VERSION 5.8 ;
BUSBITCHARS "[]" ;
DIVIDERCHAR "/" ;
UNITS
    DATABASE MICRONS 1000 ;
END UNITS

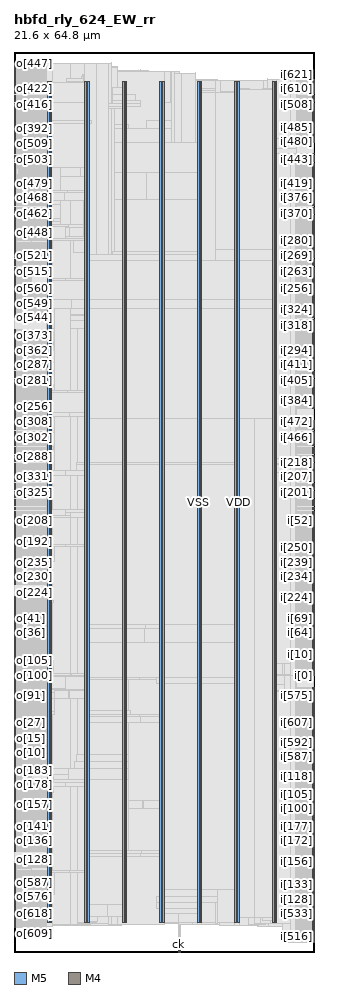
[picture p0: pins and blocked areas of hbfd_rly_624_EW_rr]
MACRO hbfd_rly_624_EW_rr
  FOREIGN hbfd_rly_624_EW_rr 0 0 ;
  CLASS BLOCK ;
  SIZE 21.6 BY 64.8 ;
  PIN ck
    DIRECTION INPUT ;
    USE SIGNAL ;
    PORT
      LAYER M5 ;
        RECT  11.856 0 11.88 0.084 ;
    END
  END ck
  PIN i[0]
    DIRECTION INPUT ;
    USE SIGNAL ;
    PORT
      LAYER M4 ;
        RECT  21.516 19.92 21.6 19.944 ;
    END
  END i[0]
  PIN i[100]
    DIRECTION INPUT ;
    USE SIGNAL ;
    PORT
      LAYER M4 ;
        RECT  21.516 10.32 21.6 10.344 ;
    END
  END i[100]
  PIN i[101]
    DIRECTION INPUT ;
    USE SIGNAL ;
    PORT
      LAYER M4 ;
        RECT  21.516 10.416 21.6 10.44 ;
    END
  END i[101]
  PIN i[102]
    DIRECTION INPUT ;
    USE SIGNAL ;
    PORT
      LAYER M4 ;
        RECT  21.516 10.512 21.6 10.536 ;
    END
  END i[102]
  PIN i[103]
    DIRECTION INPUT ;
    USE SIGNAL ;
    PORT
      LAYER M4 ;
        RECT  21.516 10.608 21.6 10.632 ;
    END
  END i[103]
  PIN i[104]
    DIRECTION INPUT ;
    USE SIGNAL ;
    PORT
      LAYER M4 ;
        RECT  21.516 10.704 21.6 10.728 ;
    END
  END i[104]
  PIN i[105]
    DIRECTION INPUT ;
    USE SIGNAL ;
    PORT
      LAYER M4 ;
        RECT  21.516 10.8 21.6 10.824 ;
    END
  END i[105]
  PIN i[106]
    DIRECTION INPUT ;
    USE SIGNAL ;
    PORT
      LAYER M4 ;
        RECT  21.516 10.896 21.6 10.92 ;
    END
  END i[106]
  PIN i[107]
    DIRECTION INPUT ;
    USE SIGNAL ;
    PORT
      LAYER M4 ;
        RECT  21.516 10.992 21.6 11.016 ;
    END
  END i[107]
  PIN i[108]
    DIRECTION INPUT ;
    USE SIGNAL ;
    PORT
      LAYER M4 ;
        RECT  21.516 11.088 21.6 11.112 ;
    END
  END i[108]
  PIN i[109]
    DIRECTION INPUT ;
    USE SIGNAL ;
    PORT
      LAYER M4 ;
        RECT  21.516 11.184 21.6 11.208 ;
    END
  END i[109]
  PIN i[10]
    DIRECTION INPUT ;
    USE SIGNAL ;
    PORT
      LAYER M4 ;
        RECT  21.516 20.88 21.6 20.904 ;
    END
  END i[10]
  PIN i[110]
    DIRECTION INPUT ;
    USE SIGNAL ;
    PORT
      LAYER M4 ;
        RECT  21.516 11.28 21.6 11.304 ;
    END
  END i[110]
  PIN i[111]
    DIRECTION INPUT ;
    USE SIGNAL ;
    PORT
      LAYER M4 ;
        RECT  21.516 11.376 21.6 11.4 ;
    END
  END i[111]
  PIN i[112]
    DIRECTION INPUT ;
    USE SIGNAL ;
    PORT
      LAYER M4 ;
        RECT  21.516 11.472 21.6 11.496 ;
    END
  END i[112]
  PIN i[113]
    DIRECTION INPUT ;
    USE SIGNAL ;
    PORT
      LAYER M4 ;
        RECT  21.516 11.568 21.6 11.592 ;
    END
  END i[113]
  PIN i[114]
    DIRECTION INPUT ;
    USE SIGNAL ;
    PORT
      LAYER M4 ;
        RECT  21.516 11.664 21.6 11.688 ;
    END
  END i[114]
  PIN i[115]
    DIRECTION INPUT ;
    USE SIGNAL ;
    PORT
      LAYER M4 ;
        RECT  21.516 11.76 21.6 11.784 ;
    END
  END i[115]
  PIN i[116]
    DIRECTION INPUT ;
    USE SIGNAL ;
    PORT
      LAYER M4 ;
        RECT  21.516 11.856 21.6 11.88 ;
    END
  END i[116]
  PIN i[117]
    DIRECTION INPUT ;
    USE SIGNAL ;
    PORT
      LAYER M4 ;
        RECT  21.516 11.952 21.6 11.976 ;
    END
  END i[117]
  PIN i[118]
    DIRECTION INPUT ;
    USE SIGNAL ;
    PORT
      LAYER M4 ;
        RECT  21.516 12.048 21.6 12.072 ;
    END
  END i[118]
  PIN i[119]
    DIRECTION INPUT ;
    USE SIGNAL ;
    PORT
      LAYER M4 ;
        RECT  21.516 12.144 21.6 12.168 ;
    END
  END i[119]
  PIN i[11]
    DIRECTION INPUT ;
    USE SIGNAL ;
    PORT
      LAYER M4 ;
        RECT  21.516 20.976 21.6 21 ;
    END
  END i[11]
  PIN i[120]
    DIRECTION INPUT ;
    USE SIGNAL ;
    PORT
      LAYER M4 ;
        RECT  21.516 12.24 21.6 12.264 ;
    END
  END i[120]
  PIN i[121]
    DIRECTION INPUT ;
    USE SIGNAL ;
    PORT
      LAYER M4 ;
        RECT  21.516 12.336 21.6 12.36 ;
    END
  END i[121]
  PIN i[122]
    DIRECTION INPUT ;
    USE SIGNAL ;
    PORT
      LAYER M4 ;
        RECT  21.516 12.432 21.6 12.456 ;
    END
  END i[122]
  PIN i[123]
    DIRECTION INPUT ;
    USE SIGNAL ;
    PORT
      LAYER M4 ;
        RECT  21.516 12.528 21.6 12.552 ;
    END
  END i[123]
  PIN i[124]
    DIRECTION INPUT ;
    USE SIGNAL ;
    PORT
      LAYER M4 ;
        RECT  21.516 12.624 21.6 12.648 ;
    END
  END i[124]
  PIN i[125]
    DIRECTION INPUT ;
    USE SIGNAL ;
    PORT
      LAYER M4 ;
        RECT  21.516 12.72 21.6 12.744 ;
    END
  END i[125]
  PIN i[126]
    DIRECTION INPUT ;
    USE SIGNAL ;
    PORT
      LAYER M4 ;
        RECT  21.516 12.816 21.6 12.84 ;
    END
  END i[126]
  PIN i[127]
    DIRECTION INPUT ;
    USE SIGNAL ;
    PORT
      LAYER M4 ;
        RECT  21.516 12.912 21.6 12.936 ;
    END
  END i[127]
  PIN i[128]
    DIRECTION INPUT ;
    USE SIGNAL ;
    PORT
      LAYER M4 ;
        RECT  21.516 3.792 21.6 3.816 ;
    END
  END i[128]
  PIN i[129]
    DIRECTION INPUT ;
    USE SIGNAL ;
    PORT
      LAYER M4 ;
        RECT  21.516 3.888 21.6 3.912 ;
    END
  END i[129]
  PIN i[12]
    DIRECTION INPUT ;
    USE SIGNAL ;
    PORT
      LAYER M4 ;
        RECT  21.516 21.072 21.6 21.096 ;
    END
  END i[12]
  PIN i[130]
    DIRECTION INPUT ;
    USE SIGNAL ;
    PORT
      LAYER M4 ;
        RECT  21.516 3.984 21.6 4.008 ;
    END
  END i[130]
  PIN i[131]
    DIRECTION INPUT ;
    USE SIGNAL ;
    PORT
      LAYER M4 ;
        RECT  21.516 4.08 21.6 4.104 ;
    END
  END i[131]
  PIN i[132]
    DIRECTION INPUT ;
    USE SIGNAL ;
    PORT
      LAYER M4 ;
        RECT  21.516 4.176 21.6 4.2 ;
    END
  END i[132]
  PIN i[133]
    DIRECTION INPUT ;
    USE SIGNAL ;
    PORT
      LAYER M4 ;
        RECT  21.516 4.272 21.6 4.296 ;
    END
  END i[133]
  PIN i[134]
    DIRECTION INPUT ;
    USE SIGNAL ;
    PORT
      LAYER M4 ;
        RECT  21.516 4.368 21.6 4.392 ;
    END
  END i[134]
  PIN i[135]
    DIRECTION INPUT ;
    USE SIGNAL ;
    PORT
      LAYER M4 ;
        RECT  21.516 4.464 21.6 4.488 ;
    END
  END i[135]
  PIN i[136]
    DIRECTION INPUT ;
    USE SIGNAL ;
    PORT
      LAYER M4 ;
        RECT  21.516 4.56 21.6 4.584 ;
    END
  END i[136]
  PIN i[137]
    DIRECTION INPUT ;
    USE SIGNAL ;
    PORT
      LAYER M4 ;
        RECT  21.516 4.656 21.6 4.68 ;
    END
  END i[137]
  PIN i[138]
    DIRECTION INPUT ;
    USE SIGNAL ;
    PORT
      LAYER M4 ;
        RECT  21.516 4.752 21.6 4.776 ;
    END
  END i[138]
  PIN i[139]
    DIRECTION INPUT ;
    USE SIGNAL ;
    PORT
      LAYER M4 ;
        RECT  21.516 4.848 21.6 4.872 ;
    END
  END i[139]
  PIN i[13]
    DIRECTION INPUT ;
    USE SIGNAL ;
    PORT
      LAYER M4 ;
        RECT  21.516 21.168 21.6 21.192 ;
    END
  END i[13]
  PIN i[140]
    DIRECTION INPUT ;
    USE SIGNAL ;
    PORT
      LAYER M4 ;
        RECT  21.516 4.944 21.6 4.968 ;
    END
  END i[140]
  PIN i[141]
    DIRECTION INPUT ;
    USE SIGNAL ;
    PORT
      LAYER M4 ;
        RECT  21.516 5.04 21.6 5.064 ;
    END
  END i[141]
  PIN i[142]
    DIRECTION INPUT ;
    USE SIGNAL ;
    PORT
      LAYER M4 ;
        RECT  21.516 5.136 21.6 5.16 ;
    END
  END i[142]
  PIN i[143]
    DIRECTION INPUT ;
    USE SIGNAL ;
    PORT
      LAYER M4 ;
        RECT  21.516 5.232 21.6 5.256 ;
    END
  END i[143]
  PIN i[144]
    DIRECTION INPUT ;
    USE SIGNAL ;
    PORT
      LAYER M4 ;
        RECT  21.516 5.328 21.6 5.352 ;
    END
  END i[144]
  PIN i[145]
    DIRECTION INPUT ;
    USE SIGNAL ;
    PORT
      LAYER M4 ;
        RECT  21.516 5.424 21.6 5.448 ;
    END
  END i[145]
  PIN i[146]
    DIRECTION INPUT ;
    USE SIGNAL ;
    PORT
      LAYER M4 ;
        RECT  21.516 5.52 21.6 5.544 ;
    END
  END i[146]
  PIN i[147]
    DIRECTION INPUT ;
    USE SIGNAL ;
    PORT
      LAYER M4 ;
        RECT  21.516 5.616 21.6 5.64 ;
    END
  END i[147]
  PIN i[148]
    DIRECTION INPUT ;
    USE SIGNAL ;
    PORT
      LAYER M4 ;
        RECT  21.516 5.712 21.6 5.736 ;
    END
  END i[148]
  PIN i[149]
    DIRECTION INPUT ;
    USE SIGNAL ;
    PORT
      LAYER M4 ;
        RECT  21.516 5.808 21.6 5.832 ;
    END
  END i[149]
  PIN i[14]
    DIRECTION INPUT ;
    USE SIGNAL ;
    PORT
      LAYER M4 ;
        RECT  21.516 21.264 21.6 21.288 ;
    END
  END i[14]
  PIN i[150]
    DIRECTION INPUT ;
    USE SIGNAL ;
    PORT
      LAYER M4 ;
        RECT  21.516 5.904 21.6 5.928 ;
    END
  END i[150]
  PIN i[151]
    DIRECTION INPUT ;
    USE SIGNAL ;
    PORT
      LAYER M4 ;
        RECT  21.516 6 21.6 6.024 ;
    END
  END i[151]
  PIN i[152]
    DIRECTION INPUT ;
    USE SIGNAL ;
    PORT
      LAYER M4 ;
        RECT  21.516 6.096 21.6 6.12 ;
    END
  END i[152]
  PIN i[153]
    DIRECTION INPUT ;
    USE SIGNAL ;
    PORT
      LAYER M4 ;
        RECT  21.516 6.192 21.6 6.216 ;
    END
  END i[153]
  PIN i[154]
    DIRECTION INPUT ;
    USE SIGNAL ;
    PORT
      LAYER M4 ;
        RECT  21.516 6.288 21.6 6.312 ;
    END
  END i[154]
  PIN i[155]
    DIRECTION INPUT ;
    USE SIGNAL ;
    PORT
      LAYER M4 ;
        RECT  21.516 6.384 21.6 6.408 ;
    END
  END i[155]
  PIN i[156]
    DIRECTION INPUT ;
    USE SIGNAL ;
    PORT
      LAYER M4 ;
        RECT  21.516 6.48 21.6 6.504 ;
    END
  END i[156]
  PIN i[157]
    DIRECTION INPUT ;
    USE SIGNAL ;
    PORT
      LAYER M4 ;
        RECT  21.516 6.576 21.6 6.6 ;
    END
  END i[157]
  PIN i[158]
    DIRECTION INPUT ;
    USE SIGNAL ;
    PORT
      LAYER M4 ;
        RECT  21.516 6.672 21.6 6.696 ;
    END
  END i[158]
  PIN i[159]
    DIRECTION INPUT ;
    USE SIGNAL ;
    PORT
      LAYER M4 ;
        RECT  21.516 6.768 21.6 6.792 ;
    END
  END i[159]
  PIN i[15]
    DIRECTION INPUT ;
    USE SIGNAL ;
    PORT
      LAYER M4 ;
        RECT  21.516 21.36 21.6 21.384 ;
    END
  END i[15]
  PIN i[160]
    DIRECTION INPUT ;
    USE SIGNAL ;
    PORT
      LAYER M4 ;
        RECT  21.516 6.864 21.6 6.888 ;
    END
  END i[160]
  PIN i[161]
    DIRECTION INPUT ;
    USE SIGNAL ;
    PORT
      LAYER M4 ;
        RECT  21.516 6.96 21.6 6.984 ;
    END
  END i[161]
  PIN i[162]
    DIRECTION INPUT ;
    USE SIGNAL ;
    PORT
      LAYER M4 ;
        RECT  21.516 7.056 21.6 7.08 ;
    END
  END i[162]
  PIN i[163]
    DIRECTION INPUT ;
    USE SIGNAL ;
    PORT
      LAYER M4 ;
        RECT  21.516 7.152 21.6 7.176 ;
    END
  END i[163]
  PIN i[164]
    DIRECTION INPUT ;
    USE SIGNAL ;
    PORT
      LAYER M4 ;
        RECT  21.516 7.248 21.6 7.272 ;
    END
  END i[164]
  PIN i[165]
    DIRECTION INPUT ;
    USE SIGNAL ;
    PORT
      LAYER M4 ;
        RECT  21.516 7.344 21.6 7.368 ;
    END
  END i[165]
  PIN i[166]
    DIRECTION INPUT ;
    USE SIGNAL ;
    PORT
      LAYER M4 ;
        RECT  21.516 7.44 21.6 7.464 ;
    END
  END i[166]
  PIN i[167]
    DIRECTION INPUT ;
    USE SIGNAL ;
    PORT
      LAYER M4 ;
        RECT  21.516 7.536 21.6 7.56 ;
    END
  END i[167]
  PIN i[168]
    DIRECTION INPUT ;
    USE SIGNAL ;
    PORT
      LAYER M4 ;
        RECT  21.516 7.632 21.6 7.656 ;
    END
  END i[168]
  PIN i[169]
    DIRECTION INPUT ;
    USE SIGNAL ;
    PORT
      LAYER M4 ;
        RECT  21.516 7.728 21.6 7.752 ;
    END
  END i[169]
  PIN i[16]
    DIRECTION INPUT ;
    USE SIGNAL ;
    PORT
      LAYER M4 ;
        RECT  21.516 21.456 21.6 21.48 ;
    END
  END i[16]
  PIN i[170]
    DIRECTION INPUT ;
    USE SIGNAL ;
    PORT
      LAYER M4 ;
        RECT  21.516 7.824 21.6 7.848 ;
    END
  END i[170]
  PIN i[171]
    DIRECTION INPUT ;
    USE SIGNAL ;
    PORT
      LAYER M4 ;
        RECT  21.516 7.92 21.6 7.944 ;
    END
  END i[171]
  PIN i[172]
    DIRECTION INPUT ;
    USE SIGNAL ;
    PORT
      LAYER M4 ;
        RECT  21.516 8.016 21.6 8.04 ;
    END
  END i[172]
  PIN i[173]
    DIRECTION INPUT ;
    USE SIGNAL ;
    PORT
      LAYER M4 ;
        RECT  21.516 8.112 21.6 8.136 ;
    END
  END i[173]
  PIN i[174]
    DIRECTION INPUT ;
    USE SIGNAL ;
    PORT
      LAYER M4 ;
        RECT  21.516 8.208 21.6 8.232 ;
    END
  END i[174]
  PIN i[175]
    DIRECTION INPUT ;
    USE SIGNAL ;
    PORT
      LAYER M4 ;
        RECT  21.516 8.304 21.6 8.328 ;
    END
  END i[175]
  PIN i[176]
    DIRECTION INPUT ;
    USE SIGNAL ;
    PORT
      LAYER M4 ;
        RECT  21.516 8.4 21.6 8.424 ;
    END
  END i[176]
  PIN i[177]
    DIRECTION INPUT ;
    USE SIGNAL ;
    PORT
      LAYER M4 ;
        RECT  21.516 8.496 21.6 8.52 ;
    END
  END i[177]
  PIN i[178]
    DIRECTION INPUT ;
    USE SIGNAL ;
    PORT
      LAYER M4 ;
        RECT  21.516 8.592 21.6 8.616 ;
    END
  END i[178]
  PIN i[179]
    DIRECTION INPUT ;
    USE SIGNAL ;
    PORT
      LAYER M4 ;
        RECT  21.516 8.688 21.6 8.712 ;
    END
  END i[179]
  PIN i[17]
    DIRECTION INPUT ;
    USE SIGNAL ;
    PORT
      LAYER M4 ;
        RECT  21.516 21.552 21.6 21.576 ;
    END
  END i[17]
  PIN i[180]
    DIRECTION INPUT ;
    USE SIGNAL ;
    PORT
      LAYER M4 ;
        RECT  21.516 8.784 21.6 8.808 ;
    END
  END i[180]
  PIN i[181]
    DIRECTION INPUT ;
    USE SIGNAL ;
    PORT
      LAYER M4 ;
        RECT  21.516 8.88 21.6 8.904 ;
    END
  END i[181]
  PIN i[182]
    DIRECTION INPUT ;
    USE SIGNAL ;
    PORT
      LAYER M4 ;
        RECT  21.516 8.976 21.6 9 ;
    END
  END i[182]
  PIN i[183]
    DIRECTION INPUT ;
    USE SIGNAL ;
    PORT
      LAYER M4 ;
        RECT  21.516 9.072 21.6 9.096 ;
    END
  END i[183]
  PIN i[184]
    DIRECTION INPUT ;
    USE SIGNAL ;
    PORT
      LAYER M4 ;
        RECT  21.516 9.168 21.6 9.192 ;
    END
  END i[184]
  PIN i[185]
    DIRECTION INPUT ;
    USE SIGNAL ;
    PORT
      LAYER M4 ;
        RECT  21.516 9.264 21.6 9.288 ;
    END
  END i[185]
  PIN i[186]
    DIRECTION INPUT ;
    USE SIGNAL ;
    PORT
      LAYER M4 ;
        RECT  21.516 9.36 21.6 9.384 ;
    END
  END i[186]
  PIN i[187]
    DIRECTION INPUT ;
    USE SIGNAL ;
    PORT
      LAYER M4 ;
        RECT  21.516 9.456 21.6 9.48 ;
    END
  END i[187]
  PIN i[188]
    DIRECTION INPUT ;
    USE SIGNAL ;
    PORT
      LAYER M4 ;
        RECT  21.516 9.552 21.6 9.576 ;
    END
  END i[188]
  PIN i[189]
    DIRECTION INPUT ;
    USE SIGNAL ;
    PORT
      LAYER M4 ;
        RECT  21.516 9.648 21.6 9.672 ;
    END
  END i[189]
  PIN i[18]
    DIRECTION INPUT ;
    USE SIGNAL ;
    PORT
      LAYER M4 ;
        RECT  21.516 21.648 21.6 21.672 ;
    END
  END i[18]
  PIN i[190]
    DIRECTION INPUT ;
    USE SIGNAL ;
    PORT
      LAYER M4 ;
        RECT  21.516 9.744 21.6 9.768 ;
    END
  END i[190]
  PIN i[191]
    DIRECTION INPUT ;
    USE SIGNAL ;
    PORT
      LAYER M4 ;
        RECT  21.516 9.84 21.6 9.864 ;
    END
  END i[191]
  PIN i[192]
    DIRECTION INPUT ;
    USE SIGNAL ;
    PORT
      LAYER M4 ;
        RECT  21.516 32.208 21.6 32.232 ;
    END
  END i[192]
  PIN i[193]
    DIRECTION INPUT ;
    USE SIGNAL ;
    PORT
      LAYER M4 ;
        RECT  21.516 32.304 21.6 32.328 ;
    END
  END i[193]
  PIN i[194]
    DIRECTION INPUT ;
    USE SIGNAL ;
    PORT
      LAYER M4 ;
        RECT  21.516 32.4 21.6 32.424 ;
    END
  END i[194]
  PIN i[195]
    DIRECTION INPUT ;
    USE SIGNAL ;
    PORT
      LAYER M4 ;
        RECT  21.516 32.496 21.6 32.52 ;
    END
  END i[195]
  PIN i[196]
    DIRECTION INPUT ;
    USE SIGNAL ;
    PORT
      LAYER M4 ;
        RECT  21.516 32.592 21.6 32.616 ;
    END
  END i[196]
  PIN i[197]
    DIRECTION INPUT ;
    USE SIGNAL ;
    PORT
      LAYER M4 ;
        RECT  21.516 32.688 21.6 32.712 ;
    END
  END i[197]
  PIN i[198]
    DIRECTION INPUT ;
    USE SIGNAL ;
    PORT
      LAYER M4 ;
        RECT  21.516 32.784 21.6 32.808 ;
    END
  END i[198]
  PIN i[199]
    DIRECTION INPUT ;
    USE SIGNAL ;
    PORT
      LAYER M4 ;
        RECT  21.516 32.88 21.6 32.904 ;
    END
  END i[199]
  PIN i[19]
    DIRECTION INPUT ;
    USE SIGNAL ;
    PORT
      LAYER M4 ;
        RECT  21.516 21.744 21.6 21.768 ;
    END
  END i[19]
  PIN i[1]
    DIRECTION INPUT ;
    USE SIGNAL ;
    PORT
      LAYER M4 ;
        RECT  21.516 20.016 21.6 20.04 ;
    END
  END i[1]
  PIN i[200]
    DIRECTION INPUT ;
    USE SIGNAL ;
    PORT
      LAYER M4 ;
        RECT  21.516 32.976 21.6 33 ;
    END
  END i[200]
  PIN i[201]
    DIRECTION INPUT ;
    USE SIGNAL ;
    PORT
      LAYER M4 ;
        RECT  21.516 33.072 21.6 33.096 ;
    END
  END i[201]
  PIN i[202]
    DIRECTION INPUT ;
    USE SIGNAL ;
    PORT
      LAYER M4 ;
        RECT  21.516 33.168 21.6 33.192 ;
    END
  END i[202]
  PIN i[203]
    DIRECTION INPUT ;
    USE SIGNAL ;
    PORT
      LAYER M4 ;
        RECT  21.516 33.264 21.6 33.288 ;
    END
  END i[203]
  PIN i[204]
    DIRECTION INPUT ;
    USE SIGNAL ;
    PORT
      LAYER M4 ;
        RECT  21.516 33.36 21.6 33.384 ;
    END
  END i[204]
  PIN i[205]
    DIRECTION INPUT ;
    USE SIGNAL ;
    PORT
      LAYER M4 ;
        RECT  21.516 33.456 21.6 33.48 ;
    END
  END i[205]
  PIN i[206]
    DIRECTION INPUT ;
    USE SIGNAL ;
    PORT
      LAYER M4 ;
        RECT  21.516 33.552 21.6 33.576 ;
    END
  END i[206]
  PIN i[207]
    DIRECTION INPUT ;
    USE SIGNAL ;
    PORT
      LAYER M4 ;
        RECT  21.516 33.648 21.6 33.672 ;
    END
  END i[207]
  PIN i[208]
    DIRECTION INPUT ;
    USE SIGNAL ;
    PORT
      LAYER M4 ;
        RECT  21.516 33.744 21.6 33.768 ;
    END
  END i[208]
  PIN i[209]
    DIRECTION INPUT ;
    USE SIGNAL ;
    PORT
      LAYER M4 ;
        RECT  21.516 33.84 21.6 33.864 ;
    END
  END i[209]
  PIN i[20]
    DIRECTION INPUT ;
    USE SIGNAL ;
    PORT
      LAYER M4 ;
        RECT  21.516 21.84 21.6 21.864 ;
    END
  END i[20]
  PIN i[210]
    DIRECTION INPUT ;
    USE SIGNAL ;
    PORT
      LAYER M4 ;
        RECT  21.516 33.936 21.6 33.96 ;
    END
  END i[210]
  PIN i[211]
    DIRECTION INPUT ;
    USE SIGNAL ;
    PORT
      LAYER M4 ;
        RECT  21.516 34.032 21.6 34.056 ;
    END
  END i[211]
  PIN i[212]
    DIRECTION INPUT ;
    USE SIGNAL ;
    PORT
      LAYER M4 ;
        RECT  21.516 34.128 21.6 34.152 ;
    END
  END i[212]
  PIN i[213]
    DIRECTION INPUT ;
    USE SIGNAL ;
    PORT
      LAYER M4 ;
        RECT  21.516 34.224 21.6 34.248 ;
    END
  END i[213]
  PIN i[214]
    DIRECTION INPUT ;
    USE SIGNAL ;
    PORT
      LAYER M4 ;
        RECT  21.516 34.32 21.6 34.344 ;
    END
  END i[214]
  PIN i[215]
    DIRECTION INPUT ;
    USE SIGNAL ;
    PORT
      LAYER M4 ;
        RECT  21.516 34.416 21.6 34.44 ;
    END
  END i[215]
  PIN i[216]
    DIRECTION INPUT ;
    USE SIGNAL ;
    PORT
      LAYER M4 ;
        RECT  21.516 34.512 21.6 34.536 ;
    END
  END i[216]
  PIN i[217]
    DIRECTION INPUT ;
    USE SIGNAL ;
    PORT
      LAYER M4 ;
        RECT  21.516 34.608 21.6 34.632 ;
    END
  END i[217]
  PIN i[218]
    DIRECTION INPUT ;
    USE SIGNAL ;
    PORT
      LAYER M4 ;
        RECT  21.516 34.704 21.6 34.728 ;
    END
  END i[218]
  PIN i[219]
    DIRECTION INPUT ;
    USE SIGNAL ;
    PORT
      LAYER M4 ;
        RECT  21.516 34.8 21.6 34.824 ;
    END
  END i[219]
  PIN i[21]
    DIRECTION INPUT ;
    USE SIGNAL ;
    PORT
      LAYER M4 ;
        RECT  21.516 21.936 21.6 21.96 ;
    END
  END i[21]
  PIN i[220]
    DIRECTION INPUT ;
    USE SIGNAL ;
    PORT
      LAYER M4 ;
        RECT  21.516 34.896 21.6 34.92 ;
    END
  END i[220]
  PIN i[221]
    DIRECTION INPUT ;
    USE SIGNAL ;
    PORT
      LAYER M4 ;
        RECT  21.516 34.992 21.6 35.016 ;
    END
  END i[221]
  PIN i[222]
    DIRECTION INPUT ;
    USE SIGNAL ;
    PORT
      LAYER M4 ;
        RECT  21.516 35.088 21.6 35.112 ;
    END
  END i[222]
  PIN i[223]
    DIRECTION INPUT ;
    USE SIGNAL ;
    PORT
      LAYER M4 ;
        RECT  21.516 35.184 21.6 35.208 ;
    END
  END i[223]
  PIN i[224]
    DIRECTION INPUT ;
    USE SIGNAL ;
    PORT
      LAYER M4 ;
        RECT  21.516 26.064 21.6 26.088 ;
    END
  END i[224]
  PIN i[225]
    DIRECTION INPUT ;
    USE SIGNAL ;
    PORT
      LAYER M4 ;
        RECT  21.516 26.16 21.6 26.184 ;
    END
  END i[225]
  PIN i[226]
    DIRECTION INPUT ;
    USE SIGNAL ;
    PORT
      LAYER M4 ;
        RECT  21.516 26.256 21.6 26.28 ;
    END
  END i[226]
  PIN i[227]
    DIRECTION INPUT ;
    USE SIGNAL ;
    PORT
      LAYER M4 ;
        RECT  21.516 26.352 21.6 26.376 ;
    END
  END i[227]
  PIN i[228]
    DIRECTION INPUT ;
    USE SIGNAL ;
    PORT
      LAYER M4 ;
        RECT  21.516 26.448 21.6 26.472 ;
    END
  END i[228]
  PIN i[229]
    DIRECTION INPUT ;
    USE SIGNAL ;
    PORT
      LAYER M4 ;
        RECT  21.516 26.544 21.6 26.568 ;
    END
  END i[229]
  PIN i[22]
    DIRECTION INPUT ;
    USE SIGNAL ;
    PORT
      LAYER M4 ;
        RECT  21.516 22.032 21.6 22.056 ;
    END
  END i[22]
  PIN i[230]
    DIRECTION INPUT ;
    USE SIGNAL ;
    PORT
      LAYER M4 ;
        RECT  21.516 26.64 21.6 26.664 ;
    END
  END i[230]
  PIN i[231]
    DIRECTION INPUT ;
    USE SIGNAL ;
    PORT
      LAYER M4 ;
        RECT  21.516 26.736 21.6 26.76 ;
    END
  END i[231]
  PIN i[232]
    DIRECTION INPUT ;
    USE SIGNAL ;
    PORT
      LAYER M4 ;
        RECT  21.516 26.832 21.6 26.856 ;
    END
  END i[232]
  PIN i[233]
    DIRECTION INPUT ;
    USE SIGNAL ;
    PORT
      LAYER M4 ;
        RECT  21.516 26.928 21.6 26.952 ;
    END
  END i[233]
  PIN i[234]
    DIRECTION INPUT ;
    USE SIGNAL ;
    PORT
      LAYER M4 ;
        RECT  21.516 27.024 21.6 27.048 ;
    END
  END i[234]
  PIN i[235]
    DIRECTION INPUT ;
    USE SIGNAL ;
    PORT
      LAYER M4 ;
        RECT  21.516 27.12 21.6 27.144 ;
    END
  END i[235]
  PIN i[236]
    DIRECTION INPUT ;
    USE SIGNAL ;
    PORT
      LAYER M4 ;
        RECT  21.516 27.216 21.6 27.24 ;
    END
  END i[236]
  PIN i[237]
    DIRECTION INPUT ;
    USE SIGNAL ;
    PORT
      LAYER M4 ;
        RECT  21.516 27.312 21.6 27.336 ;
    END
  END i[237]
  PIN i[238]
    DIRECTION INPUT ;
    USE SIGNAL ;
    PORT
      LAYER M4 ;
        RECT  21.516 27.408 21.6 27.432 ;
    END
  END i[238]
  PIN i[239]
    DIRECTION INPUT ;
    USE SIGNAL ;
    PORT
      LAYER M4 ;
        RECT  21.516 27.504 21.6 27.528 ;
    END
  END i[239]
  PIN i[23]
    DIRECTION INPUT ;
    USE SIGNAL ;
    PORT
      LAYER M4 ;
        RECT  21.516 22.128 21.6 22.152 ;
    END
  END i[23]
  PIN i[240]
    DIRECTION INPUT ;
    USE SIGNAL ;
    PORT
      LAYER M4 ;
        RECT  21.516 27.6 21.6 27.624 ;
    END
  END i[240]
  PIN i[241]
    DIRECTION INPUT ;
    USE SIGNAL ;
    PORT
      LAYER M4 ;
        RECT  21.516 27.696 21.6 27.72 ;
    END
  END i[241]
  PIN i[242]
    DIRECTION INPUT ;
    USE SIGNAL ;
    PORT
      LAYER M4 ;
        RECT  21.516 27.792 21.6 27.816 ;
    END
  END i[242]
  PIN i[243]
    DIRECTION INPUT ;
    USE SIGNAL ;
    PORT
      LAYER M4 ;
        RECT  21.516 27.888 21.6 27.912 ;
    END
  END i[243]
  PIN i[244]
    DIRECTION INPUT ;
    USE SIGNAL ;
    PORT
      LAYER M4 ;
        RECT  21.516 27.984 21.6 28.008 ;
    END
  END i[244]
  PIN i[245]
    DIRECTION INPUT ;
    USE SIGNAL ;
    PORT
      LAYER M4 ;
        RECT  21.516 28.08 21.6 28.104 ;
    END
  END i[245]
  PIN i[246]
    DIRECTION INPUT ;
    USE SIGNAL ;
    PORT
      LAYER M4 ;
        RECT  21.516 28.176 21.6 28.2 ;
    END
  END i[246]
  PIN i[247]
    DIRECTION INPUT ;
    USE SIGNAL ;
    PORT
      LAYER M4 ;
        RECT  21.516 28.272 21.6 28.296 ;
    END
  END i[247]
  PIN i[248]
    DIRECTION INPUT ;
    USE SIGNAL ;
    PORT
      LAYER M4 ;
        RECT  21.516 28.368 21.6 28.392 ;
    END
  END i[248]
  PIN i[249]
    DIRECTION INPUT ;
    USE SIGNAL ;
    PORT
      LAYER M4 ;
        RECT  21.516 28.464 21.6 28.488 ;
    END
  END i[249]
  PIN i[24]
    DIRECTION INPUT ;
    USE SIGNAL ;
    PORT
      LAYER M4 ;
        RECT  21.516 22.224 21.6 22.248 ;
    END
  END i[24]
  PIN i[250]
    DIRECTION INPUT ;
    USE SIGNAL ;
    PORT
      LAYER M4 ;
        RECT  21.516 28.56 21.6 28.584 ;
    END
  END i[250]
  PIN i[251]
    DIRECTION INPUT ;
    USE SIGNAL ;
    PORT
      LAYER M4 ;
        RECT  21.516 28.656 21.6 28.68 ;
    END
  END i[251]
  PIN i[252]
    DIRECTION INPUT ;
    USE SIGNAL ;
    PORT
      LAYER M4 ;
        RECT  21.516 28.752 21.6 28.776 ;
    END
  END i[252]
  PIN i[253]
    DIRECTION INPUT ;
    USE SIGNAL ;
    PORT
      LAYER M4 ;
        RECT  21.516 28.848 21.6 28.872 ;
    END
  END i[253]
  PIN i[254]
    DIRECTION INPUT ;
    USE SIGNAL ;
    PORT
      LAYER M4 ;
        RECT  21.516 28.944 21.6 28.968 ;
    END
  END i[254]
  PIN i[255]
    DIRECTION INPUT ;
    USE SIGNAL ;
    PORT
      LAYER M4 ;
        RECT  21.516 29.04 21.6 29.064 ;
    END
  END i[255]
  PIN i[256]
    DIRECTION INPUT ;
    USE SIGNAL ;
    PORT
      LAYER M4 ;
        RECT  21.516 48.336 21.6 48.36 ;
    END
  END i[256]
  PIN i[257]
    DIRECTION INPUT ;
    USE SIGNAL ;
    PORT
      LAYER M4 ;
        RECT  21.516 48.432 21.6 48.456 ;
    END
  END i[257]
  PIN i[258]
    DIRECTION INPUT ;
    USE SIGNAL ;
    PORT
      LAYER M4 ;
        RECT  21.516 48.528 21.6 48.552 ;
    END
  END i[258]
  PIN i[259]
    DIRECTION INPUT ;
    USE SIGNAL ;
    PORT
      LAYER M4 ;
        RECT  21.516 48.624 21.6 48.648 ;
    END
  END i[259]
  PIN i[25]
    DIRECTION INPUT ;
    USE SIGNAL ;
    PORT
      LAYER M4 ;
        RECT  21.516 22.32 21.6 22.344 ;
    END
  END i[25]
  PIN i[260]
    DIRECTION INPUT ;
    USE SIGNAL ;
    PORT
      LAYER M4 ;
        RECT  21.516 48.72 21.6 48.744 ;
    END
  END i[260]
  PIN i[261]
    DIRECTION INPUT ;
    USE SIGNAL ;
    PORT
      LAYER M4 ;
        RECT  21.516 48.816 21.6 48.84 ;
    END
  END i[261]
  PIN i[262]
    DIRECTION INPUT ;
    USE SIGNAL ;
    PORT
      LAYER M4 ;
        RECT  21.516 48.912 21.6 48.936 ;
    END
  END i[262]
  PIN i[263]
    DIRECTION INPUT ;
    USE SIGNAL ;
    PORT
      LAYER M4 ;
        RECT  21.516 49.008 21.6 49.032 ;
    END
  END i[263]
  PIN i[264]
    DIRECTION INPUT ;
    USE SIGNAL ;
    PORT
      LAYER M4 ;
        RECT  21.516 49.104 21.6 49.128 ;
    END
  END i[264]
  PIN i[265]
    DIRECTION INPUT ;
    USE SIGNAL ;
    PORT
      LAYER M4 ;
        RECT  21.516 49.2 21.6 49.224 ;
    END
  END i[265]
  PIN i[266]
    DIRECTION INPUT ;
    USE SIGNAL ;
    PORT
      LAYER M4 ;
        RECT  21.516 49.296 21.6 49.32 ;
    END
  END i[266]
  PIN i[267]
    DIRECTION INPUT ;
    USE SIGNAL ;
    PORT
      LAYER M4 ;
        RECT  21.516 49.392 21.6 49.416 ;
    END
  END i[267]
  PIN i[268]
    DIRECTION INPUT ;
    USE SIGNAL ;
    PORT
      LAYER M4 ;
        RECT  21.516 49.488 21.6 49.512 ;
    END
  END i[268]
  PIN i[269]
    DIRECTION INPUT ;
    USE SIGNAL ;
    PORT
      LAYER M4 ;
        RECT  21.516 49.584 21.6 49.608 ;
    END
  END i[269]
  PIN i[26]
    DIRECTION INPUT ;
    USE SIGNAL ;
    PORT
      LAYER M4 ;
        RECT  21.516 22.416 21.6 22.44 ;
    END
  END i[26]
  PIN i[270]
    DIRECTION INPUT ;
    USE SIGNAL ;
    PORT
      LAYER M4 ;
        RECT  21.516 49.68 21.6 49.704 ;
    END
  END i[270]
  PIN i[271]
    DIRECTION INPUT ;
    USE SIGNAL ;
    PORT
      LAYER M4 ;
        RECT  21.516 49.776 21.6 49.8 ;
    END
  END i[271]
  PIN i[272]
    DIRECTION INPUT ;
    USE SIGNAL ;
    PORT
      LAYER M4 ;
        RECT  21.516 49.872 21.6 49.896 ;
    END
  END i[272]
  PIN i[273]
    DIRECTION INPUT ;
    USE SIGNAL ;
    PORT
      LAYER M4 ;
        RECT  21.516 49.968 21.6 49.992 ;
    END
  END i[273]
  PIN i[274]
    DIRECTION INPUT ;
    USE SIGNAL ;
    PORT
      LAYER M4 ;
        RECT  21.516 50.064 21.6 50.088 ;
    END
  END i[274]
  PIN i[275]
    DIRECTION INPUT ;
    USE SIGNAL ;
    PORT
      LAYER M4 ;
        RECT  21.516 50.16 21.6 50.184 ;
    END
  END i[275]
  PIN i[276]
    DIRECTION INPUT ;
    USE SIGNAL ;
    PORT
      LAYER M4 ;
        RECT  21.516 50.256 21.6 50.28 ;
    END
  END i[276]
  PIN i[277]
    DIRECTION INPUT ;
    USE SIGNAL ;
    PORT
      LAYER M4 ;
        RECT  21.516 50.352 21.6 50.376 ;
    END
  END i[277]
  PIN i[278]
    DIRECTION INPUT ;
    USE SIGNAL ;
    PORT
      LAYER M4 ;
        RECT  21.516 50.448 21.6 50.472 ;
    END
  END i[278]
  PIN i[279]
    DIRECTION INPUT ;
    USE SIGNAL ;
    PORT
      LAYER M4 ;
        RECT  21.516 50.544 21.6 50.568 ;
    END
  END i[279]
  PIN i[27]
    DIRECTION INPUT ;
    USE SIGNAL ;
    PORT
      LAYER M4 ;
        RECT  21.516 22.512 21.6 22.536 ;
    END
  END i[27]
  PIN i[280]
    DIRECTION INPUT ;
    USE SIGNAL ;
    PORT
      LAYER M4 ;
        RECT  21.516 50.64 21.6 50.664 ;
    END
  END i[280]
  PIN i[281]
    DIRECTION INPUT ;
    USE SIGNAL ;
    PORT
      LAYER M4 ;
        RECT  21.516 50.736 21.6 50.76 ;
    END
  END i[281]
  PIN i[282]
    DIRECTION INPUT ;
    USE SIGNAL ;
    PORT
      LAYER M4 ;
        RECT  21.516 50.832 21.6 50.856 ;
    END
  END i[282]
  PIN i[283]
    DIRECTION INPUT ;
    USE SIGNAL ;
    PORT
      LAYER M4 ;
        RECT  21.516 50.928 21.6 50.952 ;
    END
  END i[283]
  PIN i[284]
    DIRECTION INPUT ;
    USE SIGNAL ;
    PORT
      LAYER M4 ;
        RECT  21.516 51.024 21.6 51.048 ;
    END
  END i[284]
  PIN i[285]
    DIRECTION INPUT ;
    USE SIGNAL ;
    PORT
      LAYER M4 ;
        RECT  21.516 51.12 21.6 51.144 ;
    END
  END i[285]
  PIN i[286]
    DIRECTION INPUT ;
    USE SIGNAL ;
    PORT
      LAYER M4 ;
        RECT  21.516 51.216 21.6 51.24 ;
    END
  END i[286]
  PIN i[287]
    DIRECTION INPUT ;
    USE SIGNAL ;
    PORT
      LAYER M4 ;
        RECT  21.516 51.312 21.6 51.336 ;
    END
  END i[287]
  PIN i[288]
    DIRECTION INPUT ;
    USE SIGNAL ;
    PORT
      LAYER M4 ;
        RECT  21.516 42.192 21.6 42.216 ;
    END
  END i[288]
  PIN i[289]
    DIRECTION INPUT ;
    USE SIGNAL ;
    PORT
      LAYER M4 ;
        RECT  21.516 42.288 21.6 42.312 ;
    END
  END i[289]
  PIN i[28]
    DIRECTION INPUT ;
    USE SIGNAL ;
    PORT
      LAYER M4 ;
        RECT  21.516 22.608 21.6 22.632 ;
    END
  END i[28]
  PIN i[290]
    DIRECTION INPUT ;
    USE SIGNAL ;
    PORT
      LAYER M4 ;
        RECT  21.516 42.384 21.6 42.408 ;
    END
  END i[290]
  PIN i[291]
    DIRECTION INPUT ;
    USE SIGNAL ;
    PORT
      LAYER M4 ;
        RECT  21.516 42.48 21.6 42.504 ;
    END
  END i[291]
  PIN i[292]
    DIRECTION INPUT ;
    USE SIGNAL ;
    PORT
      LAYER M4 ;
        RECT  21.516 42.576 21.6 42.6 ;
    END
  END i[292]
  PIN i[293]
    DIRECTION INPUT ;
    USE SIGNAL ;
    PORT
      LAYER M4 ;
        RECT  21.516 42.672 21.6 42.696 ;
    END
  END i[293]
  PIN i[294]
    DIRECTION INPUT ;
    USE SIGNAL ;
    PORT
      LAYER M4 ;
        RECT  21.516 42.768 21.6 42.792 ;
    END
  END i[294]
  PIN i[295]
    DIRECTION INPUT ;
    USE SIGNAL ;
    PORT
      LAYER M4 ;
        RECT  21.516 42.864 21.6 42.888 ;
    END
  END i[295]
  PIN i[296]
    DIRECTION INPUT ;
    USE SIGNAL ;
    PORT
      LAYER M4 ;
        RECT  21.516 42.96 21.6 42.984 ;
    END
  END i[296]
  PIN i[297]
    DIRECTION INPUT ;
    USE SIGNAL ;
    PORT
      LAYER M4 ;
        RECT  21.516 43.056 21.6 43.08 ;
    END
  END i[297]
  PIN i[298]
    DIRECTION INPUT ;
    USE SIGNAL ;
    PORT
      LAYER M4 ;
        RECT  21.516 43.152 21.6 43.176 ;
    END
  END i[298]
  PIN i[299]
    DIRECTION INPUT ;
    USE SIGNAL ;
    PORT
      LAYER M4 ;
        RECT  21.516 43.248 21.6 43.272 ;
    END
  END i[299]
  PIN i[29]
    DIRECTION INPUT ;
    USE SIGNAL ;
    PORT
      LAYER M4 ;
        RECT  21.516 22.704 21.6 22.728 ;
    END
  END i[29]
  PIN i[2]
    DIRECTION INPUT ;
    USE SIGNAL ;
    PORT
      LAYER M4 ;
        RECT  21.516 20.112 21.6 20.136 ;
    END
  END i[2]
  PIN i[300]
    DIRECTION INPUT ;
    USE SIGNAL ;
    PORT
      LAYER M4 ;
        RECT  21.516 43.344 21.6 43.368 ;
    END
  END i[300]
  PIN i[301]
    DIRECTION INPUT ;
    USE SIGNAL ;
    PORT
      LAYER M4 ;
        RECT  21.516 43.44 21.6 43.464 ;
    END
  END i[301]
  PIN i[302]
    DIRECTION INPUT ;
    USE SIGNAL ;
    PORT
      LAYER M4 ;
        RECT  21.516 43.536 21.6 43.56 ;
    END
  END i[302]
  PIN i[303]
    DIRECTION INPUT ;
    USE SIGNAL ;
    PORT
      LAYER M4 ;
        RECT  21.516 43.632 21.6 43.656 ;
    END
  END i[303]
  PIN i[304]
    DIRECTION INPUT ;
    USE SIGNAL ;
    PORT
      LAYER M4 ;
        RECT  21.516 43.728 21.6 43.752 ;
    END
  END i[304]
  PIN i[305]
    DIRECTION INPUT ;
    USE SIGNAL ;
    PORT
      LAYER M4 ;
        RECT  21.516 43.824 21.6 43.848 ;
    END
  END i[305]
  PIN i[306]
    DIRECTION INPUT ;
    USE SIGNAL ;
    PORT
      LAYER M4 ;
        RECT  21.516 43.92 21.6 43.944 ;
    END
  END i[306]
  PIN i[307]
    DIRECTION INPUT ;
    USE SIGNAL ;
    PORT
      LAYER M4 ;
        RECT  21.516 44.016 21.6 44.04 ;
    END
  END i[307]
  PIN i[308]
    DIRECTION INPUT ;
    USE SIGNAL ;
    PORT
      LAYER M4 ;
        RECT  21.516 44.112 21.6 44.136 ;
    END
  END i[308]
  PIN i[309]
    DIRECTION INPUT ;
    USE SIGNAL ;
    PORT
      LAYER M4 ;
        RECT  21.516 44.208 21.6 44.232 ;
    END
  END i[309]
  PIN i[30]
    DIRECTION INPUT ;
    USE SIGNAL ;
    PORT
      LAYER M4 ;
        RECT  21.516 22.8 21.6 22.824 ;
    END
  END i[30]
  PIN i[310]
    DIRECTION INPUT ;
    USE SIGNAL ;
    PORT
      LAYER M4 ;
        RECT  21.516 44.304 21.6 44.328 ;
    END
  END i[310]
  PIN i[311]
    DIRECTION INPUT ;
    USE SIGNAL ;
    PORT
      LAYER M4 ;
        RECT  21.516 44.4 21.6 44.424 ;
    END
  END i[311]
  PIN i[312]
    DIRECTION INPUT ;
    USE SIGNAL ;
    PORT
      LAYER M4 ;
        RECT  21.516 44.496 21.6 44.52 ;
    END
  END i[312]
  PIN i[313]
    DIRECTION INPUT ;
    USE SIGNAL ;
    PORT
      LAYER M4 ;
        RECT  21.516 44.592 21.6 44.616 ;
    END
  END i[313]
  PIN i[314]
    DIRECTION INPUT ;
    USE SIGNAL ;
    PORT
      LAYER M4 ;
        RECT  21.516 44.688 21.6 44.712 ;
    END
  END i[314]
  PIN i[315]
    DIRECTION INPUT ;
    USE SIGNAL ;
    PORT
      LAYER M4 ;
        RECT  21.516 44.784 21.6 44.808 ;
    END
  END i[315]
  PIN i[316]
    DIRECTION INPUT ;
    USE SIGNAL ;
    PORT
      LAYER M4 ;
        RECT  21.516 44.88 21.6 44.904 ;
    END
  END i[316]
  PIN i[317]
    DIRECTION INPUT ;
    USE SIGNAL ;
    PORT
      LAYER M4 ;
        RECT  21.516 44.976 21.6 45 ;
    END
  END i[317]
  PIN i[318]
    DIRECTION INPUT ;
    USE SIGNAL ;
    PORT
      LAYER M4 ;
        RECT  21.516 45.072 21.6 45.096 ;
    END
  END i[318]
  PIN i[319]
    DIRECTION INPUT ;
    USE SIGNAL ;
    PORT
      LAYER M4 ;
        RECT  21.516 45.168 21.6 45.192 ;
    END
  END i[319]
  PIN i[31]
    DIRECTION INPUT ;
    USE SIGNAL ;
    PORT
      LAYER M4 ;
        RECT  21.516 22.896 21.6 22.92 ;
    END
  END i[31]
  PIN i[320]
    DIRECTION INPUT ;
    USE SIGNAL ;
    PORT
      LAYER M4 ;
        RECT  21.516 45.264 21.6 45.288 ;
    END
  END i[320]
  PIN i[321]
    DIRECTION INPUT ;
    USE SIGNAL ;
    PORT
      LAYER M4 ;
        RECT  21.516 45.36 21.6 45.384 ;
    END
  END i[321]
  PIN i[322]
    DIRECTION INPUT ;
    USE SIGNAL ;
    PORT
      LAYER M4 ;
        RECT  21.516 45.456 21.6 45.48 ;
    END
  END i[322]
  PIN i[323]
    DIRECTION INPUT ;
    USE SIGNAL ;
    PORT
      LAYER M4 ;
        RECT  21.516 45.552 21.6 45.576 ;
    END
  END i[323]
  PIN i[324]
    DIRECTION INPUT ;
    USE SIGNAL ;
    PORT
      LAYER M4 ;
        RECT  21.516 45.648 21.6 45.672 ;
    END
  END i[324]
  PIN i[325]
    DIRECTION INPUT ;
    USE SIGNAL ;
    PORT
      LAYER M4 ;
        RECT  21.516 45.744 21.6 45.768 ;
    END
  END i[325]
  PIN i[326]
    DIRECTION INPUT ;
    USE SIGNAL ;
    PORT
      LAYER M4 ;
        RECT  21.516 45.84 21.6 45.864 ;
    END
  END i[326]
  PIN i[327]
    DIRECTION INPUT ;
    USE SIGNAL ;
    PORT
      LAYER M4 ;
        RECT  21.516 45.936 21.6 45.96 ;
    END
  END i[327]
  PIN i[328]
    DIRECTION INPUT ;
    USE SIGNAL ;
    PORT
      LAYER M4 ;
        RECT  21.516 46.032 21.6 46.056 ;
    END
  END i[328]
  PIN i[329]
    DIRECTION INPUT ;
    USE SIGNAL ;
    PORT
      LAYER M4 ;
        RECT  21.516 46.128 21.6 46.152 ;
    END
  END i[329]
  PIN i[32]
    DIRECTION INPUT ;
    USE SIGNAL ;
    PORT
      LAYER M4 ;
        RECT  21.516 29.136 21.6 29.16 ;
    END
  END i[32]
  PIN i[330]
    DIRECTION INPUT ;
    USE SIGNAL ;
    PORT
      LAYER M4 ;
        RECT  21.516 46.224 21.6 46.248 ;
    END
  END i[330]
  PIN i[331]
    DIRECTION INPUT ;
    USE SIGNAL ;
    PORT
      LAYER M4 ;
        RECT  21.516 46.32 21.6 46.344 ;
    END
  END i[331]
  PIN i[332]
    DIRECTION INPUT ;
    USE SIGNAL ;
    PORT
      LAYER M4 ;
        RECT  21.516 46.416 21.6 46.44 ;
    END
  END i[332]
  PIN i[333]
    DIRECTION INPUT ;
    USE SIGNAL ;
    PORT
      LAYER M4 ;
        RECT  21.516 46.512 21.6 46.536 ;
    END
  END i[333]
  PIN i[334]
    DIRECTION INPUT ;
    USE SIGNAL ;
    PORT
      LAYER M4 ;
        RECT  21.516 46.608 21.6 46.632 ;
    END
  END i[334]
  PIN i[335]
    DIRECTION INPUT ;
    USE SIGNAL ;
    PORT
      LAYER M4 ;
        RECT  21.516 46.704 21.6 46.728 ;
    END
  END i[335]
  PIN i[336]
    DIRECTION INPUT ;
    USE SIGNAL ;
    PORT
      LAYER M4 ;
        RECT  21.516 46.8 21.6 46.824 ;
    END
  END i[336]
  PIN i[337]
    DIRECTION INPUT ;
    USE SIGNAL ;
    PORT
      LAYER M4 ;
        RECT  21.516 46.896 21.6 46.92 ;
    END
  END i[337]
  PIN i[338]
    DIRECTION INPUT ;
    USE SIGNAL ;
    PORT
      LAYER M4 ;
        RECT  21.516 46.992 21.6 47.016 ;
    END
  END i[338]
  PIN i[339]
    DIRECTION INPUT ;
    USE SIGNAL ;
    PORT
      LAYER M4 ;
        RECT  21.516 47.088 21.6 47.112 ;
    END
  END i[339]
  PIN i[33]
    DIRECTION INPUT ;
    USE SIGNAL ;
    PORT
      LAYER M4 ;
        RECT  21.516 29.232 21.6 29.256 ;
    END
  END i[33]
  PIN i[340]
    DIRECTION INPUT ;
    USE SIGNAL ;
    PORT
      LAYER M4 ;
        RECT  21.516 47.184 21.6 47.208 ;
    END
  END i[340]
  PIN i[341]
    DIRECTION INPUT ;
    USE SIGNAL ;
    PORT
      LAYER M4 ;
        RECT  21.516 47.28 21.6 47.304 ;
    END
  END i[341]
  PIN i[342]
    DIRECTION INPUT ;
    USE SIGNAL ;
    PORT
      LAYER M4 ;
        RECT  21.516 47.376 21.6 47.4 ;
    END
  END i[342]
  PIN i[343]
    DIRECTION INPUT ;
    USE SIGNAL ;
    PORT
      LAYER M4 ;
        RECT  21.516 47.472 21.6 47.496 ;
    END
  END i[343]
  PIN i[344]
    DIRECTION INPUT ;
    USE SIGNAL ;
    PORT
      LAYER M4 ;
        RECT  21.516 47.568 21.6 47.592 ;
    END
  END i[344]
  PIN i[345]
    DIRECTION INPUT ;
    USE SIGNAL ;
    PORT
      LAYER M4 ;
        RECT  21.516 47.664 21.6 47.688 ;
    END
  END i[345]
  PIN i[346]
    DIRECTION INPUT ;
    USE SIGNAL ;
    PORT
      LAYER M4 ;
        RECT  21.516 47.76 21.6 47.784 ;
    END
  END i[346]
  PIN i[347]
    DIRECTION INPUT ;
    USE SIGNAL ;
    PORT
      LAYER M4 ;
        RECT  21.516 47.856 21.6 47.88 ;
    END
  END i[347]
  PIN i[348]
    DIRECTION INPUT ;
    USE SIGNAL ;
    PORT
      LAYER M4 ;
        RECT  21.516 47.952 21.6 47.976 ;
    END
  END i[348]
  PIN i[349]
    DIRECTION INPUT ;
    USE SIGNAL ;
    PORT
      LAYER M4 ;
        RECT  21.516 48.048 21.6 48.072 ;
    END
  END i[349]
  PIN i[34]
    DIRECTION INPUT ;
    USE SIGNAL ;
    PORT
      LAYER M4 ;
        RECT  21.516 29.328 21.6 29.352 ;
    END
  END i[34]
  PIN i[350]
    DIRECTION INPUT ;
    USE SIGNAL ;
    PORT
      LAYER M4 ;
        RECT  21.516 48.144 21.6 48.168 ;
    END
  END i[350]
  PIN i[351]
    DIRECTION INPUT ;
    USE SIGNAL ;
    PORT
      LAYER M4 ;
        RECT  21.516 48.24 21.6 48.264 ;
    END
  END i[351]
  PIN i[352]
    DIRECTION INPUT ;
    USE SIGNAL ;
    PORT
      LAYER M4 ;
        RECT  21.516 51.408 21.6 51.432 ;
    END
  END i[352]
  PIN i[353]
    DIRECTION INPUT ;
    USE SIGNAL ;
    PORT
      LAYER M4 ;
        RECT  21.516 51.504 21.6 51.528 ;
    END
  END i[353]
  PIN i[354]
    DIRECTION INPUT ;
    USE SIGNAL ;
    PORT
      LAYER M4 ;
        RECT  21.516 51.6 21.6 51.624 ;
    END
  END i[354]
  PIN i[355]
    DIRECTION INPUT ;
    USE SIGNAL ;
    PORT
      LAYER M4 ;
        RECT  21.516 51.696 21.6 51.72 ;
    END
  END i[355]
  PIN i[356]
    DIRECTION INPUT ;
    USE SIGNAL ;
    PORT
      LAYER M4 ;
        RECT  21.516 51.792 21.6 51.816 ;
    END
  END i[356]
  PIN i[357]
    DIRECTION INPUT ;
    USE SIGNAL ;
    PORT
      LAYER M4 ;
        RECT  21.516 51.888 21.6 51.912 ;
    END
  END i[357]
  PIN i[358]
    DIRECTION INPUT ;
    USE SIGNAL ;
    PORT
      LAYER M4 ;
        RECT  21.516 51.984 21.6 52.008 ;
    END
  END i[358]
  PIN i[359]
    DIRECTION INPUT ;
    USE SIGNAL ;
    PORT
      LAYER M4 ;
        RECT  21.516 52.08 21.6 52.104 ;
    END
  END i[359]
  PIN i[35]
    DIRECTION INPUT ;
    USE SIGNAL ;
    PORT
      LAYER M4 ;
        RECT  21.516 29.424 21.6 29.448 ;
    END
  END i[35]
  PIN i[360]
    DIRECTION INPUT ;
    USE SIGNAL ;
    PORT
      LAYER M4 ;
        RECT  21.516 52.176 21.6 52.2 ;
    END
  END i[360]
  PIN i[361]
    DIRECTION INPUT ;
    USE SIGNAL ;
    PORT
      LAYER M4 ;
        RECT  21.516 52.272 21.6 52.296 ;
    END
  END i[361]
  PIN i[362]
    DIRECTION INPUT ;
    USE SIGNAL ;
    PORT
      LAYER M4 ;
        RECT  21.516 52.368 21.6 52.392 ;
    END
  END i[362]
  PIN i[363]
    DIRECTION INPUT ;
    USE SIGNAL ;
    PORT
      LAYER M4 ;
        RECT  21.516 52.464 21.6 52.488 ;
    END
  END i[363]
  PIN i[364]
    DIRECTION INPUT ;
    USE SIGNAL ;
    PORT
      LAYER M4 ;
        RECT  21.516 52.56 21.6 52.584 ;
    END
  END i[364]
  PIN i[365]
    DIRECTION INPUT ;
    USE SIGNAL ;
    PORT
      LAYER M4 ;
        RECT  21.516 52.656 21.6 52.68 ;
    END
  END i[365]
  PIN i[366]
    DIRECTION INPUT ;
    USE SIGNAL ;
    PORT
      LAYER M4 ;
        RECT  21.516 52.752 21.6 52.776 ;
    END
  END i[366]
  PIN i[367]
    DIRECTION INPUT ;
    USE SIGNAL ;
    PORT
      LAYER M4 ;
        RECT  21.516 52.848 21.6 52.872 ;
    END
  END i[367]
  PIN i[368]
    DIRECTION INPUT ;
    USE SIGNAL ;
    PORT
      LAYER M4 ;
        RECT  21.516 52.944 21.6 52.968 ;
    END
  END i[368]
  PIN i[369]
    DIRECTION INPUT ;
    USE SIGNAL ;
    PORT
      LAYER M4 ;
        RECT  21.516 53.04 21.6 53.064 ;
    END
  END i[369]
  PIN i[36]
    DIRECTION INPUT ;
    USE SIGNAL ;
    PORT
      LAYER M4 ;
        RECT  21.516 29.52 21.6 29.544 ;
    END
  END i[36]
  PIN i[370]
    DIRECTION INPUT ;
    USE SIGNAL ;
    PORT
      LAYER M4 ;
        RECT  21.516 53.136 21.6 53.16 ;
    END
  END i[370]
  PIN i[371]
    DIRECTION INPUT ;
    USE SIGNAL ;
    PORT
      LAYER M4 ;
        RECT  21.516 53.232 21.6 53.256 ;
    END
  END i[371]
  PIN i[372]
    DIRECTION INPUT ;
    USE SIGNAL ;
    PORT
      LAYER M4 ;
        RECT  21.516 53.328 21.6 53.352 ;
    END
  END i[372]
  PIN i[373]
    DIRECTION INPUT ;
    USE SIGNAL ;
    PORT
      LAYER M4 ;
        RECT  21.516 53.424 21.6 53.448 ;
    END
  END i[373]
  PIN i[374]
    DIRECTION INPUT ;
    USE SIGNAL ;
    PORT
      LAYER M4 ;
        RECT  21.516 53.52 21.6 53.544 ;
    END
  END i[374]
  PIN i[375]
    DIRECTION INPUT ;
    USE SIGNAL ;
    PORT
      LAYER M4 ;
        RECT  21.516 53.616 21.6 53.64 ;
    END
  END i[375]
  PIN i[376]
    DIRECTION INPUT ;
    USE SIGNAL ;
    PORT
      LAYER M4 ;
        RECT  21.516 53.712 21.6 53.736 ;
    END
  END i[376]
  PIN i[377]
    DIRECTION INPUT ;
    USE SIGNAL ;
    PORT
      LAYER M4 ;
        RECT  21.516 53.808 21.6 53.832 ;
    END
  END i[377]
  PIN i[378]
    DIRECTION INPUT ;
    USE SIGNAL ;
    PORT
      LAYER M4 ;
        RECT  21.516 53.904 21.6 53.928 ;
    END
  END i[378]
  PIN i[379]
    DIRECTION INPUT ;
    USE SIGNAL ;
    PORT
      LAYER M4 ;
        RECT  21.516 54 21.6 54.024 ;
    END
  END i[379]
  PIN i[37]
    DIRECTION INPUT ;
    USE SIGNAL ;
    PORT
      LAYER M4 ;
        RECT  21.516 29.616 21.6 29.64 ;
    END
  END i[37]
  PIN i[380]
    DIRECTION INPUT ;
    USE SIGNAL ;
    PORT
      LAYER M4 ;
        RECT  21.516 54.096 21.6 54.12 ;
    END
  END i[380]
  PIN i[381]
    DIRECTION INPUT ;
    USE SIGNAL ;
    PORT
      LAYER M4 ;
        RECT  21.516 54.192 21.6 54.216 ;
    END
  END i[381]
  PIN i[382]
    DIRECTION INPUT ;
    USE SIGNAL ;
    PORT
      LAYER M4 ;
        RECT  21.516 54.288 21.6 54.312 ;
    END
  END i[382]
  PIN i[383]
    DIRECTION INPUT ;
    USE SIGNAL ;
    PORT
      LAYER M4 ;
        RECT  21.516 54.384 21.6 54.408 ;
    END
  END i[383]
  PIN i[384]
    DIRECTION INPUT ;
    USE SIGNAL ;
    PORT
      LAYER M4 ;
        RECT  21.516 39.12 21.6 39.144 ;
    END
  END i[384]
  PIN i[385]
    DIRECTION INPUT ;
    USE SIGNAL ;
    PORT
      LAYER M4 ;
        RECT  21.516 39.216 21.6 39.24 ;
    END
  END i[385]
  PIN i[386]
    DIRECTION INPUT ;
    USE SIGNAL ;
    PORT
      LAYER M4 ;
        RECT  21.516 39.312 21.6 39.336 ;
    END
  END i[386]
  PIN i[387]
    DIRECTION INPUT ;
    USE SIGNAL ;
    PORT
      LAYER M4 ;
        RECT  21.516 39.408 21.6 39.432 ;
    END
  END i[387]
  PIN i[388]
    DIRECTION INPUT ;
    USE SIGNAL ;
    PORT
      LAYER M4 ;
        RECT  21.516 39.504 21.6 39.528 ;
    END
  END i[388]
  PIN i[389]
    DIRECTION INPUT ;
    USE SIGNAL ;
    PORT
      LAYER M4 ;
        RECT  21.516 39.6 21.6 39.624 ;
    END
  END i[389]
  PIN i[38]
    DIRECTION INPUT ;
    USE SIGNAL ;
    PORT
      LAYER M4 ;
        RECT  21.516 29.712 21.6 29.736 ;
    END
  END i[38]
  PIN i[390]
    DIRECTION INPUT ;
    USE SIGNAL ;
    PORT
      LAYER M4 ;
        RECT  21.516 39.696 21.6 39.72 ;
    END
  END i[390]
  PIN i[391]
    DIRECTION INPUT ;
    USE SIGNAL ;
    PORT
      LAYER M4 ;
        RECT  21.516 39.792 21.6 39.816 ;
    END
  END i[391]
  PIN i[392]
    DIRECTION INPUT ;
    USE SIGNAL ;
    PORT
      LAYER M4 ;
        RECT  21.516 39.888 21.6 39.912 ;
    END
  END i[392]
  PIN i[393]
    DIRECTION INPUT ;
    USE SIGNAL ;
    PORT
      LAYER M4 ;
        RECT  21.516 39.984 21.6 40.008 ;
    END
  END i[393]
  PIN i[394]
    DIRECTION INPUT ;
    USE SIGNAL ;
    PORT
      LAYER M4 ;
        RECT  21.516 40.08 21.6 40.104 ;
    END
  END i[394]
  PIN i[395]
    DIRECTION INPUT ;
    USE SIGNAL ;
    PORT
      LAYER M4 ;
        RECT  21.516 40.176 21.6 40.2 ;
    END
  END i[395]
  PIN i[396]
    DIRECTION INPUT ;
    USE SIGNAL ;
    PORT
      LAYER M4 ;
        RECT  21.516 40.272 21.6 40.296 ;
    END
  END i[396]
  PIN i[397]
    DIRECTION INPUT ;
    USE SIGNAL ;
    PORT
      LAYER M4 ;
        RECT  21.516 40.368 21.6 40.392 ;
    END
  END i[397]
  PIN i[398]
    DIRECTION INPUT ;
    USE SIGNAL ;
    PORT
      LAYER M4 ;
        RECT  21.516 40.464 21.6 40.488 ;
    END
  END i[398]
  PIN i[399]
    DIRECTION INPUT ;
    USE SIGNAL ;
    PORT
      LAYER M4 ;
        RECT  21.516 40.56 21.6 40.584 ;
    END
  END i[399]
  PIN i[39]
    DIRECTION INPUT ;
    USE SIGNAL ;
    PORT
      LAYER M4 ;
        RECT  21.516 29.808 21.6 29.832 ;
    END
  END i[39]
  PIN i[3]
    DIRECTION INPUT ;
    USE SIGNAL ;
    PORT
      LAYER M4 ;
        RECT  21.516 20.208 21.6 20.232 ;
    END
  END i[3]
  PIN i[400]
    DIRECTION INPUT ;
    USE SIGNAL ;
    PORT
      LAYER M4 ;
        RECT  21.516 40.656 21.6 40.68 ;
    END
  END i[400]
  PIN i[401]
    DIRECTION INPUT ;
    USE SIGNAL ;
    PORT
      LAYER M4 ;
        RECT  21.516 40.752 21.6 40.776 ;
    END
  END i[401]
  PIN i[402]
    DIRECTION INPUT ;
    USE SIGNAL ;
    PORT
      LAYER M4 ;
        RECT  21.516 40.848 21.6 40.872 ;
    END
  END i[402]
  PIN i[403]
    DIRECTION INPUT ;
    USE SIGNAL ;
    PORT
      LAYER M4 ;
        RECT  21.516 40.944 21.6 40.968 ;
    END
  END i[403]
  PIN i[404]
    DIRECTION INPUT ;
    USE SIGNAL ;
    PORT
      LAYER M4 ;
        RECT  21.516 41.04 21.6 41.064 ;
    END
  END i[404]
  PIN i[405]
    DIRECTION INPUT ;
    USE SIGNAL ;
    PORT
      LAYER M4 ;
        RECT  21.516 41.136 21.6 41.16 ;
    END
  END i[405]
  PIN i[406]
    DIRECTION INPUT ;
    USE SIGNAL ;
    PORT
      LAYER M4 ;
        RECT  21.516 41.232 21.6 41.256 ;
    END
  END i[406]
  PIN i[407]
    DIRECTION INPUT ;
    USE SIGNAL ;
    PORT
      LAYER M4 ;
        RECT  21.516 41.328 21.6 41.352 ;
    END
  END i[407]
  PIN i[408]
    DIRECTION INPUT ;
    USE SIGNAL ;
    PORT
      LAYER M4 ;
        RECT  21.516 41.424 21.6 41.448 ;
    END
  END i[408]
  PIN i[409]
    DIRECTION INPUT ;
    USE SIGNAL ;
    PORT
      LAYER M4 ;
        RECT  21.516 41.52 21.6 41.544 ;
    END
  END i[409]
  PIN i[40]
    DIRECTION INPUT ;
    USE SIGNAL ;
    PORT
      LAYER M4 ;
        RECT  21.516 29.904 21.6 29.928 ;
    END
  END i[40]
  PIN i[410]
    DIRECTION INPUT ;
    USE SIGNAL ;
    PORT
      LAYER M4 ;
        RECT  21.516 41.616 21.6 41.64 ;
    END
  END i[410]
  PIN i[411]
    DIRECTION INPUT ;
    USE SIGNAL ;
    PORT
      LAYER M4 ;
        RECT  21.516 41.712 21.6 41.736 ;
    END
  END i[411]
  PIN i[412]
    DIRECTION INPUT ;
    USE SIGNAL ;
    PORT
      LAYER M4 ;
        RECT  21.516 41.808 21.6 41.832 ;
    END
  END i[412]
  PIN i[413]
    DIRECTION INPUT ;
    USE SIGNAL ;
    PORT
      LAYER M4 ;
        RECT  21.516 41.904 21.6 41.928 ;
    END
  END i[413]
  PIN i[414]
    DIRECTION INPUT ;
    USE SIGNAL ;
    PORT
      LAYER M4 ;
        RECT  21.516 42 21.6 42.024 ;
    END
  END i[414]
  PIN i[415]
    DIRECTION INPUT ;
    USE SIGNAL ;
    PORT
      LAYER M4 ;
        RECT  21.516 42.096 21.6 42.12 ;
    END
  END i[415]
  PIN i[416]
    DIRECTION INPUT ;
    USE SIGNAL ;
    PORT
      LAYER M4 ;
        RECT  21.516 54.48 21.6 54.504 ;
    END
  END i[416]
  PIN i[417]
    DIRECTION INPUT ;
    USE SIGNAL ;
    PORT
      LAYER M4 ;
        RECT  21.516 54.576 21.6 54.6 ;
    END
  END i[417]
  PIN i[418]
    DIRECTION INPUT ;
    USE SIGNAL ;
    PORT
      LAYER M4 ;
        RECT  21.516 54.672 21.6 54.696 ;
    END
  END i[418]
  PIN i[419]
    DIRECTION INPUT ;
    USE SIGNAL ;
    PORT
      LAYER M4 ;
        RECT  21.516 54.768 21.6 54.792 ;
    END
  END i[419]
  PIN i[41]
    DIRECTION INPUT ;
    USE SIGNAL ;
    PORT
      LAYER M4 ;
        RECT  21.516 30 21.6 30.024 ;
    END
  END i[41]
  PIN i[420]
    DIRECTION INPUT ;
    USE SIGNAL ;
    PORT
      LAYER M4 ;
        RECT  21.516 54.864 21.6 54.888 ;
    END
  END i[420]
  PIN i[421]
    DIRECTION INPUT ;
    USE SIGNAL ;
    PORT
      LAYER M4 ;
        RECT  21.516 54.96 21.6 54.984 ;
    END
  END i[421]
  PIN i[422]
    DIRECTION INPUT ;
    USE SIGNAL ;
    PORT
      LAYER M4 ;
        RECT  21.516 55.056 21.6 55.08 ;
    END
  END i[422]
  PIN i[423]
    DIRECTION INPUT ;
    USE SIGNAL ;
    PORT
      LAYER M4 ;
        RECT  21.516 55.152 21.6 55.176 ;
    END
  END i[423]
  PIN i[424]
    DIRECTION INPUT ;
    USE SIGNAL ;
    PORT
      LAYER M4 ;
        RECT  21.516 55.248 21.6 55.272 ;
    END
  END i[424]
  PIN i[425]
    DIRECTION INPUT ;
    USE SIGNAL ;
    PORT
      LAYER M4 ;
        RECT  21.516 55.344 21.6 55.368 ;
    END
  END i[425]
  PIN i[426]
    DIRECTION INPUT ;
    USE SIGNAL ;
    PORT
      LAYER M4 ;
        RECT  21.516 55.44 21.6 55.464 ;
    END
  END i[426]
  PIN i[427]
    DIRECTION INPUT ;
    USE SIGNAL ;
    PORT
      LAYER M4 ;
        RECT  21.516 55.536 21.6 55.56 ;
    END
  END i[427]
  PIN i[428]
    DIRECTION INPUT ;
    USE SIGNAL ;
    PORT
      LAYER M4 ;
        RECT  21.516 55.632 21.6 55.656 ;
    END
  END i[428]
  PIN i[429]
    DIRECTION INPUT ;
    USE SIGNAL ;
    PORT
      LAYER M4 ;
        RECT  21.516 55.728 21.6 55.752 ;
    END
  END i[429]
  PIN i[42]
    DIRECTION INPUT ;
    USE SIGNAL ;
    PORT
      LAYER M4 ;
        RECT  21.516 30.096 21.6 30.12 ;
    END
  END i[42]
  PIN i[430]
    DIRECTION INPUT ;
    USE SIGNAL ;
    PORT
      LAYER M4 ;
        RECT  21.516 55.824 21.6 55.848 ;
    END
  END i[430]
  PIN i[431]
    DIRECTION INPUT ;
    USE SIGNAL ;
    PORT
      LAYER M4 ;
        RECT  21.516 55.92 21.6 55.944 ;
    END
  END i[431]
  PIN i[432]
    DIRECTION INPUT ;
    USE SIGNAL ;
    PORT
      LAYER M4 ;
        RECT  21.516 56.016 21.6 56.04 ;
    END
  END i[432]
  PIN i[433]
    DIRECTION INPUT ;
    USE SIGNAL ;
    PORT
      LAYER M4 ;
        RECT  21.516 56.112 21.6 56.136 ;
    END
  END i[433]
  PIN i[434]
    DIRECTION INPUT ;
    USE SIGNAL ;
    PORT
      LAYER M4 ;
        RECT  21.516 56.208 21.6 56.232 ;
    END
  END i[434]
  PIN i[435]
    DIRECTION INPUT ;
    USE SIGNAL ;
    PORT
      LAYER M4 ;
        RECT  21.516 56.304 21.6 56.328 ;
    END
  END i[435]
  PIN i[436]
    DIRECTION INPUT ;
    USE SIGNAL ;
    PORT
      LAYER M4 ;
        RECT  21.516 56.4 21.6 56.424 ;
    END
  END i[436]
  PIN i[437]
    DIRECTION INPUT ;
    USE SIGNAL ;
    PORT
      LAYER M4 ;
        RECT  21.516 56.496 21.6 56.52 ;
    END
  END i[437]
  PIN i[438]
    DIRECTION INPUT ;
    USE SIGNAL ;
    PORT
      LAYER M4 ;
        RECT  21.516 56.592 21.6 56.616 ;
    END
  END i[438]
  PIN i[439]
    DIRECTION INPUT ;
    USE SIGNAL ;
    PORT
      LAYER M4 ;
        RECT  21.516 56.688 21.6 56.712 ;
    END
  END i[439]
  PIN i[43]
    DIRECTION INPUT ;
    USE SIGNAL ;
    PORT
      LAYER M4 ;
        RECT  21.516 30.192 21.6 30.216 ;
    END
  END i[43]
  PIN i[440]
    DIRECTION INPUT ;
    USE SIGNAL ;
    PORT
      LAYER M4 ;
        RECT  21.516 56.784 21.6 56.808 ;
    END
  END i[440]
  PIN i[441]
    DIRECTION INPUT ;
    USE SIGNAL ;
    PORT
      LAYER M4 ;
        RECT  21.516 56.88 21.6 56.904 ;
    END
  END i[441]
  PIN i[442]
    DIRECTION INPUT ;
    USE SIGNAL ;
    PORT
      LAYER M4 ;
        RECT  21.516 56.976 21.6 57 ;
    END
  END i[442]
  PIN i[443]
    DIRECTION INPUT ;
    USE SIGNAL ;
    PORT
      LAYER M4 ;
        RECT  21.516 57.072 21.6 57.096 ;
    END
  END i[443]
  PIN i[444]
    DIRECTION INPUT ;
    USE SIGNAL ;
    PORT
      LAYER M4 ;
        RECT  21.516 57.168 21.6 57.192 ;
    END
  END i[444]
  PIN i[445]
    DIRECTION INPUT ;
    USE SIGNAL ;
    PORT
      LAYER M4 ;
        RECT  21.516 57.264 21.6 57.288 ;
    END
  END i[445]
  PIN i[446]
    DIRECTION INPUT ;
    USE SIGNAL ;
    PORT
      LAYER M4 ;
        RECT  21.516 57.36 21.6 57.384 ;
    END
  END i[446]
  PIN i[447]
    DIRECTION INPUT ;
    USE SIGNAL ;
    PORT
      LAYER M4 ;
        RECT  21.516 57.456 21.6 57.48 ;
    END
  END i[447]
  PIN i[448]
    DIRECTION INPUT ;
    USE SIGNAL ;
    PORT
      LAYER M4 ;
        RECT  21.516 35.28 21.6 35.304 ;
    END
  END i[448]
  PIN i[449]
    DIRECTION INPUT ;
    USE SIGNAL ;
    PORT
      LAYER M4 ;
        RECT  21.516 35.376 21.6 35.4 ;
    END
  END i[449]
  PIN i[44]
    DIRECTION INPUT ;
    USE SIGNAL ;
    PORT
      LAYER M4 ;
        RECT  21.516 30.288 21.6 30.312 ;
    END
  END i[44]
  PIN i[450]
    DIRECTION INPUT ;
    USE SIGNAL ;
    PORT
      LAYER M4 ;
        RECT  21.516 35.472 21.6 35.496 ;
    END
  END i[450]
  PIN i[451]
    DIRECTION INPUT ;
    USE SIGNAL ;
    PORT
      LAYER M4 ;
        RECT  21.516 35.568 21.6 35.592 ;
    END
  END i[451]
  PIN i[452]
    DIRECTION INPUT ;
    USE SIGNAL ;
    PORT
      LAYER M4 ;
        RECT  21.516 35.664 21.6 35.688 ;
    END
  END i[452]
  PIN i[453]
    DIRECTION INPUT ;
    USE SIGNAL ;
    PORT
      LAYER M4 ;
        RECT  21.516 35.76 21.6 35.784 ;
    END
  END i[453]
  PIN i[454]
    DIRECTION INPUT ;
    USE SIGNAL ;
    PORT
      LAYER M4 ;
        RECT  21.516 35.856 21.6 35.88 ;
    END
  END i[454]
  PIN i[455]
    DIRECTION INPUT ;
    USE SIGNAL ;
    PORT
      LAYER M4 ;
        RECT  21.516 35.952 21.6 35.976 ;
    END
  END i[455]
  PIN i[456]
    DIRECTION INPUT ;
    USE SIGNAL ;
    PORT
      LAYER M4 ;
        RECT  21.516 36.048 21.6 36.072 ;
    END
  END i[456]
  PIN i[457]
    DIRECTION INPUT ;
    USE SIGNAL ;
    PORT
      LAYER M4 ;
        RECT  21.516 36.144 21.6 36.168 ;
    END
  END i[457]
  PIN i[458]
    DIRECTION INPUT ;
    USE SIGNAL ;
    PORT
      LAYER M4 ;
        RECT  21.516 36.24 21.6 36.264 ;
    END
  END i[458]
  PIN i[459]
    DIRECTION INPUT ;
    USE SIGNAL ;
    PORT
      LAYER M4 ;
        RECT  21.516 36.336 21.6 36.36 ;
    END
  END i[459]
  PIN i[45]
    DIRECTION INPUT ;
    USE SIGNAL ;
    PORT
      LAYER M4 ;
        RECT  21.516 30.384 21.6 30.408 ;
    END
  END i[45]
  PIN i[460]
    DIRECTION INPUT ;
    USE SIGNAL ;
    PORT
      LAYER M4 ;
        RECT  21.516 36.432 21.6 36.456 ;
    END
  END i[460]
  PIN i[461]
    DIRECTION INPUT ;
    USE SIGNAL ;
    PORT
      LAYER M4 ;
        RECT  21.516 36.528 21.6 36.552 ;
    END
  END i[461]
  PIN i[462]
    DIRECTION INPUT ;
    USE SIGNAL ;
    PORT
      LAYER M4 ;
        RECT  21.516 36.624 21.6 36.648 ;
    END
  END i[462]
  PIN i[463]
    DIRECTION INPUT ;
    USE SIGNAL ;
    PORT
      LAYER M4 ;
        RECT  21.516 36.72 21.6 36.744 ;
    END
  END i[463]
  PIN i[464]
    DIRECTION INPUT ;
    USE SIGNAL ;
    PORT
      LAYER M4 ;
        RECT  21.516 36.816 21.6 36.84 ;
    END
  END i[464]
  PIN i[465]
    DIRECTION INPUT ;
    USE SIGNAL ;
    PORT
      LAYER M4 ;
        RECT  21.516 36.912 21.6 36.936 ;
    END
  END i[465]
  PIN i[466]
    DIRECTION INPUT ;
    USE SIGNAL ;
    PORT
      LAYER M4 ;
        RECT  21.516 37.008 21.6 37.032 ;
    END
  END i[466]
  PIN i[467]
    DIRECTION INPUT ;
    USE SIGNAL ;
    PORT
      LAYER M4 ;
        RECT  21.516 37.104 21.6 37.128 ;
    END
  END i[467]
  PIN i[468]
    DIRECTION INPUT ;
    USE SIGNAL ;
    PORT
      LAYER M4 ;
        RECT  21.516 37.2 21.6 37.224 ;
    END
  END i[468]
  PIN i[469]
    DIRECTION INPUT ;
    USE SIGNAL ;
    PORT
      LAYER M4 ;
        RECT  21.516 37.296 21.6 37.32 ;
    END
  END i[469]
  PIN i[46]
    DIRECTION INPUT ;
    USE SIGNAL ;
    PORT
      LAYER M4 ;
        RECT  21.516 30.48 21.6 30.504 ;
    END
  END i[46]
  PIN i[470]
    DIRECTION INPUT ;
    USE SIGNAL ;
    PORT
      LAYER M4 ;
        RECT  21.516 37.392 21.6 37.416 ;
    END
  END i[470]
  PIN i[471]
    DIRECTION INPUT ;
    USE SIGNAL ;
    PORT
      LAYER M4 ;
        RECT  21.516 37.488 21.6 37.512 ;
    END
  END i[471]
  PIN i[472]
    DIRECTION INPUT ;
    USE SIGNAL ;
    PORT
      LAYER M4 ;
        RECT  21.516 37.584 21.6 37.608 ;
    END
  END i[472]
  PIN i[473]
    DIRECTION INPUT ;
    USE SIGNAL ;
    PORT
      LAYER M4 ;
        RECT  21.516 37.68 21.6 37.704 ;
    END
  END i[473]
  PIN i[474]
    DIRECTION INPUT ;
    USE SIGNAL ;
    PORT
      LAYER M4 ;
        RECT  21.516 37.776 21.6 37.8 ;
    END
  END i[474]
  PIN i[475]
    DIRECTION INPUT ;
    USE SIGNAL ;
    PORT
      LAYER M4 ;
        RECT  21.516 37.872 21.6 37.896 ;
    END
  END i[475]
  PIN i[476]
    DIRECTION INPUT ;
    USE SIGNAL ;
    PORT
      LAYER M4 ;
        RECT  21.516 37.968 21.6 37.992 ;
    END
  END i[476]
  PIN i[477]
    DIRECTION INPUT ;
    USE SIGNAL ;
    PORT
      LAYER M4 ;
        RECT  21.516 38.064 21.6 38.088 ;
    END
  END i[477]
  PIN i[478]
    DIRECTION INPUT ;
    USE SIGNAL ;
    PORT
      LAYER M4 ;
        RECT  21.516 38.16 21.6 38.184 ;
    END
  END i[478]
  PIN i[479]
    DIRECTION INPUT ;
    USE SIGNAL ;
    PORT
      LAYER M4 ;
        RECT  21.516 38.256 21.6 38.28 ;
    END
  END i[479]
  PIN i[47]
    DIRECTION INPUT ;
    USE SIGNAL ;
    PORT
      LAYER M4 ;
        RECT  21.516 30.576 21.6 30.6 ;
    END
  END i[47]
  PIN i[480]
    DIRECTION INPUT ;
    USE SIGNAL ;
    PORT
      LAYER M4 ;
        RECT  21.516 58.32 21.6 58.344 ;
    END
  END i[480]
  PIN i[481]
    DIRECTION INPUT ;
    USE SIGNAL ;
    PORT
      LAYER M4 ;
        RECT  21.516 58.416 21.6 58.44 ;
    END
  END i[481]
  PIN i[482]
    DIRECTION INPUT ;
    USE SIGNAL ;
    PORT
      LAYER M4 ;
        RECT  21.516 58.512 21.6 58.536 ;
    END
  END i[482]
  PIN i[483]
    DIRECTION INPUT ;
    USE SIGNAL ;
    PORT
      LAYER M4 ;
        RECT  21.516 58.608 21.6 58.632 ;
    END
  END i[483]
  PIN i[484]
    DIRECTION INPUT ;
    USE SIGNAL ;
    PORT
      LAYER M4 ;
        RECT  21.516 58.704 21.6 58.728 ;
    END
  END i[484]
  PIN i[485]
    DIRECTION INPUT ;
    USE SIGNAL ;
    PORT
      LAYER M4 ;
        RECT  21.516 58.8 21.6 58.824 ;
    END
  END i[485]
  PIN i[486]
    DIRECTION INPUT ;
    USE SIGNAL ;
    PORT
      LAYER M4 ;
        RECT  21.516 58.896 21.6 58.92 ;
    END
  END i[486]
  PIN i[487]
    DIRECTION INPUT ;
    USE SIGNAL ;
    PORT
      LAYER M4 ;
        RECT  21.516 58.992 21.6 59.016 ;
    END
  END i[487]
  PIN i[488]
    DIRECTION INPUT ;
    USE SIGNAL ;
    PORT
      LAYER M4 ;
        RECT  21.516 59.088 21.6 59.112 ;
    END
  END i[488]
  PIN i[489]
    DIRECTION INPUT ;
    USE SIGNAL ;
    PORT
      LAYER M4 ;
        RECT  21.516 59.184 21.6 59.208 ;
    END
  END i[489]
  PIN i[48]
    DIRECTION INPUT ;
    USE SIGNAL ;
    PORT
      LAYER M4 ;
        RECT  21.516 30.672 21.6 30.696 ;
    END
  END i[48]
  PIN i[490]
    DIRECTION INPUT ;
    USE SIGNAL ;
    PORT
      LAYER M4 ;
        RECT  21.516 59.28 21.6 59.304 ;
    END
  END i[490]
  PIN i[491]
    DIRECTION INPUT ;
    USE SIGNAL ;
    PORT
      LAYER M4 ;
        RECT  21.516 59.376 21.6 59.4 ;
    END
  END i[491]
  PIN i[492]
    DIRECTION INPUT ;
    USE SIGNAL ;
    PORT
      LAYER M4 ;
        RECT  21.516 59.472 21.6 59.496 ;
    END
  END i[492]
  PIN i[493]
    DIRECTION INPUT ;
    USE SIGNAL ;
    PORT
      LAYER M4 ;
        RECT  21.516 59.568 21.6 59.592 ;
    END
  END i[493]
  PIN i[494]
    DIRECTION INPUT ;
    USE SIGNAL ;
    PORT
      LAYER M4 ;
        RECT  21.516 59.664 21.6 59.688 ;
    END
  END i[494]
  PIN i[495]
    DIRECTION INPUT ;
    USE SIGNAL ;
    PORT
      LAYER M4 ;
        RECT  21.516 59.76 21.6 59.784 ;
    END
  END i[495]
  PIN i[496]
    DIRECTION INPUT ;
    USE SIGNAL ;
    PORT
      LAYER M4 ;
        RECT  21.516 59.856 21.6 59.88 ;
    END
  END i[496]
  PIN i[497]
    DIRECTION INPUT ;
    USE SIGNAL ;
    PORT
      LAYER M4 ;
        RECT  21.516 59.952 21.6 59.976 ;
    END
  END i[497]
  PIN i[498]
    DIRECTION INPUT ;
    USE SIGNAL ;
    PORT
      LAYER M4 ;
        RECT  21.516 60.048 21.6 60.072 ;
    END
  END i[498]
  PIN i[499]
    DIRECTION INPUT ;
    USE SIGNAL ;
    PORT
      LAYER M4 ;
        RECT  21.516 60.144 21.6 60.168 ;
    END
  END i[499]
  PIN i[49]
    DIRECTION INPUT ;
    USE SIGNAL ;
    PORT
      LAYER M4 ;
        RECT  21.516 30.768 21.6 30.792 ;
    END
  END i[49]
  PIN i[4]
    DIRECTION INPUT ;
    USE SIGNAL ;
    PORT
      LAYER M4 ;
        RECT  21.516 20.304 21.6 20.328 ;
    END
  END i[4]
  PIN i[500]
    DIRECTION INPUT ;
    USE SIGNAL ;
    PORT
      LAYER M4 ;
        RECT  21.516 60.24 21.6 60.264 ;
    END
  END i[500]
  PIN i[501]
    DIRECTION INPUT ;
    USE SIGNAL ;
    PORT
      LAYER M4 ;
        RECT  21.516 60.336 21.6 60.36 ;
    END
  END i[501]
  PIN i[502]
    DIRECTION INPUT ;
    USE SIGNAL ;
    PORT
      LAYER M4 ;
        RECT  21.516 60.432 21.6 60.456 ;
    END
  END i[502]
  PIN i[503]
    DIRECTION INPUT ;
    USE SIGNAL ;
    PORT
      LAYER M4 ;
        RECT  21.516 60.528 21.6 60.552 ;
    END
  END i[503]
  PIN i[504]
    DIRECTION INPUT ;
    USE SIGNAL ;
    PORT
      LAYER M4 ;
        RECT  21.516 60.624 21.6 60.648 ;
    END
  END i[504]
  PIN i[505]
    DIRECTION INPUT ;
    USE SIGNAL ;
    PORT
      LAYER M4 ;
        RECT  21.516 60.72 21.6 60.744 ;
    END
  END i[505]
  PIN i[506]
    DIRECTION INPUT ;
    USE SIGNAL ;
    PORT
      LAYER M4 ;
        RECT  21.516 60.816 21.6 60.84 ;
    END
  END i[506]
  PIN i[507]
    DIRECTION INPUT ;
    USE SIGNAL ;
    PORT
      LAYER M4 ;
        RECT  21.516 60.912 21.6 60.936 ;
    END
  END i[507]
  PIN i[508]
    DIRECTION INPUT ;
    USE SIGNAL ;
    PORT
      LAYER M4 ;
        RECT  21.516 61.008 21.6 61.032 ;
    END
  END i[508]
  PIN i[509]
    DIRECTION INPUT ;
    USE SIGNAL ;
    PORT
      LAYER M4 ;
        RECT  21.516 61.104 21.6 61.128 ;
    END
  END i[509]
  PIN i[50]
    DIRECTION INPUT ;
    USE SIGNAL ;
    PORT
      LAYER M4 ;
        RECT  21.516 30.864 21.6 30.888 ;
    END
  END i[50]
  PIN i[510]
    DIRECTION INPUT ;
    USE SIGNAL ;
    PORT
      LAYER M4 ;
        RECT  21.516 61.2 21.6 61.224 ;
    END
  END i[510]
  PIN i[511]
    DIRECTION INPUT ;
    USE SIGNAL ;
    PORT
      LAYER M4 ;
        RECT  21.516 61.296 21.6 61.32 ;
    END
  END i[511]
  PIN i[512]
    DIRECTION INPUT ;
    USE SIGNAL ;
    PORT
      LAYER M4 ;
        RECT  21.516 0.72 21.6 0.744 ;
    END
  END i[512]
  PIN i[513]
    DIRECTION INPUT ;
    USE SIGNAL ;
    PORT
      LAYER M4 ;
        RECT  21.516 0.816 21.6 0.84 ;
    END
  END i[513]
  PIN i[514]
    DIRECTION INPUT ;
    USE SIGNAL ;
    PORT
      LAYER M4 ;
        RECT  21.516 0.912 21.6 0.936 ;
    END
  END i[514]
  PIN i[515]
    DIRECTION INPUT ;
    USE SIGNAL ;
    PORT
      LAYER M4 ;
        RECT  21.516 1.008 21.6 1.032 ;
    END
  END i[515]
  PIN i[516]
    DIRECTION INPUT ;
    USE SIGNAL ;
    PORT
      LAYER M4 ;
        RECT  21.516 1.104 21.6 1.128 ;
    END
  END i[516]
  PIN i[517]
    DIRECTION INPUT ;
    USE SIGNAL ;
    PORT
      LAYER M4 ;
        RECT  21.516 1.2 21.6 1.224 ;
    END
  END i[517]
  PIN i[518]
    DIRECTION INPUT ;
    USE SIGNAL ;
    PORT
      LAYER M4 ;
        RECT  21.516 1.296 21.6 1.32 ;
    END
  END i[518]
  PIN i[519]
    DIRECTION INPUT ;
    USE SIGNAL ;
    PORT
      LAYER M4 ;
        RECT  21.516 1.392 21.6 1.416 ;
    END
  END i[519]
  PIN i[51]
    DIRECTION INPUT ;
    USE SIGNAL ;
    PORT
      LAYER M4 ;
        RECT  21.516 30.96 21.6 30.984 ;
    END
  END i[51]
  PIN i[520]
    DIRECTION INPUT ;
    USE SIGNAL ;
    PORT
      LAYER M4 ;
        RECT  21.516 1.488 21.6 1.512 ;
    END
  END i[520]
  PIN i[521]
    DIRECTION INPUT ;
    USE SIGNAL ;
    PORT
      LAYER M4 ;
        RECT  21.516 1.584 21.6 1.608 ;
    END
  END i[521]
  PIN i[522]
    DIRECTION INPUT ;
    USE SIGNAL ;
    PORT
      LAYER M4 ;
        RECT  21.516 1.68 21.6 1.704 ;
    END
  END i[522]
  PIN i[523]
    DIRECTION INPUT ;
    USE SIGNAL ;
    PORT
      LAYER M4 ;
        RECT  21.516 1.776 21.6 1.8 ;
    END
  END i[523]
  PIN i[524]
    DIRECTION INPUT ;
    USE SIGNAL ;
    PORT
      LAYER M4 ;
        RECT  21.516 1.872 21.6 1.896 ;
    END
  END i[524]
  PIN i[525]
    DIRECTION INPUT ;
    USE SIGNAL ;
    PORT
      LAYER M4 ;
        RECT  21.516 1.968 21.6 1.992 ;
    END
  END i[525]
  PIN i[526]
    DIRECTION INPUT ;
    USE SIGNAL ;
    PORT
      LAYER M4 ;
        RECT  21.516 2.064 21.6 2.088 ;
    END
  END i[526]
  PIN i[527]
    DIRECTION INPUT ;
    USE SIGNAL ;
    PORT
      LAYER M4 ;
        RECT  21.516 2.16 21.6 2.184 ;
    END
  END i[527]
  PIN i[528]
    DIRECTION INPUT ;
    USE SIGNAL ;
    PORT
      LAYER M4 ;
        RECT  21.516 2.256 21.6 2.28 ;
    END
  END i[528]
  PIN i[529]
    DIRECTION INPUT ;
    USE SIGNAL ;
    PORT
      LAYER M4 ;
        RECT  21.516 2.352 21.6 2.376 ;
    END
  END i[529]
  PIN i[52]
    DIRECTION INPUT ;
    USE SIGNAL ;
    PORT
      LAYER M4 ;
        RECT  21.516 31.056 21.6 31.08 ;
    END
  END i[52]
  PIN i[530]
    DIRECTION INPUT ;
    USE SIGNAL ;
    PORT
      LAYER M4 ;
        RECT  21.516 2.448 21.6 2.472 ;
    END
  END i[530]
  PIN i[531]
    DIRECTION INPUT ;
    USE SIGNAL ;
    PORT
      LAYER M4 ;
        RECT  21.516 2.544 21.6 2.568 ;
    END
  END i[531]
  PIN i[532]
    DIRECTION INPUT ;
    USE SIGNAL ;
    PORT
      LAYER M4 ;
        RECT  21.516 2.64 21.6 2.664 ;
    END
  END i[532]
  PIN i[533]
    DIRECTION INPUT ;
    USE SIGNAL ;
    PORT
      LAYER M4 ;
        RECT  21.516 2.736 21.6 2.76 ;
    END
  END i[533]
  PIN i[534]
    DIRECTION INPUT ;
    USE SIGNAL ;
    PORT
      LAYER M4 ;
        RECT  21.516 2.832 21.6 2.856 ;
    END
  END i[534]
  PIN i[535]
    DIRECTION INPUT ;
    USE SIGNAL ;
    PORT
      LAYER M4 ;
        RECT  21.516 2.928 21.6 2.952 ;
    END
  END i[535]
  PIN i[536]
    DIRECTION INPUT ;
    USE SIGNAL ;
    PORT
      LAYER M4 ;
        RECT  21.516 3.024 21.6 3.048 ;
    END
  END i[536]
  PIN i[537]
    DIRECTION INPUT ;
    USE SIGNAL ;
    PORT
      LAYER M4 ;
        RECT  21.516 3.12 21.6 3.144 ;
    END
  END i[537]
  PIN i[538]
    DIRECTION INPUT ;
    USE SIGNAL ;
    PORT
      LAYER M4 ;
        RECT  21.516 3.216 21.6 3.24 ;
    END
  END i[538]
  PIN i[539]
    DIRECTION INPUT ;
    USE SIGNAL ;
    PORT
      LAYER M4 ;
        RECT  21.516 3.312 21.6 3.336 ;
    END
  END i[539]
  PIN i[53]
    DIRECTION INPUT ;
    USE SIGNAL ;
    PORT
      LAYER M4 ;
        RECT  21.516 31.152 21.6 31.176 ;
    END
  END i[53]
  PIN i[540]
    DIRECTION INPUT ;
    USE SIGNAL ;
    PORT
      LAYER M4 ;
        RECT  21.516 3.408 21.6 3.432 ;
    END
  END i[540]
  PIN i[541]
    DIRECTION INPUT ;
    USE SIGNAL ;
    PORT
      LAYER M4 ;
        RECT  21.516 3.504 21.6 3.528 ;
    END
  END i[541]
  PIN i[542]
    DIRECTION INPUT ;
    USE SIGNAL ;
    PORT
      LAYER M4 ;
        RECT  21.516 3.6 21.6 3.624 ;
    END
  END i[542]
  PIN i[543]
    DIRECTION INPUT ;
    USE SIGNAL ;
    PORT
      LAYER M4 ;
        RECT  21.516 3.696 21.6 3.72 ;
    END
  END i[543]
  PIN i[544]
    DIRECTION INPUT ;
    USE SIGNAL ;
    PORT
      LAYER M4 ;
        RECT  21.516 16.08 21.6 16.104 ;
    END
  END i[544]
  PIN i[545]
    DIRECTION INPUT ;
    USE SIGNAL ;
    PORT
      LAYER M4 ;
        RECT  21.516 16.176 21.6 16.2 ;
    END
  END i[545]
  PIN i[546]
    DIRECTION INPUT ;
    USE SIGNAL ;
    PORT
      LAYER M4 ;
        RECT  21.516 16.272 21.6 16.296 ;
    END
  END i[546]
  PIN i[547]
    DIRECTION INPUT ;
    USE SIGNAL ;
    PORT
      LAYER M4 ;
        RECT  21.516 16.368 21.6 16.392 ;
    END
  END i[547]
  PIN i[548]
    DIRECTION INPUT ;
    USE SIGNAL ;
    PORT
      LAYER M4 ;
        RECT  21.516 16.464 21.6 16.488 ;
    END
  END i[548]
  PIN i[549]
    DIRECTION INPUT ;
    USE SIGNAL ;
    PORT
      LAYER M4 ;
        RECT  21.516 16.56 21.6 16.584 ;
    END
  END i[549]
  PIN i[54]
    DIRECTION INPUT ;
    USE SIGNAL ;
    PORT
      LAYER M4 ;
        RECT  21.516 31.248 21.6 31.272 ;
    END
  END i[54]
  PIN i[550]
    DIRECTION INPUT ;
    USE SIGNAL ;
    PORT
      LAYER M4 ;
        RECT  21.516 16.656 21.6 16.68 ;
    END
  END i[550]
  PIN i[551]
    DIRECTION INPUT ;
    USE SIGNAL ;
    PORT
      LAYER M4 ;
        RECT  21.516 16.752 21.6 16.776 ;
    END
  END i[551]
  PIN i[552]
    DIRECTION INPUT ;
    USE SIGNAL ;
    PORT
      LAYER M4 ;
        RECT  21.516 16.848 21.6 16.872 ;
    END
  END i[552]
  PIN i[553]
    DIRECTION INPUT ;
    USE SIGNAL ;
    PORT
      LAYER M4 ;
        RECT  21.516 16.944 21.6 16.968 ;
    END
  END i[553]
  PIN i[554]
    DIRECTION INPUT ;
    USE SIGNAL ;
    PORT
      LAYER M4 ;
        RECT  21.516 17.04 21.6 17.064 ;
    END
  END i[554]
  PIN i[555]
    DIRECTION INPUT ;
    USE SIGNAL ;
    PORT
      LAYER M4 ;
        RECT  21.516 17.136 21.6 17.16 ;
    END
  END i[555]
  PIN i[556]
    DIRECTION INPUT ;
    USE SIGNAL ;
    PORT
      LAYER M4 ;
        RECT  21.516 17.232 21.6 17.256 ;
    END
  END i[556]
  PIN i[557]
    DIRECTION INPUT ;
    USE SIGNAL ;
    PORT
      LAYER M4 ;
        RECT  21.516 17.328 21.6 17.352 ;
    END
  END i[557]
  PIN i[558]
    DIRECTION INPUT ;
    USE SIGNAL ;
    PORT
      LAYER M4 ;
        RECT  21.516 17.424 21.6 17.448 ;
    END
  END i[558]
  PIN i[559]
    DIRECTION INPUT ;
    USE SIGNAL ;
    PORT
      LAYER M4 ;
        RECT  21.516 17.52 21.6 17.544 ;
    END
  END i[559]
  PIN i[55]
    DIRECTION INPUT ;
    USE SIGNAL ;
    PORT
      LAYER M4 ;
        RECT  21.516 31.344 21.6 31.368 ;
    END
  END i[55]
  PIN i[560]
    DIRECTION INPUT ;
    USE SIGNAL ;
    PORT
      LAYER M4 ;
        RECT  21.516 17.616 21.6 17.64 ;
    END
  END i[560]
  PIN i[561]
    DIRECTION INPUT ;
    USE SIGNAL ;
    PORT
      LAYER M4 ;
        RECT  21.516 17.712 21.6 17.736 ;
    END
  END i[561]
  PIN i[562]
    DIRECTION INPUT ;
    USE SIGNAL ;
    PORT
      LAYER M4 ;
        RECT  21.516 17.808 21.6 17.832 ;
    END
  END i[562]
  PIN i[563]
    DIRECTION INPUT ;
    USE SIGNAL ;
    PORT
      LAYER M4 ;
        RECT  21.516 17.904 21.6 17.928 ;
    END
  END i[563]
  PIN i[564]
    DIRECTION INPUT ;
    USE SIGNAL ;
    PORT
      LAYER M4 ;
        RECT  21.516 18 21.6 18.024 ;
    END
  END i[564]
  PIN i[565]
    DIRECTION INPUT ;
    USE SIGNAL ;
    PORT
      LAYER M4 ;
        RECT  21.516 18.096 21.6 18.12 ;
    END
  END i[565]
  PIN i[566]
    DIRECTION INPUT ;
    USE SIGNAL ;
    PORT
      LAYER M4 ;
        RECT  21.516 18.192 21.6 18.216 ;
    END
  END i[566]
  PIN i[567]
    DIRECTION INPUT ;
    USE SIGNAL ;
    PORT
      LAYER M4 ;
        RECT  21.516 18.288 21.6 18.312 ;
    END
  END i[567]
  PIN i[568]
    DIRECTION INPUT ;
    USE SIGNAL ;
    PORT
      LAYER M4 ;
        RECT  21.516 18.384 21.6 18.408 ;
    END
  END i[568]
  PIN i[569]
    DIRECTION INPUT ;
    USE SIGNAL ;
    PORT
      LAYER M4 ;
        RECT  21.516 18.48 21.6 18.504 ;
    END
  END i[569]
  PIN i[56]
    DIRECTION INPUT ;
    USE SIGNAL ;
    PORT
      LAYER M4 ;
        RECT  21.516 31.44 21.6 31.464 ;
    END
  END i[56]
  PIN i[570]
    DIRECTION INPUT ;
    USE SIGNAL ;
    PORT
      LAYER M4 ;
        RECT  21.516 18.576 21.6 18.6 ;
    END
  END i[570]
  PIN i[571]
    DIRECTION INPUT ;
    USE SIGNAL ;
    PORT
      LAYER M4 ;
        RECT  21.516 18.672 21.6 18.696 ;
    END
  END i[571]
  PIN i[572]
    DIRECTION INPUT ;
    USE SIGNAL ;
    PORT
      LAYER M4 ;
        RECT  21.516 18.768 21.6 18.792 ;
    END
  END i[572]
  PIN i[573]
    DIRECTION INPUT ;
    USE SIGNAL ;
    PORT
      LAYER M4 ;
        RECT  21.516 18.864 21.6 18.888 ;
    END
  END i[573]
  PIN i[574]
    DIRECTION INPUT ;
    USE SIGNAL ;
    PORT
      LAYER M4 ;
        RECT  21.516 18.96 21.6 18.984 ;
    END
  END i[574]
  PIN i[575]
    DIRECTION INPUT ;
    USE SIGNAL ;
    PORT
      LAYER M4 ;
        RECT  21.516 19.056 21.6 19.08 ;
    END
  END i[575]
  PIN i[576]
    DIRECTION INPUT ;
    USE SIGNAL ;
    PORT
      LAYER M4 ;
        RECT  21.516 13.008 21.6 13.032 ;
    END
  END i[576]
  PIN i[577]
    DIRECTION INPUT ;
    USE SIGNAL ;
    PORT
      LAYER M4 ;
        RECT  21.516 13.104 21.6 13.128 ;
    END
  END i[577]
  PIN i[578]
    DIRECTION INPUT ;
    USE SIGNAL ;
    PORT
      LAYER M4 ;
        RECT  21.516 13.2 21.6 13.224 ;
    END
  END i[578]
  PIN i[579]
    DIRECTION INPUT ;
    USE SIGNAL ;
    PORT
      LAYER M4 ;
        RECT  21.516 13.296 21.6 13.32 ;
    END
  END i[579]
  PIN i[57]
    DIRECTION INPUT ;
    USE SIGNAL ;
    PORT
      LAYER M4 ;
        RECT  21.516 31.536 21.6 31.56 ;
    END
  END i[57]
  PIN i[580]
    DIRECTION INPUT ;
    USE SIGNAL ;
    PORT
      LAYER M4 ;
        RECT  21.516 13.392 21.6 13.416 ;
    END
  END i[580]
  PIN i[581]
    DIRECTION INPUT ;
    USE SIGNAL ;
    PORT
      LAYER M4 ;
        RECT  21.516 13.488 21.6 13.512 ;
    END
  END i[581]
  PIN i[582]
    DIRECTION INPUT ;
    USE SIGNAL ;
    PORT
      LAYER M4 ;
        RECT  21.516 13.584 21.6 13.608 ;
    END
  END i[582]
  PIN i[583]
    DIRECTION INPUT ;
    USE SIGNAL ;
    PORT
      LAYER M4 ;
        RECT  21.516 13.68 21.6 13.704 ;
    END
  END i[583]
  PIN i[584]
    DIRECTION INPUT ;
    USE SIGNAL ;
    PORT
      LAYER M4 ;
        RECT  21.516 13.776 21.6 13.8 ;
    END
  END i[584]
  PIN i[585]
    DIRECTION INPUT ;
    USE SIGNAL ;
    PORT
      LAYER M4 ;
        RECT  21.516 13.872 21.6 13.896 ;
    END
  END i[585]
  PIN i[586]
    DIRECTION INPUT ;
    USE SIGNAL ;
    PORT
      LAYER M4 ;
        RECT  21.516 13.968 21.6 13.992 ;
    END
  END i[586]
  PIN i[587]
    DIRECTION INPUT ;
    USE SIGNAL ;
    PORT
      LAYER M4 ;
        RECT  21.516 14.064 21.6 14.088 ;
    END
  END i[587]
  PIN i[588]
    DIRECTION INPUT ;
    USE SIGNAL ;
    PORT
      LAYER M4 ;
        RECT  21.516 14.16 21.6 14.184 ;
    END
  END i[588]
  PIN i[589]
    DIRECTION INPUT ;
    USE SIGNAL ;
    PORT
      LAYER M4 ;
        RECT  21.516 14.256 21.6 14.28 ;
    END
  END i[589]
  PIN i[58]
    DIRECTION INPUT ;
    USE SIGNAL ;
    PORT
      LAYER M4 ;
        RECT  21.516 31.632 21.6 31.656 ;
    END
  END i[58]
  PIN i[590]
    DIRECTION INPUT ;
    USE SIGNAL ;
    PORT
      LAYER M4 ;
        RECT  21.516 14.352 21.6 14.376 ;
    END
  END i[590]
  PIN i[591]
    DIRECTION INPUT ;
    USE SIGNAL ;
    PORT
      LAYER M4 ;
        RECT  21.516 14.448 21.6 14.472 ;
    END
  END i[591]
  PIN i[592]
    DIRECTION INPUT ;
    USE SIGNAL ;
    PORT
      LAYER M4 ;
        RECT  21.516 14.544 21.6 14.568 ;
    END
  END i[592]
  PIN i[593]
    DIRECTION INPUT ;
    USE SIGNAL ;
    PORT
      LAYER M4 ;
        RECT  21.516 14.64 21.6 14.664 ;
    END
  END i[593]
  PIN i[594]
    DIRECTION INPUT ;
    USE SIGNAL ;
    PORT
      LAYER M4 ;
        RECT  21.516 14.736 21.6 14.76 ;
    END
  END i[594]
  PIN i[595]
    DIRECTION INPUT ;
    USE SIGNAL ;
    PORT
      LAYER M4 ;
        RECT  21.516 14.832 21.6 14.856 ;
    END
  END i[595]
  PIN i[596]
    DIRECTION INPUT ;
    USE SIGNAL ;
    PORT
      LAYER M4 ;
        RECT  21.516 14.928 21.6 14.952 ;
    END
  END i[596]
  PIN i[597]
    DIRECTION INPUT ;
    USE SIGNAL ;
    PORT
      LAYER M4 ;
        RECT  21.516 15.024 21.6 15.048 ;
    END
  END i[597]
  PIN i[598]
    DIRECTION INPUT ;
    USE SIGNAL ;
    PORT
      LAYER M4 ;
        RECT  21.516 15.12 21.6 15.144 ;
    END
  END i[598]
  PIN i[599]
    DIRECTION INPUT ;
    USE SIGNAL ;
    PORT
      LAYER M4 ;
        RECT  21.516 15.216 21.6 15.24 ;
    END
  END i[599]
  PIN i[59]
    DIRECTION INPUT ;
    USE SIGNAL ;
    PORT
      LAYER M4 ;
        RECT  21.516 31.728 21.6 31.752 ;
    END
  END i[59]
  PIN i[5]
    DIRECTION INPUT ;
    USE SIGNAL ;
    PORT
      LAYER M4 ;
        RECT  21.516 20.4 21.6 20.424 ;
    END
  END i[5]
  PIN i[600]
    DIRECTION INPUT ;
    USE SIGNAL ;
    PORT
      LAYER M4 ;
        RECT  21.516 15.312 21.6 15.336 ;
    END
  END i[600]
  PIN i[601]
    DIRECTION INPUT ;
    USE SIGNAL ;
    PORT
      LAYER M4 ;
        RECT  21.516 15.408 21.6 15.432 ;
    END
  END i[601]
  PIN i[602]
    DIRECTION INPUT ;
    USE SIGNAL ;
    PORT
      LAYER M4 ;
        RECT  21.516 15.504 21.6 15.528 ;
    END
  END i[602]
  PIN i[603]
    DIRECTION INPUT ;
    USE SIGNAL ;
    PORT
      LAYER M4 ;
        RECT  21.516 15.6 21.6 15.624 ;
    END
  END i[603]
  PIN i[604]
    DIRECTION INPUT ;
    USE SIGNAL ;
    PORT
      LAYER M4 ;
        RECT  21.516 15.696 21.6 15.72 ;
    END
  END i[604]
  PIN i[605]
    DIRECTION INPUT ;
    USE SIGNAL ;
    PORT
      LAYER M4 ;
        RECT  21.516 15.792 21.6 15.816 ;
    END
  END i[605]
  PIN i[606]
    DIRECTION INPUT ;
    USE SIGNAL ;
    PORT
      LAYER M4 ;
        RECT  21.516 15.888 21.6 15.912 ;
    END
  END i[606]
  PIN i[607]
    DIRECTION INPUT ;
    USE SIGNAL ;
    PORT
      LAYER M4 ;
        RECT  21.516 15.984 21.6 16.008 ;
    END
  END i[607]
  PIN i[608]
    DIRECTION INPUT ;
    USE SIGNAL ;
    PORT
      LAYER M4 ;
        RECT  21.516 61.392 21.6 61.416 ;
    END
  END i[608]
  PIN i[609]
    DIRECTION INPUT ;
    USE SIGNAL ;
    PORT
      LAYER M4 ;
        RECT  21.516 61.488 21.6 61.512 ;
    END
  END i[609]
  PIN i[60]
    DIRECTION INPUT ;
    USE SIGNAL ;
    PORT
      LAYER M4 ;
        RECT  21.516 31.824 21.6 31.848 ;
    END
  END i[60]
  PIN i[610]
    DIRECTION INPUT ;
    USE SIGNAL ;
    PORT
      LAYER M4 ;
        RECT  21.516 61.584 21.6 61.608 ;
    END
  END i[610]
  PIN i[611]
    DIRECTION INPUT ;
    USE SIGNAL ;
    PORT
      LAYER M4 ;
        RECT  21.516 61.68 21.6 61.704 ;
    END
  END i[611]
  PIN i[612]
    DIRECTION INPUT ;
    USE SIGNAL ;
    PORT
      LAYER M4 ;
        RECT  21.516 61.776 21.6 61.8 ;
    END
  END i[612]
  PIN i[613]
    DIRECTION INPUT ;
    USE SIGNAL ;
    PORT
      LAYER M4 ;
        RECT  21.516 61.872 21.6 61.896 ;
    END
  END i[613]
  PIN i[614]
    DIRECTION INPUT ;
    USE SIGNAL ;
    PORT
      LAYER M4 ;
        RECT  21.516 61.968 21.6 61.992 ;
    END
  END i[614]
  PIN i[615]
    DIRECTION INPUT ;
    USE SIGNAL ;
    PORT
      LAYER M4 ;
        RECT  21.516 62.064 21.6 62.088 ;
    END
  END i[615]
  PIN i[616]
    DIRECTION INPUT ;
    USE SIGNAL ;
    PORT
      LAYER M4 ;
        RECT  21.516 62.16 21.6 62.184 ;
    END
  END i[616]
  PIN i[617]
    DIRECTION INPUT ;
    USE SIGNAL ;
    PORT
      LAYER M4 ;
        RECT  21.516 62.256 21.6 62.28 ;
    END
  END i[617]
  PIN i[618]
    DIRECTION INPUT ;
    USE SIGNAL ;
    PORT
      LAYER M4 ;
        RECT  21.516 62.352 21.6 62.376 ;
    END
  END i[618]
  PIN i[619]
    DIRECTION INPUT ;
    USE SIGNAL ;
    PORT
      LAYER M4 ;
        RECT  21.516 62.448 21.6 62.472 ;
    END
  END i[619]
  PIN i[61]
    DIRECTION INPUT ;
    USE SIGNAL ;
    PORT
      LAYER M4 ;
        RECT  21.516 31.92 21.6 31.944 ;
    END
  END i[61]
  PIN i[620]
    DIRECTION INPUT ;
    USE SIGNAL ;
    PORT
      LAYER M4 ;
        RECT  21.516 62.544 21.6 62.568 ;
    END
  END i[620]
  PIN i[621]
    DIRECTION INPUT ;
    USE SIGNAL ;
    PORT
      LAYER M4 ;
        RECT  21.516 62.64 21.6 62.664 ;
    END
  END i[621]
  PIN i[622]
    DIRECTION INPUT ;
    USE SIGNAL ;
    PORT
      LAYER M4 ;
        RECT  21.516 62.736 21.6 62.76 ;
    END
  END i[622]
  PIN i[623]
    DIRECTION INPUT ;
    USE SIGNAL ;
    PORT
      LAYER M4 ;
        RECT  21.516 62.832 21.6 62.856 ;
    END
  END i[623]
  PIN i[62]
    DIRECTION INPUT ;
    USE SIGNAL ;
    PORT
      LAYER M4 ;
        RECT  21.516 32.016 21.6 32.04 ;
    END
  END i[62]
  PIN i[63]
    DIRECTION INPUT ;
    USE SIGNAL ;
    PORT
      LAYER M4 ;
        RECT  21.516 32.112 21.6 32.136 ;
    END
  END i[63]
  PIN i[64]
    DIRECTION INPUT ;
    USE SIGNAL ;
    PORT
      LAYER M4 ;
        RECT  21.516 22.992 21.6 23.016 ;
    END
  END i[64]
  PIN i[65]
    DIRECTION INPUT ;
    USE SIGNAL ;
    PORT
      LAYER M4 ;
        RECT  21.516 23.088 21.6 23.112 ;
    END
  END i[65]
  PIN i[66]
    DIRECTION INPUT ;
    USE SIGNAL ;
    PORT
      LAYER M4 ;
        RECT  21.516 23.184 21.6 23.208 ;
    END
  END i[66]
  PIN i[67]
    DIRECTION INPUT ;
    USE SIGNAL ;
    PORT
      LAYER M4 ;
        RECT  21.516 23.28 21.6 23.304 ;
    END
  END i[67]
  PIN i[68]
    DIRECTION INPUT ;
    USE SIGNAL ;
    PORT
      LAYER M4 ;
        RECT  21.516 23.376 21.6 23.4 ;
    END
  END i[68]
  PIN i[69]
    DIRECTION INPUT ;
    USE SIGNAL ;
    PORT
      LAYER M4 ;
        RECT  21.516 23.472 21.6 23.496 ;
    END
  END i[69]
  PIN i[6]
    DIRECTION INPUT ;
    USE SIGNAL ;
    PORT
      LAYER M4 ;
        RECT  21.516 20.496 21.6 20.52 ;
    END
  END i[6]
  PIN i[70]
    DIRECTION INPUT ;
    USE SIGNAL ;
    PORT
      LAYER M4 ;
        RECT  21.516 23.568 21.6 23.592 ;
    END
  END i[70]
  PIN i[71]
    DIRECTION INPUT ;
    USE SIGNAL ;
    PORT
      LAYER M4 ;
        RECT  21.516 23.664 21.6 23.688 ;
    END
  END i[71]
  PIN i[72]
    DIRECTION INPUT ;
    USE SIGNAL ;
    PORT
      LAYER M4 ;
        RECT  21.516 23.76 21.6 23.784 ;
    END
  END i[72]
  PIN i[73]
    DIRECTION INPUT ;
    USE SIGNAL ;
    PORT
      LAYER M4 ;
        RECT  21.516 23.856 21.6 23.88 ;
    END
  END i[73]
  PIN i[74]
    DIRECTION INPUT ;
    USE SIGNAL ;
    PORT
      LAYER M4 ;
        RECT  21.516 23.952 21.6 23.976 ;
    END
  END i[74]
  PIN i[75]
    DIRECTION INPUT ;
    USE SIGNAL ;
    PORT
      LAYER M4 ;
        RECT  21.516 24.048 21.6 24.072 ;
    END
  END i[75]
  PIN i[76]
    DIRECTION INPUT ;
    USE SIGNAL ;
    PORT
      LAYER M4 ;
        RECT  21.516 24.144 21.6 24.168 ;
    END
  END i[76]
  PIN i[77]
    DIRECTION INPUT ;
    USE SIGNAL ;
    PORT
      LAYER M4 ;
        RECT  21.516 24.24 21.6 24.264 ;
    END
  END i[77]
  PIN i[78]
    DIRECTION INPUT ;
    USE SIGNAL ;
    PORT
      LAYER M4 ;
        RECT  21.516 24.336 21.6 24.36 ;
    END
  END i[78]
  PIN i[79]
    DIRECTION INPUT ;
    USE SIGNAL ;
    PORT
      LAYER M4 ;
        RECT  21.516 24.432 21.6 24.456 ;
    END
  END i[79]
  PIN i[7]
    DIRECTION INPUT ;
    USE SIGNAL ;
    PORT
      LAYER M4 ;
        RECT  21.516 20.592 21.6 20.616 ;
    END
  END i[7]
  PIN i[80]
    DIRECTION INPUT ;
    USE SIGNAL ;
    PORT
      LAYER M4 ;
        RECT  21.516 24.528 21.6 24.552 ;
    END
  END i[80]
  PIN i[81]
    DIRECTION INPUT ;
    USE SIGNAL ;
    PORT
      LAYER M4 ;
        RECT  21.516 24.624 21.6 24.648 ;
    END
  END i[81]
  PIN i[82]
    DIRECTION INPUT ;
    USE SIGNAL ;
    PORT
      LAYER M4 ;
        RECT  21.516 24.72 21.6 24.744 ;
    END
  END i[82]
  PIN i[83]
    DIRECTION INPUT ;
    USE SIGNAL ;
    PORT
      LAYER M4 ;
        RECT  21.516 24.816 21.6 24.84 ;
    END
  END i[83]
  PIN i[84]
    DIRECTION INPUT ;
    USE SIGNAL ;
    PORT
      LAYER M4 ;
        RECT  21.516 24.912 21.6 24.936 ;
    END
  END i[84]
  PIN i[85]
    DIRECTION INPUT ;
    USE SIGNAL ;
    PORT
      LAYER M4 ;
        RECT  21.516 25.008 21.6 25.032 ;
    END
  END i[85]
  PIN i[86]
    DIRECTION INPUT ;
    USE SIGNAL ;
    PORT
      LAYER M4 ;
        RECT  21.516 25.104 21.6 25.128 ;
    END
  END i[86]
  PIN i[87]
    DIRECTION INPUT ;
    USE SIGNAL ;
    PORT
      LAYER M4 ;
        RECT  21.516 25.2 21.6 25.224 ;
    END
  END i[87]
  PIN i[88]
    DIRECTION INPUT ;
    USE SIGNAL ;
    PORT
      LAYER M4 ;
        RECT  21.516 25.296 21.6 25.32 ;
    END
  END i[88]
  PIN i[89]
    DIRECTION INPUT ;
    USE SIGNAL ;
    PORT
      LAYER M4 ;
        RECT  21.516 25.392 21.6 25.416 ;
    END
  END i[89]
  PIN i[8]
    DIRECTION INPUT ;
    USE SIGNAL ;
    PORT
      LAYER M4 ;
        RECT  21.516 20.688 21.6 20.712 ;
    END
  END i[8]
  PIN i[90]
    DIRECTION INPUT ;
    USE SIGNAL ;
    PORT
      LAYER M4 ;
        RECT  21.516 25.488 21.6 25.512 ;
    END
  END i[90]
  PIN i[91]
    DIRECTION INPUT ;
    USE SIGNAL ;
    PORT
      LAYER M4 ;
        RECT  21.516 25.584 21.6 25.608 ;
    END
  END i[91]
  PIN i[92]
    DIRECTION INPUT ;
    USE SIGNAL ;
    PORT
      LAYER M4 ;
        RECT  21.516 25.68 21.6 25.704 ;
    END
  END i[92]
  PIN i[93]
    DIRECTION INPUT ;
    USE SIGNAL ;
    PORT
      LAYER M4 ;
        RECT  21.516 25.776 21.6 25.8 ;
    END
  END i[93]
  PIN i[94]
    DIRECTION INPUT ;
    USE SIGNAL ;
    PORT
      LAYER M4 ;
        RECT  21.516 25.872 21.6 25.896 ;
    END
  END i[94]
  PIN i[95]
    DIRECTION INPUT ;
    USE SIGNAL ;
    PORT
      LAYER M4 ;
        RECT  21.516 25.968 21.6 25.992 ;
    END
  END i[95]
  PIN i[96]
    DIRECTION INPUT ;
    USE SIGNAL ;
    PORT
      LAYER M4 ;
        RECT  21.516 9.936 21.6 9.96 ;
    END
  END i[96]
  PIN i[97]
    DIRECTION INPUT ;
    USE SIGNAL ;
    PORT
      LAYER M4 ;
        RECT  21.516 10.032 21.6 10.056 ;
    END
  END i[97]
  PIN i[98]
    DIRECTION INPUT ;
    USE SIGNAL ;
    PORT
      LAYER M4 ;
        RECT  21.516 10.128 21.6 10.152 ;
    END
  END i[98]
  PIN i[99]
    DIRECTION INPUT ;
    USE SIGNAL ;
    PORT
      LAYER M4 ;
        RECT  21.516 10.224 21.6 10.248 ;
    END
  END i[99]
  PIN i[9]
    DIRECTION INPUT ;
    USE SIGNAL ;
    PORT
      LAYER M4 ;
        RECT  21.516 20.784 21.6 20.808 ;
    END
  END i[9]
  PIN o[0]
    DIRECTION OUTPUT ;
    USE SIGNAL ;
    PORT
      LAYER M4 ;
        RECT  0 13.392 0.084 13.416 ;
    END
  END o[0]
  PIN o[100]
    DIRECTION OUTPUT ;
    USE SIGNAL ;
    PORT
      LAYER M4 ;
        RECT  0 19.92 0.084 19.944 ;
    END
  END o[100]
  PIN o[101]
    DIRECTION OUTPUT ;
    USE SIGNAL ;
    PORT
      LAYER M4 ;
        RECT  0 20.016 0.084 20.04 ;
    END
  END o[101]
  PIN o[102]
    DIRECTION OUTPUT ;
    USE SIGNAL ;
    PORT
      LAYER M4 ;
        RECT  0 20.112 0.084 20.136 ;
    END
  END o[102]
  PIN o[103]
    DIRECTION OUTPUT ;
    USE SIGNAL ;
    PORT
      LAYER M4 ;
        RECT  0 20.208 0.084 20.232 ;
    END
  END o[103]
  PIN o[104]
    DIRECTION OUTPUT ;
    USE SIGNAL ;
    PORT
      LAYER M4 ;
        RECT  0 20.304 0.084 20.328 ;
    END
  END o[104]
  PIN o[105]
    DIRECTION OUTPUT ;
    USE SIGNAL ;
    PORT
      LAYER M4 ;
        RECT  0 20.4 0.084 20.424 ;
    END
  END o[105]
  PIN o[106]
    DIRECTION OUTPUT ;
    USE SIGNAL ;
    PORT
      LAYER M4 ;
        RECT  0 20.496 0.084 20.52 ;
    END
  END o[106]
  PIN o[107]
    DIRECTION OUTPUT ;
    USE SIGNAL ;
    PORT
      LAYER M4 ;
        RECT  0 20.592 0.084 20.616 ;
    END
  END o[107]
  PIN o[108]
    DIRECTION OUTPUT ;
    USE SIGNAL ;
    PORT
      LAYER M4 ;
        RECT  0 20.688 0.084 20.712 ;
    END
  END o[108]
  PIN o[109]
    DIRECTION OUTPUT ;
    USE SIGNAL ;
    PORT
      LAYER M4 ;
        RECT  0 20.784 0.084 20.808 ;
    END
  END o[109]
  PIN o[10]
    DIRECTION OUTPUT ;
    USE SIGNAL ;
    PORT
      LAYER M4 ;
        RECT  0 14.352 0.084 14.376 ;
    END
  END o[10]
  PIN o[110]
    DIRECTION OUTPUT ;
    USE SIGNAL ;
    PORT
      LAYER M4 ;
        RECT  0 20.88 0.084 20.904 ;
    END
  END o[110]
  PIN o[111]
    DIRECTION OUTPUT ;
    USE SIGNAL ;
    PORT
      LAYER M4 ;
        RECT  0 20.976 0.084 21 ;
    END
  END o[111]
  PIN o[112]
    DIRECTION OUTPUT ;
    USE SIGNAL ;
    PORT
      LAYER M4 ;
        RECT  0 21.072 0.084 21.096 ;
    END
  END o[112]
  PIN o[113]
    DIRECTION OUTPUT ;
    USE SIGNAL ;
    PORT
      LAYER M4 ;
        RECT  0 21.168 0.084 21.192 ;
    END
  END o[113]
  PIN o[114]
    DIRECTION OUTPUT ;
    USE SIGNAL ;
    PORT
      LAYER M4 ;
        RECT  0 21.264 0.084 21.288 ;
    END
  END o[114]
  PIN o[115]
    DIRECTION OUTPUT ;
    USE SIGNAL ;
    PORT
      LAYER M4 ;
        RECT  0 21.36 0.084 21.384 ;
    END
  END o[115]
  PIN o[116]
    DIRECTION OUTPUT ;
    USE SIGNAL ;
    PORT
      LAYER M4 ;
        RECT  0 21.456 0.084 21.48 ;
    END
  END o[116]
  PIN o[117]
    DIRECTION OUTPUT ;
    USE SIGNAL ;
    PORT
      LAYER M4 ;
        RECT  0 21.552 0.084 21.576 ;
    END
  END o[117]
  PIN o[118]
    DIRECTION OUTPUT ;
    USE SIGNAL ;
    PORT
      LAYER M4 ;
        RECT  0 21.648 0.084 21.672 ;
    END
  END o[118]
  PIN o[119]
    DIRECTION OUTPUT ;
    USE SIGNAL ;
    PORT
      LAYER M4 ;
        RECT  0 21.744 0.084 21.768 ;
    END
  END o[119]
  PIN o[11]
    DIRECTION OUTPUT ;
    USE SIGNAL ;
    PORT
      LAYER M4 ;
        RECT  0 14.448 0.084 14.472 ;
    END
  END o[11]
  PIN o[120]
    DIRECTION OUTPUT ;
    USE SIGNAL ;
    PORT
      LAYER M4 ;
        RECT  0 21.84 0.084 21.864 ;
    END
  END o[120]
  PIN o[121]
    DIRECTION OUTPUT ;
    USE SIGNAL ;
    PORT
      LAYER M4 ;
        RECT  0 21.936 0.084 21.96 ;
    END
  END o[121]
  PIN o[122]
    DIRECTION OUTPUT ;
    USE SIGNAL ;
    PORT
      LAYER M4 ;
        RECT  0 22.032 0.084 22.056 ;
    END
  END o[122]
  PIN o[123]
    DIRECTION OUTPUT ;
    USE SIGNAL ;
    PORT
      LAYER M4 ;
        RECT  0 22.128 0.084 22.152 ;
    END
  END o[123]
  PIN o[124]
    DIRECTION OUTPUT ;
    USE SIGNAL ;
    PORT
      LAYER M4 ;
        RECT  0 22.224 0.084 22.248 ;
    END
  END o[124]
  PIN o[125]
    DIRECTION OUTPUT ;
    USE SIGNAL ;
    PORT
      LAYER M4 ;
        RECT  0 22.32 0.084 22.344 ;
    END
  END o[125]
  PIN o[126]
    DIRECTION OUTPUT ;
    USE SIGNAL ;
    PORT
      LAYER M4 ;
        RECT  0 22.416 0.084 22.44 ;
    END
  END o[126]
  PIN o[127]
    DIRECTION OUTPUT ;
    USE SIGNAL ;
    PORT
      LAYER M4 ;
        RECT  0 22.512 0.084 22.536 ;
    END
  END o[127]
  PIN o[128]
    DIRECTION OUTPUT ;
    USE SIGNAL ;
    PORT
      LAYER M4 ;
        RECT  0 7.248 0.084 7.272 ;
    END
  END o[128]
  PIN o[129]
    DIRECTION OUTPUT ;
    USE SIGNAL ;
    PORT
      LAYER M4 ;
        RECT  0 7.344 0.084 7.368 ;
    END
  END o[129]
  PIN o[12]
    DIRECTION OUTPUT ;
    USE SIGNAL ;
    PORT
      LAYER M4 ;
        RECT  0 14.544 0.084 14.568 ;
    END
  END o[12]
  PIN o[130]
    DIRECTION OUTPUT ;
    USE SIGNAL ;
    PORT
      LAYER M4 ;
        RECT  0 7.44 0.084 7.464 ;
    END
  END o[130]
  PIN o[131]
    DIRECTION OUTPUT ;
    USE SIGNAL ;
    PORT
      LAYER M4 ;
        RECT  0 7.536 0.084 7.56 ;
    END
  END o[131]
  PIN o[132]
    DIRECTION OUTPUT ;
    USE SIGNAL ;
    PORT
      LAYER M4 ;
        RECT  0 7.632 0.084 7.656 ;
    END
  END o[132]
  PIN o[133]
    DIRECTION OUTPUT ;
    USE SIGNAL ;
    PORT
      LAYER M4 ;
        RECT  0 7.728 0.084 7.752 ;
    END
  END o[133]
  PIN o[134]
    DIRECTION OUTPUT ;
    USE SIGNAL ;
    PORT
      LAYER M4 ;
        RECT  0 7.824 0.084 7.848 ;
    END
  END o[134]
  PIN o[135]
    DIRECTION OUTPUT ;
    USE SIGNAL ;
    PORT
      LAYER M4 ;
        RECT  0 7.92 0.084 7.944 ;
    END
  END o[135]
  PIN o[136]
    DIRECTION OUTPUT ;
    USE SIGNAL ;
    PORT
      LAYER M4 ;
        RECT  0 8.016 0.084 8.04 ;
    END
  END o[136]
  PIN o[137]
    DIRECTION OUTPUT ;
    USE SIGNAL ;
    PORT
      LAYER M4 ;
        RECT  0 8.112 0.084 8.136 ;
    END
  END o[137]
  PIN o[138]
    DIRECTION OUTPUT ;
    USE SIGNAL ;
    PORT
      LAYER M4 ;
        RECT  0 8.208 0.084 8.232 ;
    END
  END o[138]
  PIN o[139]
    DIRECTION OUTPUT ;
    USE SIGNAL ;
    PORT
      LAYER M4 ;
        RECT  0 8.304 0.084 8.328 ;
    END
  END o[139]
  PIN o[13]
    DIRECTION OUTPUT ;
    USE SIGNAL ;
    PORT
      LAYER M4 ;
        RECT  0 14.64 0.084 14.664 ;
    END
  END o[13]
  PIN o[140]
    DIRECTION OUTPUT ;
    USE SIGNAL ;
    PORT
      LAYER M4 ;
        RECT  0 8.4 0.084 8.424 ;
    END
  END o[140]
  PIN o[141]
    DIRECTION OUTPUT ;
    USE SIGNAL ;
    PORT
      LAYER M4 ;
        RECT  0 8.496 0.084 8.52 ;
    END
  END o[141]
  PIN o[142]
    DIRECTION OUTPUT ;
    USE SIGNAL ;
    PORT
      LAYER M4 ;
        RECT  0 8.592 0.084 8.616 ;
    END
  END o[142]
  PIN o[143]
    DIRECTION OUTPUT ;
    USE SIGNAL ;
    PORT
      LAYER M4 ;
        RECT  0 8.688 0.084 8.712 ;
    END
  END o[143]
  PIN o[144]
    DIRECTION OUTPUT ;
    USE SIGNAL ;
    PORT
      LAYER M4 ;
        RECT  0 8.784 0.084 8.808 ;
    END
  END o[144]
  PIN o[145]
    DIRECTION OUTPUT ;
    USE SIGNAL ;
    PORT
      LAYER M4 ;
        RECT  0 8.88 0.084 8.904 ;
    END
  END o[145]
  PIN o[146]
    DIRECTION OUTPUT ;
    USE SIGNAL ;
    PORT
      LAYER M4 ;
        RECT  0 8.976 0.084 9 ;
    END
  END o[146]
  PIN o[147]
    DIRECTION OUTPUT ;
    USE SIGNAL ;
    PORT
      LAYER M4 ;
        RECT  0 9.072 0.084 9.096 ;
    END
  END o[147]
  PIN o[148]
    DIRECTION OUTPUT ;
    USE SIGNAL ;
    PORT
      LAYER M4 ;
        RECT  0 9.168 0.084 9.192 ;
    END
  END o[148]
  PIN o[149]
    DIRECTION OUTPUT ;
    USE SIGNAL ;
    PORT
      LAYER M4 ;
        RECT  0 9.264 0.084 9.288 ;
    END
  END o[149]
  PIN o[14]
    DIRECTION OUTPUT ;
    USE SIGNAL ;
    PORT
      LAYER M4 ;
        RECT  0 14.736 0.084 14.76 ;
    END
  END o[14]
  PIN o[150]
    DIRECTION OUTPUT ;
    USE SIGNAL ;
    PORT
      LAYER M4 ;
        RECT  0 9.36 0.084 9.384 ;
    END
  END o[150]
  PIN o[151]
    DIRECTION OUTPUT ;
    USE SIGNAL ;
    PORT
      LAYER M4 ;
        RECT  0 9.456 0.084 9.48 ;
    END
  END o[151]
  PIN o[152]
    DIRECTION OUTPUT ;
    USE SIGNAL ;
    PORT
      LAYER M4 ;
        RECT  0 9.552 0.084 9.576 ;
    END
  END o[152]
  PIN o[153]
    DIRECTION OUTPUT ;
    USE SIGNAL ;
    PORT
      LAYER M4 ;
        RECT  0 9.648 0.084 9.672 ;
    END
  END o[153]
  PIN o[154]
    DIRECTION OUTPUT ;
    USE SIGNAL ;
    PORT
      LAYER M4 ;
        RECT  0 9.744 0.084 9.768 ;
    END
  END o[154]
  PIN o[155]
    DIRECTION OUTPUT ;
    USE SIGNAL ;
    PORT
      LAYER M4 ;
        RECT  0 9.84 0.084 9.864 ;
    END
  END o[155]
  PIN o[156]
    DIRECTION OUTPUT ;
    USE SIGNAL ;
    PORT
      LAYER M4 ;
        RECT  0 9.936 0.084 9.96 ;
    END
  END o[156]
  PIN o[157]
    DIRECTION OUTPUT ;
    USE SIGNAL ;
    PORT
      LAYER M4 ;
        RECT  0 10.032 0.084 10.056 ;
    END
  END o[157]
  PIN o[158]
    DIRECTION OUTPUT ;
    USE SIGNAL ;
    PORT
      LAYER M4 ;
        RECT  0 10.128 0.084 10.152 ;
    END
  END o[158]
  PIN o[159]
    DIRECTION OUTPUT ;
    USE SIGNAL ;
    PORT
      LAYER M4 ;
        RECT  0 10.224 0.084 10.248 ;
    END
  END o[159]
  PIN o[15]
    DIRECTION OUTPUT ;
    USE SIGNAL ;
    PORT
      LAYER M4 ;
        RECT  0 14.832 0.084 14.856 ;
    END
  END o[15]
  PIN o[160]
    DIRECTION OUTPUT ;
    USE SIGNAL ;
    PORT
      LAYER M4 ;
        RECT  0 10.32 0.084 10.344 ;
    END
  END o[160]
  PIN o[161]
    DIRECTION OUTPUT ;
    USE SIGNAL ;
    PORT
      LAYER M4 ;
        RECT  0 10.416 0.084 10.44 ;
    END
  END o[161]
  PIN o[162]
    DIRECTION OUTPUT ;
    USE SIGNAL ;
    PORT
      LAYER M4 ;
        RECT  0 10.512 0.084 10.536 ;
    END
  END o[162]
  PIN o[163]
    DIRECTION OUTPUT ;
    USE SIGNAL ;
    PORT
      LAYER M4 ;
        RECT  0 10.608 0.084 10.632 ;
    END
  END o[163]
  PIN o[164]
    DIRECTION OUTPUT ;
    USE SIGNAL ;
    PORT
      LAYER M4 ;
        RECT  0 10.704 0.084 10.728 ;
    END
  END o[164]
  PIN o[165]
    DIRECTION OUTPUT ;
    USE SIGNAL ;
    PORT
      LAYER M4 ;
        RECT  0 10.8 0.084 10.824 ;
    END
  END o[165]
  PIN o[166]
    DIRECTION OUTPUT ;
    USE SIGNAL ;
    PORT
      LAYER M4 ;
        RECT  0 10.896 0.084 10.92 ;
    END
  END o[166]
  PIN o[167]
    DIRECTION OUTPUT ;
    USE SIGNAL ;
    PORT
      LAYER M4 ;
        RECT  0 10.992 0.084 11.016 ;
    END
  END o[167]
  PIN o[168]
    DIRECTION OUTPUT ;
    USE SIGNAL ;
    PORT
      LAYER M4 ;
        RECT  0 11.088 0.084 11.112 ;
    END
  END o[168]
  PIN o[169]
    DIRECTION OUTPUT ;
    USE SIGNAL ;
    PORT
      LAYER M4 ;
        RECT  0 11.184 0.084 11.208 ;
    END
  END o[169]
  PIN o[16]
    DIRECTION OUTPUT ;
    USE SIGNAL ;
    PORT
      LAYER M4 ;
        RECT  0 14.928 0.084 14.952 ;
    END
  END o[16]
  PIN o[170]
    DIRECTION OUTPUT ;
    USE SIGNAL ;
    PORT
      LAYER M4 ;
        RECT  0 11.28 0.084 11.304 ;
    END
  END o[170]
  PIN o[171]
    DIRECTION OUTPUT ;
    USE SIGNAL ;
    PORT
      LAYER M4 ;
        RECT  0 11.376 0.084 11.4 ;
    END
  END o[171]
  PIN o[172]
    DIRECTION OUTPUT ;
    USE SIGNAL ;
    PORT
      LAYER M4 ;
        RECT  0 11.472 0.084 11.496 ;
    END
  END o[172]
  PIN o[173]
    DIRECTION OUTPUT ;
    USE SIGNAL ;
    PORT
      LAYER M4 ;
        RECT  0 11.568 0.084 11.592 ;
    END
  END o[173]
  PIN o[174]
    DIRECTION OUTPUT ;
    USE SIGNAL ;
    PORT
      LAYER M4 ;
        RECT  0 11.664 0.084 11.688 ;
    END
  END o[174]
  PIN o[175]
    DIRECTION OUTPUT ;
    USE SIGNAL ;
    PORT
      LAYER M4 ;
        RECT  0 11.76 0.084 11.784 ;
    END
  END o[175]
  PIN o[176]
    DIRECTION OUTPUT ;
    USE SIGNAL ;
    PORT
      LAYER M4 ;
        RECT  0 11.856 0.084 11.88 ;
    END
  END o[176]
  PIN o[177]
    DIRECTION OUTPUT ;
    USE SIGNAL ;
    PORT
      LAYER M4 ;
        RECT  0 11.952 0.084 11.976 ;
    END
  END o[177]
  PIN o[178]
    DIRECTION OUTPUT ;
    USE SIGNAL ;
    PORT
      LAYER M4 ;
        RECT  0 12.048 0.084 12.072 ;
    END
  END o[178]
  PIN o[179]
    DIRECTION OUTPUT ;
    USE SIGNAL ;
    PORT
      LAYER M4 ;
        RECT  0 12.144 0.084 12.168 ;
    END
  END o[179]
  PIN o[17]
    DIRECTION OUTPUT ;
    USE SIGNAL ;
    PORT
      LAYER M4 ;
        RECT  0 15.024 0.084 15.048 ;
    END
  END o[17]
  PIN o[180]
    DIRECTION OUTPUT ;
    USE SIGNAL ;
    PORT
      LAYER M4 ;
        RECT  0 12.24 0.084 12.264 ;
    END
  END o[180]
  PIN o[181]
    DIRECTION OUTPUT ;
    USE SIGNAL ;
    PORT
      LAYER M4 ;
        RECT  0 12.336 0.084 12.36 ;
    END
  END o[181]
  PIN o[182]
    DIRECTION OUTPUT ;
    USE SIGNAL ;
    PORT
      LAYER M4 ;
        RECT  0 12.432 0.084 12.456 ;
    END
  END o[182]
  PIN o[183]
    DIRECTION OUTPUT ;
    USE SIGNAL ;
    PORT
      LAYER M4 ;
        RECT  0 12.528 0.084 12.552 ;
    END
  END o[183]
  PIN o[184]
    DIRECTION OUTPUT ;
    USE SIGNAL ;
    PORT
      LAYER M4 ;
        RECT  0 12.624 0.084 12.648 ;
    END
  END o[184]
  PIN o[185]
    DIRECTION OUTPUT ;
    USE SIGNAL ;
    PORT
      LAYER M4 ;
        RECT  0 12.72 0.084 12.744 ;
    END
  END o[185]
  PIN o[186]
    DIRECTION OUTPUT ;
    USE SIGNAL ;
    PORT
      LAYER M4 ;
        RECT  0 12.816 0.084 12.84 ;
    END
  END o[186]
  PIN o[187]
    DIRECTION OUTPUT ;
    USE SIGNAL ;
    PORT
      LAYER M4 ;
        RECT  0 12.912 0.084 12.936 ;
    END
  END o[187]
  PIN o[188]
    DIRECTION OUTPUT ;
    USE SIGNAL ;
    PORT
      LAYER M4 ;
        RECT  0 13.008 0.084 13.032 ;
    END
  END o[188]
  PIN o[189]
    DIRECTION OUTPUT ;
    USE SIGNAL ;
    PORT
      LAYER M4 ;
        RECT  0 13.104 0.084 13.128 ;
    END
  END o[189]
  PIN o[18]
    DIRECTION OUTPUT ;
    USE SIGNAL ;
    PORT
      LAYER M4 ;
        RECT  0 15.12 0.084 15.144 ;
    END
  END o[18]
  PIN o[190]
    DIRECTION OUTPUT ;
    USE SIGNAL ;
    PORT
      LAYER M4 ;
        RECT  0 13.2 0.084 13.224 ;
    END
  END o[190]
  PIN o[191]
    DIRECTION OUTPUT ;
    USE SIGNAL ;
    PORT
      LAYER M4 ;
        RECT  0 13.296 0.084 13.32 ;
    END
  END o[191]
  PIN o[192]
    DIRECTION OUTPUT ;
    USE SIGNAL ;
    PORT
      LAYER M4 ;
        RECT  0 29.52 0.084 29.544 ;
    END
  END o[192]
  PIN o[193]
    DIRECTION OUTPUT ;
    USE SIGNAL ;
    PORT
      LAYER M4 ;
        RECT  0 29.616 0.084 29.64 ;
    END
  END o[193]
  PIN o[194]
    DIRECTION OUTPUT ;
    USE SIGNAL ;
    PORT
      LAYER M4 ;
        RECT  0 29.712 0.084 29.736 ;
    END
  END o[194]
  PIN o[195]
    DIRECTION OUTPUT ;
    USE SIGNAL ;
    PORT
      LAYER M4 ;
        RECT  0 29.808 0.084 29.832 ;
    END
  END o[195]
  PIN o[196]
    DIRECTION OUTPUT ;
    USE SIGNAL ;
    PORT
      LAYER M4 ;
        RECT  0 29.904 0.084 29.928 ;
    END
  END o[196]
  PIN o[197]
    DIRECTION OUTPUT ;
    USE SIGNAL ;
    PORT
      LAYER M4 ;
        RECT  0 30 0.084 30.024 ;
    END
  END o[197]
  PIN o[198]
    DIRECTION OUTPUT ;
    USE SIGNAL ;
    PORT
      LAYER M4 ;
        RECT  0 30.096 0.084 30.12 ;
    END
  END o[198]
  PIN o[199]
    DIRECTION OUTPUT ;
    USE SIGNAL ;
    PORT
      LAYER M4 ;
        RECT  0 30.192 0.084 30.216 ;
    END
  END o[199]
  PIN o[19]
    DIRECTION OUTPUT ;
    USE SIGNAL ;
    PORT
      LAYER M4 ;
        RECT  0 15.216 0.084 15.24 ;
    END
  END o[19]
  PIN o[1]
    DIRECTION OUTPUT ;
    USE SIGNAL ;
    PORT
      LAYER M4 ;
        RECT  0 13.488 0.084 13.512 ;
    END
  END o[1]
  PIN o[200]
    DIRECTION OUTPUT ;
    USE SIGNAL ;
    PORT
      LAYER M4 ;
        RECT  0 30.288 0.084 30.312 ;
    END
  END o[200]
  PIN o[201]
    DIRECTION OUTPUT ;
    USE SIGNAL ;
    PORT
      LAYER M4 ;
        RECT  0 30.384 0.084 30.408 ;
    END
  END o[201]
  PIN o[202]
    DIRECTION OUTPUT ;
    USE SIGNAL ;
    PORT
      LAYER M4 ;
        RECT  0 30.48 0.084 30.504 ;
    END
  END o[202]
  PIN o[203]
    DIRECTION OUTPUT ;
    USE SIGNAL ;
    PORT
      LAYER M4 ;
        RECT  0 30.576 0.084 30.6 ;
    END
  END o[203]
  PIN o[204]
    DIRECTION OUTPUT ;
    USE SIGNAL ;
    PORT
      LAYER M4 ;
        RECT  0 30.672 0.084 30.696 ;
    END
  END o[204]
  PIN o[205]
    DIRECTION OUTPUT ;
    USE SIGNAL ;
    PORT
      LAYER M4 ;
        RECT  0 30.768 0.084 30.792 ;
    END
  END o[205]
  PIN o[206]
    DIRECTION OUTPUT ;
    USE SIGNAL ;
    PORT
      LAYER M4 ;
        RECT  0 30.864 0.084 30.888 ;
    END
  END o[206]
  PIN o[207]
    DIRECTION OUTPUT ;
    USE SIGNAL ;
    PORT
      LAYER M4 ;
        RECT  0 30.96 0.084 30.984 ;
    END
  END o[207]
  PIN o[208]
    DIRECTION OUTPUT ;
    USE SIGNAL ;
    PORT
      LAYER M4 ;
        RECT  0 31.056 0.084 31.08 ;
    END
  END o[208]
  PIN o[209]
    DIRECTION OUTPUT ;
    USE SIGNAL ;
    PORT
      LAYER M4 ;
        RECT  0 31.152 0.084 31.176 ;
    END
  END o[209]
  PIN o[20]
    DIRECTION OUTPUT ;
    USE SIGNAL ;
    PORT
      LAYER M4 ;
        RECT  0 15.312 0.084 15.336 ;
    END
  END o[20]
  PIN o[210]
    DIRECTION OUTPUT ;
    USE SIGNAL ;
    PORT
      LAYER M4 ;
        RECT  0 31.248 0.084 31.272 ;
    END
  END o[210]
  PIN o[211]
    DIRECTION OUTPUT ;
    USE SIGNAL ;
    PORT
      LAYER M4 ;
        RECT  0 31.344 0.084 31.368 ;
    END
  END o[211]
  PIN o[212]
    DIRECTION OUTPUT ;
    USE SIGNAL ;
    PORT
      LAYER M4 ;
        RECT  0 31.44 0.084 31.464 ;
    END
  END o[212]
  PIN o[213]
    DIRECTION OUTPUT ;
    USE SIGNAL ;
    PORT
      LAYER M4 ;
        RECT  0 31.536 0.084 31.56 ;
    END
  END o[213]
  PIN o[214]
    DIRECTION OUTPUT ;
    USE SIGNAL ;
    PORT
      LAYER M4 ;
        RECT  0 31.632 0.084 31.656 ;
    END
  END o[214]
  PIN o[215]
    DIRECTION OUTPUT ;
    USE SIGNAL ;
    PORT
      LAYER M4 ;
        RECT  0 31.728 0.084 31.752 ;
    END
  END o[215]
  PIN o[216]
    DIRECTION OUTPUT ;
    USE SIGNAL ;
    PORT
      LAYER M4 ;
        RECT  0 31.824 0.084 31.848 ;
    END
  END o[216]
  PIN o[217]
    DIRECTION OUTPUT ;
    USE SIGNAL ;
    PORT
      LAYER M4 ;
        RECT  0 31.92 0.084 31.944 ;
    END
  END o[217]
  PIN o[218]
    DIRECTION OUTPUT ;
    USE SIGNAL ;
    PORT
      LAYER M4 ;
        RECT  0 32.016 0.084 32.04 ;
    END
  END o[218]
  PIN o[219]
    DIRECTION OUTPUT ;
    USE SIGNAL ;
    PORT
      LAYER M4 ;
        RECT  0 32.112 0.084 32.136 ;
    END
  END o[219]
  PIN o[21]
    DIRECTION OUTPUT ;
    USE SIGNAL ;
    PORT
      LAYER M4 ;
        RECT  0 15.408 0.084 15.432 ;
    END
  END o[21]
  PIN o[220]
    DIRECTION OUTPUT ;
    USE SIGNAL ;
    PORT
      LAYER M4 ;
        RECT  0 32.208 0.084 32.232 ;
    END
  END o[220]
  PIN o[221]
    DIRECTION OUTPUT ;
    USE SIGNAL ;
    PORT
      LAYER M4 ;
        RECT  0 32.304 0.084 32.328 ;
    END
  END o[221]
  PIN o[222]
    DIRECTION OUTPUT ;
    USE SIGNAL ;
    PORT
      LAYER M4 ;
        RECT  0 32.4 0.084 32.424 ;
    END
  END o[222]
  PIN o[223]
    DIRECTION OUTPUT ;
    USE SIGNAL ;
    PORT
      LAYER M4 ;
        RECT  0 32.496 0.084 32.52 ;
    END
  END o[223]
  PIN o[224]
    DIRECTION OUTPUT ;
    USE SIGNAL ;
    PORT
      LAYER M4 ;
        RECT  0 26.448 0.084 26.472 ;
    END
  END o[224]
  PIN o[225]
    DIRECTION OUTPUT ;
    USE SIGNAL ;
    PORT
      LAYER M4 ;
        RECT  0 26.544 0.084 26.568 ;
    END
  END o[225]
  PIN o[226]
    DIRECTION OUTPUT ;
    USE SIGNAL ;
    PORT
      LAYER M4 ;
        RECT  0 26.64 0.084 26.664 ;
    END
  END o[226]
  PIN o[227]
    DIRECTION OUTPUT ;
    USE SIGNAL ;
    PORT
      LAYER M4 ;
        RECT  0 26.736 0.084 26.76 ;
    END
  END o[227]
  PIN o[228]
    DIRECTION OUTPUT ;
    USE SIGNAL ;
    PORT
      LAYER M4 ;
        RECT  0 26.832 0.084 26.856 ;
    END
  END o[228]
  PIN o[229]
    DIRECTION OUTPUT ;
    USE SIGNAL ;
    PORT
      LAYER M4 ;
        RECT  0 26.928 0.084 26.952 ;
    END
  END o[229]
  PIN o[22]
    DIRECTION OUTPUT ;
    USE SIGNAL ;
    PORT
      LAYER M4 ;
        RECT  0 15.504 0.084 15.528 ;
    END
  END o[22]
  PIN o[230]
    DIRECTION OUTPUT ;
    USE SIGNAL ;
    PORT
      LAYER M4 ;
        RECT  0 27.024 0.084 27.048 ;
    END
  END o[230]
  PIN o[231]
    DIRECTION OUTPUT ;
    USE SIGNAL ;
    PORT
      LAYER M4 ;
        RECT  0 27.12 0.084 27.144 ;
    END
  END o[231]
  PIN o[232]
    DIRECTION OUTPUT ;
    USE SIGNAL ;
    PORT
      LAYER M4 ;
        RECT  0 27.216 0.084 27.24 ;
    END
  END o[232]
  PIN o[233]
    DIRECTION OUTPUT ;
    USE SIGNAL ;
    PORT
      LAYER M4 ;
        RECT  0 27.312 0.084 27.336 ;
    END
  END o[233]
  PIN o[234]
    DIRECTION OUTPUT ;
    USE SIGNAL ;
    PORT
      LAYER M4 ;
        RECT  0 27.408 0.084 27.432 ;
    END
  END o[234]
  PIN o[235]
    DIRECTION OUTPUT ;
    USE SIGNAL ;
    PORT
      LAYER M4 ;
        RECT  0 27.504 0.084 27.528 ;
    END
  END o[235]
  PIN o[236]
    DIRECTION OUTPUT ;
    USE SIGNAL ;
    PORT
      LAYER M4 ;
        RECT  0 27.6 0.084 27.624 ;
    END
  END o[236]
  PIN o[237]
    DIRECTION OUTPUT ;
    USE SIGNAL ;
    PORT
      LAYER M4 ;
        RECT  0 27.696 0.084 27.72 ;
    END
  END o[237]
  PIN o[238]
    DIRECTION OUTPUT ;
    USE SIGNAL ;
    PORT
      LAYER M4 ;
        RECT  0 27.792 0.084 27.816 ;
    END
  END o[238]
  PIN o[239]
    DIRECTION OUTPUT ;
    USE SIGNAL ;
    PORT
      LAYER M4 ;
        RECT  0 27.888 0.084 27.912 ;
    END
  END o[239]
  PIN o[23]
    DIRECTION OUTPUT ;
    USE SIGNAL ;
    PORT
      LAYER M4 ;
        RECT  0 15.6 0.084 15.624 ;
    END
  END o[23]
  PIN o[240]
    DIRECTION OUTPUT ;
    USE SIGNAL ;
    PORT
      LAYER M4 ;
        RECT  0 27.984 0.084 28.008 ;
    END
  END o[240]
  PIN o[241]
    DIRECTION OUTPUT ;
    USE SIGNAL ;
    PORT
      LAYER M4 ;
        RECT  0 28.08 0.084 28.104 ;
    END
  END o[241]
  PIN o[242]
    DIRECTION OUTPUT ;
    USE SIGNAL ;
    PORT
      LAYER M4 ;
        RECT  0 28.176 0.084 28.2 ;
    END
  END o[242]
  PIN o[243]
    DIRECTION OUTPUT ;
    USE SIGNAL ;
    PORT
      LAYER M4 ;
        RECT  0 28.272 0.084 28.296 ;
    END
  END o[243]
  PIN o[244]
    DIRECTION OUTPUT ;
    USE SIGNAL ;
    PORT
      LAYER M4 ;
        RECT  0 28.368 0.084 28.392 ;
    END
  END o[244]
  PIN o[245]
    DIRECTION OUTPUT ;
    USE SIGNAL ;
    PORT
      LAYER M4 ;
        RECT  0 28.464 0.084 28.488 ;
    END
  END o[245]
  PIN o[246]
    DIRECTION OUTPUT ;
    USE SIGNAL ;
    PORT
      LAYER M4 ;
        RECT  0 28.56 0.084 28.584 ;
    END
  END o[246]
  PIN o[247]
    DIRECTION OUTPUT ;
    USE SIGNAL ;
    PORT
      LAYER M4 ;
        RECT  0 28.656 0.084 28.68 ;
    END
  END o[247]
  PIN o[248]
    DIRECTION OUTPUT ;
    USE SIGNAL ;
    PORT
      LAYER M4 ;
        RECT  0 28.752 0.084 28.776 ;
    END
  END o[248]
  PIN o[249]
    DIRECTION OUTPUT ;
    USE SIGNAL ;
    PORT
      LAYER M4 ;
        RECT  0 28.848 0.084 28.872 ;
    END
  END o[249]
  PIN o[24]
    DIRECTION OUTPUT ;
    USE SIGNAL ;
    PORT
      LAYER M4 ;
        RECT  0 15.696 0.084 15.72 ;
    END
  END o[24]
  PIN o[250]
    DIRECTION OUTPUT ;
    USE SIGNAL ;
    PORT
      LAYER M4 ;
        RECT  0 28.944 0.084 28.968 ;
    END
  END o[250]
  PIN o[251]
    DIRECTION OUTPUT ;
    USE SIGNAL ;
    PORT
      LAYER M4 ;
        RECT  0 29.04 0.084 29.064 ;
    END
  END o[251]
  PIN o[252]
    DIRECTION OUTPUT ;
    USE SIGNAL ;
    PORT
      LAYER M4 ;
        RECT  0 29.136 0.084 29.16 ;
    END
  END o[252]
  PIN o[253]
    DIRECTION OUTPUT ;
    USE SIGNAL ;
    PORT
      LAYER M4 ;
        RECT  0 29.232 0.084 29.256 ;
    END
  END o[253]
  PIN o[254]
    DIRECTION OUTPUT ;
    USE SIGNAL ;
    PORT
      LAYER M4 ;
        RECT  0 29.328 0.084 29.352 ;
    END
  END o[254]
  PIN o[255]
    DIRECTION OUTPUT ;
    USE SIGNAL ;
    PORT
      LAYER M4 ;
        RECT  0 29.424 0.084 29.448 ;
    END
  END o[255]
  PIN o[256]
    DIRECTION OUTPUT ;
    USE SIGNAL ;
    PORT
      LAYER M4 ;
        RECT  0 38.736 0.084 38.76 ;
    END
  END o[256]
  PIN o[257]
    DIRECTION OUTPUT ;
    USE SIGNAL ;
    PORT
      LAYER M4 ;
        RECT  0 38.832 0.084 38.856 ;
    END
  END o[257]
  PIN o[258]
    DIRECTION OUTPUT ;
    USE SIGNAL ;
    PORT
      LAYER M4 ;
        RECT  0 38.928 0.084 38.952 ;
    END
  END o[258]
  PIN o[259]
    DIRECTION OUTPUT ;
    USE SIGNAL ;
    PORT
      LAYER M4 ;
        RECT  0 39.024 0.084 39.048 ;
    END
  END o[259]
  PIN o[25]
    DIRECTION OUTPUT ;
    USE SIGNAL ;
    PORT
      LAYER M4 ;
        RECT  0 15.792 0.084 15.816 ;
    END
  END o[25]
  PIN o[260]
    DIRECTION OUTPUT ;
    USE SIGNAL ;
    PORT
      LAYER M4 ;
        RECT  0 39.12 0.084 39.144 ;
    END
  END o[260]
  PIN o[261]
    DIRECTION OUTPUT ;
    USE SIGNAL ;
    PORT
      LAYER M4 ;
        RECT  0 39.216 0.084 39.24 ;
    END
  END o[261]
  PIN o[262]
    DIRECTION OUTPUT ;
    USE SIGNAL ;
    PORT
      LAYER M4 ;
        RECT  0 39.312 0.084 39.336 ;
    END
  END o[262]
  PIN o[263]
    DIRECTION OUTPUT ;
    USE SIGNAL ;
    PORT
      LAYER M4 ;
        RECT  0 39.408 0.084 39.432 ;
    END
  END o[263]
  PIN o[264]
    DIRECTION OUTPUT ;
    USE SIGNAL ;
    PORT
      LAYER M4 ;
        RECT  0 39.504 0.084 39.528 ;
    END
  END o[264]
  PIN o[265]
    DIRECTION OUTPUT ;
    USE SIGNAL ;
    PORT
      LAYER M4 ;
        RECT  0 39.6 0.084 39.624 ;
    END
  END o[265]
  PIN o[266]
    DIRECTION OUTPUT ;
    USE SIGNAL ;
    PORT
      LAYER M4 ;
        RECT  0 39.696 0.084 39.72 ;
    END
  END o[266]
  PIN o[267]
    DIRECTION OUTPUT ;
    USE SIGNAL ;
    PORT
      LAYER M4 ;
        RECT  0 39.792 0.084 39.816 ;
    END
  END o[267]
  PIN o[268]
    DIRECTION OUTPUT ;
    USE SIGNAL ;
    PORT
      LAYER M4 ;
        RECT  0 39.888 0.084 39.912 ;
    END
  END o[268]
  PIN o[269]
    DIRECTION OUTPUT ;
    USE SIGNAL ;
    PORT
      LAYER M4 ;
        RECT  0 39.984 0.084 40.008 ;
    END
  END o[269]
  PIN o[26]
    DIRECTION OUTPUT ;
    USE SIGNAL ;
    PORT
      LAYER M4 ;
        RECT  0 15.888 0.084 15.912 ;
    END
  END o[26]
  PIN o[270]
    DIRECTION OUTPUT ;
    USE SIGNAL ;
    PORT
      LAYER M4 ;
        RECT  0 40.08 0.084 40.104 ;
    END
  END o[270]
  PIN o[271]
    DIRECTION OUTPUT ;
    USE SIGNAL ;
    PORT
      LAYER M4 ;
        RECT  0 40.176 0.084 40.2 ;
    END
  END o[271]
  PIN o[272]
    DIRECTION OUTPUT ;
    USE SIGNAL ;
    PORT
      LAYER M4 ;
        RECT  0 40.272 0.084 40.296 ;
    END
  END o[272]
  PIN o[273]
    DIRECTION OUTPUT ;
    USE SIGNAL ;
    PORT
      LAYER M4 ;
        RECT  0 40.368 0.084 40.392 ;
    END
  END o[273]
  PIN o[274]
    DIRECTION OUTPUT ;
    USE SIGNAL ;
    PORT
      LAYER M4 ;
        RECT  0 40.464 0.084 40.488 ;
    END
  END o[274]
  PIN o[275]
    DIRECTION OUTPUT ;
    USE SIGNAL ;
    PORT
      LAYER M4 ;
        RECT  0 40.56 0.084 40.584 ;
    END
  END o[275]
  PIN o[276]
    DIRECTION OUTPUT ;
    USE SIGNAL ;
    PORT
      LAYER M4 ;
        RECT  0 40.656 0.084 40.68 ;
    END
  END o[276]
  PIN o[277]
    DIRECTION OUTPUT ;
    USE SIGNAL ;
    PORT
      LAYER M4 ;
        RECT  0 40.752 0.084 40.776 ;
    END
  END o[277]
  PIN o[278]
    DIRECTION OUTPUT ;
    USE SIGNAL ;
    PORT
      LAYER M4 ;
        RECT  0 40.848 0.084 40.872 ;
    END
  END o[278]
  PIN o[279]
    DIRECTION OUTPUT ;
    USE SIGNAL ;
    PORT
      LAYER M4 ;
        RECT  0 40.944 0.084 40.968 ;
    END
  END o[279]
  PIN o[27]
    DIRECTION OUTPUT ;
    USE SIGNAL ;
    PORT
      LAYER M4 ;
        RECT  0 15.984 0.084 16.008 ;
    END
  END o[27]
  PIN o[280]
    DIRECTION OUTPUT ;
    USE SIGNAL ;
    PORT
      LAYER M4 ;
        RECT  0 41.04 0.084 41.064 ;
    END
  END o[280]
  PIN o[281]
    DIRECTION OUTPUT ;
    USE SIGNAL ;
    PORT
      LAYER M4 ;
        RECT  0 41.136 0.084 41.16 ;
    END
  END o[281]
  PIN o[282]
    DIRECTION OUTPUT ;
    USE SIGNAL ;
    PORT
      LAYER M4 ;
        RECT  0 41.232 0.084 41.256 ;
    END
  END o[282]
  PIN o[283]
    DIRECTION OUTPUT ;
    USE SIGNAL ;
    PORT
      LAYER M4 ;
        RECT  0 41.328 0.084 41.352 ;
    END
  END o[283]
  PIN o[284]
    DIRECTION OUTPUT ;
    USE SIGNAL ;
    PORT
      LAYER M4 ;
        RECT  0 41.424 0.084 41.448 ;
    END
  END o[284]
  PIN o[285]
    DIRECTION OUTPUT ;
    USE SIGNAL ;
    PORT
      LAYER M4 ;
        RECT  0 41.52 0.084 41.544 ;
    END
  END o[285]
  PIN o[286]
    DIRECTION OUTPUT ;
    USE SIGNAL ;
    PORT
      LAYER M4 ;
        RECT  0 41.616 0.084 41.64 ;
    END
  END o[286]
  PIN o[287]
    DIRECTION OUTPUT ;
    USE SIGNAL ;
    PORT
      LAYER M4 ;
        RECT  0 41.712 0.084 41.736 ;
    END
  END o[287]
  PIN o[288]
    DIRECTION OUTPUT ;
    USE SIGNAL ;
    PORT
      LAYER M4 ;
        RECT  0 35.664 0.084 35.688 ;
    END
  END o[288]
  PIN o[289]
    DIRECTION OUTPUT ;
    USE SIGNAL ;
    PORT
      LAYER M4 ;
        RECT  0 35.76 0.084 35.784 ;
    END
  END o[289]
  PIN o[28]
    DIRECTION OUTPUT ;
    USE SIGNAL ;
    PORT
      LAYER M4 ;
        RECT  0 16.08 0.084 16.104 ;
    END
  END o[28]
  PIN o[290]
    DIRECTION OUTPUT ;
    USE SIGNAL ;
    PORT
      LAYER M4 ;
        RECT  0 35.856 0.084 35.88 ;
    END
  END o[290]
  PIN o[291]
    DIRECTION OUTPUT ;
    USE SIGNAL ;
    PORT
      LAYER M4 ;
        RECT  0 35.952 0.084 35.976 ;
    END
  END o[291]
  PIN o[292]
    DIRECTION OUTPUT ;
    USE SIGNAL ;
    PORT
      LAYER M4 ;
        RECT  0 36.048 0.084 36.072 ;
    END
  END o[292]
  PIN o[293]
    DIRECTION OUTPUT ;
    USE SIGNAL ;
    PORT
      LAYER M4 ;
        RECT  0 36.144 0.084 36.168 ;
    END
  END o[293]
  PIN o[294]
    DIRECTION OUTPUT ;
    USE SIGNAL ;
    PORT
      LAYER M4 ;
        RECT  0 36.24 0.084 36.264 ;
    END
  END o[294]
  PIN o[295]
    DIRECTION OUTPUT ;
    USE SIGNAL ;
    PORT
      LAYER M4 ;
        RECT  0 36.336 0.084 36.36 ;
    END
  END o[295]
  PIN o[296]
    DIRECTION OUTPUT ;
    USE SIGNAL ;
    PORT
      LAYER M4 ;
        RECT  0 36.432 0.084 36.456 ;
    END
  END o[296]
  PIN o[297]
    DIRECTION OUTPUT ;
    USE SIGNAL ;
    PORT
      LAYER M4 ;
        RECT  0 36.528 0.084 36.552 ;
    END
  END o[297]
  PIN o[298]
    DIRECTION OUTPUT ;
    USE SIGNAL ;
    PORT
      LAYER M4 ;
        RECT  0 36.624 0.084 36.648 ;
    END
  END o[298]
  PIN o[299]
    DIRECTION OUTPUT ;
    USE SIGNAL ;
    PORT
      LAYER M4 ;
        RECT  0 36.72 0.084 36.744 ;
    END
  END o[299]
  PIN o[29]
    DIRECTION OUTPUT ;
    USE SIGNAL ;
    PORT
      LAYER M4 ;
        RECT  0 16.176 0.084 16.2 ;
    END
  END o[29]
  PIN o[2]
    DIRECTION OUTPUT ;
    USE SIGNAL ;
    PORT
      LAYER M4 ;
        RECT  0 13.584 0.084 13.608 ;
    END
  END o[2]
  PIN o[300]
    DIRECTION OUTPUT ;
    USE SIGNAL ;
    PORT
      LAYER M4 ;
        RECT  0 36.816 0.084 36.84 ;
    END
  END o[300]
  PIN o[301]
    DIRECTION OUTPUT ;
    USE SIGNAL ;
    PORT
      LAYER M4 ;
        RECT  0 36.912 0.084 36.936 ;
    END
  END o[301]
  PIN o[302]
    DIRECTION OUTPUT ;
    USE SIGNAL ;
    PORT
      LAYER M4 ;
        RECT  0 37.008 0.084 37.032 ;
    END
  END o[302]
  PIN o[303]
    DIRECTION OUTPUT ;
    USE SIGNAL ;
    PORT
      LAYER M4 ;
        RECT  0 37.104 0.084 37.128 ;
    END
  END o[303]
  PIN o[304]
    DIRECTION OUTPUT ;
    USE SIGNAL ;
    PORT
      LAYER M4 ;
        RECT  0 37.2 0.084 37.224 ;
    END
  END o[304]
  PIN o[305]
    DIRECTION OUTPUT ;
    USE SIGNAL ;
    PORT
      LAYER M4 ;
        RECT  0 37.296 0.084 37.32 ;
    END
  END o[305]
  PIN o[306]
    DIRECTION OUTPUT ;
    USE SIGNAL ;
    PORT
      LAYER M4 ;
        RECT  0 37.392 0.084 37.416 ;
    END
  END o[306]
  PIN o[307]
    DIRECTION OUTPUT ;
    USE SIGNAL ;
    PORT
      LAYER M4 ;
        RECT  0 37.488 0.084 37.512 ;
    END
  END o[307]
  PIN o[308]
    DIRECTION OUTPUT ;
    USE SIGNAL ;
    PORT
      LAYER M4 ;
        RECT  0 37.584 0.084 37.608 ;
    END
  END o[308]
  PIN o[309]
    DIRECTION OUTPUT ;
    USE SIGNAL ;
    PORT
      LAYER M4 ;
        RECT  0 37.68 0.084 37.704 ;
    END
  END o[309]
  PIN o[30]
    DIRECTION OUTPUT ;
    USE SIGNAL ;
    PORT
      LAYER M4 ;
        RECT  0 16.272 0.084 16.296 ;
    END
  END o[30]
  PIN o[310]
    DIRECTION OUTPUT ;
    USE SIGNAL ;
    PORT
      LAYER M4 ;
        RECT  0 37.776 0.084 37.8 ;
    END
  END o[310]
  PIN o[311]
    DIRECTION OUTPUT ;
    USE SIGNAL ;
    PORT
      LAYER M4 ;
        RECT  0 37.872 0.084 37.896 ;
    END
  END o[311]
  PIN o[312]
    DIRECTION OUTPUT ;
    USE SIGNAL ;
    PORT
      LAYER M4 ;
        RECT  0 37.968 0.084 37.992 ;
    END
  END o[312]
  PIN o[313]
    DIRECTION OUTPUT ;
    USE SIGNAL ;
    PORT
      LAYER M4 ;
        RECT  0 38.064 0.084 38.088 ;
    END
  END o[313]
  PIN o[314]
    DIRECTION OUTPUT ;
    USE SIGNAL ;
    PORT
      LAYER M4 ;
        RECT  0 38.16 0.084 38.184 ;
    END
  END o[314]
  PIN o[315]
    DIRECTION OUTPUT ;
    USE SIGNAL ;
    PORT
      LAYER M4 ;
        RECT  0 38.256 0.084 38.28 ;
    END
  END o[315]
  PIN o[316]
    DIRECTION OUTPUT ;
    USE SIGNAL ;
    PORT
      LAYER M4 ;
        RECT  0 38.352 0.084 38.376 ;
    END
  END o[316]
  PIN o[317]
    DIRECTION OUTPUT ;
    USE SIGNAL ;
    PORT
      LAYER M4 ;
        RECT  0 38.448 0.084 38.472 ;
    END
  END o[317]
  PIN o[318]
    DIRECTION OUTPUT ;
    USE SIGNAL ;
    PORT
      LAYER M4 ;
        RECT  0 38.544 0.084 38.568 ;
    END
  END o[318]
  PIN o[319]
    DIRECTION OUTPUT ;
    USE SIGNAL ;
    PORT
      LAYER M4 ;
        RECT  0 38.64 0.084 38.664 ;
    END
  END o[319]
  PIN o[31]
    DIRECTION OUTPUT ;
    USE SIGNAL ;
    PORT
      LAYER M4 ;
        RECT  0 16.368 0.084 16.392 ;
    END
  END o[31]
  PIN o[320]
    DIRECTION OUTPUT ;
    USE SIGNAL ;
    PORT
      LAYER M4 ;
        RECT  0 32.592 0.084 32.616 ;
    END
  END o[320]
  PIN o[321]
    DIRECTION OUTPUT ;
    USE SIGNAL ;
    PORT
      LAYER M4 ;
        RECT  0 32.688 0.084 32.712 ;
    END
  END o[321]
  PIN o[322]
    DIRECTION OUTPUT ;
    USE SIGNAL ;
    PORT
      LAYER M4 ;
        RECT  0 32.784 0.084 32.808 ;
    END
  END o[322]
  PIN o[323]
    DIRECTION OUTPUT ;
    USE SIGNAL ;
    PORT
      LAYER M4 ;
        RECT  0 32.88 0.084 32.904 ;
    END
  END o[323]
  PIN o[324]
    DIRECTION OUTPUT ;
    USE SIGNAL ;
    PORT
      LAYER M4 ;
        RECT  0 32.976 0.084 33 ;
    END
  END o[324]
  PIN o[325]
    DIRECTION OUTPUT ;
    USE SIGNAL ;
    PORT
      LAYER M4 ;
        RECT  0 33.072 0.084 33.096 ;
    END
  END o[325]
  PIN o[326]
    DIRECTION OUTPUT ;
    USE SIGNAL ;
    PORT
      LAYER M4 ;
        RECT  0 33.168 0.084 33.192 ;
    END
  END o[326]
  PIN o[327]
    DIRECTION OUTPUT ;
    USE SIGNAL ;
    PORT
      LAYER M4 ;
        RECT  0 33.264 0.084 33.288 ;
    END
  END o[327]
  PIN o[328]
    DIRECTION OUTPUT ;
    USE SIGNAL ;
    PORT
      LAYER M4 ;
        RECT  0 33.36 0.084 33.384 ;
    END
  END o[328]
  PIN o[329]
    DIRECTION OUTPUT ;
    USE SIGNAL ;
    PORT
      LAYER M4 ;
        RECT  0 33.456 0.084 33.48 ;
    END
  END o[329]
  PIN o[32]
    DIRECTION OUTPUT ;
    USE SIGNAL ;
    PORT
      LAYER M4 ;
        RECT  0 22.608 0.084 22.632 ;
    END
  END o[32]
  PIN o[330]
    DIRECTION OUTPUT ;
    USE SIGNAL ;
    PORT
      LAYER M4 ;
        RECT  0 33.552 0.084 33.576 ;
    END
  END o[330]
  PIN o[331]
    DIRECTION OUTPUT ;
    USE SIGNAL ;
    PORT
      LAYER M4 ;
        RECT  0 33.648 0.084 33.672 ;
    END
  END o[331]
  PIN o[332]
    DIRECTION OUTPUT ;
    USE SIGNAL ;
    PORT
      LAYER M4 ;
        RECT  0 33.744 0.084 33.768 ;
    END
  END o[332]
  PIN o[333]
    DIRECTION OUTPUT ;
    USE SIGNAL ;
    PORT
      LAYER M4 ;
        RECT  0 33.84 0.084 33.864 ;
    END
  END o[333]
  PIN o[334]
    DIRECTION OUTPUT ;
    USE SIGNAL ;
    PORT
      LAYER M4 ;
        RECT  0 33.936 0.084 33.96 ;
    END
  END o[334]
  PIN o[335]
    DIRECTION OUTPUT ;
    USE SIGNAL ;
    PORT
      LAYER M4 ;
        RECT  0 34.032 0.084 34.056 ;
    END
  END o[335]
  PIN o[336]
    DIRECTION OUTPUT ;
    USE SIGNAL ;
    PORT
      LAYER M4 ;
        RECT  0 34.128 0.084 34.152 ;
    END
  END o[336]
  PIN o[337]
    DIRECTION OUTPUT ;
    USE SIGNAL ;
    PORT
      LAYER M4 ;
        RECT  0 34.224 0.084 34.248 ;
    END
  END o[337]
  PIN o[338]
    DIRECTION OUTPUT ;
    USE SIGNAL ;
    PORT
      LAYER M4 ;
        RECT  0 34.32 0.084 34.344 ;
    END
  END o[338]
  PIN o[339]
    DIRECTION OUTPUT ;
    USE SIGNAL ;
    PORT
      LAYER M4 ;
        RECT  0 34.416 0.084 34.44 ;
    END
  END o[339]
  PIN o[33]
    DIRECTION OUTPUT ;
    USE SIGNAL ;
    PORT
      LAYER M4 ;
        RECT  0 22.704 0.084 22.728 ;
    END
  END o[33]
  PIN o[340]
    DIRECTION OUTPUT ;
    USE SIGNAL ;
    PORT
      LAYER M4 ;
        RECT  0 34.512 0.084 34.536 ;
    END
  END o[340]
  PIN o[341]
    DIRECTION OUTPUT ;
    USE SIGNAL ;
    PORT
      LAYER M4 ;
        RECT  0 34.608 0.084 34.632 ;
    END
  END o[341]
  PIN o[342]
    DIRECTION OUTPUT ;
    USE SIGNAL ;
    PORT
      LAYER M4 ;
        RECT  0 34.704 0.084 34.728 ;
    END
  END o[342]
  PIN o[343]
    DIRECTION OUTPUT ;
    USE SIGNAL ;
    PORT
      LAYER M4 ;
        RECT  0 34.8 0.084 34.824 ;
    END
  END o[343]
  PIN o[344]
    DIRECTION OUTPUT ;
    USE SIGNAL ;
    PORT
      LAYER M4 ;
        RECT  0 34.896 0.084 34.92 ;
    END
  END o[344]
  PIN o[345]
    DIRECTION OUTPUT ;
    USE SIGNAL ;
    PORT
      LAYER M4 ;
        RECT  0 34.992 0.084 35.016 ;
    END
  END o[345]
  PIN o[346]
    DIRECTION OUTPUT ;
    USE SIGNAL ;
    PORT
      LAYER M4 ;
        RECT  0 35.088 0.084 35.112 ;
    END
  END o[346]
  PIN o[347]
    DIRECTION OUTPUT ;
    USE SIGNAL ;
    PORT
      LAYER M4 ;
        RECT  0 35.184 0.084 35.208 ;
    END
  END o[347]
  PIN o[348]
    DIRECTION OUTPUT ;
    USE SIGNAL ;
    PORT
      LAYER M4 ;
        RECT  0 35.28 0.084 35.304 ;
    END
  END o[348]
  PIN o[349]
    DIRECTION OUTPUT ;
    USE SIGNAL ;
    PORT
      LAYER M4 ;
        RECT  0 35.376 0.084 35.4 ;
    END
  END o[349]
  PIN o[34]
    DIRECTION OUTPUT ;
    USE SIGNAL ;
    PORT
      LAYER M4 ;
        RECT  0 22.8 0.084 22.824 ;
    END
  END o[34]
  PIN o[350]
    DIRECTION OUTPUT ;
    USE SIGNAL ;
    PORT
      LAYER M4 ;
        RECT  0 35.472 0.084 35.496 ;
    END
  END o[350]
  PIN o[351]
    DIRECTION OUTPUT ;
    USE SIGNAL ;
    PORT
      LAYER M4 ;
        RECT  0 35.568 0.084 35.592 ;
    END
  END o[351]
  PIN o[352]
    DIRECTION OUTPUT ;
    USE SIGNAL ;
    PORT
      LAYER M4 ;
        RECT  0 41.808 0.084 41.832 ;
    END
  END o[352]
  PIN o[353]
    DIRECTION OUTPUT ;
    USE SIGNAL ;
    PORT
      LAYER M4 ;
        RECT  0 41.904 0.084 41.928 ;
    END
  END o[353]
  PIN o[354]
    DIRECTION OUTPUT ;
    USE SIGNAL ;
    PORT
      LAYER M4 ;
        RECT  0 42 0.084 42.024 ;
    END
  END o[354]
  PIN o[355]
    DIRECTION OUTPUT ;
    USE SIGNAL ;
    PORT
      LAYER M4 ;
        RECT  0 42.096 0.084 42.12 ;
    END
  END o[355]
  PIN o[356]
    DIRECTION OUTPUT ;
    USE SIGNAL ;
    PORT
      LAYER M4 ;
        RECT  0 42.192 0.084 42.216 ;
    END
  END o[356]
  PIN o[357]
    DIRECTION OUTPUT ;
    USE SIGNAL ;
    PORT
      LAYER M4 ;
        RECT  0 42.288 0.084 42.312 ;
    END
  END o[357]
  PIN o[358]
    DIRECTION OUTPUT ;
    USE SIGNAL ;
    PORT
      LAYER M4 ;
        RECT  0 42.384 0.084 42.408 ;
    END
  END o[358]
  PIN o[359]
    DIRECTION OUTPUT ;
    USE SIGNAL ;
    PORT
      LAYER M4 ;
        RECT  0 42.48 0.084 42.504 ;
    END
  END o[359]
  PIN o[35]
    DIRECTION OUTPUT ;
    USE SIGNAL ;
    PORT
      LAYER M4 ;
        RECT  0 22.896 0.084 22.92 ;
    END
  END o[35]
  PIN o[360]
    DIRECTION OUTPUT ;
    USE SIGNAL ;
    PORT
      LAYER M4 ;
        RECT  0 42.576 0.084 42.6 ;
    END
  END o[360]
  PIN o[361]
    DIRECTION OUTPUT ;
    USE SIGNAL ;
    PORT
      LAYER M4 ;
        RECT  0 42.672 0.084 42.696 ;
    END
  END o[361]
  PIN o[362]
    DIRECTION OUTPUT ;
    USE SIGNAL ;
    PORT
      LAYER M4 ;
        RECT  0 42.768 0.084 42.792 ;
    END
  END o[362]
  PIN o[363]
    DIRECTION OUTPUT ;
    USE SIGNAL ;
    PORT
      LAYER M4 ;
        RECT  0 42.864 0.084 42.888 ;
    END
  END o[363]
  PIN o[364]
    DIRECTION OUTPUT ;
    USE SIGNAL ;
    PORT
      LAYER M4 ;
        RECT  0 42.96 0.084 42.984 ;
    END
  END o[364]
  PIN o[365]
    DIRECTION OUTPUT ;
    USE SIGNAL ;
    PORT
      LAYER M4 ;
        RECT  0 43.056 0.084 43.08 ;
    END
  END o[365]
  PIN o[366]
    DIRECTION OUTPUT ;
    USE SIGNAL ;
    PORT
      LAYER M4 ;
        RECT  0 43.152 0.084 43.176 ;
    END
  END o[366]
  PIN o[367]
    DIRECTION OUTPUT ;
    USE SIGNAL ;
    PORT
      LAYER M4 ;
        RECT  0 43.248 0.084 43.272 ;
    END
  END o[367]
  PIN o[368]
    DIRECTION OUTPUT ;
    USE SIGNAL ;
    PORT
      LAYER M4 ;
        RECT  0 43.344 0.084 43.368 ;
    END
  END o[368]
  PIN o[369]
    DIRECTION OUTPUT ;
    USE SIGNAL ;
    PORT
      LAYER M4 ;
        RECT  0 43.44 0.084 43.464 ;
    END
  END o[369]
  PIN o[36]
    DIRECTION OUTPUT ;
    USE SIGNAL ;
    PORT
      LAYER M4 ;
        RECT  0 22.992 0.084 23.016 ;
    END
  END o[36]
  PIN o[370]
    DIRECTION OUTPUT ;
    USE SIGNAL ;
    PORT
      LAYER M4 ;
        RECT  0 43.536 0.084 43.56 ;
    END
  END o[370]
  PIN o[371]
    DIRECTION OUTPUT ;
    USE SIGNAL ;
    PORT
      LAYER M4 ;
        RECT  0 43.632 0.084 43.656 ;
    END
  END o[371]
  PIN o[372]
    DIRECTION OUTPUT ;
    USE SIGNAL ;
    PORT
      LAYER M4 ;
        RECT  0 43.728 0.084 43.752 ;
    END
  END o[372]
  PIN o[373]
    DIRECTION OUTPUT ;
    USE SIGNAL ;
    PORT
      LAYER M4 ;
        RECT  0 43.824 0.084 43.848 ;
    END
  END o[373]
  PIN o[374]
    DIRECTION OUTPUT ;
    USE SIGNAL ;
    PORT
      LAYER M4 ;
        RECT  0 43.92 0.084 43.944 ;
    END
  END o[374]
  PIN o[375]
    DIRECTION OUTPUT ;
    USE SIGNAL ;
    PORT
      LAYER M4 ;
        RECT  0 44.016 0.084 44.04 ;
    END
  END o[375]
  PIN o[376]
    DIRECTION OUTPUT ;
    USE SIGNAL ;
    PORT
      LAYER M4 ;
        RECT  0 44.112 0.084 44.136 ;
    END
  END o[376]
  PIN o[377]
    DIRECTION OUTPUT ;
    USE SIGNAL ;
    PORT
      LAYER M4 ;
        RECT  0 44.208 0.084 44.232 ;
    END
  END o[377]
  PIN o[378]
    DIRECTION OUTPUT ;
    USE SIGNAL ;
    PORT
      LAYER M4 ;
        RECT  0 44.304 0.084 44.328 ;
    END
  END o[378]
  PIN o[379]
    DIRECTION OUTPUT ;
    USE SIGNAL ;
    PORT
      LAYER M4 ;
        RECT  0 44.4 0.084 44.424 ;
    END
  END o[379]
  PIN o[37]
    DIRECTION OUTPUT ;
    USE SIGNAL ;
    PORT
      LAYER M4 ;
        RECT  0 23.088 0.084 23.112 ;
    END
  END o[37]
  PIN o[380]
    DIRECTION OUTPUT ;
    USE SIGNAL ;
    PORT
      LAYER M4 ;
        RECT  0 44.496 0.084 44.52 ;
    END
  END o[380]
  PIN o[381]
    DIRECTION OUTPUT ;
    USE SIGNAL ;
    PORT
      LAYER M4 ;
        RECT  0 44.592 0.084 44.616 ;
    END
  END o[381]
  PIN o[382]
    DIRECTION OUTPUT ;
    USE SIGNAL ;
    PORT
      LAYER M4 ;
        RECT  0 44.688 0.084 44.712 ;
    END
  END o[382]
  PIN o[383]
    DIRECTION OUTPUT ;
    USE SIGNAL ;
    PORT
      LAYER M4 ;
        RECT  0 44.784 0.084 44.808 ;
    END
  END o[383]
  PIN o[384]
    DIRECTION OUTPUT ;
    USE SIGNAL ;
    PORT
      LAYER M4 ;
        RECT  0 57.936 0.084 57.96 ;
    END
  END o[384]
  PIN o[385]
    DIRECTION OUTPUT ;
    USE SIGNAL ;
    PORT
      LAYER M4 ;
        RECT  0 58.032 0.084 58.056 ;
    END
  END o[385]
  PIN o[386]
    DIRECTION OUTPUT ;
    USE SIGNAL ;
    PORT
      LAYER M4 ;
        RECT  0 58.128 0.084 58.152 ;
    END
  END o[386]
  PIN o[387]
    DIRECTION OUTPUT ;
    USE SIGNAL ;
    PORT
      LAYER M4 ;
        RECT  0 58.224 0.084 58.248 ;
    END
  END o[387]
  PIN o[388]
    DIRECTION OUTPUT ;
    USE SIGNAL ;
    PORT
      LAYER M4 ;
        RECT  0 58.32 0.084 58.344 ;
    END
  END o[388]
  PIN o[389]
    DIRECTION OUTPUT ;
    USE SIGNAL ;
    PORT
      LAYER M4 ;
        RECT  0 58.416 0.084 58.44 ;
    END
  END o[389]
  PIN o[38]
    DIRECTION OUTPUT ;
    USE SIGNAL ;
    PORT
      LAYER M4 ;
        RECT  0 23.184 0.084 23.208 ;
    END
  END o[38]
  PIN o[390]
    DIRECTION OUTPUT ;
    USE SIGNAL ;
    PORT
      LAYER M4 ;
        RECT  0 58.512 0.084 58.536 ;
    END
  END o[390]
  PIN o[391]
    DIRECTION OUTPUT ;
    USE SIGNAL ;
    PORT
      LAYER M4 ;
        RECT  0 58.608 0.084 58.632 ;
    END
  END o[391]
  PIN o[392]
    DIRECTION OUTPUT ;
    USE SIGNAL ;
    PORT
      LAYER M4 ;
        RECT  0 58.704 0.084 58.728 ;
    END
  END o[392]
  PIN o[393]
    DIRECTION OUTPUT ;
    USE SIGNAL ;
    PORT
      LAYER M4 ;
        RECT  0 58.8 0.084 58.824 ;
    END
  END o[393]
  PIN o[394]
    DIRECTION OUTPUT ;
    USE SIGNAL ;
    PORT
      LAYER M4 ;
        RECT  0 58.896 0.084 58.92 ;
    END
  END o[394]
  PIN o[395]
    DIRECTION OUTPUT ;
    USE SIGNAL ;
    PORT
      LAYER M4 ;
        RECT  0 58.992 0.084 59.016 ;
    END
  END o[395]
  PIN o[396]
    DIRECTION OUTPUT ;
    USE SIGNAL ;
    PORT
      LAYER M4 ;
        RECT  0 59.088 0.084 59.112 ;
    END
  END o[396]
  PIN o[397]
    DIRECTION OUTPUT ;
    USE SIGNAL ;
    PORT
      LAYER M4 ;
        RECT  0 59.184 0.084 59.208 ;
    END
  END o[397]
  PIN o[398]
    DIRECTION OUTPUT ;
    USE SIGNAL ;
    PORT
      LAYER M4 ;
        RECT  0 59.28 0.084 59.304 ;
    END
  END o[398]
  PIN o[399]
    DIRECTION OUTPUT ;
    USE SIGNAL ;
    PORT
      LAYER M4 ;
        RECT  0 59.376 0.084 59.4 ;
    END
  END o[399]
  PIN o[39]
    DIRECTION OUTPUT ;
    USE SIGNAL ;
    PORT
      LAYER M4 ;
        RECT  0 23.28 0.084 23.304 ;
    END
  END o[39]
  PIN o[3]
    DIRECTION OUTPUT ;
    USE SIGNAL ;
    PORT
      LAYER M4 ;
        RECT  0 13.68 0.084 13.704 ;
    END
  END o[3]
  PIN o[400]
    DIRECTION OUTPUT ;
    USE SIGNAL ;
    PORT
      LAYER M4 ;
        RECT  0 59.472 0.084 59.496 ;
    END
  END o[400]
  PIN o[401]
    DIRECTION OUTPUT ;
    USE SIGNAL ;
    PORT
      LAYER M4 ;
        RECT  0 59.568 0.084 59.592 ;
    END
  END o[401]
  PIN o[402]
    DIRECTION OUTPUT ;
    USE SIGNAL ;
    PORT
      LAYER M4 ;
        RECT  0 59.664 0.084 59.688 ;
    END
  END o[402]
  PIN o[403]
    DIRECTION OUTPUT ;
    USE SIGNAL ;
    PORT
      LAYER M4 ;
        RECT  0 59.76 0.084 59.784 ;
    END
  END o[403]
  PIN o[404]
    DIRECTION OUTPUT ;
    USE SIGNAL ;
    PORT
      LAYER M4 ;
        RECT  0 59.856 0.084 59.88 ;
    END
  END o[404]
  PIN o[405]
    DIRECTION OUTPUT ;
    USE SIGNAL ;
    PORT
      LAYER M4 ;
        RECT  0 59.952 0.084 59.976 ;
    END
  END o[405]
  PIN o[406]
    DIRECTION OUTPUT ;
    USE SIGNAL ;
    PORT
      LAYER M4 ;
        RECT  0 60.048 0.084 60.072 ;
    END
  END o[406]
  PIN o[407]
    DIRECTION OUTPUT ;
    USE SIGNAL ;
    PORT
      LAYER M4 ;
        RECT  0 60.144 0.084 60.168 ;
    END
  END o[407]
  PIN o[408]
    DIRECTION OUTPUT ;
    USE SIGNAL ;
    PORT
      LAYER M4 ;
        RECT  0 60.24 0.084 60.264 ;
    END
  END o[408]
  PIN o[409]
    DIRECTION OUTPUT ;
    USE SIGNAL ;
    PORT
      LAYER M4 ;
        RECT  0 60.336 0.084 60.36 ;
    END
  END o[409]
  PIN o[40]
    DIRECTION OUTPUT ;
    USE SIGNAL ;
    PORT
      LAYER M4 ;
        RECT  0 23.376 0.084 23.4 ;
    END
  END o[40]
  PIN o[410]
    DIRECTION OUTPUT ;
    USE SIGNAL ;
    PORT
      LAYER M4 ;
        RECT  0 60.432 0.084 60.456 ;
    END
  END o[410]
  PIN o[411]
    DIRECTION OUTPUT ;
    USE SIGNAL ;
    PORT
      LAYER M4 ;
        RECT  0 60.528 0.084 60.552 ;
    END
  END o[411]
  PIN o[412]
    DIRECTION OUTPUT ;
    USE SIGNAL ;
    PORT
      LAYER M4 ;
        RECT  0 60.624 0.084 60.648 ;
    END
  END o[412]
  PIN o[413]
    DIRECTION OUTPUT ;
    USE SIGNAL ;
    PORT
      LAYER M4 ;
        RECT  0 60.72 0.084 60.744 ;
    END
  END o[413]
  PIN o[414]
    DIRECTION OUTPUT ;
    USE SIGNAL ;
    PORT
      LAYER M4 ;
        RECT  0 60.816 0.084 60.84 ;
    END
  END o[414]
  PIN o[415]
    DIRECTION OUTPUT ;
    USE SIGNAL ;
    PORT
      LAYER M4 ;
        RECT  0 60.912 0.084 60.936 ;
    END
  END o[415]
  PIN o[416]
    DIRECTION OUTPUT ;
    USE SIGNAL ;
    PORT
      LAYER M4 ;
        RECT  0 61.008 0.084 61.032 ;
    END
  END o[416]
  PIN o[417]
    DIRECTION OUTPUT ;
    USE SIGNAL ;
    PORT
      LAYER M4 ;
        RECT  0 61.104 0.084 61.128 ;
    END
  END o[417]
  PIN o[418]
    DIRECTION OUTPUT ;
    USE SIGNAL ;
    PORT
      LAYER M4 ;
        RECT  0 61.2 0.084 61.224 ;
    END
  END o[418]
  PIN o[419]
    DIRECTION OUTPUT ;
    USE SIGNAL ;
    PORT
      LAYER M4 ;
        RECT  0 61.296 0.084 61.32 ;
    END
  END o[419]
  PIN o[41]
    DIRECTION OUTPUT ;
    USE SIGNAL ;
    PORT
      LAYER M4 ;
        RECT  0 23.472 0.084 23.496 ;
    END
  END o[41]
  PIN o[420]
    DIRECTION OUTPUT ;
    USE SIGNAL ;
    PORT
      LAYER M4 ;
        RECT  0 61.392 0.084 61.416 ;
    END
  END o[420]
  PIN o[421]
    DIRECTION OUTPUT ;
    USE SIGNAL ;
    PORT
      LAYER M4 ;
        RECT  0 61.488 0.084 61.512 ;
    END
  END o[421]
  PIN o[422]
    DIRECTION OUTPUT ;
    USE SIGNAL ;
    PORT
      LAYER M4 ;
        RECT  0 61.584 0.084 61.608 ;
    END
  END o[422]
  PIN o[423]
    DIRECTION OUTPUT ;
    USE SIGNAL ;
    PORT
      LAYER M4 ;
        RECT  0 61.68 0.084 61.704 ;
    END
  END o[423]
  PIN o[424]
    DIRECTION OUTPUT ;
    USE SIGNAL ;
    PORT
      LAYER M4 ;
        RECT  0 61.776 0.084 61.8 ;
    END
  END o[424]
  PIN o[425]
    DIRECTION OUTPUT ;
    USE SIGNAL ;
    PORT
      LAYER M4 ;
        RECT  0 61.872 0.084 61.896 ;
    END
  END o[425]
  PIN o[426]
    DIRECTION OUTPUT ;
    USE SIGNAL ;
    PORT
      LAYER M4 ;
        RECT  0 61.968 0.084 61.992 ;
    END
  END o[426]
  PIN o[427]
    DIRECTION OUTPUT ;
    USE SIGNAL ;
    PORT
      LAYER M4 ;
        RECT  0 62.064 0.084 62.088 ;
    END
  END o[427]
  PIN o[428]
    DIRECTION OUTPUT ;
    USE SIGNAL ;
    PORT
      LAYER M4 ;
        RECT  0 62.16 0.084 62.184 ;
    END
  END o[428]
  PIN o[429]
    DIRECTION OUTPUT ;
    USE SIGNAL ;
    PORT
      LAYER M4 ;
        RECT  0 62.256 0.084 62.28 ;
    END
  END o[429]
  PIN o[42]
    DIRECTION OUTPUT ;
    USE SIGNAL ;
    PORT
      LAYER M4 ;
        RECT  0 23.568 0.084 23.592 ;
    END
  END o[42]
  PIN o[430]
    DIRECTION OUTPUT ;
    USE SIGNAL ;
    PORT
      LAYER M4 ;
        RECT  0 62.352 0.084 62.376 ;
    END
  END o[430]
  PIN o[431]
    DIRECTION OUTPUT ;
    USE SIGNAL ;
    PORT
      LAYER M4 ;
        RECT  0 62.448 0.084 62.472 ;
    END
  END o[431]
  PIN o[432]
    DIRECTION OUTPUT ;
    USE SIGNAL ;
    PORT
      LAYER M4 ;
        RECT  0 62.544 0.084 62.568 ;
    END
  END o[432]
  PIN o[433]
    DIRECTION OUTPUT ;
    USE SIGNAL ;
    PORT
      LAYER M4 ;
        RECT  0 62.64 0.084 62.664 ;
    END
  END o[433]
  PIN o[434]
    DIRECTION OUTPUT ;
    USE SIGNAL ;
    PORT
      LAYER M4 ;
        RECT  0 62.736 0.084 62.76 ;
    END
  END o[434]
  PIN o[435]
    DIRECTION OUTPUT ;
    USE SIGNAL ;
    PORT
      LAYER M4 ;
        RECT  0 62.832 0.084 62.856 ;
    END
  END o[435]
  PIN o[436]
    DIRECTION OUTPUT ;
    USE SIGNAL ;
    PORT
      LAYER M4 ;
        RECT  0 62.928 0.084 62.952 ;
    END
  END o[436]
  PIN o[437]
    DIRECTION OUTPUT ;
    USE SIGNAL ;
    PORT
      LAYER M4 ;
        RECT  0 63.024 0.084 63.048 ;
    END
  END o[437]
  PIN o[438]
    DIRECTION OUTPUT ;
    USE SIGNAL ;
    PORT
      LAYER M4 ;
        RECT  0 63.12 0.084 63.144 ;
    END
  END o[438]
  PIN o[439]
    DIRECTION OUTPUT ;
    USE SIGNAL ;
    PORT
      LAYER M4 ;
        RECT  0 63.216 0.084 63.24 ;
    END
  END o[439]
  PIN o[43]
    DIRECTION OUTPUT ;
    USE SIGNAL ;
    PORT
      LAYER M4 ;
        RECT  0 23.664 0.084 23.688 ;
    END
  END o[43]
  PIN o[440]
    DIRECTION OUTPUT ;
    USE SIGNAL ;
    PORT
      LAYER M4 ;
        RECT  0 63.312 0.084 63.336 ;
    END
  END o[440]
  PIN o[441]
    DIRECTION OUTPUT ;
    USE SIGNAL ;
    PORT
      LAYER M4 ;
        RECT  0 63.408 0.084 63.432 ;
    END
  END o[441]
  PIN o[442]
    DIRECTION OUTPUT ;
    USE SIGNAL ;
    PORT
      LAYER M4 ;
        RECT  0 63.504 0.084 63.528 ;
    END
  END o[442]
  PIN o[443]
    DIRECTION OUTPUT ;
    USE SIGNAL ;
    PORT
      LAYER M4 ;
        RECT  0 63.6 0.084 63.624 ;
    END
  END o[443]
  PIN o[444]
    DIRECTION OUTPUT ;
    USE SIGNAL ;
    PORT
      LAYER M4 ;
        RECT  0 63.696 0.084 63.72 ;
    END
  END o[444]
  PIN o[445]
    DIRECTION OUTPUT ;
    USE SIGNAL ;
    PORT
      LAYER M4 ;
        RECT  0 63.792 0.084 63.816 ;
    END
  END o[445]
  PIN o[446]
    DIRECTION OUTPUT ;
    USE SIGNAL ;
    PORT
      LAYER M4 ;
        RECT  0 63.888 0.084 63.912 ;
    END
  END o[446]
  PIN o[447]
    DIRECTION OUTPUT ;
    USE SIGNAL ;
    PORT
      LAYER M4 ;
        RECT  0 63.984 0.084 64.008 ;
    END
  END o[447]
  PIN o[448]
    DIRECTION OUTPUT ;
    USE SIGNAL ;
    PORT
      LAYER M4 ;
        RECT  0 51.792 0.084 51.816 ;
    END
  END o[448]
  PIN o[449]
    DIRECTION OUTPUT ;
    USE SIGNAL ;
    PORT
      LAYER M4 ;
        RECT  0 51.888 0.084 51.912 ;
    END
  END o[449]
  PIN o[44]
    DIRECTION OUTPUT ;
    USE SIGNAL ;
    PORT
      LAYER M4 ;
        RECT  0 23.76 0.084 23.784 ;
    END
  END o[44]
  PIN o[450]
    DIRECTION OUTPUT ;
    USE SIGNAL ;
    PORT
      LAYER M4 ;
        RECT  0 51.984 0.084 52.008 ;
    END
  END o[450]
  PIN o[451]
    DIRECTION OUTPUT ;
    USE SIGNAL ;
    PORT
      LAYER M4 ;
        RECT  0 52.08 0.084 52.104 ;
    END
  END o[451]
  PIN o[452]
    DIRECTION OUTPUT ;
    USE SIGNAL ;
    PORT
      LAYER M4 ;
        RECT  0 52.176 0.084 52.2 ;
    END
  END o[452]
  PIN o[453]
    DIRECTION OUTPUT ;
    USE SIGNAL ;
    PORT
      LAYER M4 ;
        RECT  0 52.272 0.084 52.296 ;
    END
  END o[453]
  PIN o[454]
    DIRECTION OUTPUT ;
    USE SIGNAL ;
    PORT
      LAYER M4 ;
        RECT  0 52.368 0.084 52.392 ;
    END
  END o[454]
  PIN o[455]
    DIRECTION OUTPUT ;
    USE SIGNAL ;
    PORT
      LAYER M4 ;
        RECT  0 52.464 0.084 52.488 ;
    END
  END o[455]
  PIN o[456]
    DIRECTION OUTPUT ;
    USE SIGNAL ;
    PORT
      LAYER M4 ;
        RECT  0 52.56 0.084 52.584 ;
    END
  END o[456]
  PIN o[457]
    DIRECTION OUTPUT ;
    USE SIGNAL ;
    PORT
      LAYER M4 ;
        RECT  0 52.656 0.084 52.68 ;
    END
  END o[457]
  PIN o[458]
    DIRECTION OUTPUT ;
    USE SIGNAL ;
    PORT
      LAYER M4 ;
        RECT  0 52.752 0.084 52.776 ;
    END
  END o[458]
  PIN o[459]
    DIRECTION OUTPUT ;
    USE SIGNAL ;
    PORT
      LAYER M4 ;
        RECT  0 52.848 0.084 52.872 ;
    END
  END o[459]
  PIN o[45]
    DIRECTION OUTPUT ;
    USE SIGNAL ;
    PORT
      LAYER M4 ;
        RECT  0 23.856 0.084 23.88 ;
    END
  END o[45]
  PIN o[460]
    DIRECTION OUTPUT ;
    USE SIGNAL ;
    PORT
      LAYER M4 ;
        RECT  0 52.944 0.084 52.968 ;
    END
  END o[460]
  PIN o[461]
    DIRECTION OUTPUT ;
    USE SIGNAL ;
    PORT
      LAYER M4 ;
        RECT  0 53.04 0.084 53.064 ;
    END
  END o[461]
  PIN o[462]
    DIRECTION OUTPUT ;
    USE SIGNAL ;
    PORT
      LAYER M4 ;
        RECT  0 53.136 0.084 53.16 ;
    END
  END o[462]
  PIN o[463]
    DIRECTION OUTPUT ;
    USE SIGNAL ;
    PORT
      LAYER M4 ;
        RECT  0 53.232 0.084 53.256 ;
    END
  END o[463]
  PIN o[464]
    DIRECTION OUTPUT ;
    USE SIGNAL ;
    PORT
      LAYER M4 ;
        RECT  0 53.328 0.084 53.352 ;
    END
  END o[464]
  PIN o[465]
    DIRECTION OUTPUT ;
    USE SIGNAL ;
    PORT
      LAYER M4 ;
        RECT  0 53.424 0.084 53.448 ;
    END
  END o[465]
  PIN o[466]
    DIRECTION OUTPUT ;
    USE SIGNAL ;
    PORT
      LAYER M4 ;
        RECT  0 53.52 0.084 53.544 ;
    END
  END o[466]
  PIN o[467]
    DIRECTION OUTPUT ;
    USE SIGNAL ;
    PORT
      LAYER M4 ;
        RECT  0 53.616 0.084 53.64 ;
    END
  END o[467]
  PIN o[468]
    DIRECTION OUTPUT ;
    USE SIGNAL ;
    PORT
      LAYER M4 ;
        RECT  0 53.712 0.084 53.736 ;
    END
  END o[468]
  PIN o[469]
    DIRECTION OUTPUT ;
    USE SIGNAL ;
    PORT
      LAYER M4 ;
        RECT  0 53.808 0.084 53.832 ;
    END
  END o[469]
  PIN o[46]
    DIRECTION OUTPUT ;
    USE SIGNAL ;
    PORT
      LAYER M4 ;
        RECT  0 23.952 0.084 23.976 ;
    END
  END o[46]
  PIN o[470]
    DIRECTION OUTPUT ;
    USE SIGNAL ;
    PORT
      LAYER M4 ;
        RECT  0 53.904 0.084 53.928 ;
    END
  END o[470]
  PIN o[471]
    DIRECTION OUTPUT ;
    USE SIGNAL ;
    PORT
      LAYER M4 ;
        RECT  0 54 0.084 54.024 ;
    END
  END o[471]
  PIN o[472]
    DIRECTION OUTPUT ;
    USE SIGNAL ;
    PORT
      LAYER M4 ;
        RECT  0 54.096 0.084 54.12 ;
    END
  END o[472]
  PIN o[473]
    DIRECTION OUTPUT ;
    USE SIGNAL ;
    PORT
      LAYER M4 ;
        RECT  0 54.192 0.084 54.216 ;
    END
  END o[473]
  PIN o[474]
    DIRECTION OUTPUT ;
    USE SIGNAL ;
    PORT
      LAYER M4 ;
        RECT  0 54.288 0.084 54.312 ;
    END
  END o[474]
  PIN o[475]
    DIRECTION OUTPUT ;
    USE SIGNAL ;
    PORT
      LAYER M4 ;
        RECT  0 54.384 0.084 54.408 ;
    END
  END o[475]
  PIN o[476]
    DIRECTION OUTPUT ;
    USE SIGNAL ;
    PORT
      LAYER M4 ;
        RECT  0 54.48 0.084 54.504 ;
    END
  END o[476]
  PIN o[477]
    DIRECTION OUTPUT ;
    USE SIGNAL ;
    PORT
      LAYER M4 ;
        RECT  0 54.576 0.084 54.6 ;
    END
  END o[477]
  PIN o[478]
    DIRECTION OUTPUT ;
    USE SIGNAL ;
    PORT
      LAYER M4 ;
        RECT  0 54.672 0.084 54.696 ;
    END
  END o[478]
  PIN o[479]
    DIRECTION OUTPUT ;
    USE SIGNAL ;
    PORT
      LAYER M4 ;
        RECT  0 54.768 0.084 54.792 ;
    END
  END o[479]
  PIN o[47]
    DIRECTION OUTPUT ;
    USE SIGNAL ;
    PORT
      LAYER M4 ;
        RECT  0 24.048 0.084 24.072 ;
    END
  END o[47]
  PIN o[480]
    DIRECTION OUTPUT ;
    USE SIGNAL ;
    PORT
      LAYER M4 ;
        RECT  0 54.864 0.084 54.888 ;
    END
  END o[480]
  PIN o[481]
    DIRECTION OUTPUT ;
    USE SIGNAL ;
    PORT
      LAYER M4 ;
        RECT  0 54.96 0.084 54.984 ;
    END
  END o[481]
  PIN o[482]
    DIRECTION OUTPUT ;
    USE SIGNAL ;
    PORT
      LAYER M4 ;
        RECT  0 55.056 0.084 55.08 ;
    END
  END o[482]
  PIN o[483]
    DIRECTION OUTPUT ;
    USE SIGNAL ;
    PORT
      LAYER M4 ;
        RECT  0 55.152 0.084 55.176 ;
    END
  END o[483]
  PIN o[484]
    DIRECTION OUTPUT ;
    USE SIGNAL ;
    PORT
      LAYER M4 ;
        RECT  0 55.248 0.084 55.272 ;
    END
  END o[484]
  PIN o[485]
    DIRECTION OUTPUT ;
    USE SIGNAL ;
    PORT
      LAYER M4 ;
        RECT  0 55.344 0.084 55.368 ;
    END
  END o[485]
  PIN o[486]
    DIRECTION OUTPUT ;
    USE SIGNAL ;
    PORT
      LAYER M4 ;
        RECT  0 55.44 0.084 55.464 ;
    END
  END o[486]
  PIN o[487]
    DIRECTION OUTPUT ;
    USE SIGNAL ;
    PORT
      LAYER M4 ;
        RECT  0 55.536 0.084 55.56 ;
    END
  END o[487]
  PIN o[488]
    DIRECTION OUTPUT ;
    USE SIGNAL ;
    PORT
      LAYER M4 ;
        RECT  0 55.632 0.084 55.656 ;
    END
  END o[488]
  PIN o[489]
    DIRECTION OUTPUT ;
    USE SIGNAL ;
    PORT
      LAYER M4 ;
        RECT  0 55.728 0.084 55.752 ;
    END
  END o[489]
  PIN o[48]
    DIRECTION OUTPUT ;
    USE SIGNAL ;
    PORT
      LAYER M4 ;
        RECT  0 24.144 0.084 24.168 ;
    END
  END o[48]
  PIN o[490]
    DIRECTION OUTPUT ;
    USE SIGNAL ;
    PORT
      LAYER M4 ;
        RECT  0 55.824 0.084 55.848 ;
    END
  END o[490]
  PIN o[491]
    DIRECTION OUTPUT ;
    USE SIGNAL ;
    PORT
      LAYER M4 ;
        RECT  0 55.92 0.084 55.944 ;
    END
  END o[491]
  PIN o[492]
    DIRECTION OUTPUT ;
    USE SIGNAL ;
    PORT
      LAYER M4 ;
        RECT  0 56.016 0.084 56.04 ;
    END
  END o[492]
  PIN o[493]
    DIRECTION OUTPUT ;
    USE SIGNAL ;
    PORT
      LAYER M4 ;
        RECT  0 56.112 0.084 56.136 ;
    END
  END o[493]
  PIN o[494]
    DIRECTION OUTPUT ;
    USE SIGNAL ;
    PORT
      LAYER M4 ;
        RECT  0 56.208 0.084 56.232 ;
    END
  END o[494]
  PIN o[495]
    DIRECTION OUTPUT ;
    USE SIGNAL ;
    PORT
      LAYER M4 ;
        RECT  0 56.304 0.084 56.328 ;
    END
  END o[495]
  PIN o[496]
    DIRECTION OUTPUT ;
    USE SIGNAL ;
    PORT
      LAYER M4 ;
        RECT  0 56.4 0.084 56.424 ;
    END
  END o[496]
  PIN o[497]
    DIRECTION OUTPUT ;
    USE SIGNAL ;
    PORT
      LAYER M4 ;
        RECT  0 56.496 0.084 56.52 ;
    END
  END o[497]
  PIN o[498]
    DIRECTION OUTPUT ;
    USE SIGNAL ;
    PORT
      LAYER M4 ;
        RECT  0 56.592 0.084 56.616 ;
    END
  END o[498]
  PIN o[499]
    DIRECTION OUTPUT ;
    USE SIGNAL ;
    PORT
      LAYER M4 ;
        RECT  0 56.688 0.084 56.712 ;
    END
  END o[499]
  PIN o[49]
    DIRECTION OUTPUT ;
    USE SIGNAL ;
    PORT
      LAYER M4 ;
        RECT  0 24.24 0.084 24.264 ;
    END
  END o[49]
  PIN o[4]
    DIRECTION OUTPUT ;
    USE SIGNAL ;
    PORT
      LAYER M4 ;
        RECT  0 13.776 0.084 13.8 ;
    END
  END o[4]
  PIN o[500]
    DIRECTION OUTPUT ;
    USE SIGNAL ;
    PORT
      LAYER M4 ;
        RECT  0 56.784 0.084 56.808 ;
    END
  END o[500]
  PIN o[501]
    DIRECTION OUTPUT ;
    USE SIGNAL ;
    PORT
      LAYER M4 ;
        RECT  0 56.88 0.084 56.904 ;
    END
  END o[501]
  PIN o[502]
    DIRECTION OUTPUT ;
    USE SIGNAL ;
    PORT
      LAYER M4 ;
        RECT  0 56.976 0.084 57 ;
    END
  END o[502]
  PIN o[503]
    DIRECTION OUTPUT ;
    USE SIGNAL ;
    PORT
      LAYER M4 ;
        RECT  0 57.072 0.084 57.096 ;
    END
  END o[503]
  PIN o[504]
    DIRECTION OUTPUT ;
    USE SIGNAL ;
    PORT
      LAYER M4 ;
        RECT  0 57.168 0.084 57.192 ;
    END
  END o[504]
  PIN o[505]
    DIRECTION OUTPUT ;
    USE SIGNAL ;
    PORT
      LAYER M4 ;
        RECT  0 57.264 0.084 57.288 ;
    END
  END o[505]
  PIN o[506]
    DIRECTION OUTPUT ;
    USE SIGNAL ;
    PORT
      LAYER M4 ;
        RECT  0 57.36 0.084 57.384 ;
    END
  END o[506]
  PIN o[507]
    DIRECTION OUTPUT ;
    USE SIGNAL ;
    PORT
      LAYER M4 ;
        RECT  0 57.456 0.084 57.48 ;
    END
  END o[507]
  PIN o[508]
    DIRECTION OUTPUT ;
    USE SIGNAL ;
    PORT
      LAYER M4 ;
        RECT  0 57.552 0.084 57.576 ;
    END
  END o[508]
  PIN o[509]
    DIRECTION OUTPUT ;
    USE SIGNAL ;
    PORT
      LAYER M4 ;
        RECT  0 57.648 0.084 57.672 ;
    END
  END o[509]
  PIN o[50]
    DIRECTION OUTPUT ;
    USE SIGNAL ;
    PORT
      LAYER M4 ;
        RECT  0 24.336 0.084 24.36 ;
    END
  END o[50]
  PIN o[510]
    DIRECTION OUTPUT ;
    USE SIGNAL ;
    PORT
      LAYER M4 ;
        RECT  0 57.744 0.084 57.768 ;
    END
  END o[510]
  PIN o[511]
    DIRECTION OUTPUT ;
    USE SIGNAL ;
    PORT
      LAYER M4 ;
        RECT  0 57.84 0.084 57.864 ;
    END
  END o[511]
  PIN o[512]
    DIRECTION OUTPUT ;
    USE SIGNAL ;
    PORT
      LAYER M4 ;
        RECT  0 48.72 0.084 48.744 ;
    END
  END o[512]
  PIN o[513]
    DIRECTION OUTPUT ;
    USE SIGNAL ;
    PORT
      LAYER M4 ;
        RECT  0 48.816 0.084 48.84 ;
    END
  END o[513]
  PIN o[514]
    DIRECTION OUTPUT ;
    USE SIGNAL ;
    PORT
      LAYER M4 ;
        RECT  0 48.912 0.084 48.936 ;
    END
  END o[514]
  PIN o[515]
    DIRECTION OUTPUT ;
    USE SIGNAL ;
    PORT
      LAYER M4 ;
        RECT  0 49.008 0.084 49.032 ;
    END
  END o[515]
  PIN o[516]
    DIRECTION OUTPUT ;
    USE SIGNAL ;
    PORT
      LAYER M4 ;
        RECT  0 49.104 0.084 49.128 ;
    END
  END o[516]
  PIN o[517]
    DIRECTION OUTPUT ;
    USE SIGNAL ;
    PORT
      LAYER M4 ;
        RECT  0 49.2 0.084 49.224 ;
    END
  END o[517]
  PIN o[518]
    DIRECTION OUTPUT ;
    USE SIGNAL ;
    PORT
      LAYER M4 ;
        RECT  0 49.296 0.084 49.32 ;
    END
  END o[518]
  PIN o[519]
    DIRECTION OUTPUT ;
    USE SIGNAL ;
    PORT
      LAYER M4 ;
        RECT  0 49.392 0.084 49.416 ;
    END
  END o[519]
  PIN o[51]
    DIRECTION OUTPUT ;
    USE SIGNAL ;
    PORT
      LAYER M4 ;
        RECT  0 24.432 0.084 24.456 ;
    END
  END o[51]
  PIN o[520]
    DIRECTION OUTPUT ;
    USE SIGNAL ;
    PORT
      LAYER M4 ;
        RECT  0 49.488 0.084 49.512 ;
    END
  END o[520]
  PIN o[521]
    DIRECTION OUTPUT ;
    USE SIGNAL ;
    PORT
      LAYER M4 ;
        RECT  0 49.584 0.084 49.608 ;
    END
  END o[521]
  PIN o[522]
    DIRECTION OUTPUT ;
    USE SIGNAL ;
    PORT
      LAYER M4 ;
        RECT  0 49.68 0.084 49.704 ;
    END
  END o[522]
  PIN o[523]
    DIRECTION OUTPUT ;
    USE SIGNAL ;
    PORT
      LAYER M4 ;
        RECT  0 49.776 0.084 49.8 ;
    END
  END o[523]
  PIN o[524]
    DIRECTION OUTPUT ;
    USE SIGNAL ;
    PORT
      LAYER M4 ;
        RECT  0 49.872 0.084 49.896 ;
    END
  END o[524]
  PIN o[525]
    DIRECTION OUTPUT ;
    USE SIGNAL ;
    PORT
      LAYER M4 ;
        RECT  0 49.968 0.084 49.992 ;
    END
  END o[525]
  PIN o[526]
    DIRECTION OUTPUT ;
    USE SIGNAL ;
    PORT
      LAYER M4 ;
        RECT  0 50.064 0.084 50.088 ;
    END
  END o[526]
  PIN o[527]
    DIRECTION OUTPUT ;
    USE SIGNAL ;
    PORT
      LAYER M4 ;
        RECT  0 50.16 0.084 50.184 ;
    END
  END o[527]
  PIN o[528]
    DIRECTION OUTPUT ;
    USE SIGNAL ;
    PORT
      LAYER M4 ;
        RECT  0 50.256 0.084 50.28 ;
    END
  END o[528]
  PIN o[529]
    DIRECTION OUTPUT ;
    USE SIGNAL ;
    PORT
      LAYER M4 ;
        RECT  0 50.352 0.084 50.376 ;
    END
  END o[529]
  PIN o[52]
    DIRECTION OUTPUT ;
    USE SIGNAL ;
    PORT
      LAYER M4 ;
        RECT  0 24.528 0.084 24.552 ;
    END
  END o[52]
  PIN o[530]
    DIRECTION OUTPUT ;
    USE SIGNAL ;
    PORT
      LAYER M4 ;
        RECT  0 50.448 0.084 50.472 ;
    END
  END o[530]
  PIN o[531]
    DIRECTION OUTPUT ;
    USE SIGNAL ;
    PORT
      LAYER M4 ;
        RECT  0 50.544 0.084 50.568 ;
    END
  END o[531]
  PIN o[532]
    DIRECTION OUTPUT ;
    USE SIGNAL ;
    PORT
      LAYER M4 ;
        RECT  0 50.64 0.084 50.664 ;
    END
  END o[532]
  PIN o[533]
    DIRECTION OUTPUT ;
    USE SIGNAL ;
    PORT
      LAYER M4 ;
        RECT  0 50.736 0.084 50.76 ;
    END
  END o[533]
  PIN o[534]
    DIRECTION OUTPUT ;
    USE SIGNAL ;
    PORT
      LAYER M4 ;
        RECT  0 50.832 0.084 50.856 ;
    END
  END o[534]
  PIN o[535]
    DIRECTION OUTPUT ;
    USE SIGNAL ;
    PORT
      LAYER M4 ;
        RECT  0 50.928 0.084 50.952 ;
    END
  END o[535]
  PIN o[536]
    DIRECTION OUTPUT ;
    USE SIGNAL ;
    PORT
      LAYER M4 ;
        RECT  0 51.024 0.084 51.048 ;
    END
  END o[536]
  PIN o[537]
    DIRECTION OUTPUT ;
    USE SIGNAL ;
    PORT
      LAYER M4 ;
        RECT  0 51.12 0.084 51.144 ;
    END
  END o[537]
  PIN o[538]
    DIRECTION OUTPUT ;
    USE SIGNAL ;
    PORT
      LAYER M4 ;
        RECT  0 51.216 0.084 51.24 ;
    END
  END o[538]
  PIN o[539]
    DIRECTION OUTPUT ;
    USE SIGNAL ;
    PORT
      LAYER M4 ;
        RECT  0 51.312 0.084 51.336 ;
    END
  END o[539]
  PIN o[53]
    DIRECTION OUTPUT ;
    USE SIGNAL ;
    PORT
      LAYER M4 ;
        RECT  0 24.624 0.084 24.648 ;
    END
  END o[53]
  PIN o[540]
    DIRECTION OUTPUT ;
    USE SIGNAL ;
    PORT
      LAYER M4 ;
        RECT  0 51.408 0.084 51.432 ;
    END
  END o[540]
  PIN o[541]
    DIRECTION OUTPUT ;
    USE SIGNAL ;
    PORT
      LAYER M4 ;
        RECT  0 51.504 0.084 51.528 ;
    END
  END o[541]
  PIN o[542]
    DIRECTION OUTPUT ;
    USE SIGNAL ;
    PORT
      LAYER M4 ;
        RECT  0 51.6 0.084 51.624 ;
    END
  END o[542]
  PIN o[543]
    DIRECTION OUTPUT ;
    USE SIGNAL ;
    PORT
      LAYER M4 ;
        RECT  0 51.696 0.084 51.72 ;
    END
  END o[543]
  PIN o[544]
    DIRECTION OUTPUT ;
    USE SIGNAL ;
    PORT
      LAYER M4 ;
        RECT  0 45.648 0.084 45.672 ;
    END
  END o[544]
  PIN o[545]
    DIRECTION OUTPUT ;
    USE SIGNAL ;
    PORT
      LAYER M4 ;
        RECT  0 45.744 0.084 45.768 ;
    END
  END o[545]
  PIN o[546]
    DIRECTION OUTPUT ;
    USE SIGNAL ;
    PORT
      LAYER M4 ;
        RECT  0 45.84 0.084 45.864 ;
    END
  END o[546]
  PIN o[547]
    DIRECTION OUTPUT ;
    USE SIGNAL ;
    PORT
      LAYER M4 ;
        RECT  0 45.936 0.084 45.96 ;
    END
  END o[547]
  PIN o[548]
    DIRECTION OUTPUT ;
    USE SIGNAL ;
    PORT
      LAYER M4 ;
        RECT  0 46.032 0.084 46.056 ;
    END
  END o[548]
  PIN o[549]
    DIRECTION OUTPUT ;
    USE SIGNAL ;
    PORT
      LAYER M4 ;
        RECT  0 46.128 0.084 46.152 ;
    END
  END o[549]
  PIN o[54]
    DIRECTION OUTPUT ;
    USE SIGNAL ;
    PORT
      LAYER M4 ;
        RECT  0 24.72 0.084 24.744 ;
    END
  END o[54]
  PIN o[550]
    DIRECTION OUTPUT ;
    USE SIGNAL ;
    PORT
      LAYER M4 ;
        RECT  0 46.224 0.084 46.248 ;
    END
  END o[550]
  PIN o[551]
    DIRECTION OUTPUT ;
    USE SIGNAL ;
    PORT
      LAYER M4 ;
        RECT  0 46.32 0.084 46.344 ;
    END
  END o[551]
  PIN o[552]
    DIRECTION OUTPUT ;
    USE SIGNAL ;
    PORT
      LAYER M4 ;
        RECT  0 46.416 0.084 46.44 ;
    END
  END o[552]
  PIN o[553]
    DIRECTION OUTPUT ;
    USE SIGNAL ;
    PORT
      LAYER M4 ;
        RECT  0 46.512 0.084 46.536 ;
    END
  END o[553]
  PIN o[554]
    DIRECTION OUTPUT ;
    USE SIGNAL ;
    PORT
      LAYER M4 ;
        RECT  0 46.608 0.084 46.632 ;
    END
  END o[554]
  PIN o[555]
    DIRECTION OUTPUT ;
    USE SIGNAL ;
    PORT
      LAYER M4 ;
        RECT  0 46.704 0.084 46.728 ;
    END
  END o[555]
  PIN o[556]
    DIRECTION OUTPUT ;
    USE SIGNAL ;
    PORT
      LAYER M4 ;
        RECT  0 46.8 0.084 46.824 ;
    END
  END o[556]
  PIN o[557]
    DIRECTION OUTPUT ;
    USE SIGNAL ;
    PORT
      LAYER M4 ;
        RECT  0 46.896 0.084 46.92 ;
    END
  END o[557]
  PIN o[558]
    DIRECTION OUTPUT ;
    USE SIGNAL ;
    PORT
      LAYER M4 ;
        RECT  0 46.992 0.084 47.016 ;
    END
  END o[558]
  PIN o[559]
    DIRECTION OUTPUT ;
    USE SIGNAL ;
    PORT
      LAYER M4 ;
        RECT  0 47.088 0.084 47.112 ;
    END
  END o[559]
  PIN o[55]
    DIRECTION OUTPUT ;
    USE SIGNAL ;
    PORT
      LAYER M4 ;
        RECT  0 24.816 0.084 24.84 ;
    END
  END o[55]
  PIN o[560]
    DIRECTION OUTPUT ;
    USE SIGNAL ;
    PORT
      LAYER M4 ;
        RECT  0 47.184 0.084 47.208 ;
    END
  END o[560]
  PIN o[561]
    DIRECTION OUTPUT ;
    USE SIGNAL ;
    PORT
      LAYER M4 ;
        RECT  0 47.28 0.084 47.304 ;
    END
  END o[561]
  PIN o[562]
    DIRECTION OUTPUT ;
    USE SIGNAL ;
    PORT
      LAYER M4 ;
        RECT  0 47.376 0.084 47.4 ;
    END
  END o[562]
  PIN o[563]
    DIRECTION OUTPUT ;
    USE SIGNAL ;
    PORT
      LAYER M4 ;
        RECT  0 47.472 0.084 47.496 ;
    END
  END o[563]
  PIN o[564]
    DIRECTION OUTPUT ;
    USE SIGNAL ;
    PORT
      LAYER M4 ;
        RECT  0 47.568 0.084 47.592 ;
    END
  END o[564]
  PIN o[565]
    DIRECTION OUTPUT ;
    USE SIGNAL ;
    PORT
      LAYER M4 ;
        RECT  0 47.664 0.084 47.688 ;
    END
  END o[565]
  PIN o[566]
    DIRECTION OUTPUT ;
    USE SIGNAL ;
    PORT
      LAYER M4 ;
        RECT  0 47.76 0.084 47.784 ;
    END
  END o[566]
  PIN o[567]
    DIRECTION OUTPUT ;
    USE SIGNAL ;
    PORT
      LAYER M4 ;
        RECT  0 47.856 0.084 47.88 ;
    END
  END o[567]
  PIN o[568]
    DIRECTION OUTPUT ;
    USE SIGNAL ;
    PORT
      LAYER M4 ;
        RECT  0 47.952 0.084 47.976 ;
    END
  END o[568]
  PIN o[569]
    DIRECTION OUTPUT ;
    USE SIGNAL ;
    PORT
      LAYER M4 ;
        RECT  0 48.048 0.084 48.072 ;
    END
  END o[569]
  PIN o[56]
    DIRECTION OUTPUT ;
    USE SIGNAL ;
    PORT
      LAYER M4 ;
        RECT  0 24.912 0.084 24.936 ;
    END
  END o[56]
  PIN o[570]
    DIRECTION OUTPUT ;
    USE SIGNAL ;
    PORT
      LAYER M4 ;
        RECT  0 48.144 0.084 48.168 ;
    END
  END o[570]
  PIN o[571]
    DIRECTION OUTPUT ;
    USE SIGNAL ;
    PORT
      LAYER M4 ;
        RECT  0 48.24 0.084 48.264 ;
    END
  END o[571]
  PIN o[572]
    DIRECTION OUTPUT ;
    USE SIGNAL ;
    PORT
      LAYER M4 ;
        RECT  0 48.336 0.084 48.36 ;
    END
  END o[572]
  PIN o[573]
    DIRECTION OUTPUT ;
    USE SIGNAL ;
    PORT
      LAYER M4 ;
        RECT  0 48.432 0.084 48.456 ;
    END
  END o[573]
  PIN o[574]
    DIRECTION OUTPUT ;
    USE SIGNAL ;
    PORT
      LAYER M4 ;
        RECT  0 48.528 0.084 48.552 ;
    END
  END o[574]
  PIN o[575]
    DIRECTION OUTPUT ;
    USE SIGNAL ;
    PORT
      LAYER M4 ;
        RECT  0 48.624 0.084 48.648 ;
    END
  END o[575]
  PIN o[576]
    DIRECTION OUTPUT ;
    USE SIGNAL ;
    PORT
      LAYER M4 ;
        RECT  0 3.408 0.084 3.432 ;
    END
  END o[576]
  PIN o[577]
    DIRECTION OUTPUT ;
    USE SIGNAL ;
    PORT
      LAYER M4 ;
        RECT  0 3.504 0.084 3.528 ;
    END
  END o[577]
  PIN o[578]
    DIRECTION OUTPUT ;
    USE SIGNAL ;
    PORT
      LAYER M4 ;
        RECT  0 3.6 0.084 3.624 ;
    END
  END o[578]
  PIN o[579]
    DIRECTION OUTPUT ;
    USE SIGNAL ;
    PORT
      LAYER M4 ;
        RECT  0 3.696 0.084 3.72 ;
    END
  END o[579]
  PIN o[57]
    DIRECTION OUTPUT ;
    USE SIGNAL ;
    PORT
      LAYER M4 ;
        RECT  0 25.008 0.084 25.032 ;
    END
  END o[57]
  PIN o[580]
    DIRECTION OUTPUT ;
    USE SIGNAL ;
    PORT
      LAYER M4 ;
        RECT  0 3.792 0.084 3.816 ;
    END
  END o[580]
  PIN o[581]
    DIRECTION OUTPUT ;
    USE SIGNAL ;
    PORT
      LAYER M4 ;
        RECT  0 3.888 0.084 3.912 ;
    END
  END o[581]
  PIN o[582]
    DIRECTION OUTPUT ;
    USE SIGNAL ;
    PORT
      LAYER M4 ;
        RECT  0 3.984 0.084 4.008 ;
    END
  END o[582]
  PIN o[583]
    DIRECTION OUTPUT ;
    USE SIGNAL ;
    PORT
      LAYER M4 ;
        RECT  0 4.08 0.084 4.104 ;
    END
  END o[583]
  PIN o[584]
    DIRECTION OUTPUT ;
    USE SIGNAL ;
    PORT
      LAYER M4 ;
        RECT  0 4.176 0.084 4.2 ;
    END
  END o[584]
  PIN o[585]
    DIRECTION OUTPUT ;
    USE SIGNAL ;
    PORT
      LAYER M4 ;
        RECT  0 4.272 0.084 4.296 ;
    END
  END o[585]
  PIN o[586]
    DIRECTION OUTPUT ;
    USE SIGNAL ;
    PORT
      LAYER M4 ;
        RECT  0 4.368 0.084 4.392 ;
    END
  END o[586]
  PIN o[587]
    DIRECTION OUTPUT ;
    USE SIGNAL ;
    PORT
      LAYER M4 ;
        RECT  0 4.464 0.084 4.488 ;
    END
  END o[587]
  PIN o[588]
    DIRECTION OUTPUT ;
    USE SIGNAL ;
    PORT
      LAYER M4 ;
        RECT  0 4.56 0.084 4.584 ;
    END
  END o[588]
  PIN o[589]
    DIRECTION OUTPUT ;
    USE SIGNAL ;
    PORT
      LAYER M4 ;
        RECT  0 4.656 0.084 4.68 ;
    END
  END o[589]
  PIN o[58]
    DIRECTION OUTPUT ;
    USE SIGNAL ;
    PORT
      LAYER M4 ;
        RECT  0 25.104 0.084 25.128 ;
    END
  END o[58]
  PIN o[590]
    DIRECTION OUTPUT ;
    USE SIGNAL ;
    PORT
      LAYER M4 ;
        RECT  0 4.752 0.084 4.776 ;
    END
  END o[590]
  PIN o[591]
    DIRECTION OUTPUT ;
    USE SIGNAL ;
    PORT
      LAYER M4 ;
        RECT  0 4.848 0.084 4.872 ;
    END
  END o[591]
  PIN o[592]
    DIRECTION OUTPUT ;
    USE SIGNAL ;
    PORT
      LAYER M4 ;
        RECT  0 4.944 0.084 4.968 ;
    END
  END o[592]
  PIN o[593]
    DIRECTION OUTPUT ;
    USE SIGNAL ;
    PORT
      LAYER M4 ;
        RECT  0 5.04 0.084 5.064 ;
    END
  END o[593]
  PIN o[594]
    DIRECTION OUTPUT ;
    USE SIGNAL ;
    PORT
      LAYER M4 ;
        RECT  0 5.136 0.084 5.16 ;
    END
  END o[594]
  PIN o[595]
    DIRECTION OUTPUT ;
    USE SIGNAL ;
    PORT
      LAYER M4 ;
        RECT  0 5.232 0.084 5.256 ;
    END
  END o[595]
  PIN o[596]
    DIRECTION OUTPUT ;
    USE SIGNAL ;
    PORT
      LAYER M4 ;
        RECT  0 5.328 0.084 5.352 ;
    END
  END o[596]
  PIN o[597]
    DIRECTION OUTPUT ;
    USE SIGNAL ;
    PORT
      LAYER M4 ;
        RECT  0 5.424 0.084 5.448 ;
    END
  END o[597]
  PIN o[598]
    DIRECTION OUTPUT ;
    USE SIGNAL ;
    PORT
      LAYER M4 ;
        RECT  0 5.52 0.084 5.544 ;
    END
  END o[598]
  PIN o[599]
    DIRECTION OUTPUT ;
    USE SIGNAL ;
    PORT
      LAYER M4 ;
        RECT  0 5.616 0.084 5.64 ;
    END
  END o[599]
  PIN o[59]
    DIRECTION OUTPUT ;
    USE SIGNAL ;
    PORT
      LAYER M4 ;
        RECT  0 25.2 0.084 25.224 ;
    END
  END o[59]
  PIN o[5]
    DIRECTION OUTPUT ;
    USE SIGNAL ;
    PORT
      LAYER M4 ;
        RECT  0 13.872 0.084 13.896 ;
    END
  END o[5]
  PIN o[600]
    DIRECTION OUTPUT ;
    USE SIGNAL ;
    PORT
      LAYER M4 ;
        RECT  0 5.712 0.084 5.736 ;
    END
  END o[600]
  PIN o[601]
    DIRECTION OUTPUT ;
    USE SIGNAL ;
    PORT
      LAYER M4 ;
        RECT  0 5.808 0.084 5.832 ;
    END
  END o[601]
  PIN o[602]
    DIRECTION OUTPUT ;
    USE SIGNAL ;
    PORT
      LAYER M4 ;
        RECT  0 5.904 0.084 5.928 ;
    END
  END o[602]
  PIN o[603]
    DIRECTION OUTPUT ;
    USE SIGNAL ;
    PORT
      LAYER M4 ;
        RECT  0 6 0.084 6.024 ;
    END
  END o[603]
  PIN o[604]
    DIRECTION OUTPUT ;
    USE SIGNAL ;
    PORT
      LAYER M4 ;
        RECT  0 6.096 0.084 6.12 ;
    END
  END o[604]
  PIN o[605]
    DIRECTION OUTPUT ;
    USE SIGNAL ;
    PORT
      LAYER M4 ;
        RECT  0 6.192 0.084 6.216 ;
    END
  END o[605]
  PIN o[606]
    DIRECTION OUTPUT ;
    USE SIGNAL ;
    PORT
      LAYER M4 ;
        RECT  0 6.288 0.084 6.312 ;
    END
  END o[606]
  PIN o[607]
    DIRECTION OUTPUT ;
    USE SIGNAL ;
    PORT
      LAYER M4 ;
        RECT  0 6.384 0.084 6.408 ;
    END
  END o[607]
  PIN o[608]
    DIRECTION OUTPUT ;
    USE SIGNAL ;
    PORT
      LAYER M4 ;
        RECT  0 1.776 0.084 1.8 ;
    END
  END o[608]
  PIN o[609]
    DIRECTION OUTPUT ;
    USE SIGNAL ;
    PORT
      LAYER M4 ;
        RECT  0 1.872 0.084 1.896 ;
    END
  END o[609]
  PIN o[60]
    DIRECTION OUTPUT ;
    USE SIGNAL ;
    PORT
      LAYER M4 ;
        RECT  0 25.296 0.084 25.32 ;
    END
  END o[60]
  PIN o[610]
    DIRECTION OUTPUT ;
    USE SIGNAL ;
    PORT
      LAYER M4 ;
        RECT  0 1.968 0.084 1.992 ;
    END
  END o[610]
  PIN o[611]
    DIRECTION OUTPUT ;
    USE SIGNAL ;
    PORT
      LAYER M4 ;
        RECT  0 2.064 0.084 2.088 ;
    END
  END o[611]
  PIN o[612]
    DIRECTION OUTPUT ;
    USE SIGNAL ;
    PORT
      LAYER M4 ;
        RECT  0 2.16 0.084 2.184 ;
    END
  END o[612]
  PIN o[613]
    DIRECTION OUTPUT ;
    USE SIGNAL ;
    PORT
      LAYER M4 ;
        RECT  0 2.256 0.084 2.28 ;
    END
  END o[613]
  PIN o[614]
    DIRECTION OUTPUT ;
    USE SIGNAL ;
    PORT
      LAYER M4 ;
        RECT  0 2.352 0.084 2.376 ;
    END
  END o[614]
  PIN o[615]
    DIRECTION OUTPUT ;
    USE SIGNAL ;
    PORT
      LAYER M4 ;
        RECT  0 2.448 0.084 2.472 ;
    END
  END o[615]
  PIN o[616]
    DIRECTION OUTPUT ;
    USE SIGNAL ;
    PORT
      LAYER M4 ;
        RECT  0 2.544 0.084 2.568 ;
    END
  END o[616]
  PIN o[617]
    DIRECTION OUTPUT ;
    USE SIGNAL ;
    PORT
      LAYER M4 ;
        RECT  0 2.64 0.084 2.664 ;
    END
  END o[617]
  PIN o[618]
    DIRECTION OUTPUT ;
    USE SIGNAL ;
    PORT
      LAYER M4 ;
        RECT  0 2.736 0.084 2.76 ;
    END
  END o[618]
  PIN o[619]
    DIRECTION OUTPUT ;
    USE SIGNAL ;
    PORT
      LAYER M4 ;
        RECT  0 2.832 0.084 2.856 ;
    END
  END o[619]
  PIN o[61]
    DIRECTION OUTPUT ;
    USE SIGNAL ;
    PORT
      LAYER M4 ;
        RECT  0 25.392 0.084 25.416 ;
    END
  END o[61]
  PIN o[620]
    DIRECTION OUTPUT ;
    USE SIGNAL ;
    PORT
      LAYER M4 ;
        RECT  0 2.928 0.084 2.952 ;
    END
  END o[620]
  PIN o[621]
    DIRECTION OUTPUT ;
    USE SIGNAL ;
    PORT
      LAYER M4 ;
        RECT  0 3.024 0.084 3.048 ;
    END
  END o[621]
  PIN o[622]
    DIRECTION OUTPUT ;
    USE SIGNAL ;
    PORT
      LAYER M4 ;
        RECT  0 3.12 0.084 3.144 ;
    END
  END o[622]
  PIN o[623]
    DIRECTION OUTPUT ;
    USE SIGNAL ;
    PORT
      LAYER M4 ;
        RECT  0 3.216 0.084 3.24 ;
    END
  END o[623]
  PIN o[62]
    DIRECTION OUTPUT ;
    USE SIGNAL ;
    PORT
      LAYER M4 ;
        RECT  0 25.488 0.084 25.512 ;
    END
  END o[62]
  PIN o[63]
    DIRECTION OUTPUT ;
    USE SIGNAL ;
    PORT
      LAYER M4 ;
        RECT  0 25.584 0.084 25.608 ;
    END
  END o[63]
  PIN o[64]
    DIRECTION OUTPUT ;
    USE SIGNAL ;
    PORT
      LAYER M4 ;
        RECT  0 16.464 0.084 16.488 ;
    END
  END o[64]
  PIN o[65]
    DIRECTION OUTPUT ;
    USE SIGNAL ;
    PORT
      LAYER M4 ;
        RECT  0 16.56 0.084 16.584 ;
    END
  END o[65]
  PIN o[66]
    DIRECTION OUTPUT ;
    USE SIGNAL ;
    PORT
      LAYER M4 ;
        RECT  0 16.656 0.084 16.68 ;
    END
  END o[66]
  PIN o[67]
    DIRECTION OUTPUT ;
    USE SIGNAL ;
    PORT
      LAYER M4 ;
        RECT  0 16.752 0.084 16.776 ;
    END
  END o[67]
  PIN o[68]
    DIRECTION OUTPUT ;
    USE SIGNAL ;
    PORT
      LAYER M4 ;
        RECT  0 16.848 0.084 16.872 ;
    END
  END o[68]
  PIN o[69]
    DIRECTION OUTPUT ;
    USE SIGNAL ;
    PORT
      LAYER M4 ;
        RECT  0 16.944 0.084 16.968 ;
    END
  END o[69]
  PIN o[6]
    DIRECTION OUTPUT ;
    USE SIGNAL ;
    PORT
      LAYER M4 ;
        RECT  0 13.968 0.084 13.992 ;
    END
  END o[6]
  PIN o[70]
    DIRECTION OUTPUT ;
    USE SIGNAL ;
    PORT
      LAYER M4 ;
        RECT  0 17.04 0.084 17.064 ;
    END
  END o[70]
  PIN o[71]
    DIRECTION OUTPUT ;
    USE SIGNAL ;
    PORT
      LAYER M4 ;
        RECT  0 17.136 0.084 17.16 ;
    END
  END o[71]
  PIN o[72]
    DIRECTION OUTPUT ;
    USE SIGNAL ;
    PORT
      LAYER M4 ;
        RECT  0 17.232 0.084 17.256 ;
    END
  END o[72]
  PIN o[73]
    DIRECTION OUTPUT ;
    USE SIGNAL ;
    PORT
      LAYER M4 ;
        RECT  0 17.328 0.084 17.352 ;
    END
  END o[73]
  PIN o[74]
    DIRECTION OUTPUT ;
    USE SIGNAL ;
    PORT
      LAYER M4 ;
        RECT  0 17.424 0.084 17.448 ;
    END
  END o[74]
  PIN o[75]
    DIRECTION OUTPUT ;
    USE SIGNAL ;
    PORT
      LAYER M4 ;
        RECT  0 17.52 0.084 17.544 ;
    END
  END o[75]
  PIN o[76]
    DIRECTION OUTPUT ;
    USE SIGNAL ;
    PORT
      LAYER M4 ;
        RECT  0 17.616 0.084 17.64 ;
    END
  END o[76]
  PIN o[77]
    DIRECTION OUTPUT ;
    USE SIGNAL ;
    PORT
      LAYER M4 ;
        RECT  0 17.712 0.084 17.736 ;
    END
  END o[77]
  PIN o[78]
    DIRECTION OUTPUT ;
    USE SIGNAL ;
    PORT
      LAYER M4 ;
        RECT  0 17.808 0.084 17.832 ;
    END
  END o[78]
  PIN o[79]
    DIRECTION OUTPUT ;
    USE SIGNAL ;
    PORT
      LAYER M4 ;
        RECT  0 17.904 0.084 17.928 ;
    END
  END o[79]
  PIN o[7]
    DIRECTION OUTPUT ;
    USE SIGNAL ;
    PORT
      LAYER M4 ;
        RECT  0 14.064 0.084 14.088 ;
    END
  END o[7]
  PIN o[80]
    DIRECTION OUTPUT ;
    USE SIGNAL ;
    PORT
      LAYER M4 ;
        RECT  0 18 0.084 18.024 ;
    END
  END o[80]
  PIN o[81]
    DIRECTION OUTPUT ;
    USE SIGNAL ;
    PORT
      LAYER M4 ;
        RECT  0 18.096 0.084 18.12 ;
    END
  END o[81]
  PIN o[82]
    DIRECTION OUTPUT ;
    USE SIGNAL ;
    PORT
      LAYER M4 ;
        RECT  0 18.192 0.084 18.216 ;
    END
  END o[82]
  PIN o[83]
    DIRECTION OUTPUT ;
    USE SIGNAL ;
    PORT
      LAYER M4 ;
        RECT  0 18.288 0.084 18.312 ;
    END
  END o[83]
  PIN o[84]
    DIRECTION OUTPUT ;
    USE SIGNAL ;
    PORT
      LAYER M4 ;
        RECT  0 18.384 0.084 18.408 ;
    END
  END o[84]
  PIN o[85]
    DIRECTION OUTPUT ;
    USE SIGNAL ;
    PORT
      LAYER M4 ;
        RECT  0 18.48 0.084 18.504 ;
    END
  END o[85]
  PIN o[86]
    DIRECTION OUTPUT ;
    USE SIGNAL ;
    PORT
      LAYER M4 ;
        RECT  0 18.576 0.084 18.6 ;
    END
  END o[86]
  PIN o[87]
    DIRECTION OUTPUT ;
    USE SIGNAL ;
    PORT
      LAYER M4 ;
        RECT  0 18.672 0.084 18.696 ;
    END
  END o[87]
  PIN o[88]
    DIRECTION OUTPUT ;
    USE SIGNAL ;
    PORT
      LAYER M4 ;
        RECT  0 18.768 0.084 18.792 ;
    END
  END o[88]
  PIN o[89]
    DIRECTION OUTPUT ;
    USE SIGNAL ;
    PORT
      LAYER M4 ;
        RECT  0 18.864 0.084 18.888 ;
    END
  END o[89]
  PIN o[8]
    DIRECTION OUTPUT ;
    USE SIGNAL ;
    PORT
      LAYER M4 ;
        RECT  0 14.16 0.084 14.184 ;
    END
  END o[8]
  PIN o[90]
    DIRECTION OUTPUT ;
    USE SIGNAL ;
    PORT
      LAYER M4 ;
        RECT  0 18.96 0.084 18.984 ;
    END
  END o[90]
  PIN o[91]
    DIRECTION OUTPUT ;
    USE SIGNAL ;
    PORT
      LAYER M4 ;
        RECT  0 19.056 0.084 19.08 ;
    END
  END o[91]
  PIN o[92]
    DIRECTION OUTPUT ;
    USE SIGNAL ;
    PORT
      LAYER M4 ;
        RECT  0 19.152 0.084 19.176 ;
    END
  END o[92]
  PIN o[93]
    DIRECTION OUTPUT ;
    USE SIGNAL ;
    PORT
      LAYER M4 ;
        RECT  0 19.248 0.084 19.272 ;
    END
  END o[93]
  PIN o[94]
    DIRECTION OUTPUT ;
    USE SIGNAL ;
    PORT
      LAYER M4 ;
        RECT  0 19.344 0.084 19.368 ;
    END
  END o[94]
  PIN o[95]
    DIRECTION OUTPUT ;
    USE SIGNAL ;
    PORT
      LAYER M4 ;
        RECT  0 19.44 0.084 19.464 ;
    END
  END o[95]
  PIN o[96]
    DIRECTION OUTPUT ;
    USE SIGNAL ;
    PORT
      LAYER M4 ;
        RECT  0 19.536 0.084 19.56 ;
    END
  END o[96]
  PIN o[97]
    DIRECTION OUTPUT ;
    USE SIGNAL ;
    PORT
      LAYER M4 ;
        RECT  0 19.632 0.084 19.656 ;
    END
  END o[97]
  PIN o[98]
    DIRECTION OUTPUT ;
    USE SIGNAL ;
    PORT
      LAYER M4 ;
        RECT  0 19.728 0.084 19.752 ;
    END
  END o[98]
  PIN o[99]
    DIRECTION OUTPUT ;
    USE SIGNAL ;
    PORT
      LAYER M4 ;
        RECT  0 19.824 0.084 19.848 ;
    END
  END o[99]
  PIN o[9]
    DIRECTION OUTPUT ;
    USE SIGNAL ;
    PORT
      LAYER M4 ;
        RECT  0 14.256 0.084 14.28 ;
    END
  END o[9]
  PIN rs
    DIRECTION INPUT ;
    USE SIGNAL ;
    PORT
      LAYER M5 ;
        RECT  11.952 0 11.976 0.084 ;
    END
  END rs
  PIN rso
    DIRECTION OUTPUT ;
    USE SIGNAL ;
    PORT
      LAYER M4 ;
        RECT  0 3.312 0.084 3.336 ;
    END
  END rso
  PIN VDD
    DIRECTION INOUT ;
    USE POWER ;
    PORT
      LAYER M5 ;
        RECT  18.792 2.151 18.912 62.649 ;
        RECT  16.092 2.151 16.212 62.649 ;
        RECT  13.392 2.151 13.512 62.649 ;
        RECT  10.692 2.151 10.812 62.649 ;
        RECT  7.992 2.151 8.112 62.649 ;
        RECT  5.292 2.151 5.412 62.649 ;
        RECT  2.592 2.151 2.712 62.649 ;
    END
  END VDD
  PIN VSS
    DIRECTION INOUT ;
    USE GROUND ;
    PORT
      LAYER M5 ;
        RECT  18.6 2.137 18.72 62.663 ;
        RECT  15.9 2.137 16.02 62.663 ;
        RECT  13.2 2.137 13.32 62.663 ;
        RECT  10.5 2.137 10.62 62.663 ;
        RECT  7.8 2.137 7.92 62.663 ;
        RECT  5.1 2.137 5.22 62.663 ;
        RECT  2.4 2.137 2.52 62.663 ;
    END
  END VSS
  # OT_OBS_CLOSED layer=M5 d_um=1.536 added=91
  OBS
    LAYER RVTN ;
     RECT  2.16 2.16 19.44 2.295 ;
     RECT  2.16 2.565 19.44 2.835 ;
     RECT  2.16 3.105 19.44 3.375 ;
     RECT  2.16 3.645 19.44 3.915 ;
     RECT  2.16 4.185 19.44 4.455 ;
     RECT  2.16 4.725 19.44 4.995 ;
     RECT  2.16 5.265 19.44 5.535 ;
     RECT  2.16 5.805 19.44 6.075 ;
     RECT  2.16 6.345 19.44 6.615 ;
     RECT  2.16 6.885 19.44 7.155 ;
     RECT  2.16 7.425 19.44 7.695 ;
     RECT  2.16 7.965 19.44 8.235 ;
     RECT  2.16 8.505 19.44 8.775 ;
     RECT  2.16 9.045 19.44 9.315 ;
     RECT  2.16 9.585 19.44 9.855 ;
     RECT  2.16 10.125 19.44 10.395 ;
     RECT  2.16 10.665 19.44 10.935 ;
     RECT  2.16 11.205 19.44 11.475 ;
     RECT  2.16 11.745 19.44 12.015 ;
     RECT  2.16 12.285 19.44 12.555 ;
     RECT  2.16 12.825 19.44 13.095 ;
     RECT  2.16 13.365 19.44 13.635 ;
     RECT  2.16 13.905 19.44 14.175 ;
     RECT  2.16 14.445 19.44 14.715 ;
     RECT  2.16 14.985 19.44 15.255 ;
     RECT  2.16 15.525 19.44 15.795 ;
     RECT  2.16 16.065 19.44 16.335 ;
     RECT  2.16 16.605 19.44 16.875 ;
     RECT  2.16 17.145 19.44 17.415 ;
     RECT  2.16 17.685 19.44 17.955 ;
     RECT  2.16 18.225 19.44 18.495 ;
     RECT  2.16 18.765 19.44 19.035 ;
     RECT  2.16 19.305 19.44 19.575 ;
     RECT  2.16 19.845 19.44 20.115 ;
     RECT  2.16 20.385 19.44 20.655 ;
     RECT  2.16 20.925 19.44 21.195 ;
     RECT  2.16 21.465 19.44 21.735 ;
     RECT  2.16 22.005 19.44 22.275 ;
     RECT  2.16 22.545 19.44 22.815 ;
     RECT  2.16 23.085 19.44 23.355 ;
     RECT  2.16 23.625 19.44 23.895 ;
     RECT  2.16 24.165 19.44 24.435 ;
     RECT  2.16 24.705 19.44 24.975 ;
     RECT  2.16 25.245 19.44 25.515 ;
     RECT  2.16 25.785 19.44 26.055 ;
     RECT  2.16 26.325 19.44 26.595 ;
     RECT  2.16 26.865 19.44 27.135 ;
     RECT  2.16 27.405 19.44 27.675 ;
     RECT  2.16 27.945 19.44 28.215 ;
     RECT  2.16 28.485 19.44 28.755 ;
     RECT  2.16 29.025 19.44 29.295 ;
     RECT  2.16 29.565 19.44 29.835 ;
     RECT  2.16 30.105 19.44 30.375 ;
     RECT  2.16 30.645 19.44 30.915 ;
     RECT  2.16 31.185 19.44 31.455 ;
     RECT  2.16 31.725 19.44 31.995 ;
     RECT  2.16 32.265 19.44 32.535 ;
     RECT  2.16 32.805 19.44 33.075 ;
     RECT  2.16 33.345 19.44 33.615 ;
     RECT  2.16 33.885 19.44 34.155 ;
     RECT  2.16 34.425 19.44 34.695 ;
     RECT  2.16 34.965 19.44 35.235 ;
     RECT  2.16 35.505 19.44 35.775 ;
     RECT  2.16 36.045 19.44 36.315 ;
     RECT  2.16 36.585 19.44 36.855 ;
     RECT  2.16 37.125 19.44 37.395 ;
     RECT  2.16 37.665 19.44 37.935 ;
     RECT  2.16 38.205 19.44 38.475 ;
     RECT  2.16 38.745 19.44 39.015 ;
     RECT  2.16 39.285 19.44 39.555 ;
     RECT  2.16 39.825 19.44 40.095 ;
     RECT  2.16 40.365 19.44 40.635 ;
     RECT  2.16 40.905 19.44 41.175 ;
     RECT  2.16 41.445 19.44 41.715 ;
     RECT  2.16 41.985 19.44 42.255 ;
     RECT  2.16 42.525 19.44 42.795 ;
     RECT  2.16 43.065 19.44 43.335 ;
     RECT  2.16 43.605 19.44 43.875 ;
     RECT  2.16 44.145 19.44 44.415 ;
     RECT  2.16 44.685 19.44 44.955 ;
     RECT  2.16 45.225 19.44 45.495 ;
     RECT  2.16 45.765 19.44 46.035 ;
     RECT  2.16 46.305 19.44 46.575 ;
     RECT  2.16 46.845 19.44 47.115 ;
     RECT  2.16 47.385 19.44 47.655 ;
     RECT  2.16 47.925 19.44 48.195 ;
     RECT  2.16 48.465 19.44 48.735 ;
     RECT  2.16 49.005 19.44 49.275 ;
     RECT  2.16 49.545 19.44 49.815 ;
     RECT  2.16 50.085 19.44 50.355 ;
     RECT  2.16 50.625 19.44 50.895 ;
     RECT  2.16 51.165 19.44 51.435 ;
     RECT  2.16 51.705 19.44 51.975 ;
     RECT  2.16 52.245 19.44 52.515 ;
     RECT  2.16 52.785 19.44 53.055 ;
     RECT  2.16 53.325 19.44 53.595 ;
     RECT  2.16 53.865 19.44 54.135 ;
     RECT  2.16 54.405 19.44 54.675 ;
     RECT  2.16 54.945 19.44 55.215 ;
     RECT  2.16 55.485 19.44 55.755 ;
     RECT  2.16 56.025 19.44 56.295 ;
     RECT  2.16 56.565 19.44 56.835 ;
     RECT  2.16 57.105 19.44 57.375 ;
     RECT  2.16 57.645 19.44 57.915 ;
     RECT  2.16 58.185 19.44 58.455 ;
     RECT  2.16 58.725 19.44 58.995 ;
     RECT  2.16 59.265 19.44 59.535 ;
     RECT  2.16 59.805 19.44 60.075 ;
     RECT  2.16 60.345 19.44 60.615 ;
     RECT  2.16 60.885 19.44 61.155 ;
     RECT  2.16 61.425 19.44 61.695 ;
     RECT  2.16 61.965 19.44 62.235 ;
     RECT  2.16 62.505 19.44 62.64 ;
    LAYER RVTP ;
     RECT  2.16 2.295 19.44 2.565 ;
     RECT  2.16 2.835 19.44 3.105 ;
     RECT  2.16 3.375 19.44 3.645 ;
     RECT  2.16 3.915 19.44 4.185 ;
     RECT  2.16 4.455 19.44 4.725 ;
     RECT  2.16 4.995 19.44 5.265 ;
     RECT  2.16 5.535 19.44 5.805 ;
     RECT  2.16 6.075 19.44 6.345 ;
     RECT  2.16 6.615 19.44 6.885 ;
     RECT  2.16 7.155 19.44 7.425 ;
     RECT  2.16 7.695 19.44 7.965 ;
     RECT  2.16 8.235 19.44 8.505 ;
     RECT  2.16 8.775 19.44 9.045 ;
     RECT  2.16 9.315 19.44 9.585 ;
     RECT  2.16 9.855 19.44 10.125 ;
     RECT  2.16 10.395 19.44 10.665 ;
     RECT  2.16 10.935 19.44 11.205 ;
     RECT  2.16 11.475 19.44 11.745 ;
     RECT  2.16 12.015 19.44 12.285 ;
     RECT  2.16 12.555 19.44 12.825 ;
     RECT  2.16 13.095 19.44 13.365 ;
     RECT  2.16 13.635 19.44 13.905 ;
     RECT  2.16 14.175 19.44 14.445 ;
     RECT  2.16 14.715 19.44 14.985 ;
     RECT  2.16 15.255 19.44 15.525 ;
     RECT  2.16 15.795 19.44 16.065 ;
     RECT  2.16 16.335 19.44 16.605 ;
     RECT  2.16 16.875 19.44 17.145 ;
     RECT  2.16 17.415 19.44 17.685 ;
     RECT  2.16 17.955 19.44 18.225 ;
     RECT  2.16 18.495 19.44 18.765 ;
     RECT  2.16 19.035 19.44 19.305 ;
     RECT  2.16 19.575 19.44 19.845 ;
     RECT  2.16 20.115 19.44 20.385 ;
     RECT  2.16 20.655 19.44 20.925 ;
     RECT  2.16 21.195 19.44 21.465 ;
     RECT  2.16 21.735 19.44 22.005 ;
     RECT  2.16 22.275 19.44 22.545 ;
     RECT  2.16 22.815 19.44 23.085 ;
     RECT  2.16 23.355 19.44 23.625 ;
     RECT  2.16 23.895 19.44 24.165 ;
     RECT  2.16 24.435 19.44 24.705 ;
     RECT  2.16 24.975 19.44 25.245 ;
     RECT  2.16 25.515 19.44 25.785 ;
     RECT  2.16 26.055 19.44 26.325 ;
     RECT  2.16 26.595 19.44 26.865 ;
     RECT  2.16 27.135 19.44 27.405 ;
     RECT  2.16 27.675 19.44 27.945 ;
     RECT  2.16 28.215 19.44 28.485 ;
     RECT  2.16 28.755 19.44 29.025 ;
     RECT  2.16 29.295 19.44 29.565 ;
     RECT  2.16 29.835 19.44 30.105 ;
     RECT  2.16 30.375 19.44 30.645 ;
     RECT  2.16 30.915 19.44 31.185 ;
     RECT  2.16 31.455 19.44 31.725 ;
     RECT  2.16 31.995 19.44 32.265 ;
     RECT  2.16 32.535 19.44 32.805 ;
     RECT  2.16 33.075 19.44 33.345 ;
     RECT  2.16 33.615 19.44 33.885 ;
     RECT  2.16 34.155 19.44 34.425 ;
     RECT  2.16 34.695 19.44 34.965 ;
     RECT  2.16 35.235 19.44 35.505 ;
     RECT  2.16 35.775 19.44 36.045 ;
     RECT  2.16 36.315 19.44 36.585 ;
     RECT  2.16 36.855 19.44 37.125 ;
     RECT  2.16 37.395 19.44 37.665 ;
     RECT  2.16 37.935 19.44 38.205 ;
     RECT  2.16 38.475 19.44 38.745 ;
     RECT  2.16 39.015 19.44 39.285 ;
     RECT  2.16 39.555 19.44 39.825 ;
     RECT  2.16 40.095 19.44 40.365 ;
     RECT  2.16 40.635 19.44 40.905 ;
     RECT  2.16 41.175 19.44 41.445 ;
     RECT  2.16 41.715 19.44 41.985 ;
     RECT  2.16 42.255 19.44 42.525 ;
     RECT  2.16 42.795 19.44 43.065 ;
     RECT  2.16 43.335 19.44 43.605 ;
     RECT  2.16 43.875 19.44 44.145 ;
     RECT  2.16 44.415 19.44 44.685 ;
     RECT  2.16 44.955 19.44 45.225 ;
     RECT  2.16 45.495 19.44 45.765 ;
     RECT  2.16 46.035 19.44 46.305 ;
     RECT  2.16 46.575 19.44 46.845 ;
     RECT  2.16 47.115 19.44 47.385 ;
     RECT  2.16 47.655 19.44 47.925 ;
     RECT  2.16 48.195 19.44 48.465 ;
     RECT  2.16 48.735 19.44 49.005 ;
     RECT  2.16 49.275 19.44 49.545 ;
     RECT  2.16 49.815 19.44 50.085 ;
     RECT  2.16 50.355 19.44 50.625 ;
     RECT  2.16 50.895 19.44 51.165 ;
     RECT  2.16 51.435 19.44 51.705 ;
     RECT  2.16 51.975 19.44 52.245 ;
     RECT  2.16 52.515 19.44 52.785 ;
     RECT  2.16 53.055 19.44 53.325 ;
     RECT  2.16 53.595 19.44 53.865 ;
     RECT  2.16 54.135 19.44 54.405 ;
     RECT  2.16 54.675 19.44 54.945 ;
     RECT  2.16 55.215 19.44 55.485 ;
     RECT  2.16 55.755 19.44 56.025 ;
     RECT  2.16 56.295 19.44 56.565 ;
     RECT  2.16 56.835 19.44 57.105 ;
     RECT  2.16 57.375 19.44 57.645 ;
     RECT  2.16 57.915 19.44 58.185 ;
     RECT  2.16 58.455 19.44 58.725 ;
     RECT  2.16 58.995 19.44 59.265 ;
     RECT  2.16 59.535 19.44 59.805 ;
     RECT  2.16 60.075 19.44 60.345 ;
     RECT  2.16 60.615 19.44 60.885 ;
     RECT  2.16 61.155 19.44 61.425 ;
     RECT  2.16 61.695 19.44 61.965 ;
     RECT  2.16 62.235 19.44 62.505 ;
    LAYER M1 ;
     RECT  2.16 2.151 19.44 62.649 ;
    LAYER M2 ;
     RECT  0.103 19.044 0.139 19.566 ;
     RECT  0.103 21.861 0.139 21.879 ;
     RECT  0.103 48.24 0.139 48.258 ;
     RECT  0.103 34.902 0.175 34.92 ;
     RECT  0.103 51.786 0.175 51.804 ;
     RECT  0.103 2.196 0.203 2.214 ;
     RECT  0.103 13.914 0.203 13.932 ;
     RECT  0.103 23.094 0.203 23.112 ;
     RECT  0.103 24.714 0.203 25.542 ;
     RECT  0.103 30.231 0.203 30.564 ;
     RECT  0.103 39.141 0.203 39.744 ;
     RECT  0.103 41.724 0.203 41.742 ;
     RECT  0.103 56.844 0.203 58.14 ;
     RECT  0.103 62.406 0.203 62.424 ;
     RECT  0.103 50.436 0.211 50.454 ;
     RECT  0.175 51.21 0.211 51.804 ;
     RECT  0.139 19.044 0.239 19.764 ;
     RECT  0.139 21.816 0.239 21.879 ;
     RECT  0.203 24.714 0.239 24.732 ;
     RECT  0.103 29.268 0.239 29.286 ;
     RECT  0.203 30.546 0.239 30.564 ;
     RECT  0.175 34.902 0.239 35.604 ;
     RECT  0.103 54.414 0.239 54.738 ;
     RECT  0.103 55.728 0.239 55.746 ;
     RECT  0.103 59.742 0.239 59.76 ;
     RECT  0.103 13.068 0.247 13.086 ;
     RECT  0.103 5.04 0.275 5.058 ;
     RECT  0.103 36.828 0.275 36.846 ;
     RECT  0.139 48.24 0.283 48.339 ;
     RECT  0.103 9.216 0.319 9.234 ;
     RECT  0.103 5.814 0.347 5.832 ;
     RECT  0.247 13.068 0.347 13.194 ;
     RECT  0.139 15.3 0.347 15.318 ;
     RECT  0.239 19.044 0.347 19.062 ;
     RECT  0.239 21.861 0.347 21.879 ;
     RECT  0.283 48.24 0.347 48.42 ;
     RECT  0.211 50.436 0.347 51.804 ;
     RECT  0.247 54.756 0.347 54.774 ;
     RECT  0.319 9.216 0.419 9.954 ;
     RECT  0.347 48.321 0.419 48.42 ;
     RECT  0.355 2.916 0.455 2.934 ;
     RECT  0.419 48.402 0.491 48.42 ;
     RECT  0.347 50.562 0.491 50.58 ;
     RECT  0.103 60.93 0.535 60.948 ;
     RECT  0.347 13.068 0.571 13.086 ;
     RECT  0.203 25.524 0.599 25.542 ;
     RECT  0.535 60.624 0.599 60.948 ;
     RECT  0.571 12.726 1.111 13.086 ;
     RECT  0.239 35.586 1.111 35.604 ;
     RECT  1.111 35.046 1.147 35.604 ;
     RECT  0.347 51.786 1.147 51.804 ;
     RECT  1.147 51.606 1.175 51.804 ;
     RECT  1.111 12.726 1.183 13.356 ;
     RECT  1.175 51.606 1.219 51.624 ;
     RECT  1.183 12.258 1.255 13.356 ;
     RECT  1.183 48.978 1.283 48.996 ;
     RECT  1.255 12.258 1.327 13.59 ;
     RECT  1.219 50.94 1.391 51.624 ;
     RECT  0.103 32.706 1.723 32.724 ;
     RECT  1.147 34.866 1.723 35.604 ;
     RECT  0.103 45.666 1.723 45.684 ;
     RECT  1.723 5.886 1.759 5.904 ;
     RECT  1.723 10.566 1.759 10.584 ;
     RECT  1.327 12.258 1.759 13.896 ;
     RECT  1.147 25.686 1.759 25.704 ;
     RECT  1.723 32.706 1.759 33.336 ;
     RECT  0.599 60.624 1.759 60.642 ;
     RECT  1.759 10.296 1.795 10.584 ;
     RECT  1.759 11.52 1.795 14.004 ;
     RECT  1.759 60.624 1.795 61.074 ;
     RECT  0.571 62.136 1.795 62.154 ;
     RECT  0.203 58.122 1.975 58.14 ;
     RECT  1.723 43.686 2.011 43.704 ;
     RECT  1.975 57.888 2.011 58.14 ;
     RECT  1.723 54.846 2.047 55.314 ;
     RECT  1.795 60.624 2.047 62.154 ;
     RECT  1.759 17.496 2.119 17.514 ;
     RECT  1.147 19.476 2.155 19.494 ;
     RECT  1.723 24.102 2.155 24.12 ;
     RECT  1.759 5.886 2.16 6.444 ;
     RECT  0.419 9.216 2.16 9.234 ;
     RECT  1.795 10.296 2.16 14.004 ;
     RECT  2.119 16.956 2.16 17.514 ;
     RECT  2.155 18.81 2.16 19.494 ;
     RECT  2.155 23.364 2.16 24.12 ;
     RECT  1.759 25.416 2.16 25.704 ;
     RECT  0.103 26.676 2.16 26.694 ;
     RECT  0.535 29.538 2.16 29.556 ;
     RECT  1.759 32.706 2.16 33.984 ;
     RECT  1.723 34.866 2.16 35.694 ;
     RECT  1.723 41.418 2.16 41.436 ;
     RECT  0.571 42.264 2.16 42.282 ;
     RECT  2.011 43.686 2.16 44.208 ;
     RECT  1.723 45.666 2.16 45.864 ;
     RECT  1.391 51.606 2.16 51.624 ;
     RECT  2.047 54.846 2.16 56.052 ;
     RECT  2.011 57.456 2.16 58.14 ;
     RECT  2.047 60.624 2.16 62.532 ;
     RECT  2.16 2.151 2.299 62.649 ;
     RECT  2.299 2.106 2.335 62.73 ;
     RECT  2.335 2.106 2.731 62.919 ;
     RECT  2.731 2.106 2.911 63.504 ;
     RECT  2.911 2.07 3.055 63.504 ;
     RECT  3.055 1.881 5.279 63.504 ;
     RECT  5.279 1.926 7.763 63.504 ;
     RECT  7.763 1.998 8.555 63.504 ;
     RECT  8.555 2.034 9.131 63.504 ;
     RECT  9.131 2.07 9.671 63.459 ;
     RECT  9.671 2.07 11.939 63.414 ;
     RECT  11.939 2.07 12.443 63.036 ;
     RECT  12.443 2.151 12.947 63.036 ;
     RECT  12.947 2.151 13.811 62.838 ;
     RECT  13.811 2.151 14.675 62.802 ;
     RECT  14.675 2.151 16.123 62.694 ;
     RECT  16.123 1.926 16.375 62.694 ;
     RECT  16.375 1.881 17.563 62.694 ;
     RECT  17.563 1.836 18.311 62.694 ;
     RECT  18.311 1.836 19.44 62.649 ;
     RECT  19.44 1.836 19.931 62.532 ;
     RECT  19.931 38.52 20.255 62.532 ;
     RECT  19.931 26.298 20.327 37.494 ;
     RECT  20.255 38.988 20.327 62.532 ;
     RECT  19.931 1.836 20.363 25.236 ;
     RECT  20.327 58.428 20.399 62.532 ;
     RECT  20.363 1.881 20.435 25.236 ;
     RECT  20.327 38.988 20.435 57.636 ;
     RECT  20.399 58.428 20.435 58.446 ;
     RECT  20.399 59.238 20.435 62.532 ;
     RECT  20.435 1.881 20.471 8.298 ;
     RECT  20.435 12.564 20.471 20.718 ;
     RECT  20.471 1.926 20.507 8.226 ;
     RECT  20.471 19.62 20.507 20.718 ;
     RECT  20.435 21.51 20.507 23.688 ;
     RECT  20.327 26.298 20.507 33.174 ;
     RECT  20.435 39.258 20.507 39.816 ;
     RECT  20.435 40.608 20.507 57.402 ;
     RECT  20.435 59.508 20.507 60.336 ;
     RECT  20.507 3.186 20.543 6.984 ;
     RECT  20.435 9.054 20.543 11.772 ;
     RECT  20.471 12.564 20.543 18.756 ;
     RECT  20.507 20.088 20.543 20.718 ;
     RECT  20.507 26.298 20.543 26.928 ;
     RECT  20.507 27.72 20.543 29.088 ;
     RECT  20.327 33.966 20.543 37.494 ;
     RECT  20.507 40.878 20.543 45.828 ;
     RECT  20.507 55.764 20.543 57.402 ;
     RECT  20.507 59.814 20.543 60.336 ;
     RECT  20.543 43.11 20.579 43.128 ;
     RECT  20.507 50.4 20.579 54.774 ;
     RECT  20.543 56.106 20.579 57.402 ;
     RECT  20.579 54.684 20.615 54.774 ;
     RECT  20.507 1.926 21.407 2.358 ;
     RECT  20.543 26.298 21.407 26.586 ;
     RECT  20.579 56.808 21.407 57.402 ;
     RECT  21.407 2.034 21.443 2.322 ;
     RECT  20.543 9.054 21.443 11.466 ;
     RECT  20.435 24.714 21.443 25.236 ;
     RECT  21.407 26.298 21.443 26.316 ;
     RECT  20.507 39.528 21.443 39.816 ;
     RECT  20.543 40.878 21.443 41.976 ;
     RECT  20.543 44.118 21.443 45.828 ;
     RECT  21.407 56.808 21.443 56.898 ;
     RECT  20.543 60.156 21.443 60.336 ;
     RECT  20.435 61.128 21.443 62.532 ;
     RECT  21.443 2.034 21.479 2.088 ;
     RECT  20.543 3.186 21.479 4.374 ;
     RECT  20.507 7.776 21.479 8.064 ;
     RECT  21.443 9.9 21.479 10.998 ;
     RECT  20.543 12.564 21.479 16.938 ;
     RECT  20.507 29.844 21.479 33.174 ;
     RECT  20.543 34.236 21.479 37.494 ;
     RECT  21.443 41.184 21.479 41.634 ;
     RECT  21.443 44.46 21.479 45.828 ;
     RECT  20.579 50.4 21.479 53.694 ;
     RECT  21.479 2.07 21.515 2.088 ;
     RECT  21.479 3.186 21.515 3.204 ;
     RECT  21.479 3.96 21.515 3.978 ;
     RECT  20.543 5.31 21.515 6.984 ;
     RECT  21.479 7.776 21.515 7.794 ;
     RECT  21.443 9.054 21.515 9.072 ;
     RECT  21.479 9.9 21.515 9.918 ;
     RECT  21.479 10.674 21.515 10.692 ;
     RECT  21.479 12.636 21.515 15.822 ;
     RECT  21.479 16.578 21.515 16.596 ;
     RECT  20.543 17.694 21.515 18.756 ;
     RECT  20.543 20.394 21.515 20.718 ;
     RECT  20.507 21.51 21.515 21.528 ;
     RECT  20.507 22.896 21.515 23.652 ;
     RECT  21.443 24.714 21.515 24.732 ;
     RECT  20.543 29.07 21.515 29.088 ;
     RECT  21.479 29.844 21.515 30.294 ;
     RECT  21.479 31.041 21.515 31.716 ;
     RECT  21.479 32.616 21.515 33.174 ;
     RECT  21.479 34.236 21.515 35.028 ;
     RECT  21.479 35.82 21.515 35.838 ;
     RECT  21.479 36.666 21.515 37.422 ;
     RECT  21.479 41.616 21.515 41.634 ;
     RECT  21.479 44.46 21.515 44.946 ;
     RECT  21.479 45.81 21.515 45.828 ;
     RECT  20.507 46.62 21.515 48.798 ;
     RECT  21.479 50.436 21.515 50.454 ;
     RECT  21.479 51.444 21.515 53.694 ;
     RECT  20.615 54.756 21.515 54.774 ;
     RECT  21.443 56.88 21.515 56.898 ;
     RECT  21.443 60.156 21.515 60.174 ;
     RECT  21.443 61.2 21.515 62.532 ;
    LAYER M3 ;
     RECT  21.492 0.811 21.51 0.907 ;
     RECT  19.368 0.715 19.386 1.003 ;
     RECT  21.456 0.907 21.51 1.099 ;
     RECT  20.484 1.195 20.502 1.291 ;
     RECT  20.448 1.291 20.502 1.387 ;
     RECT  20.412 1.387 20.502 1.483 ;
     RECT  19.332 1.003 19.386 1.579 ;
     RECT  20.376 1.483 20.502 1.579 ;
     RECT  21.42 1.099 21.51 1.771 ;
     RECT  2.34 1.771 2.358 1.867 ;
     RECT  2.34 1.867 2.754 1.876 ;
     RECT  16.38 1.876 16.398 1.915 ;
     RECT  17.568 1.831 17.586 1.915 ;
     RECT  2.34 1.876 3.078 1.921 ;
     RECT  16.38 1.915 17.586 1.921 ;
     RECT  5.256 1.876 5.274 1.957 ;
     RECT  16.128 1.921 17.586 1.957 ;
     RECT  4.608 1.957 5.526 1.963 ;
     RECT  4.572 1.963 5.526 1.993 ;
     RECT  14.832 1.915 14.85 2.011 ;
     RECT  6.84 1.963 6.858 2.029 ;
     RECT  7.74 1.921 7.758 2.029 ;
     RECT  8.532 1.993 8.55 2.029 ;
     RECT  16.128 1.957 18.126 2.029 ;
     RECT  19.332 1.579 20.502 2.029 ;
     RECT  4.068 1.993 5.526 2.059 ;
     RECT  10.8 1.963 10.818 2.059 ;
     RECT  11.952 0.571 11.97 2.065 ;
     RECT  2.34 1.921 3.222 2.101 ;
     RECT  6.84 2.029 7.758 2.143 ;
     RECT  8.532 2.029 9.126 2.143 ;
     RECT  10.692 2.059 10.818 2.143 ;
     RECT  16.128 2.029 20.502 2.143 ;
     RECT  2.304 2.101 3.222 2.155 ;
     RECT  3.96 2.059 5.994 2.155 ;
     RECT  0.144 2.011 0.162 2.188 ;
     RECT  6.84 2.143 9.126 2.191 ;
     RECT  11.952 2.065 12.438 2.191 ;
     RECT  13.215 2.143 13.305 2.191 ;
     RECT  10.515 2.143 10.818 2.227 ;
     RECT  2.304 2.155 5.994 2.299 ;
     RECT  6.84 2.191 9.27 2.299 ;
     RECT  2.304 2.299 9.27 2.347 ;
     RECT  10.515 2.227 11.214 2.347 ;
     RECT  21.384 1.771 21.51 2.363 ;
     RECT  2.304 2.347 11.214 2.371 ;
     RECT  11.952 2.191 13.41 2.371 ;
     RECT  2.304 2.371 13.41 2.413 ;
     RECT  14.832 2.011 14.958 2.461 ;
     RECT  0.108 2.188 0.198 2.477 ;
     RECT  2.304 2.413 13.497 2.525 ;
     RECT  14.58 2.461 14.958 2.587 ;
     RECT  15.915 2.143 20.502 2.597 ;
     RECT  14.58 2.587 15.138 2.641 ;
     RECT  15.915 2.597 20.466 2.641 ;
     RECT  0.144 2.477 0.198 2.731 ;
     RECT  2.304 2.525 12.438 2.759 ;
     RECT  0.144 2.731 0.378 2.875 ;
     RECT  0.144 2.875 0.45 2.939 ;
     RECT  0.144 2.939 0.378 2.957 ;
     RECT  13.215 2.525 13.497 3.001 ;
     RECT  14.58 2.641 20.466 3.001 ;
     RECT  13.215 3.001 20.466 3.101 ;
     RECT  13.215 3.101 20.43 3.137 ;
     RECT  13.215 3.137 19.926 3.173 ;
     RECT  21.456 2.363 21.51 3.211 ;
     RECT  0.144 2.957 0.162 3.245 ;
     RECT  21.42 3.211 21.51 3.403 ;
     RECT  2.304 2.759 11.898 3.577 ;
     RECT  19.872 3.173 19.926 3.883 ;
     RECT  21.384 3.403 21.51 3.983 ;
     RECT  21.384 3.983 21.474 4.109 ;
     RECT  13.215 3.173 19.134 4.171 ;
     RECT  19.872 3.883 20.43 4.171 ;
     RECT  2.304 3.577 12.33 4.219 ;
     RECT  0.18 4.123 0.198 4.267 ;
     RECT  0.18 4.267 0.306 4.363 ;
     RECT  13.215 4.171 20.43 4.363 ;
     RECT  21.456 4.109 21.474 4.379 ;
     RECT  2.304 4.219 12.474 4.459 ;
     RECT  13.215 4.363 20.538 4.459 ;
     RECT  0.18 4.363 0.378 4.493 ;
     RECT  0.18 4.493 0.342 4.699 ;
     RECT  2.304 4.459 20.538 4.891 ;
     RECT  0.144 4.699 0.342 4.973 ;
     RECT  1.728 4.891 20.538 5.027 ;
     RECT  0.144 4.973 0.27 5.035 ;
     RECT  0.108 5.035 0.27 5.072 ;
     RECT  21.492 4.747 21.51 5.131 ;
     RECT  1.728 5.027 19.134 5.323 ;
     RECT  21.456 5.131 21.51 5.323 ;
     RECT  21.42 5.323 21.51 5.419 ;
     RECT  0.144 5.072 0.27 5.707 ;
     RECT  0.144 5.707 0.378 5.8 ;
     RECT  0.108 5.8 0.378 5.837 ;
     RECT  21.384 5.419 21.51 5.909 ;
     RECT  0.18 5.837 0.342 6.029 ;
     RECT  1.224 5.323 19.134 6.043 ;
     RECT  19.872 5.027 20.538 6.143 ;
     RECT  1.152 6.043 19.134 6.173 ;
     RECT  0.18 6.029 0.198 6.221 ;
     RECT  1.764 6.173 19.134 6.449 ;
     RECT  2.304 6.449 19.134 6.605 ;
     RECT  19.872 6.143 20.502 6.611 ;
     RECT  21.492 5.909 21.51 6.859 ;
     RECT  21.456 6.859 21.51 6.953 ;
     RECT  19.908 6.611 20.502 7.339 ;
     RECT  2.304 6.605 19.098 7.357 ;
     RECT  19.872 7.339 20.502 7.357 ;
     RECT  0.144 7.195 0.162 7.373 ;
     RECT  0.324 7.627 0.342 7.757 ;
     RECT  21.492 6.953 21.51 7.799 ;
     RECT  2.304 7.357 20.502 8.107 ;
     RECT  1.98 8.107 20.502 8.159 ;
     RECT  19.872 8.159 20.502 8.231 ;
     RECT  1.98 8.159 18.99 8.237 ;
     RECT  1.152 8.251 1.17 8.299 ;
     RECT  19.872 8.231 20.466 8.303 ;
     RECT  19.872 8.303 20.43 8.339 ;
     RECT  0.108 8.203 0.126 8.587 ;
     RECT  21.456 7.819 21.474 8.587 ;
     RECT  0.108 8.587 0.162 8.683 ;
     RECT  21.42 8.587 21.474 8.683 ;
     RECT  0.108 8.683 0.234 8.971 ;
     RECT  2.304 8.237 18.99 9.013 ;
     RECT  1.152 8.299 1.278 9.053 ;
     RECT  19.908 8.339 20.43 9.067 ;
     RECT  19.872 9.067 20.43 9.121 ;
     RECT  2.304 9.013 19.026 9.163 ;
     RECT  1.728 9.163 19.026 9.211 ;
     RECT  0.108 8.971 0.342 9.239 ;
     RECT  1.728 9.211 19.062 9.259 ;
     RECT  19.872 9.121 20.574 9.259 ;
     RECT  21.42 8.683 21.51 9.311 ;
     RECT  1.728 9.259 20.574 9.581 ;
     RECT  0.324 9.239 0.342 9.883 ;
     RECT  0.324 9.883 0.414 9.959 ;
     RECT  0.324 9.959 0.342 9.968 ;
     RECT  21.492 9.311 21.51 10.219 ;
     RECT  1.728 9.581 20.538 10.499 ;
     RECT  1.728 10.499 20.466 10.589 ;
     RECT  21.456 10.219 21.51 10.697 ;
     RECT  21.456 10.697 21.474 10.795 ;
     RECT  0.144 10.651 0.162 10.891 ;
     RECT  1.764 10.589 20.466 10.931 ;
     RECT  0.144 10.891 0.594 10.987 ;
     RECT  21.42 10.795 21.474 11.003 ;
     RECT  21.42 11.003 21.438 11.471 ;
     RECT  1.764 10.931 20.43 11.543 ;
     RECT  2.196 11.543 20.43 11.749 ;
     RECT  0.144 10.987 0.738 11.851 ;
     RECT  2.196 11.749 20.538 11.981 ;
     RECT  0.144 11.851 1.35 12.173 ;
     RECT  0.576 12.173 1.35 12.331 ;
     RECT  2.196 11.981 20.502 12.331 ;
     RECT  21.492 12.139 21.51 12.427 ;
     RECT  0.576 12.331 20.502 12.785 ;
     RECT  0.576 12.785 19.926 12.821 ;
     RECT  21.456 12.427 21.51 13.195 ;
     RECT  0.108 12.907 0.342 13.199 ;
     RECT  0.108 13.199 0.27 13.229 ;
     RECT  1.116 12.821 19.926 13.361 ;
     RECT  1.26 13.361 19.926 13.613 ;
     RECT  21.384 13.195 21.51 13.667 ;
     RECT  1.332 13.613 19.926 13.675 ;
     RECT  1.332 13.675 20.43 13.901 ;
     RECT  0.108 13.229 0.234 13.937 ;
     RECT  1.764 13.901 20.43 13.963 ;
     RECT  1.764 13.963 20.466 14.009 ;
     RECT  0.144 13.937 0.234 14.237 ;
     RECT  21.42 13.667 21.51 14.539 ;
     RECT  2.268 14.009 20.466 14.635 ;
     RECT  21.384 14.539 21.51 14.819 ;
     RECT  2.268 14.635 20.502 14.981 ;
     RECT  0.144 14.237 0.162 15.115 ;
     RECT  2.268 14.981 20.43 15.521 ;
     RECT  0.144 15.115 0.342 15.595 ;
     RECT  21.492 14.819 21.51 15.691 ;
     RECT  0.144 15.595 0.45 15.773 ;
     RECT  21.456 15.691 21.51 15.787 ;
     RECT  0.144 15.773 0.378 15.821 ;
     RECT  2.268 15.521 19.926 15.883 ;
     RECT  21.42 15.787 21.51 15.883 ;
     RECT  0.144 15.821 0.342 15.965 ;
     RECT  2.124 15.883 19.926 16.259 ;
     RECT  0.324 15.965 0.342 16.301 ;
     RECT  19.836 16.259 19.926 16.331 ;
     RECT  21.384 15.883 21.51 16.367 ;
     RECT  19.872 16.331 19.926 16.403 ;
     RECT  19.908 16.403 19.926 16.555 ;
     RECT  21.42 16.367 21.51 16.601 ;
     RECT  19.908 16.555 20.322 16.636 ;
     RECT  1.152 16.075 1.17 16.651 ;
     RECT  1.152 16.651 1.278 16.747 ;
     RECT  2.124 16.259 19.098 16.747 ;
     RECT  19.908 16.636 20.358 16.747 ;
     RECT  21.42 16.601 21.474 16.871 ;
     RECT  1.152 16.747 19.098 17.041 ;
     RECT  1.152 17.041 19.134 17.149 ;
     RECT  19.908 16.747 20.502 17.149 ;
     RECT  21.456 16.871 21.474 17.323 ;
     RECT  0.324 17.323 0.342 17.453 ;
     RECT  1.152 17.149 20.502 17.518 ;
     RECT  1.152 17.518 20.538 17.519 ;
     RECT  2.16 17.519 20.538 17.564 ;
     RECT  19.872 17.564 20.538 17.645 ;
     RECT  0.216 17.659 0.234 18.283 ;
     RECT  21.456 17.323 21.51 18.293 ;
     RECT  2.16 17.564 19.098 18.475 ;
     RECT  19.872 17.645 20.502 18.475 ;
     RECT  0.216 18.283 0.342 18.523 ;
     RECT  2.16 18.475 20.502 18.563 ;
     RECT  21.492 18.293 21.51 18.761 ;
     RECT  2.16 18.563 19.458 18.833 ;
     RECT  2.232 18.833 19.458 18.845 ;
     RECT  0.18 18.523 0.342 18.955 ;
     RECT  2.268 18.845 19.458 19.277 ;
     RECT  1.152 17.519 1.17 19.499 ;
     RECT  0.108 18.955 0.342 19.571 ;
     RECT  0.144 19.571 0.342 19.769 ;
     RECT  0.216 19.769 0.342 19.805 ;
     RECT  2.376 19.277 19.458 19.885 ;
     RECT  20.304 18.563 20.502 19.885 ;
     RECT  0.324 19.805 0.342 19.949 ;
     RECT  2.376 19.885 20.502 19.949 ;
     RECT  2.376 19.949 19.314 20.011 ;
     RECT  20.448 19.949 20.502 20.083 ;
     RECT  20.448 20.083 20.538 20.333 ;
     RECT  21.492 20.203 21.51 20.395 ;
     RECT  21.456 20.395 21.51 20.453 ;
     RECT  20.448 20.333 20.502 20.624 ;
     RECT  20.448 20.624 20.466 20.717 ;
     RECT  0.144 20.827 0.162 20.875 ;
     RECT  2.304 20.011 19.314 20.875 ;
     RECT  2.304 20.875 20.43 21.355 ;
     RECT  2.268 21.355 20.43 21.451 ;
     RECT  21.492 20.453 21.51 21.533 ;
     RECT  0.144 20.875 0.342 21.739 ;
     RECT  2.232 21.451 20.43 21.739 ;
     RECT  1.152 21.211 1.17 21.787 ;
     RECT  0.108 21.739 0.342 21.884 ;
     RECT  0.144 21.884 0.342 21.965 ;
     RECT  1.152 21.787 1.278 22.061 ;
     RECT  2.232 21.739 20.502 22.123 ;
     RECT  1.152 22.061 1.17 22.795 ;
     RECT  0.144 21.965 0.162 22.987 ;
     RECT  1.152 22.795 1.278 23.069 ;
     RECT  0.144 22.987 0.234 23.089 ;
     RECT  0.108 23.089 0.234 23.213 ;
     RECT  2.16 22.123 20.502 23.275 ;
     RECT  0.216 23.213 0.234 23.357 ;
     RECT  1.728 23.275 20.502 23.693 ;
     RECT  1.728 23.693 20.43 23.851 ;
     RECT  1.152 23.851 20.43 24.431 ;
     RECT  0.144 24.043 0.162 24.523 ;
     RECT  0.144 24.523 0.234 24.619 ;
     RECT  21.492 22.411 21.51 24.737 ;
     RECT  1.152 24.431 20.25 25.043 ;
     RECT  21.42 24.907 21.438 25.241 ;
     RECT  1.152 25.043 19.926 25.439 ;
     RECT  0.108 24.619 0.234 25.483 ;
     RECT  1.152 25.439 1.17 25.483 ;
     RECT  0.108 25.483 1.17 25.547 ;
     RECT  0.504 25.547 1.17 25.613 ;
     RECT  1.152 25.613 1.17 25.709 ;
     RECT  2.304 25.439 19.926 26.155 ;
     RECT  21.42 26.059 21.438 26.321 ;
     RECT  2.304 26.155 20.43 26.401 ;
     RECT  2.268 26.401 20.43 26.443 ;
     RECT  21.384 26.347 21.402 26.591 ;
     RECT  0.108 26.671 0.126 26.861 ;
     RECT  0.144 26.923 0.162 27.101 ;
     RECT  2.268 26.443 20.538 27.599 ;
     RECT  0.216 27.499 0.342 27.931 ;
     RECT  2.304 27.599 20.538 28.781 ;
     RECT  0.144 27.931 0.342 29.227 ;
     RECT  2.304 28.781 20.502 29.291 ;
     RECT  0.108 29.227 0.342 29.533 ;
     RECT  0.108 29.533 0.558 29.741 ;
     RECT  21.492 29.035 21.51 30.091 ;
     RECT  2.304 29.291 20.43 30.187 ;
     RECT  21.456 30.091 21.51 30.187 ;
     RECT  21.42 30.187 21.51 30.283 ;
     RECT  2.268 30.187 20.43 30.371 ;
     RECT  1.152 30.331 1.17 30.461 ;
     RECT  2.304 30.371 20.43 30.475 ;
     RECT  0.108 29.741 0.342 30.605 ;
     RECT  2.304 30.475 20.502 30.677 ;
     RECT  21.384 30.283 21.51 31.036 ;
     RECT  21.276 31.036 21.51 31.085 ;
     RECT  2.304 30.677 20.466 31.147 ;
     RECT  0.144 30.605 0.162 31.387 ;
     RECT  2.268 31.147 20.466 31.451 ;
     RECT  0.144 31.387 0.234 31.517 ;
     RECT  1.152 31.483 1.17 31.531 ;
     RECT  2.268 31.451 20.322 31.531 ;
     RECT  21.42 31.085 21.51 31.819 ;
     RECT  0.216 31.517 0.234 31.853 ;
     RECT  21.384 31.819 21.51 32.027 ;
     RECT  1.152 31.531 20.322 32.203 ;
     RECT  21.42 32.027 21.51 32.297 ;
     RECT  1.152 32.203 20.502 32.773 ;
     RECT  0.108 32.701 0.126 32.779 ;
     RECT  1.152 32.773 20.538 32.813 ;
     RECT  0.108 32.779 0.162 33.163 ;
     RECT  0.108 33.163 0.342 33.293 ;
     RECT  1.152 32.813 20.322 33.355 ;
     RECT  1.116 33.355 20.322 33.547 ;
     RECT  1.116 33.547 20.502 33.961 ;
     RECT  21.492 32.297 21.51 34.027 ;
     RECT  1.116 33.961 20.538 34.157 ;
     RECT  0.144 33.293 0.342 34.315 ;
     RECT  1.116 34.157 20.502 34.315 ;
     RECT  0.144 34.315 20.502 34.493 ;
     RECT  0.144 34.493 0.342 34.888 ;
     RECT  0.108 34.888 0.342 34.925 ;
     RECT  21.456 34.027 21.51 34.987 ;
     RECT  1.116 34.493 20.502 35.069 ;
     RECT  1.188 35.069 20.502 35.159 ;
     RECT  21.42 34.987 21.51 35.179 ;
     RECT  21.384 35.179 21.51 35.537 ;
     RECT  0.144 34.925 0.234 35.549 ;
     RECT  1.728 35.159 20.502 35.699 ;
     RECT  0.18 35.549 0.234 35.755 ;
     RECT  2.304 35.699 20.502 36.311 ;
     RECT  21.42 35.537 21.51 36.331 ;
     RECT  0.18 35.755 0.342 36.571 ;
     RECT  21.384 36.331 21.51 36.617 ;
     RECT  0.144 36.571 0.342 36.715 ;
     RECT  0.144 36.715 0.378 36.811 ;
     RECT  0.108 36.811 0.378 36.851 ;
     RECT  0.144 36.851 0.378 37.037 ;
     RECT  21.42 36.617 21.51 37.121 ;
     RECT  0.216 37.037 0.378 37.195 ;
     RECT  0.216 37.195 0.45 37.373 ;
     RECT  0.216 37.373 0.378 37.421 ;
     RECT  21.456 37.121 21.51 37.427 ;
     RECT  21.456 37.427 21.474 37.499 ;
     RECT  2.304 36.311 20.25 37.675 ;
     RECT  0.216 37.421 0.342 38.189 ;
     RECT  0.216 38.189 0.234 38.491 ;
     RECT  2.304 37.675 20.43 38.911 ;
     RECT  2.268 38.911 20.43 38.957 ;
     RECT  0.144 38.491 0.234 39.067 ;
     RECT  0.144 39.067 0.27 39.136 ;
     RECT  2.304 38.957 20.43 39.253 ;
     RECT  2.304 39.253 20.502 39.341 ;
     RECT  0.108 39.136 0.27 39.499 ;
     RECT  0.108 39.499 0.342 39.749 ;
     RECT  2.304 39.341 20.25 39.883 ;
     RECT  1.728 39.883 20.25 40.267 ;
     RECT  1.728 40.267 20.43 40.459 ;
     RECT  21.42 39.403 21.438 40.651 ;
     RECT  21.42 40.651 21.474 40.843 ;
     RECT  21.384 40.843 21.474 40.939 ;
     RECT  1.728 40.459 20.538 40.973 ;
     RECT  0.144 39.749 0.342 40.987 ;
     RECT  21.276 40.939 21.474 41.243 ;
     RECT  1.728 40.973 20.43 41.441 ;
     RECT  21.384 41.243 21.474 41.513 ;
     RECT  21.42 41.513 21.474 41.515 ;
     RECT  0.144 40.987 0.594 41.611 ;
     RECT  21.42 41.515 21.51 41.639 ;
     RECT  2.232 41.441 20.43 41.707 ;
     RECT  0.108 41.611 0.594 41.756 ;
     RECT  21.42 41.639 21.438 41.981 ;
     RECT  0.144 41.756 0.594 42.029 ;
     RECT  0.576 42.029 0.594 42.287 ;
     RECT  2.232 41.707 20.538 42.556 ;
     RECT  2.232 42.556 20.574 42.571 ;
     RECT  1.728 42.571 20.574 43.133 ;
     RECT  0.144 42.955 0.234 43.243 ;
     RECT  1.728 43.133 20.538 43.637 ;
     RECT  0.108 43.243 0.234 43.723 ;
     RECT  1.728 43.637 20.502 43.757 ;
     RECT  0.108 43.723 0.414 43.853 ;
     RECT  21.42 43.819 21.438 44.141 ;
     RECT  0.108 43.853 0.234 44.381 ;
     RECT  21.456 44.299 21.51 44.875 ;
     RECT  0.108 44.381 0.162 44.957 ;
     RECT  21.42 44.875 21.51 44.971 ;
     RECT  21.384 44.971 21.51 45.221 ;
     RECT  1.728 43.757 20.43 45.451 ;
     RECT  21.456 45.221 21.51 45.527 ;
     RECT  0.108 44.957 0.126 45.689 ;
     RECT  1.728 45.451 20.502 45.835 ;
     RECT  1.152 45.835 20.502 45.869 ;
     RECT  1.152 45.869 1.17 46.013 ;
     RECT  0.144 45.931 0.342 46.061 ;
     RECT  2.304 45.869 20.502 46.061 ;
     RECT  20.232 46.061 20.502 46.103 ;
     RECT  0.144 46.061 0.234 46.445 ;
     RECT  2.304 46.061 19.458 46.603 ;
     RECT  2.232 46.603 19.458 46.637 ;
     RECT  20.412 46.103 20.502 47.083 ;
     RECT  21.492 45.527 21.51 47.275 ;
     RECT  0.144 46.445 0.162 47.309 ;
     RECT  20.412 47.083 20.538 47.389 ;
     RECT  2.232 46.637 19.422 47.467 ;
     RECT  20.412 47.389 20.61 47.467 ;
     RECT  2.232 47.467 20.61 47.759 ;
     RECT  2.304 47.759 20.61 47.789 ;
     RECT  1.152 47.899 1.17 47.947 ;
     RECT  21.456 47.275 21.51 47.981 ;
     RECT  0.216 47.563 0.342 48.139 ;
     RECT  1.152 47.947 1.386 48.173 ;
     RECT  0.108 48.139 0.342 48.263 ;
     RECT  0.144 48.263 0.342 48.316 ;
     RECT  0.144 48.316 0.414 48.379 ;
     RECT  1.152 48.173 1.17 48.379 ;
     RECT  0.144 48.379 1.17 48.425 ;
     RECT  0.144 48.425 0.414 48.461 ;
     RECT  21.492 47.981 21.51 48.845 ;
     RECT  1.152 48.425 1.17 48.955 ;
     RECT  1.152 48.955 1.278 49.001 ;
     RECT  2.304 47.789 20.502 49.099 ;
     RECT  1.152 49.001 1.206 49.181 ;
     RECT  2.232 49.099 20.502 49.199 ;
     RECT  0.144 48.461 0.162 49.387 ;
     RECT  0.144 49.387 0.342 49.517 ;
     RECT  2.304 49.199 20.502 49.883 ;
     RECT  2.304 49.883 20.43 50.059 ;
     RECT  1.152 49.181 1.17 50.155 ;
     RECT  0.144 49.517 0.162 50.251 ;
     RECT  0.144 50.251 0.342 50.347 ;
     RECT  21.492 50.251 21.51 50.347 ;
     RECT  2.232 50.059 20.43 50.351 ;
     RECT  0.108 50.347 0.342 50.443 ;
     RECT  0.108 50.443 0.414 50.459 ;
     RECT  0.144 50.459 0.414 50.557 ;
     RECT  1.152 50.155 1.278 50.557 ;
     RECT  0.144 50.557 1.278 50.669 ;
     RECT  2.304 50.351 20.43 50.731 ;
     RECT  1.152 50.669 1.278 50.923 ;
     RECT  1.152 50.923 1.35 50.935 ;
     RECT  2.304 50.731 20.502 51.359 ;
     RECT  0.144 50.669 0.342 51.437 ;
     RECT  21.456 50.347 21.51 51.539 ;
     RECT  0.144 51.437 0.162 51.677 ;
     RECT  1.152 50.935 1.386 51.725 ;
     RECT  1.152 51.725 1.17 51.809 ;
     RECT  0.108 51.781 0.126 51.917 ;
     RECT  19.836 51.359 20.502 52.051 ;
     RECT  19.836 52.051 20.538 52.109 ;
     RECT  2.304 51.359 18.954 52.141 ;
     RECT  2.304 52.141 18.99 52.321 ;
     RECT  19.836 52.109 20.502 52.321 ;
     RECT  2.304 52.321 20.502 52.363 ;
     RECT  0.324 52.651 0.342 52.699 ;
     RECT  0.144 52.699 0.342 52.781 ;
     RECT  2.268 52.363 20.502 52.843 ;
     RECT  1.152 52.699 1.17 53.515 ;
     RECT  2.232 52.843 20.502 53.515 ;
     RECT  0.144 52.781 0.162 53.597 ;
     RECT  1.152 53.515 20.502 53.663 ;
     RECT  21.492 51.539 21.51 53.699 ;
     RECT  0.216 53.659 0.234 53.707 ;
     RECT  19.872 53.663 20.502 53.707 ;
     RECT  19.872 53.707 20.538 53.803 ;
     RECT  0.216 53.707 0.342 53.851 ;
     RECT  19.872 53.803 20.574 54.091 ;
     RECT  0.216 53.851 0.414 54.125 ;
     RECT  0.216 54.125 0.342 54.379 ;
     RECT  1.152 53.663 19.134 54.475 ;
     RECT  19.872 54.091 20.61 54.475 ;
     RECT  1.152 54.475 20.61 54.653 ;
     RECT  1.296 54.653 20.61 54.701 ;
     RECT  1.728 54.701 20.61 54.707 ;
     RECT  0.108 54.379 0.342 54.743 ;
     RECT  21.492 54.571 21.51 54.779 ;
     RECT  1.728 54.707 20.538 55.319 ;
     RECT  0.252 54.743 0.342 55.483 ;
     RECT  0.216 55.483 0.342 55.723 ;
     RECT  2.052 55.319 20.538 55.723 ;
     RECT  0.108 55.723 0.342 55.76 ;
     RECT  1.152 55.435 1.17 55.805 ;
     RECT  2.052 55.723 20.574 56.057 ;
     RECT  2.232 56.057 20.574 56.129 ;
     RECT  0.144 55.76 0.342 56.155 ;
     RECT  21.42 56.107 21.438 56.203 ;
     RECT  0.144 56.155 0.414 56.429 ;
     RECT  21.42 56.203 21.51 56.491 ;
     RECT  2.232 56.129 20.538 56.633 ;
     RECT  0.144 56.429 0.342 56.813 ;
     RECT  0.144 56.813 0.234 56.839 ;
     RECT  21.384 56.491 21.51 56.903 ;
     RECT  1.224 57.019 1.242 57.067 ;
     RECT  1.152 57.067 1.242 57.197 ;
     RECT  0.108 56.839 0.234 57.293 ;
     RECT  1.224 57.197 1.242 57.341 ;
     RECT  2.232 56.633 20.502 57.389 ;
     RECT  21.384 56.903 21.402 57.407 ;
     RECT  2.232 57.389 20.43 57.451 ;
     RECT  0.108 57.293 0.198 57.569 ;
     RECT  2.016 57.451 20.43 57.883 ;
     RECT  0.108 57.569 0.162 58.157 ;
     RECT  0.144 58.157 0.162 58.685 ;
     RECT  1.98 57.883 20.43 59.117 ;
     RECT  19.908 59.117 20.43 59.275 ;
     RECT  0.324 59.371 0.342 59.611 ;
     RECT  1.98 59.117 19.098 59.729 ;
     RECT  0.216 59.611 0.342 59.737 ;
     RECT  0.108 59.737 0.342 59.789 ;
     RECT  1.152 59.515 1.17 59.851 ;
     RECT  1.98 59.729 19.062 59.851 ;
     RECT  19.908 59.275 20.538 59.851 ;
     RECT  21.42 59.659 21.438 59.947 ;
     RECT  19.872 59.851 20.538 60.143 ;
     RECT  0.324 59.789 0.342 60.427 ;
     RECT  1.152 59.851 19.062 60.427 ;
     RECT  19.872 60.143 20.43 60.619 ;
     RECT  0.324 60.427 19.062 60.691 ;
     RECT  19.836 60.619 20.43 60.691 ;
     RECT  0.324 60.691 20.43 60.715 ;
     RECT  0.252 60.715 20.43 60.881 ;
     RECT  0.252 60.881 20.25 60.907 ;
     RECT  0.108 60.907 20.25 60.953 ;
     RECT  21.42 59.947 21.51 61.151 ;
     RECT  21.456 61.151 21.51 61.259 ;
     RECT  0.144 60.953 20.25 61.421 ;
     RECT  20.232 61.421 20.25 61.493 ;
     RECT  0.144 61.421 19.386 61.799 ;
     RECT  20.484 61.963 20.502 61.969 ;
     RECT  0.144 61.799 14.958 61.997 ;
     RECT  21.492 61.259 21.51 62.059 ;
     RECT  20.484 61.969 20.538 62.069 ;
     RECT  0.144 61.997 1.17 62.141 ;
     RECT  21.456 62.059 21.51 62.155 ;
     RECT  0.144 62.141 0.594 62.159 ;
     RECT  20.52 62.069 20.538 62.275 ;
     RECT  0.144 62.159 0.558 62.285 ;
     RECT  21.312 62.155 21.51 62.285 ;
     RECT  21.456 62.285 21.51 62.339 ;
     RECT  0.144 62.285 0.342 62.401 ;
     RECT  1.98 61.997 14.958 62.429 ;
     RECT  15.876 61.799 19.386 62.429 ;
     RECT  0.108 62.401 0.342 62.477 ;
     RECT  10.44 62.429 14.958 62.501 ;
     RECT  21.492 62.339 21.51 62.537 ;
     RECT  14.652 62.501 14.958 62.539 ;
     RECT  10.44 62.501 13.806 62.573 ;
     RECT  16.74 62.429 19.386 62.573 ;
     RECT  20.52 62.275 20.574 62.573 ;
     RECT  18.216 62.573 18.705 62.609 ;
     RECT  10.515 62.573 13.806 62.657 ;
     RECT  15.876 62.429 16.005 62.657 ;
     RECT  18.252 62.609 18.705 62.657 ;
     RECT  0.144 62.477 0.342 62.669 ;
     RECT  10.764 62.657 13.806 62.669 ;
     RECT  17.028 62.573 17.406 62.669 ;
     RECT  20.556 62.573 20.574 62.669 ;
     RECT  14.652 62.539 15.03 62.699 ;
     RECT  17.028 62.669 17.118 62.699 ;
     RECT  18.252 62.657 18.306 62.699 ;
     RECT  1.98 62.429 9.666 62.735 ;
     RECT  14.652 62.699 14.994 62.765 ;
     RECT  15.876 62.657 15.894 62.765 ;
     RECT  11.088 62.669 13.806 62.771 ;
     RECT  14.652 62.765 14.67 62.807 ;
     RECT  1.98 62.735 7.47 62.827 ;
     RECT  13.788 62.771 13.806 62.843 ;
     RECT  18.252 62.699 18.27 62.861 ;
     RECT  1.44 62.827 7.47 62.875 ;
     RECT  11.088 62.771 13.05 62.879 ;
     RECT  0.144 62.669 0.162 62.909 ;
     RECT  1.368 62.875 7.47 62.923 ;
     RECT  11.088 62.879 11.97 62.924 ;
     RECT  11.088 62.924 11.934 62.969 ;
     RECT  1.296 62.923 7.47 63.004 ;
     RECT  8.244 62.735 9.666 63.005 ;
     RECT  12.924 62.879 13.05 63.041 ;
     RECT  1.188 63.004 7.47 63.077 ;
     RECT  8.352 63.005 9.666 63.077 ;
     RECT  1.188 63.077 3.87 63.101 ;
     RECT  4.896 63.077 7.47 63.101 ;
     RECT  4.896 63.101 5.886 63.149 ;
     RECT  5.148 63.149 5.166 63.194 ;
     RECT  8.604 63.077 9.666 63.194 ;
     RECT  1.188 63.101 1.206 63.197 ;
     RECT  6.768 63.101 7.47 63.245 ;
     RECT  13.032 63.041 13.05 63.293 ;
     RECT  11.232 62.969 11.934 63.383 ;
     RECT  11.556 63.383 11.934 63.389 ;
     RECT  1.98 63.101 3.87 63.419 ;
     RECT  11.916 63.389 11.934 63.419 ;
     RECT  1.98 63.419 3.438 63.464 ;
     RECT  9.108 63.194 9.666 63.464 ;
     RECT  1.98 63.464 2.754 63.509 ;
     RECT  9.108 63.464 9.126 63.509 ;
     RECT  1.98 63.509 2.034 63.629 ;
     RECT  6.948 63.245 7.47 63.725 ;
     RECT  6.948 63.725 7.002 63.821 ;
     RECT  1.98 63.629 1.998 63.917 ;
     RECT  6.984 63.821 7.002 64.013 ;
    LAYER M4 ;
     RECT  0.084 1.776 2.369 1.8 ;
     RECT  0.06 1.8 2.369 1.872 ;
     RECT  0.084 1.872 2.369 1.896 ;
     RECT  0.06 1.896 2.369 1.968 ;
     RECT  0.084 1.968 2.369 1.992 ;
     RECT  0.06 1.992 2.369 2.064 ;
     RECT  0.084 2.064 2.369 2.088 ;
     RECT  0.06 2.088 2.369 2.16 ;
     RECT  0.084 2.16 2.369 2.184 ;
     RECT  0.06 2.184 2.369 2.256 ;
     RECT  0.084 2.256 2.369 2.28 ;
     RECT  0.06 2.28 2.369 2.352 ;
     RECT  0.084 2.352 2.369 2.376 ;
     RECT  0.06 2.376 2.369 2.448 ;
     RECT  0.084 2.448 2.369 2.472 ;
     RECT  0.06 2.472 2.369 2.544 ;
     RECT  0.084 2.544 2.369 2.568 ;
     RECT  0.06 2.568 2.369 2.64 ;
     RECT  0.084 2.64 2.369 2.664 ;
     RECT  0.06 2.664 2.369 2.736 ;
     RECT  0.084 2.736 2.369 2.76 ;
     RECT  0.06 2.76 2.369 2.832 ;
     RECT  0.084 2.832 2.369 2.856 ;
     RECT  0.06 2.856 2.369 2.928 ;
     RECT  0.084 2.928 2.369 2.952 ;
     RECT  0.06 2.952 2.369 3.024 ;
     RECT  0.084 3.024 2.369 3.048 ;
     RECT  0.06 3.048 2.369 3.12 ;
     RECT  0.084 3.12 2.369 3.144 ;
     RECT  0.06 3.144 2.369 3.216 ;
     RECT  0.084 3.216 2.369 3.24 ;
     RECT  0.06 3.24 2.369 3.312 ;
     RECT  0.084 3.312 2.369 3.336 ;
     RECT  0.06 3.336 2.369 3.408 ;
     RECT  0.084 3.408 2.369 3.432 ;
     RECT  0.06 3.432 2.369 3.504 ;
     RECT  0.084 3.504 2.369 3.528 ;
     RECT  0.06 3.528 2.369 3.6 ;
     RECT  0.084 3.6 2.369 3.624 ;
     RECT  0.06 3.624 2.369 3.696 ;
     RECT  0.084 3.696 2.369 3.72 ;
     RECT  0.06 3.72 2.369 3.792 ;
     RECT  0.084 3.792 2.369 3.816 ;
     RECT  0.06 3.816 2.369 3.888 ;
     RECT  0.084 3.888 2.369 3.912 ;
     RECT  0.06 3.912 2.369 3.984 ;
     RECT  0.084 3.984 2.369 4.008 ;
     RECT  0.06 4.008 2.369 4.08 ;
     RECT  0.084 4.08 2.369 4.104 ;
     RECT  0.06 4.104 2.369 4.176 ;
     RECT  0.084 4.176 2.369 4.2 ;
     RECT  0.06 4.2 2.369 4.272 ;
     RECT  0.084 4.272 2.369 4.296 ;
     RECT  0.06 4.296 2.369 4.368 ;
     RECT  0.084 4.368 2.369 4.392 ;
     RECT  0.06 4.392 2.369 4.464 ;
     RECT  0.084 4.464 2.369 4.488 ;
     RECT  0.06 4.488 2.369 4.56 ;
     RECT  0.084 4.56 2.369 4.584 ;
     RECT  0.06 4.584 2.369 4.656 ;
     RECT  0.084 4.656 2.369 4.68 ;
     RECT  0.06 4.68 2.369 4.752 ;
     RECT  0.084 4.752 2.369 4.776 ;
     RECT  0.06 4.776 2.369 4.848 ;
     RECT  0.084 4.848 2.369 4.872 ;
     RECT  0.06 4.872 2.369 4.944 ;
     RECT  0.084 4.944 2.369 4.968 ;
     RECT  0.06 4.968 2.369 5.04 ;
     RECT  0.084 5.04 2.369 5.064 ;
     RECT  0.06 5.064 2.369 5.136 ;
     RECT  0.084 5.136 2.369 5.16 ;
     RECT  0.06 5.16 2.369 5.232 ;
     RECT  0.084 5.232 2.369 5.256 ;
     RECT  0.06 5.256 2.369 5.328 ;
     RECT  0.084 5.328 2.369 5.352 ;
     RECT  0.06 5.352 2.369 5.424 ;
     RECT  0.084 5.424 2.369 5.448 ;
     RECT  0.06 5.448 2.369 5.52 ;
     RECT  0.084 5.52 2.369 5.544 ;
     RECT  0.06 5.544 2.369 5.616 ;
     RECT  0.084 5.616 2.369 5.64 ;
     RECT  0.06 5.64 2.369 5.712 ;
     RECT  0.084 5.712 2.369 5.736 ;
     RECT  0.06 5.736 2.369 5.808 ;
     RECT  0.084 5.808 2.369 5.832 ;
     RECT  0.06 5.832 2.369 5.904 ;
     RECT  0.084 5.904 2.369 5.928 ;
     RECT  0.06 5.928 2.369 6 ;
     RECT  0.084 6 2.369 6.024 ;
     RECT  0.06 6.024 2.369 6.096 ;
     RECT  0.084 6.096 2.369 6.12 ;
     RECT  0.06 6.12 2.369 6.192 ;
     RECT  0.084 6.192 2.369 6.216 ;
     RECT  0.06 6.216 2.369 6.288 ;
     RECT  0.084 6.288 2.369 6.312 ;
     RECT  0.06 6.312 2.369 6.384 ;
     RECT  0.084 6.384 2.369 6.408 ;
     RECT  0.06 6.408 2.369 7.248 ;
     RECT  0.084 7.248 2.369 7.272 ;
     RECT  0.06 7.272 2.369 7.344 ;
     RECT  0.084 7.344 2.369 7.368 ;
     RECT  0.06 7.368 2.369 7.44 ;
     RECT  0.084 7.44 2.369 7.464 ;
     RECT  0.06 7.464 2.369 7.536 ;
     RECT  0.084 7.536 2.369 7.56 ;
     RECT  0.06 7.56 2.369 7.632 ;
     RECT  0.084 7.632 2.369 7.656 ;
     RECT  0.06 7.656 2.369 7.728 ;
     RECT  0.084 7.728 2.369 7.752 ;
     RECT  0.06 7.752 2.369 7.824 ;
     RECT  0.084 7.824 2.369 7.848 ;
     RECT  0.06 7.848 2.369 7.92 ;
     RECT  0.084 7.92 2.369 7.944 ;
     RECT  0.06 7.944 2.369 8.016 ;
     RECT  0.084 8.016 2.369 8.04 ;
     RECT  0.06 8.04 2.369 8.112 ;
     RECT  0.084 8.112 2.369 8.136 ;
     RECT  0.06 8.136 2.369 8.208 ;
     RECT  0.084 8.208 2.369 8.232 ;
     RECT  0.06 8.232 2.369 8.304 ;
     RECT  0.084 8.304 2.369 8.328 ;
     RECT  0.06 8.328 2.369 8.4 ;
     RECT  0.084 8.4 2.369 8.424 ;
     RECT  0.06 8.424 2.369 8.496 ;
     RECT  0.084 8.496 2.369 8.52 ;
     RECT  0.06 8.52 2.369 8.592 ;
     RECT  0.084 8.592 2.369 8.616 ;
     RECT  0.06 8.616 2.369 8.688 ;
     RECT  0.084 8.688 2.369 8.712 ;
     RECT  0.06 8.712 2.369 8.784 ;
     RECT  0.084 8.784 2.369 8.808 ;
     RECT  0.06 8.808 2.369 8.88 ;
     RECT  0.084 8.88 2.369 8.904 ;
     RECT  0.06 8.904 2.369 8.976 ;
     RECT  0.084 8.976 2.369 9 ;
     RECT  0.06 9 2.369 9.072 ;
     RECT  0.084 9.072 2.369 9.096 ;
     RECT  0.06 9.096 2.369 9.168 ;
     RECT  0.084 9.168 2.369 9.192 ;
     RECT  0.06 9.192 2.369 9.264 ;
     RECT  0.084 9.264 2.369 9.288 ;
     RECT  0.06 9.288 2.369 9.36 ;
     RECT  0.084 9.36 2.369 9.384 ;
     RECT  0.06 9.384 2.369 9.456 ;
     RECT  0.084 9.456 2.369 9.48 ;
     RECT  0.06 9.48 2.369 9.552 ;
     RECT  0.084 9.552 2.369 9.576 ;
     RECT  0.06 9.576 2.369 9.648 ;
     RECT  0.084 9.648 2.369 9.672 ;
     RECT  0.06 9.672 2.369 9.744 ;
     RECT  0.084 9.744 2.369 9.768 ;
     RECT  0.06 9.768 2.369 9.84 ;
     RECT  0.084 9.84 2.369 9.864 ;
     RECT  0.06 9.864 2.369 9.936 ;
     RECT  0.084 9.936 2.369 9.96 ;
     RECT  0.06 9.96 2.369 10.032 ;
     RECT  0.084 10.032 2.369 10.056 ;
     RECT  0.06 10.056 2.369 10.128 ;
     RECT  0.084 10.128 2.369 10.152 ;
     RECT  0.06 10.152 2.369 10.224 ;
     RECT  0.084 10.224 2.369 10.248 ;
     RECT  0.06 10.248 2.369 10.32 ;
     RECT  0.084 10.32 2.369 10.344 ;
     RECT  0.06 10.344 2.369 10.416 ;
     RECT  0.084 10.416 2.369 10.44 ;
     RECT  0.06 10.44 2.369 10.512 ;
     RECT  0.084 10.512 2.369 10.536 ;
     RECT  0.06 10.536 2.369 10.608 ;
     RECT  0.084 10.608 2.369 10.632 ;
     RECT  0.06 10.632 2.369 10.704 ;
     RECT  0.084 10.704 2.369 10.728 ;
     RECT  0.06 10.728 2.369 10.8 ;
     RECT  0.084 10.8 2.369 10.824 ;
     RECT  0.06 10.824 2.369 10.896 ;
     RECT  0.084 10.896 2.369 10.92 ;
     RECT  0.06 10.92 2.369 10.992 ;
     RECT  0.084 10.992 2.369 11.016 ;
     RECT  0.06 11.016 2.369 11.088 ;
     RECT  0.084 11.088 2.369 11.112 ;
     RECT  0.06 11.112 2.369 11.184 ;
     RECT  0.084 11.184 2.369 11.208 ;
     RECT  0.06 11.208 2.369 11.28 ;
     RECT  0.084 11.28 2.369 11.304 ;
     RECT  0.06 11.304 2.369 11.376 ;
     RECT  0.084 11.376 2.369 11.4 ;
     RECT  0.06 11.4 2.369 11.472 ;
     RECT  0.084 11.472 2.369 11.496 ;
     RECT  0.06 11.496 2.369 11.568 ;
     RECT  0.084 11.568 2.369 11.592 ;
     RECT  0.06 11.592 2.369 11.664 ;
     RECT  0.084 11.664 2.369 11.688 ;
     RECT  0.06 11.688 2.369 11.76 ;
     RECT  0.084 11.76 2.369 11.784 ;
     RECT  0.06 11.784 2.369 11.856 ;
     RECT  0.084 11.856 2.369 11.88 ;
     RECT  0.06 11.88 2.369 11.952 ;
     RECT  0.084 11.952 2.369 11.976 ;
     RECT  0.06 11.976 2.369 12.048 ;
     RECT  0.084 12.048 2.369 12.072 ;
     RECT  0.06 12.072 2.369 12.144 ;
     RECT  0.084 12.144 2.369 12.168 ;
     RECT  0.06 12.168 2.369 12.24 ;
     RECT  0.084 12.24 2.369 12.264 ;
     RECT  0.06 12.264 2.369 12.336 ;
     RECT  0.084 12.336 2.369 12.36 ;
     RECT  0.06 12.36 2.369 12.432 ;
     RECT  0.084 12.432 2.369 12.456 ;
     RECT  0.06 12.456 2.369 12.528 ;
     RECT  0.084 12.528 2.369 12.552 ;
     RECT  0.06 12.552 2.369 12.624 ;
     RECT  0.084 12.624 2.369 12.648 ;
     RECT  0.06 12.648 2.369 12.72 ;
     RECT  0.084 12.72 2.369 12.744 ;
     RECT  0.06 12.744 2.369 12.816 ;
     RECT  0.084 12.816 2.369 12.84 ;
     RECT  0.06 12.84 2.369 12.912 ;
     RECT  0.084 12.912 2.369 12.936 ;
     RECT  0.06 12.936 2.369 13.008 ;
     RECT  0.084 13.008 2.369 13.032 ;
     RECT  0.06 13.032 2.369 13.104 ;
     RECT  0.084 13.104 2.369 13.128 ;
     RECT  0.06 13.128 2.369 13.2 ;
     RECT  0.084 13.2 2.369 13.224 ;
     RECT  0.06 13.224 2.369 13.296 ;
     RECT  0.084 13.296 2.369 13.32 ;
     RECT  0.06 13.32 2.369 13.392 ;
     RECT  0.084 13.392 2.369 13.416 ;
     RECT  0.06 13.416 2.369 13.488 ;
     RECT  0.084 13.488 2.369 13.512 ;
     RECT  0.06 13.512 2.369 13.584 ;
     RECT  0.084 13.584 2.369 13.608 ;
     RECT  0.06 13.608 2.369 13.68 ;
     RECT  0.084 13.68 2.369 13.704 ;
     RECT  0.06 13.704 2.369 13.776 ;
     RECT  0.084 13.776 2.369 13.8 ;
     RECT  0.06 13.8 2.369 13.872 ;
     RECT  0.084 13.872 2.369 13.896 ;
     RECT  0.06 13.896 2.369 13.968 ;
     RECT  0.084 13.968 2.369 13.992 ;
     RECT  0.06 13.992 2.369 14.064 ;
     RECT  0.084 14.064 2.369 14.088 ;
     RECT  0.06 14.088 2.369 14.16 ;
     RECT  0.084 14.16 2.369 14.184 ;
     RECT  0.06 14.184 2.369 14.256 ;
     RECT  0.084 14.256 2.369 14.28 ;
     RECT  0.06 14.28 2.369 14.352 ;
     RECT  0.084 14.352 2.369 14.376 ;
     RECT  0.06 14.376 2.369 14.448 ;
     RECT  0.084 14.448 2.369 14.472 ;
     RECT  0.06 14.472 2.369 14.544 ;
     RECT  0.084 14.544 2.369 14.568 ;
     RECT  0.06 14.568 2.369 14.64 ;
     RECT  0.084 14.64 2.369 14.664 ;
     RECT  0.06 14.664 2.369 14.736 ;
     RECT  0.084 14.736 2.369 14.76 ;
     RECT  0.06 14.76 2.369 14.832 ;
     RECT  0.084 14.832 2.369 14.856 ;
     RECT  0.06 14.856 2.369 14.928 ;
     RECT  0.084 14.928 2.369 14.952 ;
     RECT  0.06 14.952 2.369 15.024 ;
     RECT  0.084 15.024 2.369 15.048 ;
     RECT  0.06 15.048 2.369 15.12 ;
     RECT  0.084 15.12 2.369 15.144 ;
     RECT  0.06 15.144 2.369 15.216 ;
     RECT  0.084 15.216 2.369 15.24 ;
     RECT  0.06 15.24 2.369 15.312 ;
     RECT  0.084 15.312 2.369 15.336 ;
     RECT  0.06 15.336 2.369 15.408 ;
     RECT  0.084 15.408 2.369 15.432 ;
     RECT  0.06 15.432 2.369 15.504 ;
     RECT  0.084 15.504 2.369 15.528 ;
     RECT  0.06 15.528 2.369 15.6 ;
     RECT  0.084 15.6 2.369 15.624 ;
     RECT  0.06 15.624 2.369 15.696 ;
     RECT  0.084 15.696 2.369 15.72 ;
     RECT  0.06 15.72 2.369 15.792 ;
     RECT  0.084 15.792 2.369 15.816 ;
     RECT  0.06 15.816 2.369 15.888 ;
     RECT  0.084 15.888 2.369 15.912 ;
     RECT  0.06 15.912 2.369 15.984 ;
     RECT  0.084 15.984 2.369 16.008 ;
     RECT  0.06 16.008 2.369 16.08 ;
     RECT  0.084 16.08 2.369 16.104 ;
     RECT  0.06 16.104 2.369 16.176 ;
     RECT  0.084 16.176 2.369 16.2 ;
     RECT  0.06 16.2 2.369 16.272 ;
     RECT  0.084 16.272 2.369 16.296 ;
     RECT  0.06 16.296 2.369 16.368 ;
     RECT  0.084 16.368 2.369 16.392 ;
     RECT  0.06 16.392 2.369 16.464 ;
     RECT  0.084 16.464 2.369 16.488 ;
     RECT  0.06 16.488 2.369 16.56 ;
     RECT  0.084 16.56 2.369 16.584 ;
     RECT  0.06 16.584 2.369 16.656 ;
     RECT  0.084 16.656 2.369 16.68 ;
     RECT  0.06 16.68 2.369 16.752 ;
     RECT  0.084 16.752 2.369 16.776 ;
     RECT  0.06 16.776 2.369 16.848 ;
     RECT  0.084 16.848 2.369 16.872 ;
     RECT  0.06 16.872 2.369 16.944 ;
     RECT  0.084 16.944 2.369 16.968 ;
     RECT  0.06 16.968 2.369 17.04 ;
     RECT  0.084 17.04 2.369 17.064 ;
     RECT  0.06 17.064 2.369 17.136 ;
     RECT  0.084 17.136 2.369 17.16 ;
     RECT  0.06 17.16 2.369 17.232 ;
     RECT  0.084 17.232 2.369 17.256 ;
     RECT  0.06 17.256 2.369 17.328 ;
     RECT  0.084 17.328 2.369 17.352 ;
     RECT  0.06 17.352 2.369 17.424 ;
     RECT  0.084 17.424 2.369 17.448 ;
     RECT  0.06 17.448 2.369 17.52 ;
     RECT  0.084 17.52 2.369 17.544 ;
     RECT  0.06 17.544 2.369 17.616 ;
     RECT  0.084 17.616 2.369 17.64 ;
     RECT  0.06 17.64 2.369 17.712 ;
     RECT  0.084 17.712 2.369 17.736 ;
     RECT  0.06 17.736 2.369 17.808 ;
     RECT  0.084 17.808 2.369 17.832 ;
     RECT  0.06 17.832 2.369 17.904 ;
     RECT  0.084 17.904 2.369 17.928 ;
     RECT  0.06 17.928 2.369 18 ;
     RECT  0.084 18 2.369 18.024 ;
     RECT  0.06 18.024 2.369 18.096 ;
     RECT  0.084 18.096 2.369 18.12 ;
     RECT  0.06 18.12 2.369 18.192 ;
     RECT  0.084 18.192 2.369 18.216 ;
     RECT  0.06 18.216 2.369 18.288 ;
     RECT  0.084 18.288 2.369 18.312 ;
     RECT  0.06 18.312 2.369 18.384 ;
     RECT  0.084 18.384 2.369 18.408 ;
     RECT  0.06 18.408 2.369 18.48 ;
     RECT  0.084 18.48 2.369 18.504 ;
     RECT  0.06 18.504 2.369 18.576 ;
     RECT  0.084 18.576 2.369 18.6 ;
     RECT  0.06 18.6 2.369 18.672 ;
     RECT  0.084 18.672 2.369 18.696 ;
     RECT  0.06 18.696 2.369 18.768 ;
     RECT  0.084 18.768 2.369 18.792 ;
     RECT  0.06 18.792 2.369 18.864 ;
     RECT  0.084 18.864 2.369 18.888 ;
     RECT  0.06 18.888 2.369 18.96 ;
     RECT  0.084 18.96 2.369 18.984 ;
     RECT  0.06 18.984 2.369 19.056 ;
     RECT  0.084 19.056 2.369 19.08 ;
     RECT  0.06 19.08 2.369 19.152 ;
     RECT  0.084 19.152 2.369 19.176 ;
     RECT  0.06 19.176 2.369 19.248 ;
     RECT  0.084 19.248 2.369 19.272 ;
     RECT  0.06 19.272 2.369 19.344 ;
     RECT  0.084 19.344 2.369 19.368 ;
     RECT  0.06 19.368 2.369 19.44 ;
     RECT  0.084 19.44 2.369 19.464 ;
     RECT  0.06 19.464 2.369 19.536 ;
     RECT  0.084 19.536 2.369 19.56 ;
     RECT  0.06 19.56 2.369 19.632 ;
     RECT  0.084 19.632 2.369 19.656 ;
     RECT  0.06 19.656 2.369 19.728 ;
     RECT  0.084 19.728 2.369 19.752 ;
     RECT  0.06 19.752 2.369 19.824 ;
     RECT  0.084 19.824 2.369 19.848 ;
     RECT  0.06 19.848 2.369 19.92 ;
     RECT  0.084 19.92 2.369 19.944 ;
     RECT  0.06 19.944 2.369 20.016 ;
     RECT  0.084 20.016 2.369 20.04 ;
     RECT  0.06 20.04 2.369 20.112 ;
     RECT  0.084 20.112 2.369 20.136 ;
     RECT  0.06 20.136 2.369 20.208 ;
     RECT  0.084 20.208 2.369 20.232 ;
     RECT  0.06 20.232 2.369 20.304 ;
     RECT  0.084 20.304 2.369 20.328 ;
     RECT  0.06 20.328 2.369 20.4 ;
     RECT  0.084 20.4 2.369 20.424 ;
     RECT  0.06 20.424 2.369 20.496 ;
     RECT  0.084 20.496 2.369 20.52 ;
     RECT  0.06 20.52 2.369 20.592 ;
     RECT  0.084 20.592 2.369 20.616 ;
     RECT  0.06 20.616 2.369 20.688 ;
     RECT  0.084 20.688 2.369 20.712 ;
     RECT  0.06 20.712 2.369 20.784 ;
     RECT  0.084 20.784 2.369 20.808 ;
     RECT  0.06 20.808 2.369 20.88 ;
     RECT  0.084 20.88 2.369 20.904 ;
     RECT  0.06 20.904 2.369 20.976 ;
     RECT  0.084 20.976 2.369 21 ;
     RECT  0.06 21 2.369 21.072 ;
     RECT  0.084 21.072 2.369 21.096 ;
     RECT  0.06 21.096 2.369 21.168 ;
     RECT  0.084 21.168 2.369 21.192 ;
     RECT  0.06 21.192 2.369 21.264 ;
     RECT  0.084 21.264 2.369 21.288 ;
     RECT  0.06 21.288 2.369 21.36 ;
     RECT  0.084 21.36 2.369 21.384 ;
     RECT  0.06 21.384 2.369 21.456 ;
     RECT  0.084 21.456 2.369 21.48 ;
     RECT  0.06 21.48 2.369 21.552 ;
     RECT  0.084 21.552 2.369 21.576 ;
     RECT  0.06 21.576 2.369 21.648 ;
     RECT  0.084 21.648 2.369 21.672 ;
     RECT  0.06 21.672 2.369 21.744 ;
     RECT  0.084 21.744 2.369 21.768 ;
     RECT  0.06 21.768 2.369 21.84 ;
     RECT  0.084 21.84 2.369 21.864 ;
     RECT  0.06 21.864 2.369 21.936 ;
     RECT  0.084 21.936 2.369 21.96 ;
     RECT  0.06 21.96 2.369 22.032 ;
     RECT  0.084 22.032 2.369 22.056 ;
     RECT  0.06 22.056 2.369 22.128 ;
     RECT  0.084 22.128 2.369 22.152 ;
     RECT  0.06 22.152 2.369 22.224 ;
     RECT  0.084 22.224 2.369 22.248 ;
     RECT  0.06 22.248 2.369 22.32 ;
     RECT  0.084 22.32 2.369 22.344 ;
     RECT  0.06 22.344 2.369 22.416 ;
     RECT  0.084 22.416 2.369 22.44 ;
     RECT  0.06 22.44 2.369 22.512 ;
     RECT  0.084 22.512 2.369 22.536 ;
     RECT  0.06 22.536 2.369 22.608 ;
     RECT  0.084 22.608 2.369 22.632 ;
     RECT  0.06 22.632 2.369 22.704 ;
     RECT  0.084 22.704 2.369 22.728 ;
     RECT  0.06 22.728 2.369 22.8 ;
     RECT  0.084 22.8 2.369 22.824 ;
     RECT  0.06 22.824 2.369 22.896 ;
     RECT  0.084 22.896 2.369 22.92 ;
     RECT  0.06 22.92 2.369 22.992 ;
     RECT  0.084 22.992 2.369 23.016 ;
     RECT  0.06 23.016 2.369 23.088 ;
     RECT  0.084 23.088 2.369 23.112 ;
     RECT  0.06 23.112 2.369 23.184 ;
     RECT  0.084 23.184 2.369 23.208 ;
     RECT  0.06 23.208 2.369 23.28 ;
     RECT  0.084 23.28 2.369 23.304 ;
     RECT  0.06 23.304 2.369 23.376 ;
     RECT  0.084 23.376 2.369 23.4 ;
     RECT  0.06 23.4 2.369 23.472 ;
     RECT  0.084 23.472 2.369 23.496 ;
     RECT  0.06 23.496 2.369 23.568 ;
     RECT  0.084 23.568 2.369 23.592 ;
     RECT  0.06 23.592 2.369 23.664 ;
     RECT  0.084 23.664 2.369 23.688 ;
     RECT  0.06 23.688 2.369 23.76 ;
     RECT  0.084 23.76 2.369 23.784 ;
     RECT  0.06 23.784 2.369 23.856 ;
     RECT  0.084 23.856 2.369 23.88 ;
     RECT  0.06 23.88 2.369 23.952 ;
     RECT  0.084 23.952 2.369 23.976 ;
     RECT  0.06 23.976 2.369 24.048 ;
     RECT  0.084 24.048 2.369 24.072 ;
     RECT  0.06 24.072 2.369 24.144 ;
     RECT  0.084 24.144 2.369 24.168 ;
     RECT  0.06 24.168 2.369 24.24 ;
     RECT  0.084 24.24 2.369 24.264 ;
     RECT  0.06 24.264 2.369 24.336 ;
     RECT  0.084 24.336 2.369 24.36 ;
     RECT  0.06 24.36 2.369 24.432 ;
     RECT  0.084 24.432 2.369 24.456 ;
     RECT  0.06 24.456 2.369 24.528 ;
     RECT  0.084 24.528 2.369 24.552 ;
     RECT  0.06 24.552 2.369 24.624 ;
     RECT  0.084 24.624 2.369 24.648 ;
     RECT  0.06 24.648 2.369 24.72 ;
     RECT  0.084 24.72 2.369 24.744 ;
     RECT  0.06 24.744 2.369 24.816 ;
     RECT  0.084 24.816 2.369 24.84 ;
     RECT  0.06 24.84 2.369 24.912 ;
     RECT  0.084 24.912 2.369 24.936 ;
     RECT  0.06 24.936 2.369 25.008 ;
     RECT  0.084 25.008 2.369 25.032 ;
     RECT  0.06 25.032 2.369 25.104 ;
     RECT  0.084 25.104 2.369 25.128 ;
     RECT  0.06 25.128 2.369 25.2 ;
     RECT  0.084 25.2 2.369 25.224 ;
     RECT  0.06 25.224 2.369 25.296 ;
     RECT  0.084 25.296 2.369 25.32 ;
     RECT  0.06 25.32 2.369 25.392 ;
     RECT  0.084 25.392 2.369 25.416 ;
     RECT  0.06 25.416 2.369 25.488 ;
     RECT  0.084 25.488 2.369 25.512 ;
     RECT  0.06 25.512 2.369 25.584 ;
     RECT  0.084 25.584 2.369 25.608 ;
     RECT  0.06 25.608 2.369 26.448 ;
     RECT  0.084 26.448 2.369 26.472 ;
     RECT  0.06 26.472 2.369 26.544 ;
     RECT  0.084 26.544 2.369 26.568 ;
     RECT  0.06 26.568 2.369 26.64 ;
     RECT  0.084 26.64 2.369 26.664 ;
     RECT  0.06 26.664 2.369 26.736 ;
     RECT  0.084 26.736 2.369 26.76 ;
     RECT  0.06 26.76 2.369 26.832 ;
     RECT  0.084 26.832 2.369 26.856 ;
     RECT  0.06 26.856 2.369 26.928 ;
     RECT  0.084 26.928 2.369 26.952 ;
     RECT  0.06 26.952 2.369 27.024 ;
     RECT  0.084 27.024 2.369 27.048 ;
     RECT  0.06 27.048 2.369 27.12 ;
     RECT  0.084 27.12 2.369 27.144 ;
     RECT  0.06 27.144 2.369 27.216 ;
     RECT  0.084 27.216 2.369 27.24 ;
     RECT  0.06 27.24 2.369 27.312 ;
     RECT  0.084 27.312 2.369 27.336 ;
     RECT  0.06 27.336 2.369 27.408 ;
     RECT  0.084 27.408 2.369 27.432 ;
     RECT  0.06 27.432 2.369 27.504 ;
     RECT  0.084 27.504 2.369 27.528 ;
     RECT  0.06 27.528 2.369 27.6 ;
     RECT  0.084 27.6 2.369 27.624 ;
     RECT  0.06 27.624 2.369 27.696 ;
     RECT  0.084 27.696 2.369 27.72 ;
     RECT  0.06 27.72 2.369 27.792 ;
     RECT  0.084 27.792 2.369 27.816 ;
     RECT  0.06 27.816 2.369 27.888 ;
     RECT  0.084 27.888 2.369 27.912 ;
     RECT  0.06 27.912 2.369 27.984 ;
     RECT  0.084 27.984 2.369 28.008 ;
     RECT  0.06 28.008 2.369 28.08 ;
     RECT  0.084 28.08 2.369 28.104 ;
     RECT  0.06 28.104 2.369 28.176 ;
     RECT  0.084 28.176 2.369 28.2 ;
     RECT  0.06 28.2 2.369 28.272 ;
     RECT  0.084 28.272 2.369 28.296 ;
     RECT  0.06 28.296 2.369 28.368 ;
     RECT  0.084 28.368 2.369 28.392 ;
     RECT  0.06 28.392 2.369 28.464 ;
     RECT  0.084 28.464 2.369 28.488 ;
     RECT  0.06 28.488 2.369 28.56 ;
     RECT  0.084 28.56 2.369 28.584 ;
     RECT  0.06 28.584 2.369 28.656 ;
     RECT  0.084 28.656 2.369 28.68 ;
     RECT  0.06 28.68 2.369 28.752 ;
     RECT  0.084 28.752 2.369 28.776 ;
     RECT  0.06 28.776 2.369 28.848 ;
     RECT  0.084 28.848 2.369 28.872 ;
     RECT  0.06 28.872 2.369 28.944 ;
     RECT  0.084 28.944 2.369 28.968 ;
     RECT  0.06 28.968 2.369 29.04 ;
     RECT  0.084 29.04 2.369 29.064 ;
     RECT  0.06 29.064 2.369 29.136 ;
     RECT  0.084 29.136 2.369 29.16 ;
     RECT  0.06 29.16 2.369 29.232 ;
     RECT  0.084 29.232 2.369 29.256 ;
     RECT  0.06 29.256 2.369 29.328 ;
     RECT  0.084 29.328 2.369 29.352 ;
     RECT  0.06 29.352 2.369 29.424 ;
     RECT  0.084 29.424 2.369 29.448 ;
     RECT  0.06 29.448 2.369 29.52 ;
     RECT  0.084 29.52 2.369 29.544 ;
     RECT  0.06 29.544 2.369 29.616 ;
     RECT  0.084 29.616 2.369 29.64 ;
     RECT  0.06 29.64 2.369 29.712 ;
     RECT  0.084 29.712 2.369 29.736 ;
     RECT  0.06 29.736 2.369 29.808 ;
     RECT  0.084 29.808 2.369 29.832 ;
     RECT  0.06 29.832 2.369 29.904 ;
     RECT  0.084 29.904 2.369 29.928 ;
     RECT  0.06 29.928 2.369 30 ;
     RECT  0.084 30 2.369 30.024 ;
     RECT  0.06 30.024 2.369 30.096 ;
     RECT  0.084 30.096 2.369 30.12 ;
     RECT  0.06 30.12 2.369 30.192 ;
     RECT  0.084 30.192 2.369 30.216 ;
     RECT  0.06 30.216 2.369 30.288 ;
     RECT  0.084 30.288 2.369 30.312 ;
     RECT  0.06 30.312 2.369 30.384 ;
     RECT  0.084 30.384 2.369 30.408 ;
     RECT  0.06 30.408 2.369 30.48 ;
     RECT  0.084 30.48 2.369 30.504 ;
     RECT  0.06 30.504 2.369 30.576 ;
     RECT  0.084 30.576 2.369 30.6 ;
     RECT  0.06 30.6 2.369 30.672 ;
     RECT  0.084 30.672 2.369 30.696 ;
     RECT  0.06 30.696 2.369 30.768 ;
     RECT  0.084 30.768 2.369 30.792 ;
     RECT  0.06 30.792 2.369 30.864 ;
     RECT  0.084 30.864 2.369 30.888 ;
     RECT  0.06 30.888 2.369 30.96 ;
     RECT  0.084 30.96 2.369 30.984 ;
     RECT  0.06 30.984 2.369 31.056 ;
     RECT  0.084 31.056 2.369 31.08 ;
     RECT  0.06 31.08 2.369 31.152 ;
     RECT  0.084 31.152 2.369 31.176 ;
     RECT  0.06 31.176 2.369 31.248 ;
     RECT  0.084 31.248 2.369 31.272 ;
     RECT  0.06 31.272 2.369 31.344 ;
     RECT  0.084 31.344 2.369 31.368 ;
     RECT  0.06 31.368 2.369 31.44 ;
     RECT  0.084 31.44 2.369 31.464 ;
     RECT  0.06 31.464 2.369 31.536 ;
     RECT  0.084 31.536 2.369 31.56 ;
     RECT  0.06 31.56 2.369 31.632 ;
     RECT  0.084 31.632 2.369 31.656 ;
     RECT  0.06 31.656 2.369 31.728 ;
     RECT  0.084 31.728 2.369 31.752 ;
     RECT  0.06 31.752 2.369 31.824 ;
     RECT  0.084 31.824 2.369 31.848 ;
     RECT  0.06 31.848 2.369 31.92 ;
     RECT  0.084 31.92 2.369 31.944 ;
     RECT  0.06 31.944 2.369 32.016 ;
     RECT  0.084 32.016 2.369 32.04 ;
     RECT  0.06 32.04 2.369 32.112 ;
     RECT  0.084 32.112 2.369 32.136 ;
     RECT  0.06 32.136 2.369 32.208 ;
     RECT  0.084 32.208 2.369 32.232 ;
     RECT  0.06 32.232 2.369 32.304 ;
     RECT  0.084 32.304 2.369 32.328 ;
     RECT  0.06 32.328 2.369 32.4 ;
     RECT  0.084 32.4 2.369 32.424 ;
     RECT  0.06 32.424 2.369 32.496 ;
     RECT  0.084 32.496 2.369 32.52 ;
     RECT  0.06 32.52 2.369 32.592 ;
     RECT  0.084 32.592 2.369 32.616 ;
     RECT  0.06 32.616 2.369 32.688 ;
     RECT  0.084 32.688 2.369 32.712 ;
     RECT  0.06 32.712 2.369 32.784 ;
     RECT  0.084 32.784 2.369 32.808 ;
     RECT  0.06 32.808 2.369 32.88 ;
     RECT  0.084 32.88 2.369 32.904 ;
     RECT  0.06 32.904 2.369 32.976 ;
     RECT  0.084 32.976 2.369 33 ;
     RECT  0.06 33 2.369 33.072 ;
     RECT  0.084 33.072 2.369 33.096 ;
     RECT  0.06 33.096 2.369 33.168 ;
     RECT  0.084 33.168 2.369 33.192 ;
     RECT  0.06 33.192 2.369 33.264 ;
     RECT  0.084 33.264 2.369 33.288 ;
     RECT  0.06 33.288 2.369 33.36 ;
     RECT  0.084 33.36 2.369 33.384 ;
     RECT  0.06 33.384 2.369 33.456 ;
     RECT  0.084 33.456 2.369 33.48 ;
     RECT  0.06 33.48 2.369 33.552 ;
     RECT  0.084 33.552 2.369 33.576 ;
     RECT  0.06 33.576 2.369 33.648 ;
     RECT  0.084 33.648 2.369 33.672 ;
     RECT  0.06 33.672 2.369 33.744 ;
     RECT  0.084 33.744 2.369 33.768 ;
     RECT  0.06 33.768 2.369 33.84 ;
     RECT  0.084 33.84 2.369 33.864 ;
     RECT  0.06 33.864 2.369 33.936 ;
     RECT  0.084 33.936 2.369 33.96 ;
     RECT  0.06 33.96 2.369 34.032 ;
     RECT  0.084 34.032 2.369 34.056 ;
     RECT  0.06 34.056 2.369 34.128 ;
     RECT  0.084 34.128 2.369 34.152 ;
     RECT  0.06 34.152 2.369 34.224 ;
     RECT  0.084 34.224 2.369 34.248 ;
     RECT  0.06 34.248 2.369 34.32 ;
     RECT  0.084 34.32 2.369 34.344 ;
     RECT  0.06 34.344 2.369 34.416 ;
     RECT  0.084 34.416 2.369 34.44 ;
     RECT  0.06 34.44 2.369 34.512 ;
     RECT  0.084 34.512 2.369 34.536 ;
     RECT  0.06 34.536 2.369 34.608 ;
     RECT  0.084 34.608 2.369 34.632 ;
     RECT  0.06 34.632 2.369 34.704 ;
     RECT  0.084 34.704 2.369 34.728 ;
     RECT  0.06 34.728 2.369 34.8 ;
     RECT  0.084 34.8 2.369 34.824 ;
     RECT  0.06 34.824 2.369 34.896 ;
     RECT  0.084 34.896 2.369 34.92 ;
     RECT  0.06 34.92 2.369 34.992 ;
     RECT  0.084 34.992 2.369 35.016 ;
     RECT  0.06 35.016 2.369 35.088 ;
     RECT  0.084 35.088 2.369 35.112 ;
     RECT  0.06 35.112 2.369 35.184 ;
     RECT  0.084 35.184 2.369 35.208 ;
     RECT  0.06 35.208 2.369 35.28 ;
     RECT  0.084 35.28 2.369 35.304 ;
     RECT  0.06 35.304 2.369 35.376 ;
     RECT  0.084 35.376 2.369 35.4 ;
     RECT  0.06 35.4 2.369 35.472 ;
     RECT  0.084 35.472 2.369 35.496 ;
     RECT  0.06 35.496 2.369 35.568 ;
     RECT  0.084 35.568 2.369 35.592 ;
     RECT  0.06 35.592 2.369 35.664 ;
     RECT  0.084 35.664 2.369 35.688 ;
     RECT  0.06 35.688 2.369 35.76 ;
     RECT  0.084 35.76 2.369 35.784 ;
     RECT  0.06 35.784 2.369 35.856 ;
     RECT  0.084 35.856 2.369 35.88 ;
     RECT  0.06 35.88 2.369 35.952 ;
     RECT  0.084 35.952 2.369 35.976 ;
     RECT  0.06 35.976 2.369 36.048 ;
     RECT  0.084 36.048 2.369 36.072 ;
     RECT  0.06 36.072 2.369 36.144 ;
     RECT  0.084 36.144 2.369 36.168 ;
     RECT  0.06 36.168 2.369 36.24 ;
     RECT  0.084 36.24 2.369 36.264 ;
     RECT  0.06 36.264 2.369 36.336 ;
     RECT  0.084 36.336 2.369 36.36 ;
     RECT  0.06 36.36 2.369 36.432 ;
     RECT  0.084 36.432 2.369 36.456 ;
     RECT  0.06 36.456 2.369 36.528 ;
     RECT  0.084 36.528 2.369 36.552 ;
     RECT  0.06 36.552 2.369 36.624 ;
     RECT  0.084 36.624 2.369 36.648 ;
     RECT  0.06 36.648 2.369 36.72 ;
     RECT  0.084 36.72 2.369 36.744 ;
     RECT  0.06 36.744 2.369 36.816 ;
     RECT  0.084 36.816 2.369 36.84 ;
     RECT  0.06 36.84 2.369 36.912 ;
     RECT  0.084 36.912 2.369 36.936 ;
     RECT  0.06 36.936 2.369 37.008 ;
     RECT  0.084 37.008 2.369 37.032 ;
     RECT  0.06 37.032 2.369 37.104 ;
     RECT  0.084 37.104 2.369 37.128 ;
     RECT  0.06 37.128 2.369 37.2 ;
     RECT  0.084 37.2 2.369 37.224 ;
     RECT  0.06 37.224 2.369 37.296 ;
     RECT  0.084 37.296 2.369 37.32 ;
     RECT  0.06 37.32 2.369 37.392 ;
     RECT  0.084 37.392 2.369 37.416 ;
     RECT  0.06 37.416 2.369 37.488 ;
     RECT  0.084 37.488 2.369 37.512 ;
     RECT  0.06 37.512 2.369 37.584 ;
     RECT  0.084 37.584 2.369 37.608 ;
     RECT  0.06 37.608 2.369 37.68 ;
     RECT  0.084 37.68 2.369 37.704 ;
     RECT  0.06 37.704 2.369 37.776 ;
     RECT  0.084 37.776 2.369 37.8 ;
     RECT  0.06 37.8 2.369 37.872 ;
     RECT  0.084 37.872 2.369 37.896 ;
     RECT  0.06 37.896 2.369 37.968 ;
     RECT  0.084 37.968 2.369 37.992 ;
     RECT  0.06 37.992 2.369 38.064 ;
     RECT  0.084 38.064 2.369 38.088 ;
     RECT  0.06 38.088 2.369 38.16 ;
     RECT  0.084 38.16 2.369 38.184 ;
     RECT  0.06 38.184 2.369 38.256 ;
     RECT  0.084 38.256 2.369 38.28 ;
     RECT  0.06 38.28 2.369 38.352 ;
     RECT  0.084 38.352 2.369 38.376 ;
     RECT  0.06 38.376 2.369 38.448 ;
     RECT  0.084 38.448 2.369 38.472 ;
     RECT  0.06 38.472 2.369 38.544 ;
     RECT  0.084 38.544 2.369 38.568 ;
     RECT  0.06 38.568 2.369 38.64 ;
     RECT  0.084 38.64 2.369 38.664 ;
     RECT  0.06 38.664 2.369 38.736 ;
     RECT  0.084 38.736 2.369 38.76 ;
     RECT  0.06 38.76 2.369 38.832 ;
     RECT  0.084 38.832 2.369 38.856 ;
     RECT  0.06 38.856 2.369 38.928 ;
     RECT  0.084 38.928 2.369 38.952 ;
     RECT  0.06 38.952 2.369 39.024 ;
     RECT  0.084 39.024 2.369 39.048 ;
     RECT  0.06 39.048 2.369 39.12 ;
     RECT  0.084 39.12 2.369 39.144 ;
     RECT  0.06 39.144 2.369 39.216 ;
     RECT  0.084 39.216 2.369 39.24 ;
     RECT  0.06 39.24 2.369 39.312 ;
     RECT  0.084 39.312 2.369 39.336 ;
     RECT  0.06 39.336 2.369 39.408 ;
     RECT  0.084 39.408 2.369 39.432 ;
     RECT  0.06 39.432 2.369 39.504 ;
     RECT  0.084 39.504 2.369 39.528 ;
     RECT  0.06 39.528 2.369 39.6 ;
     RECT  0.084 39.6 2.369 39.624 ;
     RECT  0.06 39.624 2.369 39.696 ;
     RECT  0.084 39.696 2.369 39.72 ;
     RECT  0.06 39.72 2.369 39.792 ;
     RECT  0.084 39.792 2.369 39.816 ;
     RECT  0.06 39.816 2.369 39.888 ;
     RECT  0.084 39.888 2.369 39.912 ;
     RECT  0.06 39.912 2.369 39.984 ;
     RECT  0.084 39.984 2.369 40.008 ;
     RECT  0.06 40.008 2.369 40.08 ;
     RECT  0.084 40.08 2.369 40.104 ;
     RECT  0.06 40.104 2.369 40.176 ;
     RECT  0.084 40.176 2.369 40.2 ;
     RECT  0.06 40.2 2.369 40.272 ;
     RECT  0.084 40.272 2.369 40.296 ;
     RECT  0.06 40.296 2.369 40.368 ;
     RECT  0.084 40.368 2.369 40.392 ;
     RECT  0.06 40.392 2.369 40.464 ;
     RECT  0.084 40.464 2.369 40.488 ;
     RECT  0.06 40.488 2.369 40.56 ;
     RECT  0.084 40.56 2.369 40.584 ;
     RECT  0.06 40.584 2.369 40.656 ;
     RECT  0.084 40.656 2.369 40.68 ;
     RECT  0.06 40.68 2.369 40.752 ;
     RECT  0.084 40.752 2.369 40.776 ;
     RECT  0.06 40.776 2.369 40.848 ;
     RECT  0.084 40.848 2.369 40.872 ;
     RECT  0.06 40.872 2.369 40.944 ;
     RECT  0.084 40.944 2.369 40.968 ;
     RECT  0.06 40.968 2.369 41.04 ;
     RECT  0.084 41.04 2.369 41.064 ;
     RECT  0.06 41.064 2.369 41.136 ;
     RECT  0.084 41.136 2.369 41.16 ;
     RECT  0.06 41.16 2.369 41.232 ;
     RECT  0.084 41.232 2.369 41.256 ;
     RECT  0.06 41.256 2.369 41.328 ;
     RECT  0.084 41.328 2.369 41.352 ;
     RECT  0.06 41.352 2.369 41.424 ;
     RECT  0.084 41.424 2.369 41.448 ;
     RECT  0.06 41.448 2.369 41.52 ;
     RECT  0.084 41.52 2.369 41.544 ;
     RECT  0.06 41.544 2.369 41.616 ;
     RECT  0.084 41.616 2.369 41.64 ;
     RECT  0.06 41.64 2.369 41.712 ;
     RECT  0.084 41.712 2.369 41.736 ;
     RECT  0.06 41.736 2.369 41.808 ;
     RECT  0.084 41.808 2.369 41.832 ;
     RECT  0.06 41.832 2.369 41.904 ;
     RECT  0.084 41.904 2.369 41.928 ;
     RECT  0.06 41.928 2.369 42 ;
     RECT  0.084 42 2.369 42.024 ;
     RECT  0.06 42.024 2.369 42.096 ;
     RECT  0.084 42.096 2.369 42.12 ;
     RECT  0.06 42.12 2.369 42.192 ;
     RECT  0.084 42.192 2.369 42.216 ;
     RECT  0.06 42.216 2.369 42.288 ;
     RECT  0.084 42.288 2.369 42.312 ;
     RECT  0.06 42.312 2.369 42.384 ;
     RECT  0.084 42.384 2.369 42.408 ;
     RECT  0.06 42.408 2.369 42.48 ;
     RECT  0.084 42.48 2.369 42.504 ;
     RECT  0.06 42.504 2.369 42.576 ;
     RECT  0.084 42.576 2.369 42.6 ;
     RECT  0.06 42.6 2.369 42.672 ;
     RECT  0.084 42.672 2.369 42.696 ;
     RECT  0.06 42.696 2.369 42.768 ;
     RECT  0.084 42.768 2.369 42.792 ;
     RECT  0.06 42.792 2.369 42.864 ;
     RECT  0.084 42.864 2.369 42.888 ;
     RECT  0.06 42.888 2.369 42.96 ;
     RECT  0.084 42.96 2.369 42.984 ;
     RECT  0.06 42.984 2.369 43.056 ;
     RECT  0.084 43.056 2.369 43.08 ;
     RECT  0.06 43.08 2.369 43.152 ;
     RECT  0.084 43.152 2.369 43.176 ;
     RECT  0.06 43.176 2.369 43.248 ;
     RECT  0.084 43.248 2.369 43.272 ;
     RECT  0.06 43.272 2.369 43.344 ;
     RECT  0.084 43.344 2.369 43.368 ;
     RECT  0.06 43.368 2.369 43.44 ;
     RECT  0.084 43.44 2.369 43.464 ;
     RECT  0.06 43.464 2.369 43.536 ;
     RECT  0.084 43.536 2.369 43.56 ;
     RECT  0.06 43.56 2.369 43.632 ;
     RECT  0.084 43.632 2.369 43.656 ;
     RECT  0.06 43.656 2.369 43.728 ;
     RECT  0.084 43.728 2.369 43.752 ;
     RECT  0.06 43.752 2.369 43.824 ;
     RECT  0.084 43.824 2.369 43.848 ;
     RECT  0.06 43.848 2.369 43.92 ;
     RECT  0.084 43.92 2.369 43.944 ;
     RECT  0.06 43.944 2.369 44.016 ;
     RECT  0.084 44.016 2.369 44.04 ;
     RECT  0.06 44.04 2.369 44.112 ;
     RECT  0.084 44.112 2.369 44.136 ;
     RECT  0.06 44.136 2.369 44.208 ;
     RECT  0.084 44.208 2.369 44.232 ;
     RECT  0.06 44.232 2.369 44.304 ;
     RECT  0.084 44.304 2.369 44.328 ;
     RECT  0.06 44.328 2.369 44.4 ;
     RECT  0.084 44.4 2.369 44.424 ;
     RECT  0.06 44.424 2.369 44.496 ;
     RECT  0.084 44.496 2.369 44.52 ;
     RECT  0.06 44.52 2.369 44.592 ;
     RECT  0.084 44.592 2.369 44.616 ;
     RECT  0.06 44.616 2.369 44.688 ;
     RECT  0.084 44.688 2.369 44.712 ;
     RECT  0.06 44.712 2.369 44.784 ;
     RECT  0.084 44.784 2.369 44.808 ;
     RECT  0.06 44.808 2.369 45.648 ;
     RECT  0.084 45.648 2.369 45.672 ;
     RECT  0.06 45.672 2.369 45.744 ;
     RECT  0.084 45.744 2.369 45.768 ;
     RECT  0.06 45.768 2.369 45.84 ;
     RECT  0.084 45.84 2.369 45.864 ;
     RECT  0.06 45.864 2.369 45.936 ;
     RECT  0.084 45.936 2.369 45.96 ;
     RECT  0.06 45.96 2.369 46.032 ;
     RECT  0.084 46.032 2.369 46.056 ;
     RECT  0.06 46.056 2.369 46.128 ;
     RECT  0.084 46.128 2.369 46.152 ;
     RECT  0.06 46.152 2.369 46.224 ;
     RECT  0.084 46.224 2.369 46.248 ;
     RECT  0.06 46.248 2.369 46.32 ;
     RECT  0.084 46.32 2.369 46.344 ;
     RECT  0.06 46.344 2.369 46.416 ;
     RECT  0.084 46.416 2.369 46.44 ;
     RECT  0.06 46.44 2.369 46.512 ;
     RECT  0.084 46.512 2.369 46.536 ;
     RECT  0.06 46.536 2.369 46.608 ;
     RECT  0.084 46.608 2.369 46.632 ;
     RECT  0.06 46.632 2.369 46.704 ;
     RECT  0.084 46.704 2.369 46.728 ;
     RECT  0.06 46.728 2.369 46.8 ;
     RECT  0.084 46.8 2.369 46.824 ;
     RECT  0.06 46.824 2.369 46.896 ;
     RECT  0.084 46.896 2.369 46.92 ;
     RECT  0.06 46.92 2.369 46.992 ;
     RECT  0.084 46.992 2.369 47.016 ;
     RECT  0.06 47.016 2.369 47.088 ;
     RECT  0.084 47.088 2.369 47.112 ;
     RECT  0.06 47.112 2.369 47.184 ;
     RECT  0.084 47.184 2.369 47.208 ;
     RECT  0.06 47.208 2.369 47.28 ;
     RECT  0.084 47.28 2.369 47.304 ;
     RECT  0.06 47.304 2.369 47.376 ;
     RECT  0.084 47.376 2.369 47.4 ;
     RECT  0.06 47.4 2.369 47.472 ;
     RECT  0.084 47.472 2.369 47.496 ;
     RECT  0.06 47.496 2.369 47.568 ;
     RECT  0.084 47.568 2.369 47.592 ;
     RECT  0.06 47.592 2.369 47.664 ;
     RECT  0.084 47.664 2.369 47.688 ;
     RECT  0.06 47.688 2.369 47.76 ;
     RECT  0.084 47.76 2.369 47.784 ;
     RECT  0.06 47.784 2.369 47.856 ;
     RECT  0.084 47.856 2.369 47.88 ;
     RECT  0.06 47.88 2.369 47.952 ;
     RECT  0.084 47.952 2.369 47.976 ;
     RECT  0.06 47.976 2.369 48.048 ;
     RECT  0.084 48.048 2.369 48.072 ;
     RECT  0.06 48.072 2.369 48.144 ;
     RECT  0.084 48.144 2.369 48.168 ;
     RECT  0.06 48.168 2.369 48.24 ;
     RECT  0.084 48.24 2.369 48.264 ;
     RECT  0.06 48.264 2.369 48.336 ;
     RECT  0.084 48.336 2.369 48.36 ;
     RECT  0.06 48.36 2.369 48.432 ;
     RECT  0.084 48.432 2.369 48.456 ;
     RECT  0.06 48.456 2.369 48.528 ;
     RECT  0.084 48.528 2.369 48.552 ;
     RECT  0.06 48.552 2.369 48.624 ;
     RECT  0.084 48.624 2.369 48.648 ;
     RECT  0.06 48.648 2.369 48.72 ;
     RECT  0.084 48.72 2.369 48.744 ;
     RECT  0.06 48.744 2.369 48.816 ;
     RECT  0.084 48.816 2.369 48.84 ;
     RECT  0.06 48.84 2.369 48.912 ;
     RECT  0.084 48.912 2.369 48.936 ;
     RECT  0.06 48.936 2.369 49.008 ;
     RECT  0.084 49.008 2.369 49.032 ;
     RECT  0.06 49.032 2.369 49.104 ;
     RECT  0.084 49.104 2.369 49.128 ;
     RECT  0.06 49.128 2.369 49.2 ;
     RECT  0.084 49.2 2.369 49.224 ;
     RECT  0.06 49.224 2.369 49.296 ;
     RECT  0.084 49.296 2.369 49.32 ;
     RECT  0.06 49.32 2.369 49.392 ;
     RECT  0.084 49.392 2.369 49.416 ;
     RECT  0.06 49.416 2.369 49.488 ;
     RECT  0.084 49.488 2.369 49.512 ;
     RECT  0.06 49.512 2.369 49.584 ;
     RECT  0.084 49.584 2.369 49.608 ;
     RECT  0.06 49.608 2.369 49.68 ;
     RECT  0.084 49.68 2.369 49.704 ;
     RECT  0.06 49.704 2.369 49.776 ;
     RECT  0.084 49.776 2.369 49.8 ;
     RECT  0.06 49.8 2.369 49.872 ;
     RECT  0.084 49.872 2.369 49.896 ;
     RECT  0.06 49.896 2.369 49.968 ;
     RECT  0.084 49.968 2.369 49.992 ;
     RECT  0.06 49.992 2.369 50.064 ;
     RECT  0.084 50.064 2.369 50.088 ;
     RECT  0.06 50.088 2.369 50.16 ;
     RECT  0.084 50.16 2.369 50.184 ;
     RECT  0.06 50.184 2.369 50.256 ;
     RECT  0.084 50.256 2.369 50.28 ;
     RECT  0.06 50.28 2.369 50.352 ;
     RECT  0.084 50.352 2.369 50.376 ;
     RECT  0.06 50.376 2.369 50.448 ;
     RECT  0.084 50.448 2.369 50.472 ;
     RECT  0.06 50.472 2.369 50.544 ;
     RECT  0.084 50.544 2.369 50.568 ;
     RECT  0.06 50.568 2.369 50.64 ;
     RECT  0.084 50.64 2.369 50.664 ;
     RECT  0.06 50.664 2.369 50.736 ;
     RECT  0.084 50.736 2.369 50.76 ;
     RECT  0.06 50.76 2.369 50.832 ;
     RECT  0.084 50.832 2.369 50.856 ;
     RECT  0.06 50.856 2.369 50.928 ;
     RECT  0.084 50.928 2.369 50.952 ;
     RECT  0.06 50.952 2.369 51.024 ;
     RECT  0.084 51.024 2.369 51.048 ;
     RECT  0.06 51.048 2.369 51.12 ;
     RECT  0.084 51.12 2.369 51.144 ;
     RECT  0.06 51.144 2.369 51.216 ;
     RECT  0.084 51.216 2.369 51.24 ;
     RECT  0.06 51.24 2.369 51.312 ;
     RECT  0.084 51.312 2.369 51.336 ;
     RECT  0.06 51.336 2.369 51.408 ;
     RECT  0.084 51.408 2.369 51.432 ;
     RECT  0.06 51.432 2.369 51.504 ;
     RECT  0.084 51.504 2.369 51.528 ;
     RECT  0.06 51.528 2.369 51.6 ;
     RECT  0.084 51.6 2.369 51.624 ;
     RECT  0.06 51.624 2.369 51.696 ;
     RECT  0.084 51.696 2.369 51.72 ;
     RECT  0.06 51.72 2.369 51.792 ;
     RECT  0.084 51.792 2.369 51.816 ;
     RECT  0.06 51.816 2.369 51.888 ;
     RECT  0.084 51.888 2.369 51.912 ;
     RECT  0.06 51.912 2.369 51.984 ;
     RECT  0.084 51.984 2.369 52.008 ;
     RECT  0.06 52.008 2.369 52.08 ;
     RECT  0.084 52.08 2.369 52.104 ;
     RECT  0.06 52.104 2.369 52.176 ;
     RECT  0.084 52.176 2.369 52.2 ;
     RECT  0.06 52.2 2.369 52.272 ;
     RECT  0.084 52.272 2.369 52.296 ;
     RECT  0.06 52.296 2.369 52.368 ;
     RECT  0.084 52.368 2.369 52.392 ;
     RECT  0.06 52.392 2.369 52.464 ;
     RECT  0.084 52.464 2.369 52.488 ;
     RECT  0.06 52.488 2.369 52.56 ;
     RECT  0.084 52.56 2.369 52.584 ;
     RECT  0.06 52.584 2.369 52.656 ;
     RECT  0.084 52.656 2.369 52.68 ;
     RECT  0.06 52.68 2.369 52.752 ;
     RECT  0.084 52.752 2.369 52.776 ;
     RECT  0.06 52.776 2.369 52.848 ;
     RECT  0.084 52.848 2.369 52.872 ;
     RECT  0.06 52.872 2.369 52.944 ;
     RECT  0.084 52.944 2.369 52.968 ;
     RECT  0.06 52.968 2.369 53.04 ;
     RECT  0.084 53.04 2.369 53.064 ;
     RECT  0.06 53.064 2.369 53.136 ;
     RECT  0.084 53.136 2.369 53.16 ;
     RECT  0.06 53.16 2.369 53.232 ;
     RECT  0.084 53.232 2.369 53.256 ;
     RECT  0.06 53.256 2.369 53.328 ;
     RECT  0.084 53.328 2.369 53.352 ;
     RECT  0.06 53.352 2.369 53.424 ;
     RECT  0.084 53.424 2.369 53.448 ;
     RECT  0.06 53.448 2.369 53.52 ;
     RECT  0.084 53.52 2.369 53.544 ;
     RECT  0.06 53.544 2.369 53.616 ;
     RECT  0.084 53.616 2.369 53.64 ;
     RECT  0.06 53.64 2.369 53.712 ;
     RECT  0.084 53.712 2.369 53.736 ;
     RECT  0.06 53.736 2.369 53.808 ;
     RECT  0.084 53.808 2.369 53.832 ;
     RECT  0.06 53.832 2.369 53.904 ;
     RECT  0.084 53.904 2.369 53.928 ;
     RECT  0.06 53.928 2.369 54 ;
     RECT  0.084 54 2.369 54.024 ;
     RECT  0.06 54.024 2.369 54.096 ;
     RECT  0.084 54.096 2.369 54.12 ;
     RECT  0.06 54.12 2.369 54.192 ;
     RECT  0.084 54.192 2.369 54.216 ;
     RECT  0.06 54.216 2.369 54.288 ;
     RECT  0.084 54.288 2.369 54.312 ;
     RECT  0.06 54.312 2.369 54.384 ;
     RECT  0.084 54.384 2.369 54.408 ;
     RECT  0.06 54.408 2.369 54.48 ;
     RECT  0.084 54.48 2.369 54.504 ;
     RECT  0.06 54.504 2.369 54.576 ;
     RECT  0.084 54.576 2.369 54.6 ;
     RECT  0.06 54.6 2.369 54.672 ;
     RECT  0.084 54.672 2.369 54.696 ;
     RECT  0.06 54.696 2.369 54.768 ;
     RECT  0.084 54.768 2.369 54.792 ;
     RECT  0.06 54.792 2.369 54.864 ;
     RECT  0.084 54.864 2.369 54.888 ;
     RECT  0.06 54.888 2.369 54.96 ;
     RECT  0.084 54.96 2.369 54.984 ;
     RECT  0.06 54.984 2.369 55.056 ;
     RECT  0.084 55.056 2.369 55.08 ;
     RECT  0.06 55.08 2.369 55.152 ;
     RECT  0.084 55.152 2.369 55.176 ;
     RECT  0.06 55.176 2.369 55.248 ;
     RECT  0.084 55.248 2.369 55.272 ;
     RECT  0.06 55.272 2.369 55.344 ;
     RECT  0.084 55.344 2.369 55.368 ;
     RECT  0.06 55.368 2.369 55.44 ;
     RECT  0.084 55.44 2.369 55.464 ;
     RECT  0.06 55.464 2.369 55.536 ;
     RECT  0.084 55.536 2.369 55.56 ;
     RECT  0.06 55.56 2.369 55.632 ;
     RECT  0.084 55.632 2.369 55.656 ;
     RECT  0.06 55.656 2.369 55.728 ;
     RECT  0.084 55.728 2.369 55.752 ;
     RECT  0.06 55.752 2.369 55.824 ;
     RECT  0.084 55.824 2.369 55.848 ;
     RECT  0.06 55.848 2.369 55.92 ;
     RECT  0.084 55.92 2.369 55.944 ;
     RECT  0.06 55.944 2.369 56.016 ;
     RECT  0.084 56.016 2.369 56.04 ;
     RECT  0.06 56.04 2.369 56.112 ;
     RECT  0.084 56.112 2.369 56.136 ;
     RECT  0.06 56.136 2.369 56.208 ;
     RECT  0.084 56.208 2.369 56.232 ;
     RECT  0.06 56.232 2.369 56.304 ;
     RECT  0.084 56.304 2.369 56.328 ;
     RECT  0.06 56.328 2.369 56.4 ;
     RECT  0.084 56.4 2.369 56.424 ;
     RECT  0.06 56.424 2.369 56.496 ;
     RECT  0.084 56.496 2.369 56.52 ;
     RECT  0.06 56.52 2.369 56.592 ;
     RECT  0.084 56.592 2.369 56.616 ;
     RECT  0.06 56.616 2.369 56.688 ;
     RECT  0.084 56.688 2.369 56.712 ;
     RECT  0.06 56.712 2.369 56.784 ;
     RECT  0.084 56.784 2.369 56.808 ;
     RECT  0.06 56.808 2.369 56.88 ;
     RECT  0.084 56.88 2.369 56.904 ;
     RECT  0.06 56.904 2.369 56.976 ;
     RECT  0.084 56.976 2.369 57 ;
     RECT  0.06 57 2.369 57.072 ;
     RECT  0.084 57.072 2.369 57.096 ;
     RECT  0.06 57.096 2.369 57.168 ;
     RECT  0.084 57.168 2.369 57.192 ;
     RECT  0.06 57.192 2.369 57.264 ;
     RECT  0.084 57.264 2.369 57.288 ;
     RECT  0.06 57.288 2.369 57.36 ;
     RECT  0.084 57.36 2.369 57.384 ;
     RECT  0.06 57.384 2.369 57.456 ;
     RECT  0.084 57.456 2.369 57.48 ;
     RECT  0.06 57.48 2.369 57.552 ;
     RECT  0.084 57.552 2.369 57.576 ;
     RECT  0.06 57.576 2.369 57.648 ;
     RECT  0.084 57.648 2.369 57.672 ;
     RECT  0.06 57.672 2.369 57.744 ;
     RECT  0.084 57.744 2.369 57.768 ;
     RECT  0.06 57.768 2.369 57.84 ;
     RECT  0.084 57.84 2.369 57.864 ;
     RECT  0.06 57.864 2.369 57.936 ;
     RECT  0.084 57.936 2.369 57.96 ;
     RECT  0.06 57.96 2.369 58.032 ;
     RECT  0.084 58.032 2.369 58.056 ;
     RECT  0.06 58.056 2.369 58.128 ;
     RECT  0.084 58.128 2.369 58.152 ;
     RECT  0.06 58.152 2.369 58.224 ;
     RECT  0.084 58.224 2.369 58.248 ;
     RECT  0.06 58.248 2.369 58.32 ;
     RECT  0.084 58.32 2.369 58.344 ;
     RECT  0.06 58.344 2.369 58.416 ;
     RECT  0.084 58.416 2.369 58.44 ;
     RECT  0.06 58.44 2.369 58.512 ;
     RECT  0.084 58.512 2.369 58.536 ;
     RECT  0.06 58.536 2.369 58.608 ;
     RECT  0.084 58.608 2.369 58.632 ;
     RECT  0.06 58.632 2.369 58.704 ;
     RECT  0.084 58.704 2.369 58.728 ;
     RECT  0.06 58.728 2.369 58.8 ;
     RECT  0.084 58.8 2.369 58.824 ;
     RECT  0.06 58.824 2.369 58.896 ;
     RECT  0.084 58.896 2.369 58.92 ;
     RECT  0.06 58.92 2.369 58.992 ;
     RECT  0.084 58.992 2.369 59.016 ;
     RECT  0.06 59.016 2.369 59.088 ;
     RECT  0.084 59.088 2.369 59.112 ;
     RECT  0.06 59.112 2.369 59.184 ;
     RECT  0.084 59.184 2.369 59.208 ;
     RECT  0.06 59.208 2.369 59.28 ;
     RECT  0.084 59.28 2.369 59.304 ;
     RECT  0.06 59.304 2.369 59.376 ;
     RECT  0.084 59.376 2.369 59.4 ;
     RECT  0.06 59.4 2.369 59.472 ;
     RECT  0.084 59.472 2.369 59.496 ;
     RECT  0.06 59.496 2.369 59.568 ;
     RECT  0.084 59.568 2.369 59.592 ;
     RECT  0.06 59.592 2.369 59.664 ;
     RECT  0.084 59.664 2.369 59.688 ;
     RECT  0.06 59.688 2.369 59.76 ;
     RECT  0.084 59.76 2.369 59.784 ;
     RECT  0.06 59.784 2.369 59.856 ;
     RECT  0.084 59.856 2.369 59.88 ;
     RECT  0.06 59.88 2.369 59.952 ;
     RECT  0.084 59.952 2.369 59.976 ;
     RECT  0.06 59.976 2.369 60.048 ;
     RECT  0.084 60.048 2.369 60.072 ;
     RECT  0.06 60.072 2.369 60.144 ;
     RECT  0.084 60.144 2.369 60.168 ;
     RECT  0.06 60.168 2.369 60.24 ;
     RECT  0.084 60.24 2.369 60.264 ;
     RECT  0.06 60.264 2.369 60.336 ;
     RECT  0.084 60.336 2.369 60.36 ;
     RECT  0.06 60.36 2.369 60.432 ;
     RECT  0.084 60.432 2.369 60.456 ;
     RECT  0.06 60.456 2.369 60.528 ;
     RECT  0.084 60.528 2.369 60.552 ;
     RECT  0.06 60.552 2.369 60.624 ;
     RECT  0.084 60.624 2.369 60.648 ;
     RECT  0.06 60.648 2.369 60.72 ;
     RECT  0.084 60.72 2.369 60.744 ;
     RECT  0.06 60.744 2.369 60.816 ;
     RECT  0.084 60.816 2.369 60.84 ;
     RECT  0.06 60.84 2.369 60.912 ;
     RECT  0.084 60.912 2.369 60.936 ;
     RECT  0.06 60.936 2.369 61.008 ;
     RECT  0.084 61.008 2.369 61.032 ;
     RECT  0.06 61.032 2.369 61.104 ;
     RECT  0.084 61.104 2.369 61.128 ;
     RECT  0.06 61.128 2.369 61.2 ;
     RECT  0.084 61.2 2.369 61.224 ;
     RECT  0.06 61.224 2.369 61.296 ;
     RECT  0.084 61.296 2.369 61.32 ;
     RECT  0.06 61.32 2.369 61.392 ;
     RECT  0.084 61.392 2.369 61.416 ;
     RECT  0.06 61.416 2.369 61.488 ;
     RECT  0.084 61.488 2.369 61.512 ;
     RECT  0.06 61.512 2.369 61.584 ;
     RECT  0.084 61.584 2.369 61.608 ;
     RECT  0.06 61.608 2.369 61.68 ;
     RECT  0.084 61.68 2.369 61.704 ;
     RECT  0.06 61.704 2.369 61.776 ;
     RECT  0.084 61.776 2.369 61.8 ;
     RECT  0.06 61.8 2.369 61.872 ;
     RECT  0.084 61.872 2.369 61.896 ;
     RECT  0.06 61.896 2.369 61.968 ;
     RECT  0.084 61.968 2.369 61.992 ;
     RECT  0.06 61.992 2.369 62.064 ;
     RECT  0.084 62.064 2.369 62.088 ;
     RECT  0.06 62.088 2.369 62.16 ;
     RECT  0.084 62.16 2.369 62.184 ;
     RECT  0.06 62.184 2.369 62.256 ;
     RECT  0.084 62.256 2.369 62.28 ;
     RECT  0.06 62.28 2.369 62.352 ;
     RECT  0.084 62.352 2.369 62.376 ;
     RECT  0.06 62.376 2.369 62.448 ;
     RECT  0.084 62.448 2.369 62.472 ;
     RECT  0.06 62.472 2.369 62.544 ;
     RECT  0.084 62.544 2.369 62.568 ;
     RECT  0.06 62.568 2.369 62.64 ;
     RECT  0.084 62.64 2.369 62.664 ;
     RECT  0.06 62.664 2.369 62.736 ;
     RECT  0.084 62.736 2.369 62.76 ;
     RECT  0.06 62.76 2.369 62.832 ;
     RECT  0.084 62.832 2.369 62.856 ;
     RECT  0.06 62.856 2.369 62.928 ;
     RECT  0.084 62.928 2.369 62.952 ;
     RECT  0.06 62.952 2.369 63.024 ;
     RECT  0.084 63.024 2.369 63.048 ;
     RECT  0.06 63.048 2.369 63.12 ;
     RECT  0.084 63.12 2.369 63.144 ;
     RECT  0.06 63.144 2.369 63.216 ;
     RECT  0.084 63.216 2.369 63.24 ;
     RECT  0.06 63.24 2.369 63.312 ;
     RECT  0.084 63.312 2.369 63.336 ;
     RECT  0.06 63.336 2.369 63.408 ;
     RECT  0.084 63.408 2.369 63.432 ;
     RECT  0.06 63.432 2.369 63.504 ;
     RECT  0.084 63.504 2.369 63.528 ;
     RECT  0.06 63.528 2.369 63.6 ;
     RECT  0.084 63.6 2.369 63.624 ;
     RECT  0.06 63.624 2.369 63.696 ;
     RECT  0.084 63.696 2.369 63.72 ;
     RECT  0.06 63.72 2.369 63.792 ;
     RECT  0.084 63.792 2.369 63.816 ;
     RECT  0.06 63.816 2.369 63.888 ;
     RECT  0.084 63.888 2.369 63.912 ;
     RECT  0.06 63.912 2.369 63.984 ;
     RECT  0.084 63.984 2.369 64.008 ;
     RECT  2.369 1.872 2.765 64.008 ;
     RECT  2.765 1.968 4.061 64.008 ;
     RECT  4.061 1.968 4.601 44.904 ;
     RECT  4.601 2.148 5.108 44.904 ;
     RECT  4.061 45.888 5.108 64.008 ;
     RECT  5.108 2.148 5.965 64.008 ;
     RECT  5.965 2.064 6.829 64.008 ;
     RECT  6.829 1.968 7.013 64.008 ;
     RECT  7.013 1.968 7.481 63.72 ;
     RECT  7.481 1.968 10.829 63.384 ;
     RECT  10.829 2.064 11.297 63.384 ;
     RECT  11.297 15.984 11.315 63.384 ;
     RECT  11.315 15.984 11.369 42.888 ;
     RECT  11.369 17.328 11.405 42.888 ;
     RECT  11.405 17.328 11.477 24.12 ;
     RECT  11.405 32.208 11.477 42.888 ;
     RECT  11.297 2.064 11.513 14.712 ;
     RECT  11.369 15.984 11.513 16.296 ;
     RECT  11.477 18.48 11.513 24.12 ;
     RECT  11.513 2.064 11.549 9.48 ;
     RECT  11.477 17.328 11.549 17.448 ;
     RECT  11.477 32.208 11.549 36.888 ;
     RECT  11.315 44.16 11.585 63.384 ;
     RECT  11.513 15.984 11.657 16.104 ;
     RECT  11.549 32.304 11.657 36.888 ;
     RECT  11.657 32.304 11.693 35.256 ;
     RECT  11.657 36.816 11.729 36.84 ;
     RECT  11.513 10.656 11.765 14.712 ;
     RECT  11.513 18.72 11.765 24.12 ;
     RECT  11.405 25.44 11.801 30.84 ;
     RECT  11.477 37.872 11.837 42.888 ;
     RECT  11.765 18.72 11.873 21.816 ;
     RECT  11.801 26.544 11.981 30.84 ;
     RECT  11.873 18.96 12.017 21.816 ;
     RECT  11.981 26.544 12.017 29.88 ;
     RECT  11.941 0.576 12.025 0.6 ;
     RECT  11.585 44.16 12.053 63.288 ;
     RECT  11.549 6.528 12.161 9.48 ;
     RECT  11.837 38.064 12.197 42.888 ;
     RECT  12.017 26.544 12.233 29.784 ;
     RECT  11.549 2.064 12.805 5.544 ;
     RECT  11.765 10.656 12.877 14.664 ;
     RECT  11.549 17.328 13.021 17.352 ;
     RECT  12.053 52.752 13.061 63.288 ;
     RECT  12.805 2.016 13.208 5.544 ;
     RECT  12.161 6.528 13.208 9.048 ;
     RECT  12.877 10.176 13.208 14.664 ;
     RECT  11.657 15.984 13.208 16.008 ;
     RECT  13.021 17.328 13.208 17.448 ;
     RECT  12.017 18.96 13.208 20.088 ;
     RECT  12.017 21.792 13.208 21.816 ;
     RECT  11.765 23.04 13.208 24.12 ;
     RECT  11.801 25.44 13.208 25.464 ;
     RECT  12.233 26.544 13.208 29.496 ;
     RECT  11.693 32.304 13.208 32.904 ;
     RECT  11.693 34.032 13.208 35.256 ;
     RECT  12.197 38.064 13.208 42.552 ;
     RECT  12.053 44.16 13.208 51.096 ;
     RECT  13.061 52.752 13.208 62.76 ;
     RECT  13.208 2.016 13.504 62.76 ;
     RECT  13.504 6.528 13.565 9.048 ;
     RECT  13.504 18.96 13.565 20.088 ;
     RECT  13.504 58.368 13.565 61.176 ;
     RECT  13.565 18.96 13.601 19.8 ;
     RECT  13.504 40.848 13.601 42.552 ;
     RECT  13.504 53.328 14.069 54.456 ;
     RECT  13.504 34.128 14.105 35.256 ;
     RECT  13.565 6.528 14.249 9 ;
     RECT  14.105 34.464 14.429 35.256 ;
     RECT  13.504 62.16 14.485 62.76 ;
     RECT  13.504 44.352 14.537 50.568 ;
     RECT  14.537 44.352 14.627 48.984 ;
     RECT  13.565 58.368 14.645 60.84 ;
     RECT  13.504 21.792 14.681 21.816 ;
     RECT  14.645 58.368 14.717 60.648 ;
     RECT  13.504 2.016 14.821 5.544 ;
     RECT  13.601 18.96 14.821 19.512 ;
     RECT  13.504 26.544 14.821 29.496 ;
     RECT  13.601 40.848 14.821 42.504 ;
     RECT  14.429 34.656 14.825 35.256 ;
     RECT  14.641 56.208 14.825 56.232 ;
     RECT  14.821 40.848 14.857 42.552 ;
     RECT  14.069 53.328 14.861 53.688 ;
     RECT  14.717 58.368 14.861 60.312 ;
     RECT  14.485 61.872 14.861 62.76 ;
     RECT  13.504 32.448 14.929 32.472 ;
     RECT  14.857 40.848 14.929 43.128 ;
     RECT  14.249 6.528 14.933 8.808 ;
     RECT  14.929 40.848 15.061 43.368 ;
     RECT  14.627 44.352 15.061 48.744 ;
     RECT  14.821 1.92 15.908 5.544 ;
     RECT  14.933 6.576 15.908 8.808 ;
     RECT  13.504 10.656 15.908 10.68 ;
     RECT  13.504 11.712 15.908 14.664 ;
     RECT  13.504 15.984 15.908 16.008 ;
     RECT  13.504 17.424 15.908 17.448 ;
     RECT  14.821 18.96 15.908 19.608 ;
     RECT  13.504 23.04 15.908 24.12 ;
     RECT  13.504 25.44 15.908 25.464 ;
     RECT  14.821 26.544 15.908 29.592 ;
     RECT  14.929 32.304 15.908 32.472 ;
     RECT  14.825 34.656 15.908 35.208 ;
     RECT  13.504 38.16 15.908 39.864 ;
     RECT  15.061 40.848 15.908 48.744 ;
     RECT  14.537 50.544 15.908 50.568 ;
     RECT  14.861 53.328 15.908 53.592 ;
     RECT  14.861 58.464 15.908 60.312 ;
     RECT  14.861 61.968 15.908 62.76 ;
     RECT  15.908 1.92 16.204 62.76 ;
     RECT  16.204 58.464 16.337 59.016 ;
     RECT  16.204 44.352 16.481 48.744 ;
     RECT  16.204 6.576 16.553 14.664 ;
     RECT  16.204 37.584 16.553 39.864 ;
     RECT  16.553 6.576 16.733 11.736 ;
     RECT  16.204 50.736 16.769 50.76 ;
     RECT  16.204 1.92 16.913 5.544 ;
     RECT  16.204 30.816 17.057 30.84 ;
     RECT  16.553 12.864 17.129 14.664 ;
     RECT  16.204 40.848 17.197 43.32 ;
     RECT  16.481 44.352 17.197 47.88 ;
     RECT  16.204 23.04 17.201 24.12 ;
     RECT  16.204 17.424 17.269 17.448 ;
     RECT  16.204 32.304 17.269 32.328 ;
     RECT  16.204 53.568 17.305 54.12 ;
     RECT  16.204 18.96 17.341 19.608 ;
     RECT  16.913 2.016 17.345 5.544 ;
     RECT  17.129 14.592 17.377 14.664 ;
     RECT  17.201 24.096 17.413 24.12 ;
     RECT  16.204 25.152 17.413 29.832 ;
     RECT  16.204 60.288 17.413 60.312 ;
     RECT  17.413 24.096 17.449 29.832 ;
     RECT  16.204 52.032 17.449 52.056 ;
     RECT  17.305 53.04 17.449 54.12 ;
     RECT  16.733 6.576 17.489 10.296 ;
     RECT  17.341 18.912 17.557 19.608 ;
     RECT  17.557 18.432 17.629 19.608 ;
     RECT  17.201 23.04 17.629 23.064 ;
     RECT  16.553 37.584 17.629 38.472 ;
     RECT  16.204 57.072 17.629 57.096 ;
     RECT  16.733 11.712 17.701 11.736 ;
     RECT  17.129 12.864 17.701 13.56 ;
     RECT  17.377 14.592 17.701 14.808 ;
     RECT  17.305 49.44 17.701 49.464 ;
     RECT  17.345 2.064 17.773 5.544 ;
     RECT  17.489 6.576 17.773 7.704 ;
     RECT  17.629 37.152 17.809 38.472 ;
     RECT  17.269 17.04 17.941 17.448 ;
     RECT  17.629 18.432 17.941 20.52 ;
     RECT  16.204 61.968 17.989 62.76 ;
     RECT  17.629 57.072 18.025 57.576 ;
     RECT  17.197 40.848 18.061 47.88 ;
     RECT  18.061 40.848 18.169 48.456 ;
     RECT  17.701 49.44 18.169 49.512 ;
     RECT  17.809 37.056 18.241 38.472 ;
     RECT  17.413 60.288 18.241 60.456 ;
     RECT  17.989 61.92 18.241 62.76 ;
     RECT  17.449 52.032 18.385 54.12 ;
     RECT  17.629 22.752 18.421 23.064 ;
     RECT  17.449 24.096 18.421 30.744 ;
     RECT  17.773 2.064 18.457 7.704 ;
     RECT  17.489 8.736 18.457 10.296 ;
     RECT  18.421 22.752 18.565 30.744 ;
     RECT  18.457 2.064 18.608 10.296 ;
     RECT  17.701 11.28 18.608 13.56 ;
     RECT  17.701 14.592 18.608 14.856 ;
     RECT  16.204 15.984 18.608 16.008 ;
     RECT  17.941 17.04 18.608 20.52 ;
     RECT  18.565 22.032 18.608 30.744 ;
     RECT  17.269 32.304 18.608 32.376 ;
     RECT  17.845 33.504 18.608 33.528 ;
     RECT  16.204 35.184 18.608 35.208 ;
     RECT  18.241 36.624 18.608 38.472 ;
     RECT  16.553 39.84 18.608 39.864 ;
     RECT  18.169 40.848 18.608 49.512 ;
     RECT  18.385 52.032 18.608 54.648 ;
     RECT  18.025 56.832 18.608 57.576 ;
     RECT  16.337 58.992 18.608 59.016 ;
     RECT  18.241 60.288 18.608 60.936 ;
     RECT  18.241 61.92 18.608 62.856 ;
     RECT  18.608 2.064 18.904 62.856 ;
     RECT  19.321 1.008 19.357 1.032 ;
     RECT  19.357 0.72 19.897 1.032 ;
     RECT  18.904 2.064 19.897 18.792 ;
     RECT  18.904 20.784 19.897 34.536 ;
     RECT  18.904 35.568 19.897 57.48 ;
     RECT  18.904 58.608 19.897 62.856 ;
     RECT  19.897 20.784 19.933 57.48 ;
     RECT  19.897 0.72 20.293 18.792 ;
     RECT  19.933 19.92 20.293 57.48 ;
     RECT  20.293 0.72 20.365 57.48 ;
     RECT  19.897 58.512 20.365 62.856 ;
     RECT  20.365 0.72 21.516 0.744 ;
     RECT  20.365 0.744 21.564 0.816 ;
     RECT  20.365 0.816 21.516 0.84 ;
     RECT  20.365 0.84 21.564 0.912 ;
     RECT  20.365 0.912 21.516 0.936 ;
     RECT  20.365 0.936 21.564 1.008 ;
     RECT  20.365 1.008 21.516 1.032 ;
     RECT  20.365 1.032 21.564 1.104 ;
     RECT  20.365 1.104 21.516 1.128 ;
     RECT  20.365 1.128 21.564 1.2 ;
     RECT  20.365 1.2 21.516 1.224 ;
     RECT  20.365 1.224 21.564 1.296 ;
     RECT  20.365 1.296 21.516 1.32 ;
     RECT  20.365 1.32 21.564 1.392 ;
     RECT  20.365 1.392 21.516 1.416 ;
     RECT  20.365 1.416 21.564 1.488 ;
     RECT  20.365 1.488 21.516 1.512 ;
     RECT  20.365 1.512 21.564 1.584 ;
     RECT  20.365 1.584 21.516 1.608 ;
     RECT  20.365 1.608 21.564 1.68 ;
     RECT  20.365 1.68 21.516 1.704 ;
     RECT  20.365 1.704 21.564 1.776 ;
     RECT  20.365 1.776 21.516 1.8 ;
     RECT  20.365 1.8 21.564 1.872 ;
     RECT  20.365 1.872 21.516 1.896 ;
     RECT  20.365 1.896 21.564 1.968 ;
     RECT  20.365 1.968 21.516 1.992 ;
     RECT  20.365 1.992 21.564 2.064 ;
     RECT  20.365 2.064 21.516 2.088 ;
     RECT  20.365 2.088 21.564 2.16 ;
     RECT  20.365 2.16 21.516 2.184 ;
     RECT  20.365 2.184 21.564 2.256 ;
     RECT  20.365 2.256 21.516 2.28 ;
     RECT  20.365 2.28 21.564 2.352 ;
     RECT  20.365 2.352 21.516 2.376 ;
     RECT  20.365 2.376 21.564 2.448 ;
     RECT  20.365 2.448 21.516 2.472 ;
     RECT  20.365 2.472 21.564 2.544 ;
     RECT  20.365 2.544 21.516 2.568 ;
     RECT  20.365 2.568 21.564 2.64 ;
     RECT  20.365 2.64 21.516 2.664 ;
     RECT  20.365 2.664 21.564 2.736 ;
     RECT  20.365 2.736 21.516 2.76 ;
     RECT  20.365 2.76 21.564 2.832 ;
     RECT  20.365 2.832 21.516 2.856 ;
     RECT  20.365 2.856 21.564 2.928 ;
     RECT  20.365 2.928 21.516 2.952 ;
     RECT  20.365 2.952 21.564 3.024 ;
     RECT  20.365 3.024 21.516 3.048 ;
     RECT  20.365 3.048 21.564 3.12 ;
     RECT  20.365 3.12 21.516 3.144 ;
     RECT  20.365 3.144 21.564 3.216 ;
     RECT  20.365 3.216 21.516 3.24 ;
     RECT  20.365 3.24 21.564 3.312 ;
     RECT  20.365 3.312 21.516 3.336 ;
     RECT  20.365 3.336 21.564 3.408 ;
     RECT  20.365 3.408 21.516 3.432 ;
     RECT  20.365 3.432 21.564 3.504 ;
     RECT  20.365 3.504 21.516 3.528 ;
     RECT  20.365 3.528 21.564 3.6 ;
     RECT  20.365 3.6 21.516 3.624 ;
     RECT  20.365 3.624 21.564 3.696 ;
     RECT  20.365 3.696 21.516 3.72 ;
     RECT  20.365 3.72 21.564 3.792 ;
     RECT  20.365 3.792 21.516 3.816 ;
     RECT  20.365 3.816 21.564 3.888 ;
     RECT  20.365 3.888 21.516 3.912 ;
     RECT  20.365 3.912 21.564 3.984 ;
     RECT  20.365 3.984 21.516 4.008 ;
     RECT  20.365 4.008 21.564 4.08 ;
     RECT  20.365 4.08 21.516 4.104 ;
     RECT  20.365 4.104 21.564 4.176 ;
     RECT  20.365 4.176 21.516 4.2 ;
     RECT  20.365 4.2 21.564 4.272 ;
     RECT  20.365 4.272 21.516 4.296 ;
     RECT  20.365 4.296 21.564 4.368 ;
     RECT  20.365 4.368 21.516 4.392 ;
     RECT  20.365 4.392 21.564 4.464 ;
     RECT  20.365 4.464 21.516 4.488 ;
     RECT  20.365 4.488 21.564 4.56 ;
     RECT  20.365 4.56 21.516 4.584 ;
     RECT  20.365 4.584 21.564 4.656 ;
     RECT  20.365 4.656 21.516 4.68 ;
     RECT  20.365 4.68 21.564 4.752 ;
     RECT  20.365 4.752 21.516 4.776 ;
     RECT  20.365 4.776 21.564 4.848 ;
     RECT  20.365 4.848 21.516 4.872 ;
     RECT  20.365 4.872 21.564 4.944 ;
     RECT  20.365 4.944 21.516 4.968 ;
     RECT  20.365 4.968 21.564 5.04 ;
     RECT  20.365 5.04 21.516 5.064 ;
     RECT  20.365 5.064 21.564 5.136 ;
     RECT  20.365 5.136 21.516 5.16 ;
     RECT  20.365 5.16 21.564 5.232 ;
     RECT  20.365 5.232 21.516 5.256 ;
     RECT  20.365 5.256 21.564 5.328 ;
     RECT  20.365 5.328 21.516 5.352 ;
     RECT  20.365 5.352 21.564 5.424 ;
     RECT  20.365 5.424 21.516 5.448 ;
     RECT  20.365 5.448 21.564 5.52 ;
     RECT  20.365 5.52 21.516 5.544 ;
     RECT  20.365 5.544 21.564 5.616 ;
     RECT  20.365 5.616 21.516 5.64 ;
     RECT  20.365 5.64 21.564 5.712 ;
     RECT  20.365 5.712 21.516 5.736 ;
     RECT  20.365 5.736 21.564 5.808 ;
     RECT  20.365 5.808 21.516 5.832 ;
     RECT  20.365 5.832 21.564 5.904 ;
     RECT  20.365 5.904 21.516 5.928 ;
     RECT  20.365 5.928 21.564 6 ;
     RECT  20.365 6 21.516 6.024 ;
     RECT  20.365 6.024 21.564 6.096 ;
     RECT  20.365 6.096 21.516 6.12 ;
     RECT  20.365 6.12 21.564 6.192 ;
     RECT  20.365 6.192 21.516 6.216 ;
     RECT  20.365 6.216 21.564 6.288 ;
     RECT  20.365 6.288 21.516 6.312 ;
     RECT  20.365 6.312 21.564 6.384 ;
     RECT  20.365 6.384 21.516 6.408 ;
     RECT  20.365 6.408 21.564 6.48 ;
     RECT  20.365 6.48 21.516 6.504 ;
     RECT  20.365 6.504 21.564 6.576 ;
     RECT  20.365 6.576 21.516 6.6 ;
     RECT  20.365 6.6 21.564 6.672 ;
     RECT  20.365 6.672 21.516 6.696 ;
     RECT  20.365 6.696 21.564 6.768 ;
     RECT  20.365 6.768 21.516 6.792 ;
     RECT  20.365 6.792 21.564 6.864 ;
     RECT  20.365 6.864 21.516 6.888 ;
     RECT  20.365 6.888 21.564 6.96 ;
     RECT  20.365 6.96 21.516 6.984 ;
     RECT  20.365 6.984 21.564 7.056 ;
     RECT  20.365 7.056 21.516 7.08 ;
     RECT  20.365 7.08 21.564 7.152 ;
     RECT  20.365 7.152 21.516 7.176 ;
     RECT  20.365 7.176 21.564 7.248 ;
     RECT  20.365 7.248 21.516 7.272 ;
     RECT  20.365 7.272 21.564 7.344 ;
     RECT  20.365 7.344 21.516 7.368 ;
     RECT  20.365 7.368 21.564 7.44 ;
     RECT  20.365 7.44 21.516 7.464 ;
     RECT  20.365 7.464 21.564 7.536 ;
     RECT  20.365 7.536 21.516 7.56 ;
     RECT  20.365 7.56 21.564 7.632 ;
     RECT  20.365 7.632 21.516 7.656 ;
     RECT  20.365 7.656 21.564 7.728 ;
     RECT  20.365 7.728 21.516 7.752 ;
     RECT  20.365 7.752 21.564 7.824 ;
     RECT  20.365 7.824 21.516 7.848 ;
     RECT  20.365 7.848 21.564 7.92 ;
     RECT  20.365 7.92 21.516 7.944 ;
     RECT  20.365 7.944 21.564 8.016 ;
     RECT  20.365 8.016 21.516 8.04 ;
     RECT  20.365 8.04 21.564 8.112 ;
     RECT  20.365 8.112 21.516 8.136 ;
     RECT  20.365 8.136 21.564 8.208 ;
     RECT  20.365 8.208 21.516 8.232 ;
     RECT  20.365 8.232 21.564 8.304 ;
     RECT  20.365 8.304 21.516 8.328 ;
     RECT  20.365 8.328 21.564 8.4 ;
     RECT  20.365 8.4 21.516 8.424 ;
     RECT  20.365 8.424 21.564 8.496 ;
     RECT  20.365 8.496 21.516 8.52 ;
     RECT  20.365 8.52 21.564 8.592 ;
     RECT  20.365 8.592 21.516 8.616 ;
     RECT  20.365 8.616 21.564 8.688 ;
     RECT  20.365 8.688 21.516 8.712 ;
     RECT  20.365 8.712 21.564 8.784 ;
     RECT  20.365 8.784 21.516 8.808 ;
     RECT  20.365 8.808 21.564 8.88 ;
     RECT  20.365 8.88 21.516 8.904 ;
     RECT  20.365 8.904 21.564 8.976 ;
     RECT  20.365 8.976 21.516 9 ;
     RECT  20.365 9 21.564 9.072 ;
     RECT  20.365 9.072 21.516 9.096 ;
     RECT  20.365 9.096 21.564 9.168 ;
     RECT  20.365 9.168 21.516 9.192 ;
     RECT  20.365 9.192 21.564 9.264 ;
     RECT  20.365 9.264 21.516 9.288 ;
     RECT  20.365 9.288 21.564 9.36 ;
     RECT  20.365 9.36 21.516 9.384 ;
     RECT  20.365 9.384 21.564 9.456 ;
     RECT  20.365 9.456 21.516 9.48 ;
     RECT  20.365 9.48 21.564 9.552 ;
     RECT  20.365 9.552 21.516 9.576 ;
     RECT  20.365 9.576 21.564 9.648 ;
     RECT  20.365 9.648 21.516 9.672 ;
     RECT  20.365 9.672 21.564 9.744 ;
     RECT  20.365 9.744 21.516 9.768 ;
     RECT  20.365 9.768 21.564 9.84 ;
     RECT  20.365 9.84 21.516 9.864 ;
     RECT  20.365 9.864 21.564 9.936 ;
     RECT  20.365 9.936 21.516 9.96 ;
     RECT  20.365 9.96 21.564 10.032 ;
     RECT  20.365 10.032 21.516 10.056 ;
     RECT  20.365 10.056 21.564 10.128 ;
     RECT  20.365 10.128 21.516 10.152 ;
     RECT  20.365 10.152 21.564 10.224 ;
     RECT  20.365 10.224 21.516 10.248 ;
     RECT  20.365 10.248 21.564 10.32 ;
     RECT  20.365 10.32 21.516 10.344 ;
     RECT  20.365 10.344 21.564 10.416 ;
     RECT  20.365 10.416 21.516 10.44 ;
     RECT  20.365 10.44 21.564 10.512 ;
     RECT  20.365 10.512 21.516 10.536 ;
     RECT  20.365 10.536 21.564 10.608 ;
     RECT  20.365 10.608 21.516 10.632 ;
     RECT  20.365 10.632 21.564 10.704 ;
     RECT  20.365 10.704 21.516 10.728 ;
     RECT  20.365 10.728 21.564 10.8 ;
     RECT  20.365 10.8 21.516 10.824 ;
     RECT  20.365 10.824 21.564 10.896 ;
     RECT  20.365 10.896 21.516 10.92 ;
     RECT  20.365 10.92 21.564 10.992 ;
     RECT  20.365 10.992 21.516 11.016 ;
     RECT  20.365 11.016 21.564 11.088 ;
     RECT  20.365 11.088 21.516 11.112 ;
     RECT  20.365 11.112 21.564 11.184 ;
     RECT  20.365 11.184 21.516 11.208 ;
     RECT  20.365 11.208 21.564 11.28 ;
     RECT  20.365 11.28 21.516 11.304 ;
     RECT  20.365 11.304 21.564 11.376 ;
     RECT  20.365 11.376 21.516 11.4 ;
     RECT  20.365 11.4 21.564 11.472 ;
     RECT  20.365 11.472 21.516 11.496 ;
     RECT  20.365 11.496 21.564 11.568 ;
     RECT  20.365 11.568 21.516 11.592 ;
     RECT  20.365 11.592 21.564 11.664 ;
     RECT  20.365 11.664 21.516 11.688 ;
     RECT  20.365 11.688 21.564 11.76 ;
     RECT  20.365 11.76 21.516 11.784 ;
     RECT  20.365 11.784 21.564 11.856 ;
     RECT  20.365 11.856 21.516 11.88 ;
     RECT  20.365 11.88 21.564 11.952 ;
     RECT  20.365 11.952 21.516 11.976 ;
     RECT  20.365 11.976 21.564 12.048 ;
     RECT  20.365 12.048 21.516 12.072 ;
     RECT  20.365 12.072 21.564 12.144 ;
     RECT  20.365 12.144 21.516 12.168 ;
     RECT  20.365 12.168 21.564 12.24 ;
     RECT  20.365 12.24 21.516 12.264 ;
     RECT  20.365 12.264 21.564 12.336 ;
     RECT  20.365 12.336 21.516 12.36 ;
     RECT  20.365 12.36 21.564 12.432 ;
     RECT  20.365 12.432 21.516 12.456 ;
     RECT  20.365 12.456 21.564 12.528 ;
     RECT  20.365 12.528 21.516 12.552 ;
     RECT  20.365 12.552 21.564 12.624 ;
     RECT  20.365 12.624 21.516 12.648 ;
     RECT  20.365 12.648 21.564 12.72 ;
     RECT  20.365 12.72 21.516 12.744 ;
     RECT  20.365 12.744 21.564 12.816 ;
     RECT  20.365 12.816 21.516 12.84 ;
     RECT  20.365 12.84 21.564 12.912 ;
     RECT  20.365 12.912 21.516 12.936 ;
     RECT  20.365 12.936 21.564 13.008 ;
     RECT  20.365 13.008 21.516 13.032 ;
     RECT  20.365 13.032 21.564 13.104 ;
     RECT  20.365 13.104 21.516 13.128 ;
     RECT  20.365 13.128 21.564 13.2 ;
     RECT  20.365 13.2 21.516 13.224 ;
     RECT  20.365 13.224 21.564 13.296 ;
     RECT  20.365 13.296 21.516 13.32 ;
     RECT  20.365 13.32 21.564 13.392 ;
     RECT  20.365 13.392 21.516 13.416 ;
     RECT  20.365 13.416 21.564 13.488 ;
     RECT  20.365 13.488 21.516 13.512 ;
     RECT  20.365 13.512 21.564 13.584 ;
     RECT  20.365 13.584 21.516 13.608 ;
     RECT  20.365 13.608 21.564 13.68 ;
     RECT  20.365 13.68 21.516 13.704 ;
     RECT  20.365 13.704 21.564 13.776 ;
     RECT  20.365 13.776 21.516 13.8 ;
     RECT  20.365 13.8 21.564 13.872 ;
     RECT  20.365 13.872 21.516 13.896 ;
     RECT  20.365 13.896 21.564 13.968 ;
     RECT  20.365 13.968 21.516 13.992 ;
     RECT  20.365 13.992 21.564 14.064 ;
     RECT  20.365 14.064 21.516 14.088 ;
     RECT  20.365 14.088 21.564 14.16 ;
     RECT  20.365 14.16 21.516 14.184 ;
     RECT  20.365 14.184 21.564 14.256 ;
     RECT  20.365 14.256 21.516 14.28 ;
     RECT  20.365 14.28 21.564 14.352 ;
     RECT  20.365 14.352 21.516 14.376 ;
     RECT  20.365 14.376 21.564 14.448 ;
     RECT  20.365 14.448 21.516 14.472 ;
     RECT  20.365 14.472 21.564 14.544 ;
     RECT  20.365 14.544 21.516 14.568 ;
     RECT  20.365 14.568 21.564 14.64 ;
     RECT  20.365 14.64 21.516 14.664 ;
     RECT  20.365 14.664 21.564 14.736 ;
     RECT  20.365 14.736 21.516 14.76 ;
     RECT  20.365 14.76 21.564 14.832 ;
     RECT  20.365 14.832 21.516 14.856 ;
     RECT  20.365 14.856 21.564 14.928 ;
     RECT  20.365 14.928 21.516 14.952 ;
     RECT  20.365 14.952 21.564 15.024 ;
     RECT  20.365 15.024 21.516 15.048 ;
     RECT  20.365 15.048 21.564 15.12 ;
     RECT  20.365 15.12 21.516 15.144 ;
     RECT  20.365 15.144 21.564 15.216 ;
     RECT  20.365 15.216 21.516 15.24 ;
     RECT  20.365 15.24 21.564 15.312 ;
     RECT  20.365 15.312 21.516 15.336 ;
     RECT  20.365 15.336 21.564 15.408 ;
     RECT  20.365 15.408 21.516 15.432 ;
     RECT  20.365 15.432 21.564 15.504 ;
     RECT  20.365 15.504 21.516 15.528 ;
     RECT  20.365 15.528 21.564 15.6 ;
     RECT  20.365 15.6 21.516 15.624 ;
     RECT  20.365 15.624 21.564 15.696 ;
     RECT  20.365 15.696 21.516 15.72 ;
     RECT  20.365 15.72 21.564 15.792 ;
     RECT  20.365 15.792 21.516 15.816 ;
     RECT  20.365 15.816 21.564 15.888 ;
     RECT  20.365 15.888 21.516 15.912 ;
     RECT  20.365 15.912 21.564 15.984 ;
     RECT  20.365 15.984 21.516 16.008 ;
     RECT  20.365 16.008 21.564 16.08 ;
     RECT  20.365 16.08 21.516 16.104 ;
     RECT  20.365 16.104 21.564 16.176 ;
     RECT  20.365 16.176 21.516 16.2 ;
     RECT  20.365 16.2 21.564 16.272 ;
     RECT  20.365 16.272 21.516 16.296 ;
     RECT  20.365 16.296 21.564 16.368 ;
     RECT  20.365 16.368 21.516 16.392 ;
     RECT  20.365 16.392 21.564 16.464 ;
     RECT  20.365 16.464 21.516 16.488 ;
     RECT  20.365 16.488 21.564 16.56 ;
     RECT  20.365 16.56 21.516 16.584 ;
     RECT  20.365 16.584 21.564 16.656 ;
     RECT  20.365 16.656 21.516 16.68 ;
     RECT  20.365 16.68 21.564 16.752 ;
     RECT  20.365 16.752 21.516 16.776 ;
     RECT  20.365 16.776 21.564 16.848 ;
     RECT  20.365 16.848 21.516 16.872 ;
     RECT  20.365 16.872 21.564 16.944 ;
     RECT  20.365 16.944 21.516 16.968 ;
     RECT  20.365 16.968 21.564 17.04 ;
     RECT  20.365 17.04 21.516 17.064 ;
     RECT  20.365 17.064 21.564 17.136 ;
     RECT  20.365 17.136 21.516 17.16 ;
     RECT  20.365 17.16 21.564 17.232 ;
     RECT  20.365 17.232 21.516 17.256 ;
     RECT  20.365 17.256 21.564 17.328 ;
     RECT  20.365 17.328 21.516 17.352 ;
     RECT  20.365 17.352 21.564 17.424 ;
     RECT  20.365 17.424 21.516 17.448 ;
     RECT  20.365 17.448 21.564 17.52 ;
     RECT  20.365 17.52 21.516 17.544 ;
     RECT  20.365 17.544 21.564 17.616 ;
     RECT  20.365 17.616 21.516 17.64 ;
     RECT  20.365 17.64 21.564 17.712 ;
     RECT  20.365 17.712 21.516 17.736 ;
     RECT  20.365 17.736 21.564 17.808 ;
     RECT  20.365 17.808 21.516 17.832 ;
     RECT  20.365 17.832 21.564 17.904 ;
     RECT  20.365 17.904 21.516 17.928 ;
     RECT  20.365 17.928 21.564 18 ;
     RECT  20.365 18 21.516 18.024 ;
     RECT  20.365 18.024 21.564 18.096 ;
     RECT  20.365 18.096 21.516 18.12 ;
     RECT  20.365 18.12 21.564 18.192 ;
     RECT  20.365 18.192 21.516 18.216 ;
     RECT  20.365 18.216 21.564 18.288 ;
     RECT  20.365 18.288 21.516 18.312 ;
     RECT  20.365 18.312 21.564 18.384 ;
     RECT  20.365 18.384 21.516 18.408 ;
     RECT  20.365 18.408 21.564 18.48 ;
     RECT  20.365 18.48 21.516 18.504 ;
     RECT  20.365 18.504 21.564 18.576 ;
     RECT  20.365 18.576 21.516 18.6 ;
     RECT  20.365 18.6 21.564 18.672 ;
     RECT  20.365 18.672 21.516 18.696 ;
     RECT  20.365 18.696 21.564 18.768 ;
     RECT  20.365 18.768 21.516 18.792 ;
     RECT  20.365 18.792 21.564 18.864 ;
     RECT  20.365 18.864 21.516 18.888 ;
     RECT  20.365 18.888 21.564 18.96 ;
     RECT  20.365 18.96 21.516 18.984 ;
     RECT  20.365 18.984 21.564 19.056 ;
     RECT  20.365 19.056 21.516 19.08 ;
     RECT  20.365 19.08 21.564 19.92 ;
     RECT  20.365 19.92 21.516 19.944 ;
     RECT  20.365 19.944 21.564 20.016 ;
     RECT  20.365 20.016 21.516 20.04 ;
     RECT  20.365 20.04 21.564 20.112 ;
     RECT  20.365 20.112 21.516 20.136 ;
     RECT  20.365 20.136 21.564 20.208 ;
     RECT  20.365 20.208 21.516 20.232 ;
     RECT  20.365 20.232 21.564 20.304 ;
     RECT  20.365 20.304 21.516 20.328 ;
     RECT  20.365 20.328 21.564 20.4 ;
     RECT  20.365 20.4 21.516 20.424 ;
     RECT  20.365 20.424 21.564 20.496 ;
     RECT  20.365 20.496 21.516 20.52 ;
     RECT  20.365 20.52 21.564 20.592 ;
     RECT  20.365 20.592 21.516 20.616 ;
     RECT  20.365 20.616 21.564 20.688 ;
     RECT  20.365 20.688 21.516 20.712 ;
     RECT  20.365 20.712 21.564 20.784 ;
     RECT  20.365 20.784 21.516 20.808 ;
     RECT  20.365 20.808 21.564 20.88 ;
     RECT  20.365 20.88 21.516 20.904 ;
     RECT  20.365 20.904 21.564 20.976 ;
     RECT  20.365 20.976 21.516 21 ;
     RECT  20.365 21 21.564 21.072 ;
     RECT  20.365 21.072 21.516 21.096 ;
     RECT  20.365 21.096 21.564 21.168 ;
     RECT  20.365 21.168 21.516 21.192 ;
     RECT  20.365 21.192 21.564 21.264 ;
     RECT  20.365 21.264 21.516 21.288 ;
     RECT  20.365 21.288 21.564 21.36 ;
     RECT  20.365 21.36 21.516 21.384 ;
     RECT  20.365 21.384 21.564 21.456 ;
     RECT  20.365 21.456 21.516 21.48 ;
     RECT  20.365 21.48 21.564 21.552 ;
     RECT  20.365 21.552 21.516 21.576 ;
     RECT  20.365 21.576 21.564 21.648 ;
     RECT  20.365 21.648 21.516 21.672 ;
     RECT  20.365 21.672 21.564 21.744 ;
     RECT  20.365 21.744 21.516 21.768 ;
     RECT  20.365 21.768 21.564 21.84 ;
     RECT  20.365 21.84 21.516 21.864 ;
     RECT  20.365 21.864 21.564 21.936 ;
     RECT  20.365 21.936 21.516 21.96 ;
     RECT  20.365 21.96 21.564 22.032 ;
     RECT  20.365 22.032 21.516 22.056 ;
     RECT  20.365 22.056 21.564 22.128 ;
     RECT  20.365 22.128 21.516 22.152 ;
     RECT  20.365 22.152 21.564 22.224 ;
     RECT  20.365 22.224 21.516 22.248 ;
     RECT  20.365 22.248 21.564 22.32 ;
     RECT  20.365 22.32 21.516 22.344 ;
     RECT  20.365 22.344 21.564 22.416 ;
     RECT  20.365 22.416 21.516 22.44 ;
     RECT  20.365 22.44 21.564 22.512 ;
     RECT  20.365 22.512 21.516 22.536 ;
     RECT  20.365 22.536 21.564 22.608 ;
     RECT  20.365 22.608 21.516 22.632 ;
     RECT  20.365 22.632 21.564 22.704 ;
     RECT  20.365 22.704 21.516 22.728 ;
     RECT  20.365 22.728 21.564 22.8 ;
     RECT  20.365 22.8 21.516 22.824 ;
     RECT  20.365 22.824 21.564 22.896 ;
     RECT  20.365 22.896 21.516 22.92 ;
     RECT  20.365 22.92 21.564 22.992 ;
     RECT  20.365 22.992 21.516 23.016 ;
     RECT  20.365 23.016 21.564 23.088 ;
     RECT  20.365 23.088 21.516 23.112 ;
     RECT  20.365 23.112 21.564 23.184 ;
     RECT  20.365 23.184 21.516 23.208 ;
     RECT  20.365 23.208 21.564 23.28 ;
     RECT  20.365 23.28 21.516 23.304 ;
     RECT  20.365 23.304 21.564 23.376 ;
     RECT  20.365 23.376 21.516 23.4 ;
     RECT  20.365 23.4 21.564 23.472 ;
     RECT  20.365 23.472 21.516 23.496 ;
     RECT  20.365 23.496 21.564 23.568 ;
     RECT  20.365 23.568 21.516 23.592 ;
     RECT  20.365 23.592 21.564 23.664 ;
     RECT  20.365 23.664 21.516 23.688 ;
     RECT  20.365 23.688 21.564 23.76 ;
     RECT  20.365 23.76 21.516 23.784 ;
     RECT  20.365 23.784 21.564 23.856 ;
     RECT  20.365 23.856 21.516 23.88 ;
     RECT  20.365 23.88 21.564 23.952 ;
     RECT  20.365 23.952 21.516 23.976 ;
     RECT  20.365 23.976 21.564 24.048 ;
     RECT  20.365 24.048 21.516 24.072 ;
     RECT  20.365 24.072 21.564 24.144 ;
     RECT  20.365 24.144 21.516 24.168 ;
     RECT  20.365 24.168 21.564 24.24 ;
     RECT  20.365 24.24 21.516 24.264 ;
     RECT  20.365 24.264 21.564 24.336 ;
     RECT  20.365 24.336 21.516 24.36 ;
     RECT  20.365 24.36 21.564 24.432 ;
     RECT  20.365 24.432 21.516 24.456 ;
     RECT  20.365 24.456 21.564 24.528 ;
     RECT  20.365 24.528 21.516 24.552 ;
     RECT  20.365 24.552 21.564 24.624 ;
     RECT  20.365 24.624 21.516 24.648 ;
     RECT  20.365 24.648 21.564 24.72 ;
     RECT  20.365 24.72 21.516 24.744 ;
     RECT  20.365 24.744 21.564 24.816 ;
     RECT  20.365 24.816 21.516 24.84 ;
     RECT  20.365 24.84 21.564 24.912 ;
     RECT  20.365 24.912 21.516 24.936 ;
     RECT  20.365 24.936 21.564 25.008 ;
     RECT  20.365 25.008 21.516 25.032 ;
     RECT  20.365 25.032 21.564 25.104 ;
     RECT  20.365 25.104 21.516 25.128 ;
     RECT  20.365 25.128 21.564 25.2 ;
     RECT  20.365 25.2 21.516 25.224 ;
     RECT  20.365 25.224 21.564 25.296 ;
     RECT  20.365 25.296 21.516 25.32 ;
     RECT  20.365 25.32 21.564 25.392 ;
     RECT  20.365 25.392 21.516 25.416 ;
     RECT  20.365 25.416 21.564 25.488 ;
     RECT  20.365 25.488 21.516 25.512 ;
     RECT  20.365 25.512 21.564 25.584 ;
     RECT  20.365 25.584 21.516 25.608 ;
     RECT  20.365 25.608 21.564 25.68 ;
     RECT  20.365 25.68 21.516 25.704 ;
     RECT  20.365 25.704 21.564 25.776 ;
     RECT  20.365 25.776 21.516 25.8 ;
     RECT  20.365 25.8 21.564 25.872 ;
     RECT  20.365 25.872 21.516 25.896 ;
     RECT  20.365 25.896 21.564 25.968 ;
     RECT  20.365 25.968 21.516 25.992 ;
     RECT  20.365 25.992 21.564 26.064 ;
     RECT  20.365 26.064 21.516 26.088 ;
     RECT  20.365 26.088 21.564 26.16 ;
     RECT  20.365 26.16 21.516 26.184 ;
     RECT  20.365 26.184 21.564 26.256 ;
     RECT  20.365 26.256 21.516 26.28 ;
     RECT  20.365 26.28 21.564 26.352 ;
     RECT  20.365 26.352 21.516 26.376 ;
     RECT  20.365 26.376 21.564 26.448 ;
     RECT  20.365 26.448 21.516 26.472 ;
     RECT  20.365 26.472 21.564 26.544 ;
     RECT  20.365 26.544 21.516 26.568 ;
     RECT  20.365 26.568 21.564 26.64 ;
     RECT  20.365 26.64 21.516 26.664 ;
     RECT  20.365 26.664 21.564 26.736 ;
     RECT  20.365 26.736 21.516 26.76 ;
     RECT  20.365 26.76 21.564 26.832 ;
     RECT  20.365 26.832 21.516 26.856 ;
     RECT  20.365 26.856 21.564 26.928 ;
     RECT  20.365 26.928 21.516 26.952 ;
     RECT  20.365 26.952 21.564 27.024 ;
     RECT  20.365 27.024 21.516 27.048 ;
     RECT  20.365 27.048 21.564 27.12 ;
     RECT  20.365 27.12 21.516 27.144 ;
     RECT  20.365 27.144 21.564 27.216 ;
     RECT  20.365 27.216 21.516 27.24 ;
     RECT  20.365 27.24 21.564 27.312 ;
     RECT  20.365 27.312 21.516 27.336 ;
     RECT  20.365 27.336 21.564 27.408 ;
     RECT  20.365 27.408 21.516 27.432 ;
     RECT  20.365 27.432 21.564 27.504 ;
     RECT  20.365 27.504 21.516 27.528 ;
     RECT  20.365 27.528 21.564 27.6 ;
     RECT  20.365 27.6 21.516 27.624 ;
     RECT  20.365 27.624 21.564 27.696 ;
     RECT  20.365 27.696 21.516 27.72 ;
     RECT  20.365 27.72 21.564 27.792 ;
     RECT  20.365 27.792 21.516 27.816 ;
     RECT  20.365 27.816 21.564 27.888 ;
     RECT  20.365 27.888 21.516 27.912 ;
     RECT  20.365 27.912 21.564 27.984 ;
     RECT  20.365 27.984 21.516 28.008 ;
     RECT  20.365 28.008 21.564 28.08 ;
     RECT  20.365 28.08 21.516 28.104 ;
     RECT  20.365 28.104 21.564 28.176 ;
     RECT  20.365 28.176 21.516 28.2 ;
     RECT  20.365 28.2 21.564 28.272 ;
     RECT  20.365 28.272 21.516 28.296 ;
     RECT  20.365 28.296 21.564 28.368 ;
     RECT  20.365 28.368 21.516 28.392 ;
     RECT  20.365 28.392 21.564 28.464 ;
     RECT  20.365 28.464 21.516 28.488 ;
     RECT  20.365 28.488 21.564 28.56 ;
     RECT  20.365 28.56 21.516 28.584 ;
     RECT  20.365 28.584 21.564 28.656 ;
     RECT  20.365 28.656 21.516 28.68 ;
     RECT  20.365 28.68 21.564 28.752 ;
     RECT  20.365 28.752 21.516 28.776 ;
     RECT  20.365 28.776 21.564 28.848 ;
     RECT  20.365 28.848 21.516 28.872 ;
     RECT  20.365 28.872 21.564 28.944 ;
     RECT  20.365 28.944 21.516 28.968 ;
     RECT  20.365 28.968 21.564 29.04 ;
     RECT  20.365 29.04 21.516 29.064 ;
     RECT  20.365 29.064 21.564 29.136 ;
     RECT  20.365 29.136 21.516 29.16 ;
     RECT  20.365 29.16 21.564 29.232 ;
     RECT  20.365 29.232 21.516 29.256 ;
     RECT  20.365 29.256 21.564 29.328 ;
     RECT  20.365 29.328 21.516 29.352 ;
     RECT  20.365 29.352 21.564 29.424 ;
     RECT  20.365 29.424 21.516 29.448 ;
     RECT  20.365 29.448 21.564 29.52 ;
     RECT  20.365 29.52 21.516 29.544 ;
     RECT  20.365 29.544 21.564 29.616 ;
     RECT  20.365 29.616 21.516 29.64 ;
     RECT  20.365 29.64 21.564 29.712 ;
     RECT  20.365 29.712 21.516 29.736 ;
     RECT  20.365 29.736 21.564 29.808 ;
     RECT  20.365 29.808 21.516 29.832 ;
     RECT  20.365 29.832 21.564 29.904 ;
     RECT  20.365 29.904 21.516 29.928 ;
     RECT  20.365 29.928 21.564 30 ;
     RECT  20.365 30 21.516 30.024 ;
     RECT  20.365 30.024 21.564 30.096 ;
     RECT  20.365 30.096 21.516 30.12 ;
     RECT  20.365 30.12 21.564 30.192 ;
     RECT  20.365 30.192 21.516 30.216 ;
     RECT  20.365 30.216 21.564 30.288 ;
     RECT  20.365 30.288 21.516 30.312 ;
     RECT  20.365 30.312 21.564 30.384 ;
     RECT  20.365 30.384 21.516 30.408 ;
     RECT  20.365 30.408 21.564 30.48 ;
     RECT  20.365 30.48 21.516 30.504 ;
     RECT  20.365 30.504 21.564 30.576 ;
     RECT  20.365 30.576 21.516 30.6 ;
     RECT  20.365 30.6 21.564 30.672 ;
     RECT  20.365 30.672 21.516 30.696 ;
     RECT  20.365 30.696 21.564 30.768 ;
     RECT  20.365 30.768 21.516 30.792 ;
     RECT  20.365 30.792 21.564 30.864 ;
     RECT  20.365 30.864 21.516 30.888 ;
     RECT  20.365 30.888 21.564 30.96 ;
     RECT  20.365 30.96 21.516 30.984 ;
     RECT  20.365 30.984 21.564 31.056 ;
     RECT  20.365 31.056 21.516 31.08 ;
     RECT  20.365 31.08 21.564 31.152 ;
     RECT  20.365 31.152 21.516 31.176 ;
     RECT  20.365 31.176 21.564 31.248 ;
     RECT  20.365 31.248 21.516 31.272 ;
     RECT  20.365 31.272 21.564 31.344 ;
     RECT  20.365 31.344 21.516 31.368 ;
     RECT  20.365 31.368 21.564 31.44 ;
     RECT  20.365 31.44 21.516 31.464 ;
     RECT  20.365 31.464 21.564 31.536 ;
     RECT  20.365 31.536 21.516 31.56 ;
     RECT  20.365 31.56 21.564 31.632 ;
     RECT  20.365 31.632 21.516 31.656 ;
     RECT  20.365 31.656 21.564 31.728 ;
     RECT  20.365 31.728 21.516 31.752 ;
     RECT  20.365 31.752 21.564 31.824 ;
     RECT  20.365 31.824 21.516 31.848 ;
     RECT  20.365 31.848 21.564 31.92 ;
     RECT  20.365 31.92 21.516 31.944 ;
     RECT  20.365 31.944 21.564 32.016 ;
     RECT  20.365 32.016 21.516 32.04 ;
     RECT  20.365 32.04 21.564 32.112 ;
     RECT  20.365 32.112 21.516 32.136 ;
     RECT  20.365 32.136 21.564 32.208 ;
     RECT  20.365 32.208 21.516 32.232 ;
     RECT  20.365 32.232 21.564 32.304 ;
     RECT  20.365 32.304 21.516 32.328 ;
     RECT  20.365 32.328 21.564 32.4 ;
     RECT  20.365 32.4 21.516 32.424 ;
     RECT  20.365 32.424 21.564 32.496 ;
     RECT  20.365 32.496 21.516 32.52 ;
     RECT  20.365 32.52 21.564 32.592 ;
     RECT  20.365 32.592 21.516 32.616 ;
     RECT  20.365 32.616 21.564 32.688 ;
     RECT  20.365 32.688 21.516 32.712 ;
     RECT  20.365 32.712 21.564 32.784 ;
     RECT  20.365 32.784 21.516 32.808 ;
     RECT  20.365 32.808 21.564 32.88 ;
     RECT  20.365 32.88 21.516 32.904 ;
     RECT  20.365 32.904 21.564 32.976 ;
     RECT  20.365 32.976 21.516 33 ;
     RECT  20.365 33 21.564 33.072 ;
     RECT  20.365 33.072 21.516 33.096 ;
     RECT  20.365 33.096 21.564 33.168 ;
     RECT  20.365 33.168 21.516 33.192 ;
     RECT  20.365 33.192 21.564 33.264 ;
     RECT  20.365 33.264 21.516 33.288 ;
     RECT  20.365 33.288 21.564 33.36 ;
     RECT  20.365 33.36 21.516 33.384 ;
     RECT  20.365 33.384 21.564 33.456 ;
     RECT  20.365 33.456 21.516 33.48 ;
     RECT  20.365 33.48 21.564 33.552 ;
     RECT  20.365 33.552 21.516 33.576 ;
     RECT  20.365 33.576 21.564 33.648 ;
     RECT  20.365 33.648 21.516 33.672 ;
     RECT  20.365 33.672 21.564 33.744 ;
     RECT  20.365 33.744 21.516 33.768 ;
     RECT  20.365 33.768 21.564 33.84 ;
     RECT  20.365 33.84 21.516 33.864 ;
     RECT  20.365 33.864 21.564 33.936 ;
     RECT  20.365 33.936 21.516 33.96 ;
     RECT  20.365 33.96 21.564 34.032 ;
     RECT  20.365 34.032 21.516 34.056 ;
     RECT  20.365 34.056 21.564 34.128 ;
     RECT  20.365 34.128 21.516 34.152 ;
     RECT  20.365 34.152 21.564 34.224 ;
     RECT  20.365 34.224 21.516 34.248 ;
     RECT  20.365 34.248 21.564 34.32 ;
     RECT  20.365 34.32 21.516 34.344 ;
     RECT  20.365 34.344 21.564 34.416 ;
     RECT  20.365 34.416 21.516 34.44 ;
     RECT  20.365 34.44 21.564 34.512 ;
     RECT  20.365 34.512 21.516 34.536 ;
     RECT  20.365 34.536 21.564 34.608 ;
     RECT  20.365 34.608 21.516 34.632 ;
     RECT  20.365 34.632 21.564 34.704 ;
     RECT  20.365 34.704 21.516 34.728 ;
     RECT  20.365 34.728 21.564 34.8 ;
     RECT  20.365 34.8 21.516 34.824 ;
     RECT  20.365 34.824 21.564 34.896 ;
     RECT  20.365 34.896 21.516 34.92 ;
     RECT  20.365 34.92 21.564 34.992 ;
     RECT  20.365 34.992 21.516 35.016 ;
     RECT  20.365 35.016 21.564 35.088 ;
     RECT  20.365 35.088 21.516 35.112 ;
     RECT  20.365 35.112 21.564 35.184 ;
     RECT  20.365 35.184 21.516 35.208 ;
     RECT  20.365 35.208 21.564 35.28 ;
     RECT  20.365 35.28 21.516 35.304 ;
     RECT  20.365 35.304 21.564 35.376 ;
     RECT  20.365 35.376 21.516 35.4 ;
     RECT  20.365 35.4 21.564 35.472 ;
     RECT  20.365 35.472 21.516 35.496 ;
     RECT  20.365 35.496 21.564 35.568 ;
     RECT  20.365 35.568 21.516 35.592 ;
     RECT  20.365 35.592 21.564 35.664 ;
     RECT  20.365 35.664 21.516 35.688 ;
     RECT  20.365 35.688 21.564 35.76 ;
     RECT  20.365 35.76 21.516 35.784 ;
     RECT  20.365 35.784 21.564 35.856 ;
     RECT  20.365 35.856 21.516 35.88 ;
     RECT  20.365 35.88 21.564 35.952 ;
     RECT  20.365 35.952 21.516 35.976 ;
     RECT  20.365 35.976 21.564 36.048 ;
     RECT  20.365 36.048 21.516 36.072 ;
     RECT  20.365 36.072 21.564 36.144 ;
     RECT  20.365 36.144 21.516 36.168 ;
     RECT  20.365 36.168 21.564 36.24 ;
     RECT  20.365 36.24 21.516 36.264 ;
     RECT  20.365 36.264 21.564 36.336 ;
     RECT  20.365 36.336 21.516 36.36 ;
     RECT  20.365 36.36 21.564 36.432 ;
     RECT  20.365 36.432 21.516 36.456 ;
     RECT  20.365 36.456 21.564 36.528 ;
     RECT  20.365 36.528 21.516 36.552 ;
     RECT  20.365 36.552 21.564 36.624 ;
     RECT  20.365 36.624 21.516 36.648 ;
     RECT  20.365 36.648 21.564 36.72 ;
     RECT  20.365 36.72 21.516 36.744 ;
     RECT  20.365 36.744 21.564 36.816 ;
     RECT  20.365 36.816 21.516 36.84 ;
     RECT  20.365 36.84 21.564 36.912 ;
     RECT  20.365 36.912 21.516 36.936 ;
     RECT  20.365 36.936 21.564 37.008 ;
     RECT  20.365 37.008 21.516 37.032 ;
     RECT  20.365 37.032 21.564 37.104 ;
     RECT  20.365 37.104 21.516 37.128 ;
     RECT  20.365 37.128 21.564 37.2 ;
     RECT  20.365 37.2 21.516 37.224 ;
     RECT  20.365 37.224 21.564 37.296 ;
     RECT  20.365 37.296 21.516 37.32 ;
     RECT  20.365 37.32 21.564 37.392 ;
     RECT  20.365 37.392 21.516 37.416 ;
     RECT  20.365 37.416 21.564 37.488 ;
     RECT  20.365 37.488 21.516 37.512 ;
     RECT  20.365 37.512 21.564 37.584 ;
     RECT  20.365 37.584 21.516 37.608 ;
     RECT  20.365 37.608 21.564 37.68 ;
     RECT  20.365 37.68 21.516 37.704 ;
     RECT  20.365 37.704 21.564 37.776 ;
     RECT  20.365 37.776 21.516 37.8 ;
     RECT  20.365 37.8 21.564 37.872 ;
     RECT  20.365 37.872 21.516 37.896 ;
     RECT  20.365 37.896 21.564 37.968 ;
     RECT  20.365 37.968 21.516 37.992 ;
     RECT  20.365 37.992 21.564 38.064 ;
     RECT  20.365 38.064 21.516 38.088 ;
     RECT  20.365 38.088 21.564 38.16 ;
     RECT  20.365 38.16 21.516 38.184 ;
     RECT  20.365 38.184 21.564 38.256 ;
     RECT  20.365 38.256 21.516 38.28 ;
     RECT  20.365 38.28 21.564 39.12 ;
     RECT  20.365 39.12 21.516 39.144 ;
     RECT  20.365 39.144 21.564 39.216 ;
     RECT  20.365 39.216 21.516 39.24 ;
     RECT  20.365 39.24 21.564 39.312 ;
     RECT  20.365 39.312 21.516 39.336 ;
     RECT  20.365 39.336 21.564 39.408 ;
     RECT  20.365 39.408 21.516 39.432 ;
     RECT  20.365 39.432 21.564 39.504 ;
     RECT  20.365 39.504 21.516 39.528 ;
     RECT  20.365 39.528 21.564 39.6 ;
     RECT  20.365 39.6 21.516 39.624 ;
     RECT  20.365 39.624 21.564 39.696 ;
     RECT  20.365 39.696 21.516 39.72 ;
     RECT  20.365 39.72 21.564 39.792 ;
     RECT  20.365 39.792 21.516 39.816 ;
     RECT  20.365 39.816 21.564 39.888 ;
     RECT  20.365 39.888 21.516 39.912 ;
     RECT  20.365 39.912 21.564 39.984 ;
     RECT  20.365 39.984 21.516 40.008 ;
     RECT  20.365 40.008 21.564 40.08 ;
     RECT  20.365 40.08 21.516 40.104 ;
     RECT  20.365 40.104 21.564 40.176 ;
     RECT  20.365 40.176 21.516 40.2 ;
     RECT  20.365 40.2 21.564 40.272 ;
     RECT  20.365 40.272 21.516 40.296 ;
     RECT  20.365 40.296 21.564 40.368 ;
     RECT  20.365 40.368 21.516 40.392 ;
     RECT  20.365 40.392 21.564 40.464 ;
     RECT  20.365 40.464 21.516 40.488 ;
     RECT  20.365 40.488 21.564 40.56 ;
     RECT  20.365 40.56 21.516 40.584 ;
     RECT  20.365 40.584 21.564 40.656 ;
     RECT  20.365 40.656 21.516 40.68 ;
     RECT  20.365 40.68 21.564 40.752 ;
     RECT  20.365 40.752 21.516 40.776 ;
     RECT  20.365 40.776 21.564 40.848 ;
     RECT  20.365 40.848 21.516 40.872 ;
     RECT  20.365 40.872 21.564 40.944 ;
     RECT  20.365 40.944 21.516 40.968 ;
     RECT  20.365 40.968 21.564 41.04 ;
     RECT  20.365 41.04 21.516 41.064 ;
     RECT  20.365 41.064 21.564 41.136 ;
     RECT  20.365 41.136 21.516 41.16 ;
     RECT  20.365 41.16 21.564 41.232 ;
     RECT  20.365 41.232 21.516 41.256 ;
     RECT  20.365 41.256 21.564 41.328 ;
     RECT  20.365 41.328 21.516 41.352 ;
     RECT  20.365 41.352 21.564 41.424 ;
     RECT  20.365 41.424 21.516 41.448 ;
     RECT  20.365 41.448 21.564 41.52 ;
     RECT  20.365 41.52 21.516 41.544 ;
     RECT  20.365 41.544 21.564 41.616 ;
     RECT  20.365 41.616 21.516 41.64 ;
     RECT  20.365 41.64 21.564 41.712 ;
     RECT  20.365 41.712 21.516 41.736 ;
     RECT  20.365 41.736 21.564 41.808 ;
     RECT  20.365 41.808 21.516 41.832 ;
     RECT  20.365 41.832 21.564 41.904 ;
     RECT  20.365 41.904 21.516 41.928 ;
     RECT  20.365 41.928 21.564 42 ;
     RECT  20.365 42 21.516 42.024 ;
     RECT  20.365 42.024 21.564 42.096 ;
     RECT  20.365 42.096 21.516 42.12 ;
     RECT  20.365 42.12 21.564 42.192 ;
     RECT  20.365 42.192 21.516 42.216 ;
     RECT  20.365 42.216 21.564 42.288 ;
     RECT  20.365 42.288 21.516 42.312 ;
     RECT  20.365 42.312 21.564 42.384 ;
     RECT  20.365 42.384 21.516 42.408 ;
     RECT  20.365 42.408 21.564 42.48 ;
     RECT  20.365 42.48 21.516 42.504 ;
     RECT  20.365 42.504 21.564 42.576 ;
     RECT  20.365 42.576 21.516 42.6 ;
     RECT  20.365 42.6 21.564 42.672 ;
     RECT  20.365 42.672 21.516 42.696 ;
     RECT  20.365 42.696 21.564 42.768 ;
     RECT  20.365 42.768 21.516 42.792 ;
     RECT  20.365 42.792 21.564 42.864 ;
     RECT  20.365 42.864 21.516 42.888 ;
     RECT  20.365 42.888 21.564 42.96 ;
     RECT  20.365 42.96 21.516 42.984 ;
     RECT  20.365 42.984 21.564 43.056 ;
     RECT  20.365 43.056 21.516 43.08 ;
     RECT  20.365 43.08 21.564 43.152 ;
     RECT  20.365 43.152 21.516 43.176 ;
     RECT  20.365 43.176 21.564 43.248 ;
     RECT  20.365 43.248 21.516 43.272 ;
     RECT  20.365 43.272 21.564 43.344 ;
     RECT  20.365 43.344 21.516 43.368 ;
     RECT  20.365 43.368 21.564 43.44 ;
     RECT  20.365 43.44 21.516 43.464 ;
     RECT  20.365 43.464 21.564 43.536 ;
     RECT  20.365 43.536 21.516 43.56 ;
     RECT  20.365 43.56 21.564 43.632 ;
     RECT  20.365 43.632 21.516 43.656 ;
     RECT  20.365 43.656 21.564 43.728 ;
     RECT  20.365 43.728 21.516 43.752 ;
     RECT  20.365 43.752 21.564 43.824 ;
     RECT  20.365 43.824 21.516 43.848 ;
     RECT  20.365 43.848 21.564 43.92 ;
     RECT  20.365 43.92 21.516 43.944 ;
     RECT  20.365 43.944 21.564 44.016 ;
     RECT  20.365 44.016 21.516 44.04 ;
     RECT  20.365 44.04 21.564 44.112 ;
     RECT  20.365 44.112 21.516 44.136 ;
     RECT  20.365 44.136 21.564 44.208 ;
     RECT  20.365 44.208 21.516 44.232 ;
     RECT  20.365 44.232 21.564 44.304 ;
     RECT  20.365 44.304 21.516 44.328 ;
     RECT  20.365 44.328 21.564 44.4 ;
     RECT  20.365 44.4 21.516 44.424 ;
     RECT  20.365 44.424 21.564 44.496 ;
     RECT  20.365 44.496 21.516 44.52 ;
     RECT  20.365 44.52 21.564 44.592 ;
     RECT  20.365 44.592 21.516 44.616 ;
     RECT  20.365 44.616 21.564 44.688 ;
     RECT  20.365 44.688 21.516 44.712 ;
     RECT  20.365 44.712 21.564 44.784 ;
     RECT  20.365 44.784 21.516 44.808 ;
     RECT  20.365 44.808 21.564 44.88 ;
     RECT  20.365 44.88 21.516 44.904 ;
     RECT  20.365 44.904 21.564 44.976 ;
     RECT  20.365 44.976 21.516 45 ;
     RECT  20.365 45 21.564 45.072 ;
     RECT  20.365 45.072 21.516 45.096 ;
     RECT  20.365 45.096 21.564 45.168 ;
     RECT  20.365 45.168 21.516 45.192 ;
     RECT  20.365 45.192 21.564 45.264 ;
     RECT  20.365 45.264 21.516 45.288 ;
     RECT  20.365 45.288 21.564 45.36 ;
     RECT  20.365 45.36 21.516 45.384 ;
     RECT  20.365 45.384 21.564 45.456 ;
     RECT  20.365 45.456 21.516 45.48 ;
     RECT  20.365 45.48 21.564 45.552 ;
     RECT  20.365 45.552 21.516 45.576 ;
     RECT  20.365 45.576 21.564 45.648 ;
     RECT  20.365 45.648 21.516 45.672 ;
     RECT  20.365 45.672 21.564 45.744 ;
     RECT  20.365 45.744 21.516 45.768 ;
     RECT  20.365 45.768 21.564 45.84 ;
     RECT  20.365 45.84 21.516 45.864 ;
     RECT  20.365 45.864 21.564 45.936 ;
     RECT  20.365 45.936 21.516 45.96 ;
     RECT  20.365 45.96 21.564 46.032 ;
     RECT  20.365 46.032 21.516 46.056 ;
     RECT  20.365 46.056 21.564 46.128 ;
     RECT  20.365 46.128 21.516 46.152 ;
     RECT  20.365 46.152 21.564 46.224 ;
     RECT  20.365 46.224 21.516 46.248 ;
     RECT  20.365 46.248 21.564 46.32 ;
     RECT  20.365 46.32 21.516 46.344 ;
     RECT  20.365 46.344 21.564 46.416 ;
     RECT  20.365 46.416 21.516 46.44 ;
     RECT  20.365 46.44 21.564 46.512 ;
     RECT  20.365 46.512 21.516 46.536 ;
     RECT  20.365 46.536 21.564 46.608 ;
     RECT  20.365 46.608 21.516 46.632 ;
     RECT  20.365 46.632 21.564 46.704 ;
     RECT  20.365 46.704 21.516 46.728 ;
     RECT  20.365 46.728 21.564 46.8 ;
     RECT  20.365 46.8 21.516 46.824 ;
     RECT  20.365 46.824 21.564 46.896 ;
     RECT  20.365 46.896 21.516 46.92 ;
     RECT  20.365 46.92 21.564 46.992 ;
     RECT  20.365 46.992 21.516 47.016 ;
     RECT  20.365 47.016 21.564 47.088 ;
     RECT  20.365 47.088 21.516 47.112 ;
     RECT  20.365 47.112 21.564 47.184 ;
     RECT  20.365 47.184 21.516 47.208 ;
     RECT  20.365 47.208 21.564 47.28 ;
     RECT  20.365 47.28 21.516 47.304 ;
     RECT  20.365 47.304 21.564 47.376 ;
     RECT  20.365 47.376 21.516 47.4 ;
     RECT  20.365 47.4 21.564 47.472 ;
     RECT  20.365 47.472 21.516 47.496 ;
     RECT  20.365 47.496 21.564 47.568 ;
     RECT  20.365 47.568 21.516 47.592 ;
     RECT  20.365 47.592 21.564 47.664 ;
     RECT  20.365 47.664 21.516 47.688 ;
     RECT  20.365 47.688 21.564 47.76 ;
     RECT  20.365 47.76 21.516 47.784 ;
     RECT  20.365 47.784 21.564 47.856 ;
     RECT  20.365 47.856 21.516 47.88 ;
     RECT  20.365 47.88 21.564 47.952 ;
     RECT  20.365 47.952 21.516 47.976 ;
     RECT  20.365 47.976 21.564 48.048 ;
     RECT  20.365 48.048 21.516 48.072 ;
     RECT  20.365 48.072 21.564 48.144 ;
     RECT  20.365 48.144 21.516 48.168 ;
     RECT  20.365 48.168 21.564 48.24 ;
     RECT  20.365 48.24 21.516 48.264 ;
     RECT  20.365 48.264 21.564 48.336 ;
     RECT  20.365 48.336 21.516 48.36 ;
     RECT  20.365 48.36 21.564 48.432 ;
     RECT  20.365 48.432 21.516 48.456 ;
     RECT  20.365 48.456 21.564 48.528 ;
     RECT  20.365 48.528 21.516 48.552 ;
     RECT  20.365 48.552 21.564 48.624 ;
     RECT  20.365 48.624 21.516 48.648 ;
     RECT  20.365 48.648 21.564 48.72 ;
     RECT  20.365 48.72 21.516 48.744 ;
     RECT  20.365 48.744 21.564 48.816 ;
     RECT  20.365 48.816 21.516 48.84 ;
     RECT  20.365 48.84 21.564 48.912 ;
     RECT  20.365 48.912 21.516 48.936 ;
     RECT  20.365 48.936 21.564 49.008 ;
     RECT  20.365 49.008 21.516 49.032 ;
     RECT  20.365 49.032 21.564 49.104 ;
     RECT  20.365 49.104 21.516 49.128 ;
     RECT  20.365 49.128 21.564 49.2 ;
     RECT  20.365 49.2 21.516 49.224 ;
     RECT  20.365 49.224 21.564 49.296 ;
     RECT  20.365 49.296 21.516 49.32 ;
     RECT  20.365 49.32 21.564 49.392 ;
     RECT  20.365 49.392 21.516 49.416 ;
     RECT  20.365 49.416 21.564 49.488 ;
     RECT  20.365 49.488 21.516 49.512 ;
     RECT  20.365 49.512 21.564 49.584 ;
     RECT  20.365 49.584 21.516 49.608 ;
     RECT  20.365 49.608 21.564 49.68 ;
     RECT  20.365 49.68 21.516 49.704 ;
     RECT  20.365 49.704 21.564 49.776 ;
     RECT  20.365 49.776 21.516 49.8 ;
     RECT  20.365 49.8 21.564 49.872 ;
     RECT  20.365 49.872 21.516 49.896 ;
     RECT  20.365 49.896 21.564 49.968 ;
     RECT  20.365 49.968 21.516 49.992 ;
     RECT  20.365 49.992 21.564 50.064 ;
     RECT  20.365 50.064 21.516 50.088 ;
     RECT  20.365 50.088 21.564 50.16 ;
     RECT  20.365 50.16 21.516 50.184 ;
     RECT  20.365 50.184 21.564 50.256 ;
     RECT  20.365 50.256 21.516 50.28 ;
     RECT  20.365 50.28 21.564 50.352 ;
     RECT  20.365 50.352 21.516 50.376 ;
     RECT  20.365 50.376 21.564 50.448 ;
     RECT  20.365 50.448 21.516 50.472 ;
     RECT  20.365 50.472 21.564 50.544 ;
     RECT  20.365 50.544 21.516 50.568 ;
     RECT  20.365 50.568 21.564 50.64 ;
     RECT  20.365 50.64 21.516 50.664 ;
     RECT  20.365 50.664 21.564 50.736 ;
     RECT  20.365 50.736 21.516 50.76 ;
     RECT  20.365 50.76 21.564 50.832 ;
     RECT  20.365 50.832 21.516 50.856 ;
     RECT  20.365 50.856 21.564 50.928 ;
     RECT  20.365 50.928 21.516 50.952 ;
     RECT  20.365 50.952 21.564 51.024 ;
     RECT  20.365 51.024 21.516 51.048 ;
     RECT  20.365 51.048 21.564 51.12 ;
     RECT  20.365 51.12 21.516 51.144 ;
     RECT  20.365 51.144 21.564 51.216 ;
     RECT  20.365 51.216 21.516 51.24 ;
     RECT  20.365 51.24 21.564 51.312 ;
     RECT  20.365 51.312 21.516 51.336 ;
     RECT  20.365 51.336 21.564 51.408 ;
     RECT  20.365 51.408 21.516 51.432 ;
     RECT  20.365 51.432 21.564 51.504 ;
     RECT  20.365 51.504 21.516 51.528 ;
     RECT  20.365 51.528 21.564 51.6 ;
     RECT  20.365 51.6 21.516 51.624 ;
     RECT  20.365 51.624 21.564 51.696 ;
     RECT  20.365 51.696 21.516 51.72 ;
     RECT  20.365 51.72 21.564 51.792 ;
     RECT  20.365 51.792 21.516 51.816 ;
     RECT  20.365 51.816 21.564 51.888 ;
     RECT  20.365 51.888 21.516 51.912 ;
     RECT  20.365 51.912 21.564 51.984 ;
     RECT  20.365 51.984 21.516 52.008 ;
     RECT  20.365 52.008 21.564 52.08 ;
     RECT  20.365 52.08 21.516 52.104 ;
     RECT  20.365 52.104 21.564 52.176 ;
     RECT  20.365 52.176 21.516 52.2 ;
     RECT  20.365 52.2 21.564 52.272 ;
     RECT  20.365 52.272 21.516 52.296 ;
     RECT  20.365 52.296 21.564 52.368 ;
     RECT  20.365 52.368 21.516 52.392 ;
     RECT  20.365 52.392 21.564 52.464 ;
     RECT  20.365 52.464 21.516 52.488 ;
     RECT  20.365 52.488 21.564 52.56 ;
     RECT  20.365 52.56 21.516 52.584 ;
     RECT  20.365 52.584 21.564 52.656 ;
     RECT  20.365 52.656 21.516 52.68 ;
     RECT  20.365 52.68 21.564 52.752 ;
     RECT  20.365 52.752 21.516 52.776 ;
     RECT  20.365 52.776 21.564 52.848 ;
     RECT  20.365 52.848 21.516 52.872 ;
     RECT  20.365 52.872 21.564 52.944 ;
     RECT  20.365 52.944 21.516 52.968 ;
     RECT  20.365 52.968 21.564 53.04 ;
     RECT  20.365 53.04 21.516 53.064 ;
     RECT  20.365 53.064 21.564 53.136 ;
     RECT  20.365 53.136 21.516 53.16 ;
     RECT  20.365 53.16 21.564 53.232 ;
     RECT  20.365 53.232 21.516 53.256 ;
     RECT  20.365 53.256 21.564 53.328 ;
     RECT  20.365 53.328 21.516 53.352 ;
     RECT  20.365 53.352 21.564 53.424 ;
     RECT  20.365 53.424 21.516 53.448 ;
     RECT  20.365 53.448 21.564 53.52 ;
     RECT  20.365 53.52 21.516 53.544 ;
     RECT  20.365 53.544 21.564 53.616 ;
     RECT  20.365 53.616 21.516 53.64 ;
     RECT  20.365 53.64 21.564 53.712 ;
     RECT  20.365 53.712 21.516 53.736 ;
     RECT  20.365 53.736 21.564 53.808 ;
     RECT  20.365 53.808 21.516 53.832 ;
     RECT  20.365 53.832 21.564 53.904 ;
     RECT  20.365 53.904 21.516 53.928 ;
     RECT  20.365 53.928 21.564 54 ;
     RECT  20.365 54 21.516 54.024 ;
     RECT  20.365 54.024 21.564 54.096 ;
     RECT  20.365 54.096 21.516 54.12 ;
     RECT  20.365 54.12 21.564 54.192 ;
     RECT  20.365 54.192 21.516 54.216 ;
     RECT  20.365 54.216 21.564 54.288 ;
     RECT  20.365 54.288 21.516 54.312 ;
     RECT  20.365 54.312 21.564 54.384 ;
     RECT  20.365 54.384 21.516 54.408 ;
     RECT  20.365 54.408 21.564 54.48 ;
     RECT  20.365 54.48 21.516 54.504 ;
     RECT  20.365 54.504 21.564 54.576 ;
     RECT  20.365 54.576 21.516 54.6 ;
     RECT  20.365 54.6 21.564 54.672 ;
     RECT  20.365 54.672 21.516 54.696 ;
     RECT  20.365 54.696 21.564 54.768 ;
     RECT  20.365 54.768 21.516 54.792 ;
     RECT  20.365 54.792 21.564 54.864 ;
     RECT  20.365 54.864 21.516 54.888 ;
     RECT  20.365 54.888 21.564 54.96 ;
     RECT  20.365 54.96 21.516 54.984 ;
     RECT  20.365 54.984 21.564 55.056 ;
     RECT  20.365 55.056 21.516 55.08 ;
     RECT  20.365 55.08 21.564 55.152 ;
     RECT  20.365 55.152 21.516 55.176 ;
     RECT  20.365 55.176 21.564 55.248 ;
     RECT  20.365 55.248 21.516 55.272 ;
     RECT  20.365 55.272 21.564 55.344 ;
     RECT  20.365 55.344 21.516 55.368 ;
     RECT  20.365 55.368 21.564 55.44 ;
     RECT  20.365 55.44 21.516 55.464 ;
     RECT  20.365 55.464 21.564 55.536 ;
     RECT  20.365 55.536 21.516 55.56 ;
     RECT  20.365 55.56 21.564 55.632 ;
     RECT  20.365 55.632 21.516 55.656 ;
     RECT  20.365 55.656 21.564 55.728 ;
     RECT  20.365 55.728 21.516 55.752 ;
     RECT  20.365 55.752 21.564 55.824 ;
     RECT  20.365 55.824 21.516 55.848 ;
     RECT  20.365 55.848 21.564 55.92 ;
     RECT  20.365 55.92 21.516 55.944 ;
     RECT  20.365 55.944 21.564 56.016 ;
     RECT  20.365 56.016 21.516 56.04 ;
     RECT  20.365 56.04 21.564 56.112 ;
     RECT  20.365 56.112 21.516 56.136 ;
     RECT  20.365 56.136 21.564 56.208 ;
     RECT  20.365 56.208 21.516 56.232 ;
     RECT  20.365 56.232 21.564 56.304 ;
     RECT  20.365 56.304 21.516 56.328 ;
     RECT  20.365 56.328 21.564 56.4 ;
     RECT  20.365 56.4 21.516 56.424 ;
     RECT  20.365 56.424 21.564 56.496 ;
     RECT  20.365 56.496 21.516 56.52 ;
     RECT  20.365 56.52 21.564 56.592 ;
     RECT  20.365 56.592 21.516 56.616 ;
     RECT  20.365 56.616 21.564 56.688 ;
     RECT  20.365 56.688 21.516 56.712 ;
     RECT  20.365 56.712 21.564 56.784 ;
     RECT  20.365 56.784 21.516 56.808 ;
     RECT  20.365 56.808 21.564 56.88 ;
     RECT  20.365 56.88 21.516 56.904 ;
     RECT  20.365 56.904 21.564 56.976 ;
     RECT  20.365 56.976 21.516 57 ;
     RECT  20.365 57 21.564 57.072 ;
     RECT  20.365 57.072 21.516 57.096 ;
     RECT  20.365 57.096 21.564 57.168 ;
     RECT  20.365 57.168 21.516 57.192 ;
     RECT  20.365 57.192 21.564 57.264 ;
     RECT  20.365 57.264 21.516 57.288 ;
     RECT  20.365 57.288 21.564 57.36 ;
     RECT  20.365 57.36 21.516 57.384 ;
     RECT  20.365 57.384 21.564 57.456 ;
     RECT  20.365 57.456 21.516 57.48 ;
     RECT  20.365 57.48 21.564 58.32 ;
     RECT  20.365 58.32 21.516 58.344 ;
     RECT  20.365 58.344 21.564 58.416 ;
     RECT  20.365 58.416 21.516 58.44 ;
     RECT  20.365 58.44 21.564 58.512 ;
     RECT  20.365 58.512 21.516 58.536 ;
     RECT  20.365 58.536 21.564 58.608 ;
     RECT  20.365 58.608 21.516 58.632 ;
     RECT  20.365 58.632 21.564 58.704 ;
     RECT  20.365 58.704 21.516 58.728 ;
     RECT  20.365 58.728 21.564 58.8 ;
     RECT  20.365 58.8 21.516 58.824 ;
     RECT  20.365 58.824 21.564 58.896 ;
     RECT  20.365 58.896 21.516 58.92 ;
     RECT  20.365 58.92 21.564 58.992 ;
     RECT  20.365 58.992 21.516 59.016 ;
     RECT  20.365 59.016 21.564 59.088 ;
     RECT  20.365 59.088 21.516 59.112 ;
     RECT  20.365 59.112 21.564 59.184 ;
     RECT  20.365 59.184 21.516 59.208 ;
     RECT  20.365 59.208 21.564 59.28 ;
     RECT  20.365 59.28 21.516 59.304 ;
     RECT  20.365 59.304 21.564 59.376 ;
     RECT  20.365 59.376 21.516 59.4 ;
     RECT  20.365 59.4 21.564 59.472 ;
     RECT  20.365 59.472 21.516 59.496 ;
     RECT  20.365 59.496 21.564 59.568 ;
     RECT  20.365 59.568 21.516 59.592 ;
     RECT  20.365 59.592 21.564 59.664 ;
     RECT  20.365 59.664 21.516 59.688 ;
     RECT  20.365 59.688 21.564 59.76 ;
     RECT  20.365 59.76 21.516 59.784 ;
     RECT  20.365 59.784 21.564 59.856 ;
     RECT  20.365 59.856 21.516 59.88 ;
     RECT  20.365 59.88 21.564 59.952 ;
     RECT  20.365 59.952 21.516 59.976 ;
     RECT  20.365 59.976 21.564 60.048 ;
     RECT  20.365 60.048 21.516 60.072 ;
     RECT  20.365 60.072 21.564 60.144 ;
     RECT  20.365 60.144 21.516 60.168 ;
     RECT  20.365 60.168 21.564 60.24 ;
     RECT  20.365 60.24 21.516 60.264 ;
     RECT  20.365 60.264 21.564 60.336 ;
     RECT  20.365 60.336 21.516 60.36 ;
     RECT  20.365 60.36 21.564 60.432 ;
     RECT  20.365 60.432 21.516 60.456 ;
     RECT  20.365 60.456 21.564 60.528 ;
     RECT  20.365 60.528 21.516 60.552 ;
     RECT  20.365 60.552 21.564 60.624 ;
     RECT  20.365 60.624 21.516 60.648 ;
     RECT  20.365 60.648 21.564 60.72 ;
     RECT  20.365 60.72 21.516 60.744 ;
     RECT  20.365 60.744 21.564 60.816 ;
     RECT  20.365 60.816 21.516 60.84 ;
     RECT  20.365 60.84 21.564 60.912 ;
     RECT  20.365 60.912 21.516 60.936 ;
     RECT  20.365 60.936 21.564 61.008 ;
     RECT  20.365 61.008 21.516 61.032 ;
     RECT  20.365 61.032 21.564 61.104 ;
     RECT  20.365 61.104 21.516 61.128 ;
     RECT  20.365 61.128 21.564 61.2 ;
     RECT  20.365 61.2 21.516 61.224 ;
     RECT  20.365 61.224 21.564 61.296 ;
     RECT  20.365 61.296 21.516 61.32 ;
     RECT  20.365 61.32 21.564 61.392 ;
     RECT  20.365 61.392 21.516 61.416 ;
     RECT  20.365 61.416 21.564 61.488 ;
     RECT  20.365 61.488 21.516 61.512 ;
     RECT  20.365 61.512 21.564 61.584 ;
     RECT  20.365 61.584 21.516 61.608 ;
     RECT  20.365 61.608 21.564 61.68 ;
     RECT  20.365 61.68 21.516 61.704 ;
     RECT  20.365 61.704 21.564 61.776 ;
     RECT  20.365 61.776 21.516 61.8 ;
     RECT  20.365 61.8 21.564 61.872 ;
     RECT  20.365 61.872 21.516 61.896 ;
     RECT  20.365 61.896 21.564 61.968 ;
     RECT  20.365 61.968 21.516 61.992 ;
     RECT  20.365 61.992 21.564 62.064 ;
     RECT  20.365 62.064 21.516 62.088 ;
     RECT  20.365 62.088 21.564 62.16 ;
     RECT  20.365 62.16 21.516 62.184 ;
     RECT  20.365 62.184 21.564 62.256 ;
     RECT  20.365 62.256 21.516 62.28 ;
     RECT  20.365 62.28 21.564 62.352 ;
     RECT  20.365 62.352 21.516 62.376 ;
     RECT  20.365 62.376 21.564 62.448 ;
     RECT  20.365 62.448 21.516 62.472 ;
     RECT  20.365 62.472 21.564 62.544 ;
     RECT  20.365 62.544 21.516 62.568 ;
     RECT  20.365 62.568 21.564 62.64 ;
     RECT  20.365 62.64 21.516 62.664 ;
     RECT  20.365 62.664 21.564 62.736 ;
     RECT  20.365 62.736 21.516 62.76 ;
     RECT  20.365 62.76 21.564 62.832 ;
     RECT  20.365 62.832 21.516 62.856 ;
    LAYER M5 ;
     RECT  11.88 0.016 11.952 0.084 ;
     RECT  11.856 0.084 11.976 0.611 ;
     RECT  11.856 0.611 11.88 2.005 ;
     RECT  11.856 2.005 12.84 2.137 ;
     RECT  2.4 2.137 2.52 2.151 ;
     RECT  5.1 2.137 5.22 2.151 ;
     RECT  7.8 2.137 7.92 2.151 ;
     RECT  10.5 2.137 10.62 2.151 ;
     RECT  11.856 2.137 13.32 2.151 ;
     RECT  15.9 2.137 16.02 2.151 ;
     RECT  18.6 2.137 18.72 2.151 ;
     RECT  5.1 2.151 5.412 2.197 ;
     RECT  18.6 2.151 18.912 2.245 ;
     RECT  17.904 2.245 18.912 2.485 ;
     RECT  5.1 2.197 5.976 2.533 ;
     RECT  10.5 2.151 10.812 2.773 ;
     RECT  11.856 2.151 13.512 2.773 ;
     RECT  0.192 2.581 0.216 2.867 ;
     RECT  10.5 2.773 13.512 3.109 ;
     RECT  5.1 2.533 6.696 3.397 ;
     RECT  7.8 2.151 8.112 3.397 ;
     RECT  10.224 3.109 13.512 3.541 ;
     RECT  14.496 2.053 14.616 3.541 ;
     RECT  10.224 3.541 14.616 3.971 ;
     RECT  2.4 2.151 2.712 4.117 ;
     RECT  2.4 4.117 2.904 4.307 ;
     RECT  10.5 3.971 14.616 4.501 ;
     RECT  15.9 2.151 16.212 4.501 ;
     RECT  3.984 5.749 4.008 5.891 ;
     RECT  0.144 4.741 0.168 6.035 ;
     RECT  1.248 5.845 1.272 6.083 ;
     RECT  5.1 3.397 8.112 6.853 ;
     RECT  5.1 6.853 9.096 7.093 ;
     RECT  5.1 7.093 9.144 7.283 ;
     RECT  0.144 7.717 0.168 7.907 ;
     RECT  0.144 8.917 0.168 10.019 ;
     RECT  9.264 10.357 9.288 10.931 ;
     RECT  2.4 4.307 2.712 11.509 ;
     RECT  0.144 11.509 0.168 11.795 ;
     RECT  2.4 11.509 2.808 11.941 ;
     RECT  2.4 11.941 3.672 12.179 ;
     RECT  5.1 7.283 8.232 12.421 ;
     RECT  1.2 12.517 1.224 12.803 ;
     RECT  2.4 12.179 2.808 12.803 ;
     RECT  2.4 12.803 2.712 12.997 ;
     RECT  2.304 12.997 2.712 13.139 ;
     RECT  3.888 12.421 8.232 13.235 ;
     RECT  4.368 13.235 8.232 13.715 ;
     RECT  4.512 13.715 8.232 14.243 ;
     RECT  0.144 14.965 0.168 16.307 ;
     RECT  2.4 13.139 2.712 16.453 ;
     RECT  5.1 14.243 8.232 16.501 ;
     RECT  5.1 16.501 8.28 16.549 ;
     RECT  2.304 16.453 2.712 16.835 ;
     RECT  5.1 16.549 9.096 16.931 ;
     RECT  5.1 16.931 9 17.123 ;
     RECT  2.4 16.835 2.712 17.125 ;
     RECT  2.4 17.125 2.904 17.315 ;
     RECT  5.1 17.123 8.376 17.363 ;
     RECT  2.4 17.315 2.712 18.277 ;
     RECT  2.4 18.277 2.904 18.709 ;
     RECT  3.936 18.277 3.96 18.851 ;
     RECT  0.144 17.413 0.168 18.901 ;
     RECT  2.304 18.709 2.904 18.901 ;
     RECT  2.304 18.901 3.672 18.947 ;
     RECT  0.144 18.901 0.216 19.091 ;
     RECT  10.5 4.501 16.212 19.333 ;
     RECT  5.1 17.363 8.232 19.621 ;
     RECT  5.1 19.621 9 19.765 ;
     RECT  10.224 19.333 16.212 19.765 ;
     RECT  0.144 19.091 0.168 19.859 ;
     RECT  2.4 18.947 3.672 19.859 ;
     RECT  4.08 19.909 4.104 20.051 ;
     RECT  2.4 19.859 2.712 20.869 ;
     RECT  2.4 20.869 2.856 21.011 ;
     RECT  0.144 21.685 0.168 21.971 ;
     RECT  5.1 19.765 16.212 22.259 ;
     RECT  2.4 21.011 2.712 23.077 ;
     RECT  5.1 22.259 9.384 23.317 ;
     RECT  5.1 23.317 9.432 23.605 ;
     RECT  10.5 22.259 16.212 23.605 ;
     RECT  2.304 23.077 2.712 23.891 ;
     RECT  0.144 24.565 0.168 24.755 ;
     RECT  2.4 23.891 2.712 25.141 ;
     RECT  2.4 25.141 2.808 25.283 ;
     RECT  0.144 27.445 0.168 27.731 ;
     RECT  2.4 25.283 2.712 28.117 ;
     RECT  2.4 28.117 2.904 29.173 ;
     RECT  2.4 29.173 3.672 29.363 ;
     RECT  0.144 30.373 0.168 30.659 ;
     RECT  21.408 30.757 21.432 31.235 ;
     RECT  2.4 29.363 2.712 31.285 ;
     RECT  2.4 31.285 4.056 31.427 ;
     RECT  3.696 31.427 4.056 31.619 ;
     RECT  2.4 31.427 2.712 31.717 ;
     RECT  3.696 31.619 3.72 31.859 ;
     RECT  0.144 33.109 0.168 33.587 ;
     RECT  2.304 31.717 2.712 33.635 ;
     RECT  2.4 33.635 2.712 34.309 ;
     RECT  2.4 34.309 3.72 34.691 ;
     RECT  5.1 23.605 16.212 35.077 ;
     RECT  4.464 35.077 16.212 35.219 ;
     RECT  2.4 34.691 2.904 36.179 ;
     RECT  0.144 35.317 0.168 36.419 ;
     RECT  2.4 36.179 2.808 36.419 ;
     RECT  2.4 36.419 2.712 37.429 ;
     RECT  0.24 36.901 0.264 37.571 ;
     RECT  0.144 37.909 0.168 38.195 ;
     RECT  5.1 35.219 16.212 38.437 ;
     RECT  17.328 2.485 18.912 38.437 ;
     RECT  2.4 37.429 2.904 38.483 ;
     RECT  3.984 38.533 4.008 38.867 ;
     RECT  3.84 40.309 3.864 40.451 ;
     RECT  2.4 38.483 2.712 40.693 ;
     RECT  2.4 40.693 2.808 40.883 ;
     RECT  0.144 40.069 0.168 41.027 ;
     RECT  2.4 40.883 2.712 41.893 ;
     RECT  2.4 41.893 2.904 42.469 ;
     RECT  2.304 42.469 2.904 43.283 ;
     RECT  0.288 43.525 0.312 43.859 ;
     RECT  2.304 43.283 2.856 44.485 ;
     RECT  2.256 44.485 2.856 44.581 ;
     RECT  2.256 44.581 2.904 44.675 ;
     RECT  2.4 44.675 2.904 44.915 ;
     RECT  5.1 38.437 18.912 46.357 ;
     RECT  4.128 46.357 18.912 46.979 ;
     RECT  0.144 45.781 0.168 47.891 ;
     RECT  2.4 44.915 2.712 48.373 ;
     RECT  2.4 48.373 3.672 48.515 ;
     RECT  1.248 48.133 1.272 48.661 ;
     RECT  1.152 48.661 1.272 48.995 ;
     RECT  1.248 48.995 1.272 49.187 ;
     RECT  0.144 49.333 0.168 49.523 ;
     RECT  5.1 46.979 18.912 49.811 ;
     RECT  5.1 49.811 13.512 50.243 ;
     RECT  5.1 50.243 5.412 50.341 ;
     RECT  7.056 50.243 13.512 50.435 ;
     RECT  14.496 49.811 18.912 50.579 ;
     RECT  0.144 51.061 0.168 51.251 ;
     RECT  1.248 51.109 1.272 51.251 ;
     RECT  2.4 48.515 2.712 51.253 ;
     RECT  4.272 50.341 5.412 51.253 ;
     RECT  2.4 51.253 5.412 51.395 ;
     RECT  3.696 51.395 5.412 51.539 ;
     RECT  3.696 51.539 3.96 52.163 ;
     RECT  3.696 52.163 3.912 52.259 ;
     RECT  3.888 52.259 3.912 52.355 ;
     RECT  2.4 51.395 2.712 52.597 ;
     RECT  4.992 51.539 5.412 52.643 ;
     RECT  2.4 52.597 2.808 52.835 ;
     RECT  0.144 52.741 0.168 53.027 ;
     RECT  2.4 52.835 2.712 53.797 ;
     RECT  2.4 53.797 3.336 54.133 ;
     RECT  7.2 50.435 13.512 54.179 ;
     RECT  2.4 54.133 3.624 54.661 ;
     RECT  1.152 54.133 1.176 54.707 ;
     RECT  2.4 54.661 3.816 54.803 ;
     RECT  2.4 54.803 3.624 54.851 ;
     RECT  5.1 52.643 5.412 55.813 ;
     RECT  0.144 55.429 0.168 56.005 ;
     RECT  7.2 54.179 9.528 56.149 ;
     RECT  10.5 54.179 13.512 56.149 ;
     RECT  0.144 56.005 0.312 56.435 ;
     RECT  2.4 54.851 3.336 56.485 ;
     RECT  4.8 55.813 5.412 56.485 ;
     RECT  0.144 56.435 0.168 56.819 ;
     RECT  7.2 56.149 13.512 58.259 ;
     RECT  7.2 58.259 11.352 59.315 ;
     RECT  7.2 59.315 8.232 59.555 ;
     RECT  2.4 56.485 5.412 59.653 ;
     RECT  2.4 59.653 5.544 59.843 ;
     RECT  9.504 59.315 11.352 59.843 ;
     RECT  9.504 59.843 9.528 59.891 ;
     RECT  0.144 59.557 0.168 60.613 ;
     RECT  7.2 59.555 8.112 60.757 ;
     RECT  0.144 60.613 0.264 60.851 ;
     RECT  0.24 60.851 0.264 60.899 ;
     RECT  6.768 60.757 8.112 60.901 ;
     RECT  6.768 60.901 9.096 61.091 ;
     RECT  10.5 59.843 11.352 61.139 ;
     RECT  2.4 59.843 5.412 61.189 ;
     RECT  7.104 61.091 9.096 61.283 ;
     RECT  7.104 61.283 8.712 61.763 ;
     RECT  14.496 50.579 14.52 61.907 ;
     RECT  15.9 50.579 18.912 62.099 ;
     RECT  15.9 62.099 16.92 62.195 ;
     RECT  17.904 62.099 18.912 62.195 ;
     RECT  7.104 61.763 8.112 62.243 ;
     RECT  2.304 61.189 5.412 62.627 ;
     RECT  2.304 62.627 2.712 62.649 ;
     RECT  3.792 62.627 5.412 62.649 ;
     RECT  7.8 62.243 8.112 62.649 ;
     RECT  10.5 61.139 10.812 62.649 ;
     RECT  13.2 58.259 13.512 62.649 ;
     RECT  15.9 62.195 16.212 62.649 ;
     RECT  18.6 62.195 18.912 62.649 ;
     RECT  2.304 62.649 2.52 62.663 ;
     RECT  3.792 62.649 5.22 62.663 ;
     RECT  7.8 62.649 7.92 62.663 ;
     RECT  10.5 62.649 10.62 62.663 ;
     RECT  13.2 62.649 13.32 62.663 ;
     RECT  15.9 62.649 16.02 62.663 ;
     RECT  18.6 62.649 18.72 62.663 ;
     RECT  2.304 62.663 2.328 62.867 ;
     RECT  3.792 62.663 4.968 62.867 ;
     RECT  3.792 62.867 3.816 62.915 ;
     RECT  4.848 62.867 4.968 63.059 ;
     RECT  4.944 63.059 4.968 63.203 ;
     RECT  11.88 0.611 11.976 2.005 ;
     RECT  10.62 2.137 11.856 2.151 ;
     RECT  13.32 2.137 14.496 2.151 ;
     RECT  14.616 2.137 15.9 4.501 ;
     RECT  10.812 2.151 11.856 2.773 ;
     RECT  13.512 2.151 14.496 3.541 ;
     RECT  16.212 2.485 17.328 38.437 ;
     RECT  6.696 2.533 7.8 3.397 ;
     RECT  2.712 4.307 2.904 5.749 ;
     RECT  2.712 5.749 3.984 5.891 ;
     RECT  4.008 5.749 5.1 5.891 ;
     RECT  0.18 5.845 1.248 6.035 ;
     RECT  1.272 5.845 2.4 6.083 ;
     RECT  9.096 6.853 10.5 7.093 ;
     RECT  9.144 7.093 10.5 7.283 ;
     RECT  8.232 10.357 9.264 10.931 ;
     RECT  9.288 10.357 10.5 10.931 ;
     RECT  3.672 11.941 5.1 12.179 ;
     RECT  2.808 12.179 5.1 12.421 ;
     RECT  2.808 12.421 3.888 12.803 ;
     RECT  1.224 12.517 2.4 12.803 ;
     RECT  2.304 12.803 2.4 12.997 ;
     RECT  2.712 12.803 3.888 13.235 ;
     RECT  9.096 16.549 10.5 16.931 ;
     RECT  9 16.931 10.5 17.123 ;
     RECT  2.712 17.315 2.904 18.277 ;
     RECT  2.904 18.277 3.936 18.851 ;
     RECT  3.96 18.277 5.1 18.851 ;
     RECT  2.904 18.851 5.1 18.901 ;
     RECT  3.672 18.901 5.1 19.859 ;
     RECT  9 19.621 10.224 19.765 ;
     RECT  2.712 19.859 5.1 19.909 ;
     RECT  2.712 19.909 4.08 20.051 ;
     RECT  4.104 19.909 5.1 20.051 ;
     RECT  2.712 20.051 2.856 20.869 ;
     RECT  9.384 22.259 10.5 23.317 ;
     RECT  9.432 23.317 10.5 23.605 ;
     RECT  3.672 29.173 5.1 29.363 ;
     RECT  4.056 31.285 5.1 31.619 ;
     RECT  2.712 31.427 3.696 31.859 ;
     RECT  3.72 31.619 5.1 31.859 ;
     RECT  3.72 34.309 5.1 34.691 ;
     RECT  4.464 34.691 5.1 35.077 ;
     RECT  2.808 36.179 2.904 36.419 ;
     RECT  2.712 36.419 2.904 37.429 ;
     RECT  2.712 38.483 2.904 38.533 ;
     RECT  2.712 38.533 3.984 38.867 ;
     RECT  4.008 38.533 5.1 38.867 ;
     RECT  2.712 38.867 5.1 40.309 ;
     RECT  2.712 40.309 3.84 40.451 ;
     RECT  3.864 40.309 5.1 40.451 ;
     RECT  2.712 40.451 2.904 40.693 ;
     RECT  2.808 40.693 2.904 40.883 ;
     RECT  2.712 40.883 2.904 41.893 ;
     RECT  2.856 43.283 2.904 44.581 ;
     RECT  2.712 44.915 2.904 46.357 ;
     RECT  2.712 46.357 4.128 46.979 ;
     RECT  2.712 46.979 5.1 48.373 ;
     RECT  1.272 48.133 2.4 49.187 ;
     RECT  3.672 48.373 5.1 48.515 ;
     RECT  13.512 49.811 14.496 61.907 ;
     RECT  14.52 50.579 15.9 61.907 ;
     RECT  0.18 51.109 1.248 51.251 ;
     RECT  1.272 51.109 2.4 51.251 ;
     RECT  2.712 51.395 3.696 52.259 ;
     RECT  3.96 51.539 4.992 52.163 ;
     RECT  3.912 52.163 4.992 52.355 ;
     RECT  2.712 52.259 3.888 52.355 ;
     RECT  2.712 52.355 3.336 52.597 ;
     RECT  2.808 52.597 3.336 52.835 ;
     RECT  4.992 52.643 5.1 54.133 ;
     RECT  2.712 52.835 3.336 53.797 ;
     RECT  1.176 54.133 2.4 54.707 ;
     RECT  3.624 54.133 5.1 54.661 ;
     RECT  9.528 54.179 10.5 56.149 ;
     RECT  3.816 54.661 5.1 54.803 ;
     RECT  3.624 54.803 5.1 54.851 ;
     RECT  3.336 54.851 5.1 55.813 ;
     RECT  3.336 55.813 4.8 56.485 ;
     RECT  8.232 59.315 9.504 59.555 ;
     RECT  8.112 59.555 9.504 59.891 ;
     RECT  5.412 59.843 5.544 60.757 ;
     RECT  9.528 59.843 10.5 59.891 ;
     RECT  8.112 59.891 10.5 60.901 ;
     RECT  5.412 60.757 6.768 61.091 ;
     RECT  9.096 60.901 10.5 61.283 ;
     RECT  16.92 62.099 17.904 62.195 ;
     RECT  2.712 62.627 3.792 62.649 ;
     RECT  2.52 62.649 3.792 62.663 ;
     RECT  2.328 62.663 3.792 62.867 ;
     RECT  3.816 62.867 4.848 62.915 ;
  END
END hbfd_rly_624_EW_rr
END LIBRARY
